          <field>
            <name>DLYM1L</name>
            <bitOffset>0</bitOffset>
            <bitWidth>3</bitWidth>
          </field>
          <field>
            <name>DLYM1R</name>
            <bitOffset>4</bitOffset>
            <bitWidth>3</bitWidth>
          </field>
          <field>
            <name>DLYM2L</name>
            <bitOffset>8</bitOffset>
            <bitWidth>3</bitWidth>
          </field>
          <field>
            <name>DLYM2R</name>
            <bitOffset>12</bitOffset>
            <bitWidth>3</bitWidth>
          </field>
          <field>
            <name>DLYM3L</name>
            <bitOffset>16</bitOffset>
            <bitWidth>3</bitWidth>
          </field>
          <field>
            <name>DLYM3R</name>
            <bitOffset>20</bitOffset>
            <bitWidth>3</bitWidth>
          </field>
          <field>
            <name>DLYM4L</name>
            <bitOffset>24</bitOffset>
            <bitWidth>3</bitWidth>
          </field>
          <field>
            <name>DLYM4R</name>
            <bitOffset>28</bitOffset>
            <bitWidth>3</bitWidth>
          </field>
        </fields>
      </register>
      <register>
        <name>IMRB</name>
        <addressOffset>0x4c</addressOffset>
        <size>0x20</size>
      </register>
      <register>
        <name>IMRB</name>
        <addressOffset>0x4c</addressOffset>
        <size>0x20</size>
      </register>
      <register>
        <name>CLRFRA</name>
        <addressOffset>0x58</addressOffset>
        <size>0x20</size>
      </register>
      <register>
        <name>CLRFRA</name>
        <addressOffset>0x58</addressOffset>
        <size>0x20</size>
      </register>
      <register>
        <name>SRB</name>
        <addressOffset>0x60</addressOffset>
        <size>0x20</size>
      </register>
      <register>
        <name>SRB</name>
        <addressOffset>0x60</addressOffset>
        <size>0x20</size>
      </register>
      <register>
        <name>DRA</name>
        <addressOffset>0x74</addressOffset>
        <size>0x20</size>
      </register>
      <register>
        <name>DRA</name>
        <addressOffset>0x74</addressOffset>
        <size>0x20</size>
      </register>
      <register>
        <name>CLRFRB</name>
        <addressOffset>0x78</addressOffset>
        <size>0x20</size>
      </register>
      <register>
        <name>CLRFRB</name>
        <addressOffset>0x78</addressOffset>
        <size>0x20</size>
      </register>
      <register>
        <name>DRB</name>
        <addressOffset>0x94</addressOffset>
        <size>0x20</size>
      </register>
      <register>
        <name>DRB</name>
        <addressOffset>0x94</addressOffset>
        <size>0x20</size>
      </register>
    </peripheral>
    <peripheral>
      <name>DFSDM1</name>
      <baseAddress>0x40016000</baseAddress>
      <register>
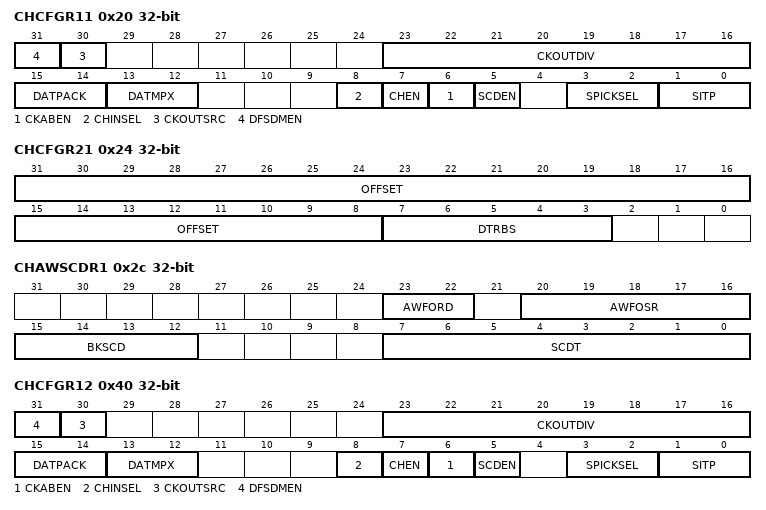
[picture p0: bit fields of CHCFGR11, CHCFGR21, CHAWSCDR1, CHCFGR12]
        <name>CHCFGR11</name>
        <addressOffset>0x20</addressOffset>
        <size>0x20</size>
        <fields>
          <field>
            <name>SITP</name>
            <bitOffset>0</bitOffset>
            <bitWidth>2</bitWidth>
          </field>
          <field>
            <name>SPICKSEL</name>
            <bitOffset>2</bitOffset>
            <bitWidth>2</bitWidth>
          </field>
          <field>
            <name>SCDEN</name>
            <bitOffset>5</bitOffset>
            <bitWidth>1</bitWidth>
          </field>
          <field>
            <name>CKABEN</name>
            <bitOffset>6</bitOffset>
            <bitWidth>1</bitWidth>
          </field>
          <field>
            <name>CHEN</name>
            <bitOffset>7</bitOffset>
            <bitWidth>1</bitWidth>
          </field>
          <field>
            <name>CHINSEL</name>
            <bitOffset>8</bitOffset>
            <bitWidth>1</bitWidth>
          </field>
          <field>
            <name>DATMPX</name>
            <bitOffset>12</bitOffset>
            <bitWidth>2</bitWidth>
          </field>
          <field>
            <name>DATPACK</name>
            <bitOffset>14</bitOffset>
            <bitWidth>2</bitWidth>
          </field>
          <field>
            <name>CKOUTDIV</name>
            <bitOffset>16</bitOffset>
            <bitWidth>8</bitWidth>
          </field>
          <field>
            <name>CKOUTSRC</name>
            <bitOffset>30</bitOffset>
            <bitWidth>1</bitWidth>
          </field>
          <field>
            <name>DFSDMEN</name>
            <bitOffset>31</bitOffset>
            <bitWidth>1</bitWidth>
          </field>
        </fields>
      </register>
      <register>
        <name>CHCFGR21</name>
        <addressOffset>0x24</addressOffset>
        <size>0x20</size>
        <fields>
          <field>
            <name>DTRBS</name>
            <bitOffset>3</bitOffset>
            <bitWidth>5</bitWidth>
          </field>
          <field>
            <name>OFFSET</name>
            <bitOffset>8</bitOffset>
            <bitWidth>24</bitWidth>
          </field>
        </fields>
      </register>
      <register>
        <name>CHAWSCDR1</name>
        <addressOffset>0x2c</addressOffset>
        <size>0x20</size>
        <fields>
          <field>
            <name>SCDT</name>
            <bitOffset>0</bitOffset>
            <bitWidth>8</bitWidth>
          </field>
          <field>
            <name>BKSCD</name>
            <bitOffset>12</bitOffset>
            <bitWidth>4</bitWidth>
          </field>
          <field>
            <name>AWFOSR</name>
            <bitOffset>16</bitOffset>
            <bitWidth>5</bitWidth>
          </field>
          <field>
            <name>AWFORD</name>
            <bitOffset>22</bitOffset>
            <bitWidth>2</bitWidth>
          </field>
        </fields>
      </register>
      <register>
        <name>CHWDATAR1</name>
        <addressOffset>0x38</addressOffset>
        <size>0x20</size>
      </register>
      <register>
        <name>CHCFGR12</name>
        <addressOffset>0x40</addressOffset>
        <size>0x20</size>
        <fields>
          <field>
            <name>SITP</name>
            <bitOffset>0</bitOffset>
            <bitWidth>2</bitWidth>
          </field>
          <field>
            <name>SPICKSEL</name>
            <bitOffset>2</bitOffset>
            <bitWidth>2</bitWidth>
          </field>
          <field>
            <name>SCDEN</name>
            <bitOffset>5</bitOffset>
            <bitWidth>1</bitWidth>
          </field>
          <field>
            <name>CKABEN</name>
            <bitOffset>6</bitOffset>
            <bitWidth>1</bitWidth>
          </field>
          <field>
            <name>CHEN</name>
            <bitOffset>7</bitOffset>
            <bitWidth>1</bitWidth>
          </field>
          <field>
            <name>CHINSEL</name>
            <bitOffset>8</bitOffset>
            <bitWidth>1</bitWidth>
          </field>
          <field>
            <name>DATMPX</name>
            <bitOffset>12</bitOffset>
            <bitWidth>2</bitWidth>
          </field>
          <field>
            <name>DATPACK</name>
            <bitOffset>14</bitOffset>
            <bitWidth>2</bitWidth>
          </field>
          <field>
            <name>CKOUTDIV</name>
            <bitOffset>16</bitOffset>
            <bitWidth>8</bitWidth>
          </field>
          <field>
            <name>CKOUTSRC</name>
            <bitOffset>30</bitOffset>
            <bitWidth>1</bitWidth>
          </field>
          <field>
            <name>DFSDMEN</name>
            <bitOffset>31</bitOffset>
            <bitWidth>1</bitWidth>
          </field>
        </fields>
      </register>
      <register>
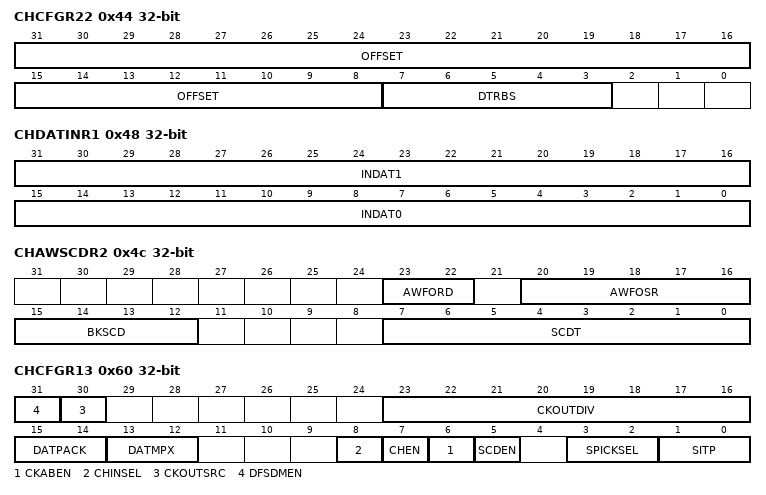
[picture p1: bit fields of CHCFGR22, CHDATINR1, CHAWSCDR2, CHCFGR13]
        <name>CHCFGR22</name>
        <addressOffset>0x44</addressOffset>
        <size>0x20</size>
        <fields>
          <field>
            <name>DTRBS</name>
            <bitOffset>3</bitOffset>
            <bitWidth>5</bitWidth>
          </field>
          <field>
            <name>OFFSET</name>
            <bitOffset>8</bitOffset>
            <bitWidth>24</bitWidth>
          </field>
        </fields>
      </register>
      <register>
        <name>CHDATINR1</name>
        <addressOffset>0x48</addressOffset>
        <size>0x20</size>
        <fields>
          <field>
            <name>INDAT0</name>
            <bitOffset>0</bitOffset>
            <bitWidth>16</bitWidth>
          </field>
          <field>
            <name>INDAT1</name>
            <bitOffset>16</bitOffset>
            <bitWidth>16</bitWidth>
          </field>
        </fields>
      </register>
      <register>
        <name>CHAWSCDR2</name>
        <addressOffset>0x4c</addressOffset>
        <size>0x20</size>
        <fields>
          <field>
            <name>SCDT</name>
            <bitOffset>0</bitOffset>
            <bitWidth>8</bitWidth>
          </field>
          <field>
            <name>BKSCD</name>
            <bitOffset>12</bitOffset>
            <bitWidth>4</bitWidth>
          </field>
          <field>
            <name>AWFOSR</name>
            <bitOffset>16</bitOffset>
            <bitWidth>5</bitWidth>
          </field>
          <field>
            <name>AWFORD</name>
            <bitOffset>22</bitOffset>
            <bitWidth>2</bitWidth>
          </field>
        </fields>
      </register>
      <register>
        <name>CHWDATAR2</name>
        <addressOffset>0x58</addressOffset>
        <size>0x20</size>
      </register>
      <register>
        <name>CHDLYR1</name>
        <addressOffset>0x5c</addressOffset>
        <size>0x20</size>
        <fields>
          <field>
            <name>PLSSKP</name>
            <bitOffset>0</bitOffset>
            <bitWidth>6</bitWidth>
          </field>
        </fields>
      </register>
      <register>
        <name>CHCFGR13</name>
        <addressOffset>0x60</addressOffset>
        <size>0x20</size>
        <fields>
          <field>
            <name>SITP</name>
            <bitOffset>0</bitOffset>
            <bitWidth>2</bitWidth>
          </field>
          <field>
            <name>SPICKSEL</name>
            <bitOffset>2</bitOffset>
            <bitWidth>2</bitWidth>
          </field>
          <field>
            <name>SCDEN</name>
            <bitOffset>5</bitOffset>
            <bitWidth>1</bitWidth>
          </field>
          <field>
            <name>CKABEN</name>
            <bitOffset>6</bitOffset>
            <bitWidth>1</bitWidth>
          </field>
          <field>
            <name>CHEN</name>
            <bitOffset>7</bitOffset>
            <bitWidth>1</bitWidth>
          </field>
          <field>
            <name>CHINSEL</name>
            <bitOffset>8</bitOffset>
            <bitWidth>1</bitWidth>
          </field>
          <field>
            <name>DATMPX</name>
            <bitOffset>12</bitOffset>
            <bitWidth>2</bitWidth>
          </field>
          <field>
            <name>DATPACK</name>
            <bitOffset>14</bitOffset>
            <bitWidth>2</bitWidth>
          </field>
          <field>
            <name>CKOUTDIV</name>
            <bitOffset>16</bitOffset>
            <bitWidth>8</bitWidth>
          </field>
          <field>
            <name>CKOUTSRC</name>
            <bitOffset>30</bitOffset>
            <bitWidth>1</bitWidth>
          </field>
          <field>
            <name>DFSDMEN</name>
            <bitOffset>31</bitOffset>
            <bitWidth>1</bitWidth>
          </field>
        </fields>
      </register>
      <register>
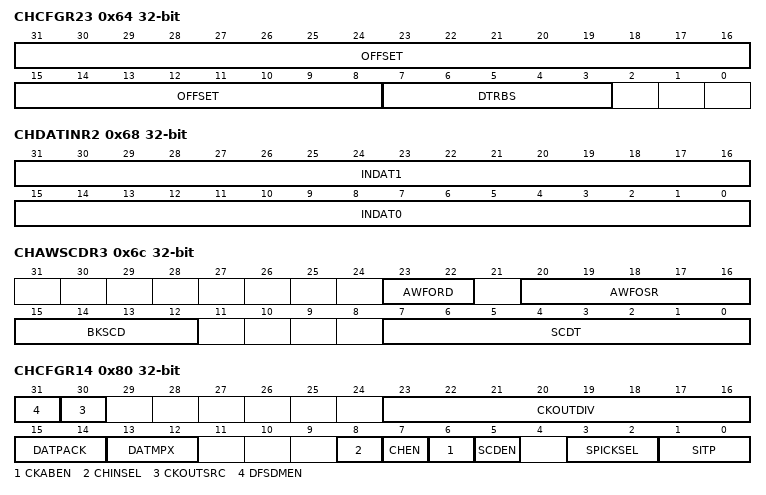
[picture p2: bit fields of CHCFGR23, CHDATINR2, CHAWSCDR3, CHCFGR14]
        <name>CHCFGR23</name>
        <addressOffset>0x64</addressOffset>
        <size>0x20</size>
        <fields>
          <field>
            <name>DTRBS</name>
            <bitOffset>3</bitOffset>
            <bitWidth>5</bitWidth>
          </field>
          <field>
            <name>OFFSET</name>
            <bitOffset>8</bitOffset>
            <bitWidth>24</bitWidth>
          </field>
        </fields>
      </register>
      <register>
        <name>CHDATINR2</name>
        <addressOffset>0x68</addressOffset>
        <size>0x20</size>
        <fields>
          <field>
            <name>INDAT0</name>
            <bitOffset>0</bitOffset>
            <bitWidth>16</bitWidth>
          </field>
          <field>
            <name>INDAT1</name>
            <bitOffset>16</bitOffset>
            <bitWidth>16</bitWidth>
          </field>
        </fields>
      </register>
      <register>
        <name>CHAWSCDR3</name>
        <addressOffset>0x6c</addressOffset>
        <size>0x20</size>
        <fields>
          <field>
            <name>SCDT</name>
            <bitOffset>0</bitOffset>
            <bitWidth>8</bitWidth>
          </field>
          <field>
            <name>BKSCD</name>
            <bitOffset>12</bitOffset>
            <bitWidth>4</bitWidth>
          </field>
          <field>
            <name>AWFOSR</name>
            <bitOffset>16</bitOffset>
            <bitWidth>5</bitWidth>
          </field>
          <field>
            <name>AWFORD</name>
            <bitOffset>22</bitOffset>
            <bitWidth>2</bitWidth>
          </field>
        </fields>
      </register>
      <register>
        <name>CHWDATAR3</name>
        <addressOffset>0x78</addressOffset>
        <size>0x20</size>
      </register>
      <register>
        <name>CHDLYR2</name>
        <addressOffset>0x7c</addressOffset>
        <size>0x20</size>
        <fields>
          <field>
            <name>PLSSKP</name>
            <bitOffset>0</bitOffset>
            <bitWidth>6</bitWidth>
          </field>
        </fields>
      </register>
      <register>
        <name>CHCFGR14</name>
        <addressOffset>0x80</addressOffset>
        <size>0x20</size>
        <fields>
          <field>
            <name>SITP</name>
            <bitOffset>0</bitOffset>
            <bitWidth>2</bitWidth>
          </field>
          <field>
            <name>SPICKSEL</name>
            <bitOffset>2</bitOffset>
            <bitWidth>2</bitWidth>
          </field>
          <field>
            <name>SCDEN</name>
            <bitOffset>5</bitOffset>
            <bitWidth>1</bitWidth>
          </field>
          <field>
            <name>CKABEN</name>
            <bitOffset>6</bitOffset>
            <bitWidth>1</bitWidth>
          </field>
          <field>
            <name>CHEN</name>
            <bitOffset>7</bitOffset>
            <bitWidth>1</bitWidth>
          </field>
          <field>
            <name>CHINSEL</name>
            <bitOffset>8</bitOffset>
            <bitWidth>1</bitWidth>
          </field>
          <field>
            <name>DATMPX</name>
            <bitOffset>12</bitOffset>
            <bitWidth>2</bitWidth>
          </field>
          <field>
            <name>DATPACK</name>
            <bitOffset>14</bitOffset>
            <bitWidth>2</bitWidth>
          </field>
          <field>
            <name>CKOUTDIV</name>
            <bitOffset>16</bitOffset>
            <bitWidth>8</bitWidth>
          </field>
          <field>
            <name>CKOUTSRC</name>
            <bitOffset>30</bitOffset>
            <bitWidth>1</bitWidth>
          </field>
          <field>
            <name>DFSDMEN</name>
            <bitOffset>31</bitOffset>
            <bitWidth>1</bitWidth>
          </field>
        </fields>
      </register>
      <register>
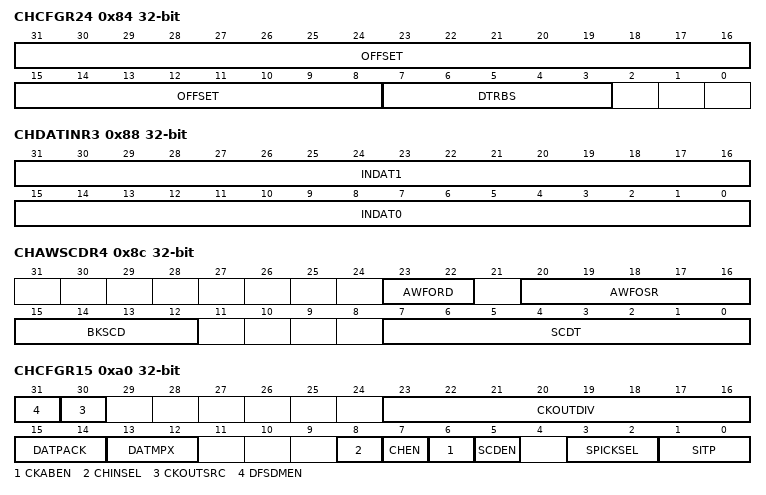
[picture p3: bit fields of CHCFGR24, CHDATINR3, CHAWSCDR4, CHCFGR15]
        <name>CHCFGR24</name>
        <addressOffset>0x84</addressOffset>
        <size>0x20</size>
        <fields>
          <field>
            <name>DTRBS</name>
            <bitOffset>3</bitOffset>
            <bitWidth>5</bitWidth>
          </field>
          <field>
            <name>OFFSET</name>
            <bitOffset>8</bitOffset>
            <bitWidth>24</bitWidth>
          </field>
        </fields>
      </register>
      <register>
        <name>CHDATINR3</name>
        <addressOffset>0x88</addressOffset>
        <size>0x20</size>
        <fields>
          <field>
            <name>INDAT0</name>
            <bitOffset>0</bitOffset>
            <bitWidth>16</bitWidth>
          </field>
          <field>
            <name>INDAT1</name>
            <bitOffset>16</bitOffset>
            <bitWidth>16</bitWidth>
          </field>
        </fields>
      </register>
      <register>
        <name>CHAWSCDR4</name>
        <addressOffset>0x8c</addressOffset>
        <size>0x20</size>
        <fields>
          <field>
            <name>SCDT</name>
            <bitOffset>0</bitOffset>
            <bitWidth>8</bitWidth>
          </field>
          <field>
            <name>BKSCD</name>
            <bitOffset>12</bitOffset>
            <bitWidth>4</bitWidth>
          </field>
          <field>
            <name>AWFOSR</name>
            <bitOffset>16</bitOffset>
            <bitWidth>5</bitWidth>
          </field>
          <field>
            <name>AWFORD</name>
            <bitOffset>22</bitOffset>
            <bitWidth>2</bitWidth>
          </field>
        </fields>
      </register>
      <register>
        <name>CHWDATAR4</name>
        <addressOffset>0x98</addressOffset>
        <size>0x20</size>
      </register>
      <register>
        <name>CHDLYR3</name>
        <addressOffset>0x9c</addressOffset>
        <size>0x20</size>
        <fields>
          <field>
            <name>PLSSKP</name>
            <bitOffset>0</bitOffset>
            <bitWidth>6</bitWidth>
          </field>
        </fields>
      </register>
      <register>
        <name>CHCFGR15</name>
        <addressOffset>0xa0</addressOffset>
        <size>0x20</size>
        <fields>
          <field>
            <name>SITP</name>
            <bitOffset>0</bitOffset>
            <bitWidth>2</bitWidth>
          </field>
          <field>
            <name>SPICKSEL</name>
            <bitOffset>2</bitOffset>
            <bitWidth>2</bitWidth>
          </field>
          <field>
            <name>SCDEN</name>
            <bitOffset>5</bitOffset>
            <bitWidth>1</bitWidth>
          </field>
          <field>
            <name>CKABEN</name>
            <bitOffset>6</bitOffset>
            <bitWidth>1</bitWidth>
          </field>
          <field>
            <name>CHEN</name>
            <bitOffset>7</bitOffset>
            <bitWidth>1</bitWidth>
          </field>
          <field>
            <name>CHINSEL</name>
            <bitOffset>8</bitOffset>
            <bitWidth>1</bitWidth>
          </field>
          <field>
            <name>DATMPX</name>
            <bitOffset>12</bitOffset>
            <bitWidth>2</bitWidth>
          </field>
          <field>
            <name>DATPACK</name>
            <bitOffset>14</bitOffset>
            <bitWidth>2</bitWidth>
          </field>
          <field>
            <name>CKOUTDIV</name>
            <bitOffset>16</bitOffset>
            <bitWidth>8</bitWidth>
          </field>
          <field>
            <name>CKOUTSRC</name>
            <bitOffset>30</bitOffset>
            <bitWidth>1</bitWidth>
          </field>
          <field>
            <name>DFSDMEN</name>
            <bitOffset>31</bitOffset>
            <bitWidth>1</bitWidth>
          </field>
        </fields>
      </register>
      <register>
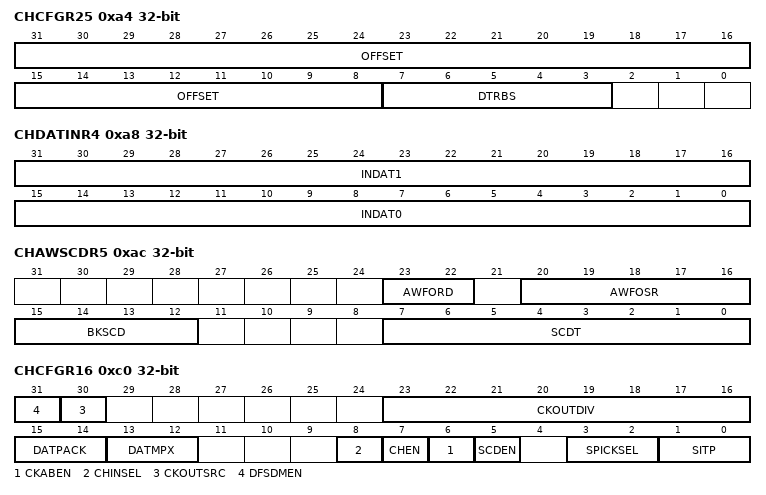
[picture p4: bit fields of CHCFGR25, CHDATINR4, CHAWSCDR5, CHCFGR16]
        <name>CHCFGR25</name>
        <addressOffset>0xa4</addressOffset>
        <size>0x20</size>
        <fields>
          <field>
            <name>DTRBS</name>
            <bitOffset>3</bitOffset>
            <bitWidth>5</bitWidth>
          </field>
          <field>
            <name>OFFSET</name>
            <bitOffset>8</bitOffset>
            <bitWidth>24</bitWidth>
          </field>
        </fields>
      </register>
      <register>
        <name>CHDATINR4</name>
        <addressOffset>0xa8</addressOffset>
        <size>0x20</size>
        <fields>
          <field>
            <name>INDAT0</name>
            <bitOffset>0</bitOffset>
            <bitWidth>16</bitWidth>
          </field>
          <field>
            <name>INDAT1</name>
            <bitOffset>16</bitOffset>
            <bitWidth>16</bitWidth>
          </field>
        </fields>
      </register>
      <register>
        <name>CHAWSCDR5</name>
        <addressOffset>0xac</addressOffset>
        <size>0x20</size>
        <fields>
          <field>
            <name>SCDT</name>
            <bitOffset>0</bitOffset>
            <bitWidth>8</bitWidth>
          </field>
          <field>
            <name>BKSCD</name>
            <bitOffset>12</bitOffset>
            <bitWidth>4</bitWidth>
          </field>
          <field>
            <name>AWFOSR</name>
            <bitOffset>16</bitOffset>
            <bitWidth>5</bitWidth>
          </field>
          <field>
            <name>AWFORD</name>
            <bitOffset>22</bitOffset>
            <bitWidth>2</bitWidth>
          </field>
        </fields>
      </register>
      <register>
        <name>CHWDATAR5</name>
        <addressOffset>0xb8</addressOffset>
        <size>0x20</size>
      </register>
      <register>
        <name>CHDLYR4</name>
        <addressOffset>0xbc</addressOffset>
        <size>0x20</size>
        <fields>
          <field>
            <name>PLSSKP</name>
            <bitOffset>0</bitOffset>
            <bitWidth>6</bitWidth>
          </field>
        </fields>
      </register>
      <register>
        <name>CHCFGR16</name>
        <addressOffset>0xc0</addressOffset>
        <size>0x20</size>
        <fields>
          <field>
            <name>SITP</name>
            <bitOffset>0</bitOffset>
            <bitWidth>2</bitWidth>
          </field>
          <field>
            <name>SPICKSEL</name>
            <bitOffset>2</bitOffset>
            <bitWidth>2</bitWidth>
          </field>
          <field>
            <name>SCDEN</name>
            <bitOffset>5</bitOffset>
            <bitWidth>1</bitWidth>
          </field>
          <field>
            <name>CKABEN</name>
            <bitOffset>6</bitOffset>
            <bitWidth>1</bitWidth>
          </field>
          <field>
            <name>CHEN</name>
            <bitOffset>7</bitOffset>
            <bitWidth>1</bitWidth>
          </field>
          <field>
            <name>CHINSEL</name>
            <bitOffset>8</bitOffset>
            <bitWidth>1</bitWidth>
          </field>
          <field>
            <name>DATMPX</name>
            <bitOffset>12</bitOffset>
            <bitWidth>2</bitWidth>
          </field>
          <field>
            <name>DATPACK</name>
            <bitOffset>14</bitOffset>
            <bitWidth>2</bitWidth>
          </field>
          <field>
            <name>CKOUTDIV</name>
            <bitOffset>16</bitOffset>
            <bitWidth>8</bitWidth>
          </field>
          <field>
            <name>CKOUTSRC</name>
            <bitOffset>30</bitOffset>
            <bitWidth>1</bitWidth>
          </field>
          <field>
            <name>DFSDMEN</name>
            <bitOffset>31</bitOffset>
            <bitWidth>1</bitWidth>
          </field>
        </fields>
      </register>
      <register>
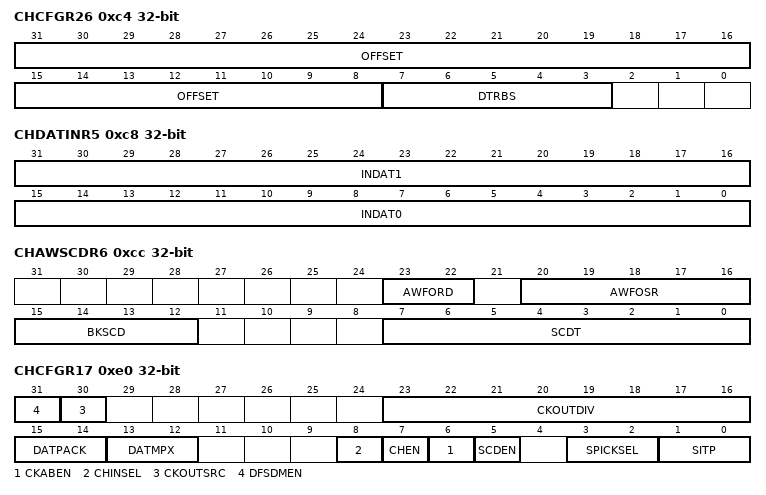
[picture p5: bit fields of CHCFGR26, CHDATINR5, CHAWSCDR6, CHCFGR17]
        <name>CHCFGR26</name>
        <addressOffset>0xc4</addressOffset>
        <size>0x20</size>
        <fields>
          <field>
            <name>DTRBS</name>
            <bitOffset>3</bitOffset>
            <bitWidth>5</bitWidth>
          </field>
          <field>
            <name>OFFSET</name>
            <bitOffset>8</bitOffset>
            <bitWidth>24</bitWidth>
          </field>
        </fields>
      </register>
      <register>
        <name>CHDATINR5</name>
        <addressOffset>0xc8</addressOffset>
        <size>0x20</size>
        <fields>
          <field>
            <name>INDAT0</name>
            <bitOffset>0</bitOffset>
            <bitWidth>16</bitWidth>
          </field>
          <field>
            <name>INDAT1</name>
            <bitOffset>16</bitOffset>
            <bitWidth>16</bitWidth>
          </field>
        </fields>
      </register>
      <register>
        <name>CHAWSCDR6</name>
        <addressOffset>0xcc</addressOffset>
        <size>0x20</size>
        <fields>
          <field>
            <name>SCDT</name>
            <bitOffset>0</bitOffset>
            <bitWidth>8</bitWidth>
          </field>
          <field>
            <name>BKSCD</name>
            <bitOffset>12</bitOffset>
            <bitWidth>4</bitWidth>
          </field>
          <field>
            <name>AWFOSR</name>
            <bitOffset>16</bitOffset>
            <bitWidth>5</bitWidth>
          </field>
          <field>
            <name>AWFORD</name>
            <bitOffset>22</bitOffset>
            <bitWidth>2</bitWidth>
          </field>
        </fields>
      </register>
      <register>
        <name>CHWDATAR6</name>
        <addressOffset>0xd8</addressOffset>
        <size>0x20</size>
      </register>
      <register>
        <name>CHDLYR5</name>
        <addressOffset>0xdc</addressOffset>
        <size>0x20</size>
        <fields>
          <field>
            <name>PLSSKP</name>
            <bitOffset>0</bitOffset>
            <bitWidth>6</bitWidth>
          </field>
        </fields>
      </register>
      <register>
        <name>CHCFGR17</name>
        <addressOffset>0xe0</addressOffset>
        <size>0x20</size>
        <fields>
          <field>
            <name>SITP</name>
            <bitOffset>0</bitOffset>
            <bitWidth>2</bitWidth>
          </field>
          <field>
            <name>SPICKSEL</name>
            <bitOffset>2</bitOffset>
            <bitWidth>2</bitWidth>
          </field>
          <field>
            <name>SCDEN</name>
            <bitOffset>5</bitOffset>
            <bitWidth>1</bitWidth>
          </field>
          <field>
            <name>CKABEN</name>
            <bitOffset>6</bitOffset>
            <bitWidth>1</bitWidth>
          </field>
          <field>
            <name>CHEN</name>
            <bitOffset>7</bitOffset>
            <bitWidth>1</bitWidth>
          </field>
          <field>
            <name>CHINSEL</name>
            <bitOffset>8</bitOffset>
            <bitWidth>1</bitWidth>
          </field>
          <field>
            <name>DATMPX</name>
            <bitOffset>12</bitOffset>
            <bitWidth>2</bitWidth>
          </field>
          <field>
            <name>DATPACK</name>
            <bitOffset>14</bitOffset>
            <bitWidth>2</bitWidth>
          </field>
          <field>
            <name>CKOUTDIV</name>
            <bitOffset>16</bitOffset>
            <bitWidth>8</bitWidth>
          </field>
          <field>
            <name>CKOUTSRC</name>
            <bitOffset>30</bitOffset>
            <bitWidth>1</bitWidth>
          </field>
          <field>
            <name>DFSDMEN</name>
            <bitOffset>31</bitOffset>
            <bitWidth>1</bitWidth>
          </field>
        </fields>
      </register>
      <register>
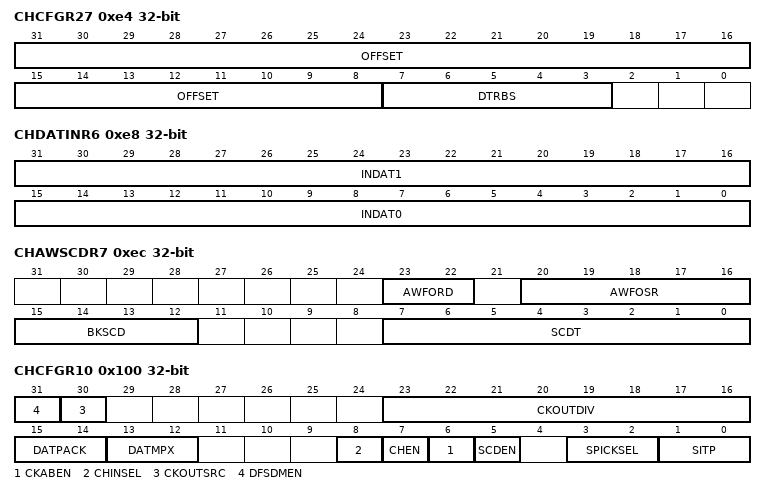
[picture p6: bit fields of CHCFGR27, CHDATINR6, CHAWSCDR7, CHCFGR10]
        <name>CHCFGR27</name>
        <addressOffset>0xe4</addressOffset>
        <size>0x20</size>
        <fields>
          <field>
            <name>DTRBS</name>
            <bitOffset>3</bitOffset>
            <bitWidth>5</bitWidth>
          </field>
          <field>
            <name>OFFSET</name>
            <bitOffset>8</bitOffset>
            <bitWidth>24</bitWidth>
          </field>
        </fields>
      </register>
      <register>
        <name>CHDATINR6</name>
        <addressOffset>0xe8</addressOffset>
        <size>0x20</size>
        <fields>
          <field>
            <name>INDAT0</name>
            <bitOffset>0</bitOffset>
            <bitWidth>16</bitWidth>
          </field>
          <field>
            <name>INDAT1</name>
            <bitOffset>16</bitOffset>
            <bitWidth>16</bitWidth>
          </field>
        </fields>
      </register>
      <register>
        <name>CHAWSCDR7</name>
        <addressOffset>0xec</addressOffset>
        <size>0x20</size>
        <fields>
          <field>
            <name>SCDT</name>
            <bitOffset>0</bitOffset>
            <bitWidth>8</bitWidth>
          </field>
          <field>
            <name>BKSCD</name>
            <bitOffset>12</bitOffset>
            <bitWidth>4</bitWidth>
          </field>
          <field>
            <name>AWFOSR</name>
            <bitOffset>16</bitOffset>
            <bitWidth>5</bitWidth>
          </field>
          <field>
            <name>AWFORD</name>
            <bitOffset>22</bitOffset>
            <bitWidth>2</bitWidth>
          </field>
        </fields>
      </register>
      <register>
        <name>CHWDATAR7</name>
        <addressOffset>0xf8</addressOffset>
        <size>0x20</size>
      </register>
      <register>
        <name>CHDLYR6</name>
        <addressOffset>0xfc</addressOffset>
        <size>0x20</size>
        <fields>
          <field>
            <name>PLSSKP</name>
            <bitOffset>0</bitOffset>
            <bitWidth>6</bitWidth>
          </field>
        </fields>
      </register>
      <register>
        <name>CHCFGR10</name>
        <addressOffset>0x100</addressOffset>
        <size>0x20</size>
        <fields>
          <field>
            <name>SITP</name>
            <bitOffset>0</bitOffset>
            <bitWidth>2</bitWidth>
          </field>
          <field>
            <name>SPICKSEL</name>
            <bitOffset>2</bitOffset>
            <bitWidth>2</bitWidth>
          </field>
          <field>
            <name>SCDEN</name>
            <bitOffset>5</bitOffset>
            <bitWidth>1</bitWidth>
          </field>
          <field>
            <name>CKABEN</name>
            <bitOffset>6</bitOffset>
            <bitWidth>1</bitWidth>
          </field>
          <field>
            <name>CHEN</name>
            <bitOffset>7</bitOffset>
            <bitWidth>1</bitWidth>
          </field>
          <field>
            <name>CHINSEL</name>
            <bitOffset>8</bitOffset>
            <bitWidth>1</bitWidth>
          </field>
          <field>
            <name>DATMPX</name>
            <bitOffset>12</bitOffset>
            <bitWidth>2</bitWidth>
          </field>
          <field>
            <name>DATPACK</name>
            <bitOffset>14</bitOffset>
            <bitWidth>2</bitWidth>
          </field>
          <field>
            <name>CKOUTDIV</name>
            <bitOffset>16</bitOffset>
            <bitWidth>8</bitWidth>
          </field>
          <field>
            <name>CKOUTSRC</name>
            <bitOffset>30</bitOffset>
            <bitWidth>1</bitWidth>
          </field>
          <field>
            <name>DFSDMEN</name>
            <bitOffset>31</bitOffset>
            <bitWidth>1</bitWidth>
          </field>
        </fields>
      </register>
      <register>
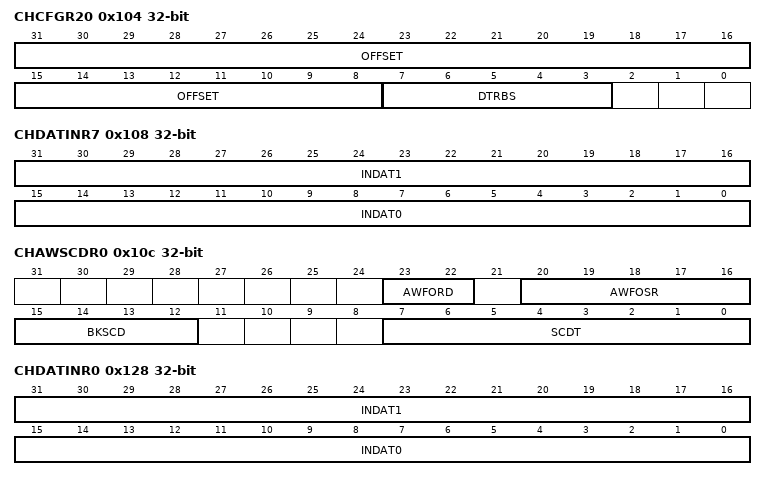
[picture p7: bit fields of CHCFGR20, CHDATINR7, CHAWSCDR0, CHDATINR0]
        <name>CHCFGR20</name>
        <addressOffset>0x104</addressOffset>
        <size>0x20</size>
        <fields>
          <field>
            <name>DTRBS</name>
            <bitOffset>3</bitOffset>
            <bitWidth>5</bitWidth>
          </field>
          <field>
            <name>OFFSET</name>
            <bitOffset>8</bitOffset>
            <bitWidth>24</bitWidth>
          </field>
        </fields>
      </register>
      <register>
        <name>CHDATINR7</name>
        <addressOffset>0x108</addressOffset>
        <size>0x20</size>
        <fields>
          <field>
            <name>INDAT0</name>
            <bitOffset>0</bitOffset>
            <bitWidth>16</bitWidth>
          </field>
          <field>
            <name>INDAT1</name>
            <bitOffset>16</bitOffset>
            <bitWidth>16</bitWidth>
          </field>
        </fields>
      </register>
      <register>
        <name>CHAWSCDR0</name>
        <addressOffset>0x10c</addressOffset>
        <size>0x20</size>
        <fields>
          <field>
            <name>SCDT</name>
            <bitOffset>0</bitOffset>
            <bitWidth>8</bitWidth>
          </field>
          <field>
            <name>BKSCD</name>
            <bitOffset>12</bitOffset>
            <bitWidth>4</bitWidth>
          </field>
          <field>
            <name>AWFOSR</name>
            <bitOffset>16</bitOffset>
            <bitWidth>5</bitWidth>
          </field>
          <field>
            <name>AWFORD</name>
            <bitOffset>22</bitOffset>
            <bitWidth>2</bitWidth>
          </field>
        </fields>
      </register>
      <register>
        <name>CHWDATAR0</name>
        <addressOffset>0x118</addressOffset>
        <size>0x20</size>
      </register>
      <register>
        <name>CHDLYR7</name>
        <addressOffset>0x11c</addressOffset>
        <size>0x20</size>
        <fields>
          <field>
            <name>PLSSKP</name>
            <bitOffset>0</bitOffset>
            <bitWidth>6</bitWidth>
          </field>
        </fields>
      </register>
      <register>
        <name>CHDATINR0</name>
        <addressOffset>0x128</addressOffset>
        <size>0x20</size>
        <fields>
          <field>
            <name>INDAT0</name>
            <bitOffset>0</bitOffset>
            <bitWidth>16</bitWidth>
          </field>
          <field>
            <name>INDAT1</name>
            <bitOffset>16</bitOffset>
            <bitWidth>16</bitWidth>
          </field>
        </fields>
      </register>
      <register>
        <name>CHDLYR0</name>
        <addressOffset>0x13c</addressOffset>
        <size>0x20</size>
        <fields>
          <field>
            <name>PLSSKP</name>
            <bitOffset>0</bitOffset>
            <bitWidth>6</bitWidth>
          </field>
        </fields>
      </register>
      <register>
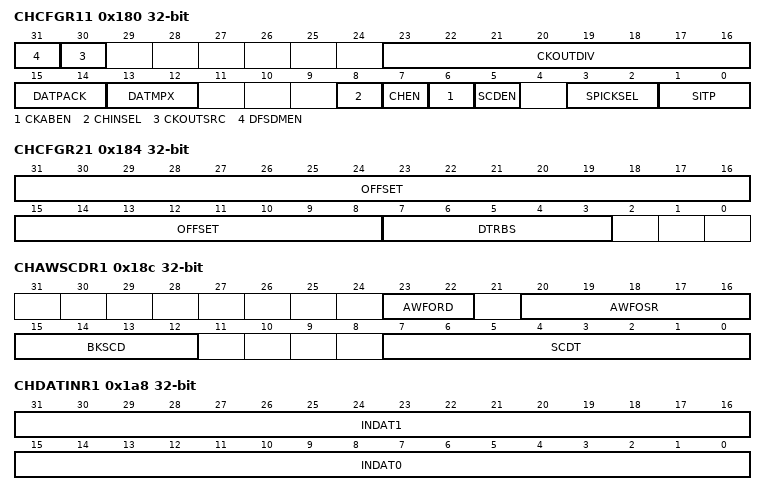
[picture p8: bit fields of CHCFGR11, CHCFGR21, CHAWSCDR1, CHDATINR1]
        <name>CHCFGR11</name>
        <addressOffset>0x180</addressOffset>
        <size>0x20</size>
        <fields>
          <field>
            <name>SITP</name>
            <bitOffset>0</bitOffset>
            <bitWidth>2</bitWidth>
          </field>
          <field>
            <name>SPICKSEL</name>
            <bitOffset>2</bitOffset>
            <bitWidth>2</bitWidth>
          </field>
          <field>
            <name>SCDEN</name>
            <bitOffset>5</bitOffset>
            <bitWidth>1</bitWidth>
          </field>
          <field>
            <name>CKABEN</name>
            <bitOffset>6</bitOffset>
            <bitWidth>1</bitWidth>
          </field>
          <field>
            <name>CHEN</name>
            <bitOffset>7</bitOffset>
            <bitWidth>1</bitWidth>
          </field>
          <field>
            <name>CHINSEL</name>
            <bitOffset>8</bitOffset>
            <bitWidth>1</bitWidth>
          </field>
          <field>
            <name>DATMPX</name>
            <bitOffset>12</bitOffset>
            <bitWidth>2</bitWidth>
          </field>
          <field>
            <name>DATPACK</name>
            <bitOffset>14</bitOffset>
            <bitWidth>2</bitWidth>
          </field>
          <field>
            <name>CKOUTDIV</name>
            <bitOffset>16</bitOffset>
            <bitWidth>8</bitWidth>
          </field>
          <field>
            <name>CKOUTSRC</name>
            <bitOffset>30</bitOffset>
            <bitWidth>1</bitWidth>
          </field>
          <field>
            <name>DFSDMEN</name>
            <bitOffset>31</bitOffset>
            <bitWidth>1</bitWidth>
          </field>
        </fields>
      </register>
      <register>
        <name>CHCFGR21</name>
        <addressOffset>0x184</addressOffset>
        <size>0x20</size>
        <fields>
          <field>
            <name>DTRBS</name>
            <bitOffset>3</bitOffset>
            <bitWidth>5</bitWidth>
          </field>
          <field>
            <name>OFFSET</name>
            <bitOffset>8</bitOffset>
            <bitWidth>24</bitWidth>
          </field>
        </fields>
      </register>
      <register>
        <name>CHAWSCDR1</name>
        <addressOffset>0x18c</addressOffset>
        <size>0x20</size>
        <fields>
          <field>
            <name>SCDT</name>
            <bitOffset>0</bitOffset>
            <bitWidth>8</bitWidth>
          </field>
          <field>
            <name>BKSCD</name>
            <bitOffset>12</bitOffset>
            <bitWidth>4</bitWidth>
          </field>
          <field>
            <name>AWFOSR</name>
            <bitOffset>16</bitOffset>
            <bitWidth>5</bitWidth>
          </field>
          <field>
            <name>AWFORD</name>
            <bitOffset>22</bitOffset>
            <bitWidth>2</bitWidth>
          </field>
        </fields>
      </register>
      <register>
        <name>CHWDATAR1</name>
        <addressOffset>0x198</addressOffset>
        <size>0x20</size>
      </register>
      <register>
        <name>CHDATINR1</name>
        <addressOffset>0x1a8</addressOffset>
        <size>0x20</size>
        <fields>
          <field>
            <name>INDAT0</name>
            <bitOffset>0</bitOffset>
            <bitWidth>16</bitWidth>
          </field>
          <field>
            <name>INDAT1</name>
            <bitOffset>16</bitOffset>
            <bitWidth>16</bitWidth>
          </field>
        </fields>
      </register>
      <register>
        <name>CHDLYR1</name>
        <addressOffset>0x1bc</addressOffset>
        <size>0x20</size>
        <fields>
          <field>
            <name>PLSSKP</name>
            <bitOffset>0</bitOffset>
            <bitWidth>6</bitWidth>
          </field>
        </fields>
      </register>
      <register>
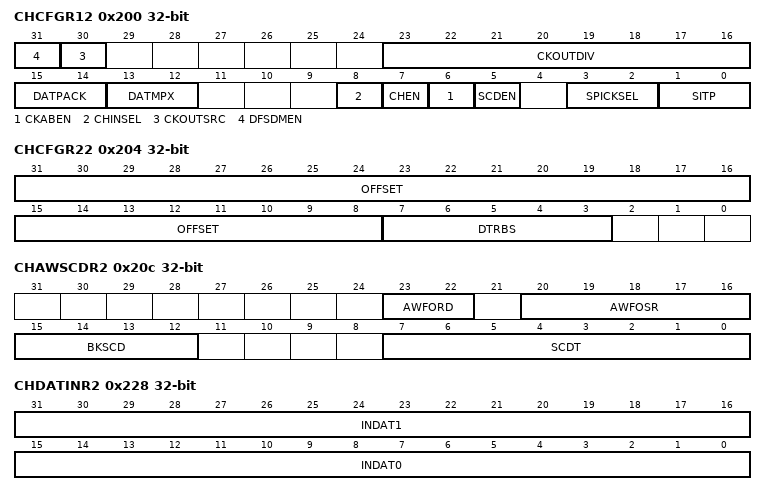
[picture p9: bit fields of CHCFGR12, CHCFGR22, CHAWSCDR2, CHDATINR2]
        <name>CHCFGR12</name>
        <addressOffset>0x200</addressOffset>
        <size>0x20</size>
        <fields>
          <field>
            <name>SITP</name>
            <bitOffset>0</bitOffset>
            <bitWidth>2</bitWidth>
          </field>
          <field>
            <name>SPICKSEL</name>
            <bitOffset>2</bitOffset>
            <bitWidth>2</bitWidth>
          </field>
          <field>
            <name>SCDEN</name>
            <bitOffset>5</bitOffset>
            <bitWidth>1</bitWidth>
          </field>
          <field>
            <name>CKABEN</name>
            <bitOffset>6</bitOffset>
            <bitWidth>1</bitWidth>
          </field>
          <field>
            <name>CHEN</name>
            <bitOffset>7</bitOffset>
            <bitWidth>1</bitWidth>
          </field>
          <field>
            <name>CHINSEL</name>
            <bitOffset>8</bitOffset>
            <bitWidth>1</bitWidth>
          </field>
          <field>
            <name>DATMPX</name>
            <bitOffset>12</bitOffset>
            <bitWidth>2</bitWidth>
          </field>
          <field>
            <name>DATPACK</name>
            <bitOffset>14</bitOffset>
            <bitWidth>2</bitWidth>
          </field>
          <field>
            <name>CKOUTDIV</name>
            <bitOffset>16</bitOffset>
            <bitWidth>8</bitWidth>
          </field>
          <field>
            <name>CKOUTSRC</name>
            <bitOffset>30</bitOffset>
            <bitWidth>1</bitWidth>
          </field>
          <field>
            <name>DFSDMEN</name>
            <bitOffset>31</bitOffset>
            <bitWidth>1</bitWidth>
          </field>
        </fields>
      </register>
      <register>
        <name>CHCFGR22</name>
        <addressOffset>0x204</addressOffset>
        <size>0x20</size>
        <fields>
          <field>
            <name>DTRBS</name>
            <bitOffset>3</bitOffset>
            <bitWidth>5</bitWidth>
          </field>
          <field>
            <name>OFFSET</name>
            <bitOffset>8</bitOffset>
            <bitWidth>24</bitWidth>
          </field>
        </fields>
      </register>
      <register>
        <name>CHAWSCDR2</name>
        <addressOffset>0x20c</addressOffset>
        <size>0x20</size>
        <fields>
          <field>
            <name>SCDT</name>
            <bitOffset>0</bitOffset>
            <bitWidth>8</bitWidth>
          </field>
          <field>
            <name>BKSCD</name>
            <bitOffset>12</bitOffset>
            <bitWidth>4</bitWidth>
          </field>
          <field>
            <name>AWFOSR</name>
            <bitOffset>16</bitOffset>
            <bitWidth>5</bitWidth>
          </field>
          <field>
            <name>AWFORD</name>
            <bitOffset>22</bitOffset>
            <bitWidth>2</bitWidth>
          </field>
        </fields>
      </register>
      <register>
        <name>CHWDATAR2</name>
        <addressOffset>0x218</addressOffset>
        <size>0x20</size>
      </register>
      <register>
        <name>CHDATINR2</name>
        <addressOffset>0x228</addressOffset>
        <size>0x20</size>
        <fields>
          <field>
            <name>INDAT0</name>
            <bitOffset>0</bitOffset>
            <bitWidth>16</bitWidth>
          </field>
          <field>
            <name>INDAT1</name>
            <bitOffset>16</bitOffset>
            <bitWidth>16</bitWidth>
          </field>
        </fields>
      </register>
      <register>
        <name>CHDLYR2</name>
        <addressOffset>0x23c</addressOffset>
        <size>0x20</size>
        <fields>
          <field>
            <name>PLSSKP</name>
            <bitOffset>0</bitOffset>
            <bitWidth>6</bitWidth>
          </field>
        </fields>
      </register>
      <register>
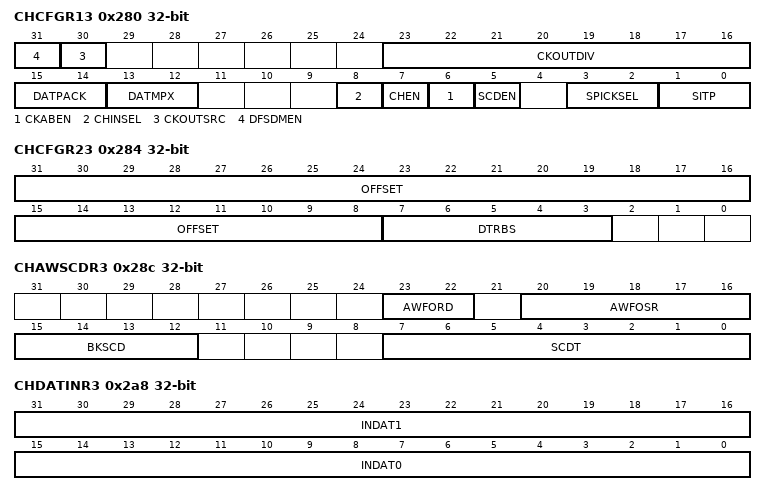
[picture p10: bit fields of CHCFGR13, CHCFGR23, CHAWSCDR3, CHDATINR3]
        <name>CHCFGR13</name>
        <addressOffset>0x280</addressOffset>
        <size>0x20</size>
        <fields>
          <field>
            <name>SITP</name>
            <bitOffset>0</bitOffset>
            <bitWidth>2</bitWidth>
          </field>
          <field>
            <name>SPICKSEL</name>
            <bitOffset>2</bitOffset>
            <bitWidth>2</bitWidth>
          </field>
          <field>
            <name>SCDEN</name>
            <bitOffset>5</bitOffset>
            <bitWidth>1</bitWidth>
          </field>
          <field>
            <name>CKABEN</name>
            <bitOffset>6</bitOffset>
            <bitWidth>1</bitWidth>
          </field>
          <field>
            <name>CHEN</name>
            <bitOffset>7</bitOffset>
            <bitWidth>1</bitWidth>
          </field>
          <field>
            <name>CHINSEL</name>
            <bitOffset>8</bitOffset>
            <bitWidth>1</bitWidth>
          </field>
          <field>
            <name>DATMPX</name>
            <bitOffset>12</bitOffset>
            <bitWidth>2</bitWidth>
          </field>
          <field>
            <name>DATPACK</name>
            <bitOffset>14</bitOffset>
            <bitWidth>2</bitWidth>
          </field>
          <field>
            <name>CKOUTDIV</name>
            <bitOffset>16</bitOffset>
            <bitWidth>8</bitWidth>
          </field>
          <field>
            <name>CKOUTSRC</name>
            <bitOffset>30</bitOffset>
            <bitWidth>1</bitWidth>
          </field>
          <field>
            <name>DFSDMEN</name>
            <bitOffset>31</bitOffset>
            <bitWidth>1</bitWidth>
          </field>
        </fields>
      </register>
      <register>
        <name>CHCFGR23</name>
        <addressOffset>0x284</addressOffset>
        <size>0x20</size>
        <fields>
          <field>
            <name>DTRBS</name>
            <bitOffset>3</bitOffset>
            <bitWidth>5</bitWidth>
          </field>
          <field>
            <name>OFFSET</name>
            <bitOffset>8</bitOffset>
            <bitWidth>24</bitWidth>
          </field>
        </fields>
      </register>
      <register>
        <name>CHAWSCDR3</name>
        <addressOffset>0x28c</addressOffset>
        <size>0x20</size>
        <fields>
          <field>
            <name>SCDT</name>
            <bitOffset>0</bitOffset>
            <bitWidth>8</bitWidth>
          </field>
          <field>
            <name>BKSCD</name>
            <bitOffset>12</bitOffset>
            <bitWidth>4</bitWidth>
          </field>
          <field>
            <name>AWFOSR</name>
            <bitOffset>16</bitOffset>
            <bitWidth>5</bitWidth>
          </field>
          <field>
            <name>AWFORD</name>
            <bitOffset>22</bitOffset>
            <bitWidth>2</bitWidth>
          </field>
        </fields>
      </register>
      <register>
        <name>CHWDATAR3</name>
        <addressOffset>0x298</addressOffset>
        <size>0x20</size>
      </register>
      <register>
        <name>CHDATINR3</name>
        <addressOffset>0x2a8</addressOffset>
        <size>0x20</size>
        <fields>
          <field>
            <name>INDAT0</name>
            <bitOffset>0</bitOffset>
            <bitWidth>16</bitWidth>
          </field>
          <field>
            <name>INDAT1</name>
            <bitOffset>16</bitOffset>
            <bitWidth>16</bitWidth>
          </field>
        </fields>
      </register>
      <register>
        <name>CHDLYR3</name>
        <addressOffset>0x2bc</addressOffset>
        <size>0x20</size>
        <fields>
          <field>
            <name>PLSSKP</name>
            <bitOffset>0</bitOffset>
            <bitWidth>6</bitWidth>
          </field>
        </fields>
      </register>
    </peripheral>
    <peripheral>
      <name>LTDC</name>
      <baseAddress>0x40016800</baseAddress>
      <register>
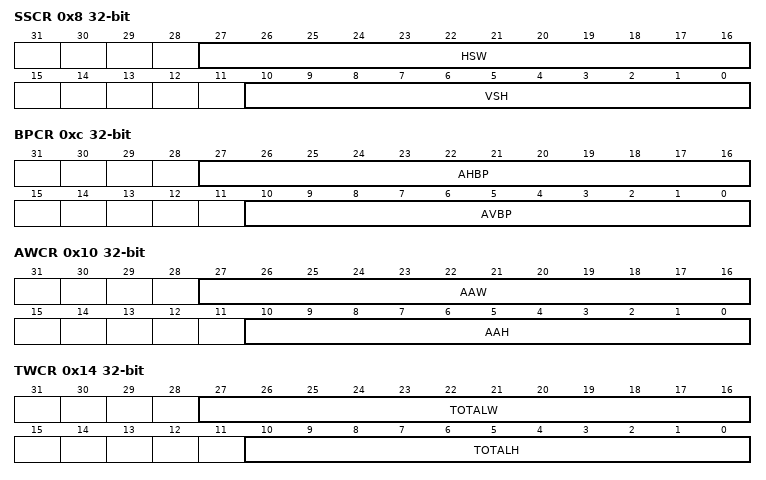
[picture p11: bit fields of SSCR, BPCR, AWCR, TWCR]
        <name>SSCR</name>
        <addressOffset>0x8</addressOffset>
        <size>0x20</size>
        <fields>
          <field>
            <name>VSH</name>
            <bitOffset>0</bitOffset>
            <bitWidth>11</bitWidth>
          </field>
          <field>
            <name>HSW</name>
            <bitOffset>16</bitOffset>
            <bitWidth>12</bitWidth>
          </field>
        </fields>
      </register>
      <register>
        <name>BPCR</name>
        <addressOffset>0xc</addressOffset>
        <size>0x20</size>
        <fields>
          <field>
            <name>AVBP</name>
            <bitOffset>0</bitOffset>
            <bitWidth>11</bitWidth>
          </field>
          <field>
            <name>AHBP</name>
            <bitOffset>16</bitOffset>
            <bitWidth>12</bitWidth>
          </field>
        </fields>
      </register>
      <register>
        <name>AWCR</name>
        <addressOffset>0x10</addressOffset>
        <size>0x20</size>
        <fields>
          <field>
            <name>AAH</name>
            <bitOffset>0</bitOffset>
            <bitWidth>11</bitWidth>
          </field>
          <field>
            <name>AAW</name>
            <bitOffset>16</bitOffset>
            <bitWidth>12</bitWidth>
          </field>
        </fields>
      </register>
      <register>
        <name>TWCR</name>
        <addressOffset>0x14</addressOffset>
        <size>0x20</size>
        <fields>
          <field>
            <name>TOTALH</name>
            <bitOffset>0</bitOffset>
            <bitWidth>11</bitWidth>
          </field>
          <field>
            <name>TOTALW</name>
            <bitOffset>16</bitOffset>
            <bitWidth>12</bitWidth>
          </field>
        </fields>
      </register>
      <register>
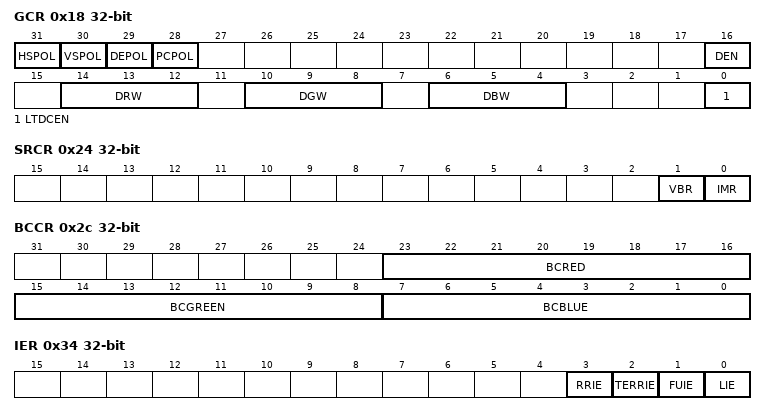
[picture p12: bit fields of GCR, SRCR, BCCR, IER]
        <name>GCR</name>
        <addressOffset>0x18</addressOffset>
        <size>0x20</size>
        <fields>
          <field>
            <name>LTDCEN</name>
            <bitOffset>0</bitOffset>
            <bitWidth>1</bitWidth>
          </field>
          <field>
            <name>DBW</name>
            <bitOffset>4</bitOffset>
            <bitWidth>3</bitWidth>
          </field>
          <field>
            <name>DGW</name>
            <bitOffset>8</bitOffset>
            <bitWidth>3</bitWidth>
          </field>
          <field>
            <name>DRW</name>
            <bitOffset>12</bitOffset>
            <bitWidth>3</bitWidth>
          </field>
          <field>
            <name>DEN</name>
            <bitOffset>16</bitOffset>
            <bitWidth>1</bitWidth>
          </field>
          <field>
            <name>PCPOL</name>
            <bitOffset>28</bitOffset>
            <bitWidth>1</bitWidth>
          </field>
          <field>
            <name>DEPOL</name>
            <bitOffset>29</bitOffset>
            <bitWidth>1</bitWidth>
          </field>
          <field>
            <name>VSPOL</name>
            <bitOffset>30</bitOffset>
            <bitWidth>1</bitWidth>
          </field>
          <field>
            <name>HSPOL</name>
            <bitOffset>31</bitOffset>
            <bitWidth>1</bitWidth>
          </field>
        </fields>
      </register>
      <register>
        <name>SRCR</name>
        <addressOffset>0x24</addressOffset>
        <size>0x20</size>
        <fields>
          <field>
            <name>IMR</name>
            <bitOffset>0</bitOffset>
            <bitWidth>1</bitWidth>
          </field>
          <field>
            <name>VBR</name>
            <bitOffset>1</bitOffset>
            <bitWidth>1</bitWidth>
          </field>
        </fields>
      </register>
      <register>
        <name>BCCR</name>
        <addressOffset>0x2c</addressOffset>
        <size>0x20</size>
        <fields>
          <field>
            <name>BCBLUE</name>
            <bitOffset>0</bitOffset>
            <bitWidth>8</bitWidth>
          </field>
          <field>
            <name>BCGREEN</name>
            <bitOffset>8</bitOffset>
            <bitWidth>8</bitWidth>
          </field>
          <field>
            <name>BCRED</name>
            <bitOffset>16</bitOffset>
            <bitWidth>8</bitWidth>
          </field>
        </fields>
      </register>
      <register>
        <name>IER</name>
        <addressOffset>0x34</addressOffset>
        <size>0x20</size>
        <fields>
          <field>
            <name>LIE</name>
            <bitOffset>0</bitOffset>
            <bitWidth>1</bitWidth>
          </field>
          <field>
            <name>FUIE</name>
            <bitOffset>1</bitOffset>
            <bitWidth>1</bitWidth>
          </field>
          <field>
            <name>TERRIE</name>
            <bitOffset>2</bitOffset>
            <bitWidth>1</bitWidth>
          </field>
          <field>
            <name>RRIE</name>
            <bitOffset>3</bitOffset>
            <bitWidth>1</bitWidth>
          </field>
        </fields>
      </register>
      <register>
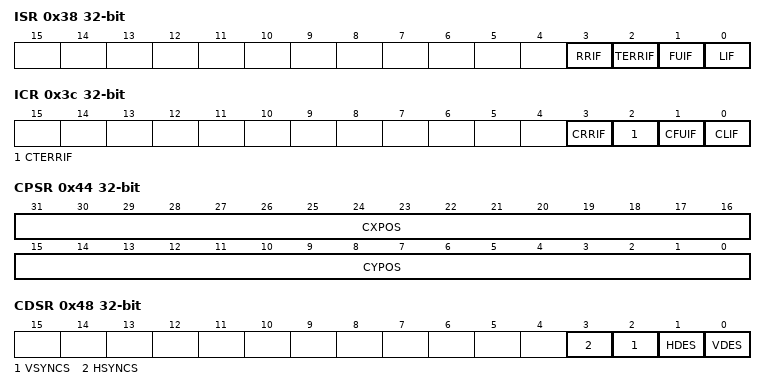
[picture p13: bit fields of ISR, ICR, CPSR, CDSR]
        <name>ISR</name>
        <addressOffset>0x38</addressOffset>
        <size>0x20</size>
        <fields>
          <field>
            <name>LIF</name>
            <bitOffset>0</bitOffset>
            <bitWidth>1</bitWidth>
          </field>
          <field>
            <name>FUIF</name>
            <bitOffset>1</bitOffset>
            <bitWidth>1</bitWidth>
          </field>
          <field>
            <name>TERRIF</name>
            <bitOffset>2</bitOffset>
            <bitWidth>1</bitWidth>
          </field>
          <field>
            <name>RRIF</name>
            <bitOffset>3</bitOffset>
            <bitWidth>1</bitWidth>
          </field>
        </fields>
      </register>
      <register>
        <name>ICR</name>
        <addressOffset>0x3c</addressOffset>
        <size>0x20</size>
        <fields>
          <field>
            <name>CLIF</name>
            <bitOffset>0</bitOffset>
            <bitWidth>1</bitWidth>
          </field>
          <field>
            <name>CFUIF</name>
            <bitOffset>1</bitOffset>
            <bitWidth>1</bitWidth>
          </field>
          <field>
            <name>CTERRIF</name>
            <bitOffset>2</bitOffset>
            <bitWidth>1</bitWidth>
          </field>
          <field>
            <name>CRRIF</name>
            <bitOffset>3</bitOffset>
            <bitWidth>1</bitWidth>
          </field>
        </fields>
      </register>
      <register>
        <name>LIPCR</name>
        <addressOffset>0x40</addressOffset>
        <size>0x20</size>
        <fields>
          <field>
            <name>LIPOS</name>
            <bitOffset>0</bitOffset>
            <bitWidth>11</bitWidth>
          </field>
        </fields>
      </register>
      <register>
        <name>CPSR</name>
        <addressOffset>0x44</addressOffset>
        <size>0x20</size>
        <fields>
          <field>
            <name>CYPOS</name>
            <bitOffset>0</bitOffset>
            <bitWidth>16</bitWidth>
          </field>
          <field>
            <name>CXPOS</name>
            <bitOffset>16</bitOffset>
            <bitWidth>16</bitWidth>
          </field>
        </fields>
      </register>
      <register>
        <name>CDSR</name>
        <addressOffset>0x48</addressOffset>
        <size>0x20</size>
        <fields>
          <field>
            <name>VDES</name>
            <bitOffset>0</bitOffset>
            <bitWidth>1</bitWidth>
          </field>
          <field>
            <name>HDES</name>
            <bitOffset>1</bitOffset>
            <bitWidth>1</bitWidth>
          </field>
          <field>
            <name>VSYNCS</name>
            <bitOffset>2</bitOffset>
            <bitWidth>1</bitWidth>
          </field>
          <field>
            <name>HSYNCS</name>
            <bitOffset>3</bitOffset>
            <bitWidth>1</bitWidth>
          </field>
        </fields>
      </register>
      <register>
        <name>CR1</name>
        <addressOffset>0x84</addressOffset>
        <size>0x20</size>
      </register>
      <register>
        <name>WHPCR1</name>
        <addressOffset>0x88</addressOffset>
        <size>0x20</size>
      </register>
      <register>
        <name>WVPCR1</name>
        <addressOffset>0x90</addressOffset>
        <size>0x20</size>
      </register>
      <register>
        <name>CKCR1</name>
        <addressOffset>0x9c</addressOffset>
        <size>0x20</size>
      </register>
      <register>
        <name>PFCR1</name>
        <addressOffset>0xac</addressOffset>
        <size>0x20</size>
      </register>
      <register>
        <name>CACR1</name>
        <addressOffset>0xc0</addressOffset>
        <size>0x20</size>
      </register>
      <register>
        <name>DCCR1</name>
        <addressOffset>0xd8</addressOffset>
        <size>0x20</size>
      </register>
      <register>
        <name>BFCR1</name>
        <addressOffset>0xf4</addressOffset>
        <size>0x20</size>
      </register>
      <register>
        <name>CFBAR1</name>
        <addressOffset>0x11c</addressOffset>
        <size>0x20</size>
      </register>
      <register>
        <name>CFBLR1</name>
        <addressOffset>0x148</addressOffset>
        <size>0x20</size>
      </register>
      <register>
        <name>CFBLNR1</name>
        <addressOffset>0x178</addressOffset>
        <size>0x20</size>
      </register>
      <register>
        <name>CLUTWR1</name>
        <addressOffset>0x1b8</addressOffset>
        <size>0x20</size>
      </register>
    </peripheral>
    <peripheral>
      <name>DMA1</name>
      <baseAddress>0x40020000</baseAddress>
      <register>
        <name>ISR</name>
        <addressOffset>0x0</addressOffset>
        <size>0x20</size>
        <fields>
          <field>
            <name>GIF1</name>
            <bitOffset>0</bitOffset>
            <bitWidth>1</bitWidth>
          </field>
          <field>
            <name>TCIF1</name>
            <bitOffset>1</bitOffset>
            <bitWidth>1</bitWidth>
          </field>
          <field>
            <name>HTIF1</name>
            <bitOffset>2</bitOffset>
            <bitWidth>1</bitWidth>
          </field>
          <field>
            <name>TEIF1</name>
            <bitOffset>3</bitOffset>
            <bitWidth>1</bitWidth>
          </field>
          <field>
            <name>GIF2</name>
            <bitOffset>4</bitOffset>
            <bitWidth>1</bitWidth>
          </field>
          <field>
            <name>TCIF2</name>
            <bitOffset>5</bitOffset>
            <bitWidth>1</bitWidth>
          </field>
          <field>
            <name>HTIF2</name>
            <bitOffset>6</bitOffset>
            <bitWidth>1</bitWidth>
          </field>
          <field>
            <name>TEIF2</name>
            <bitOffset>7</bitOffset>
            <bitWidth>1</bitWidth>
          </field>
          <field>
            <name>GIF3</name>
            <bitOffset>8</bitOffset>
            <bitWidth>1</bitWidth>
          </field>
          <field>
            <name>TCIF3</name>
            <bitOffset>9</bitOffset>
            <bitWidth>1</bitWidth>
          </field>
          <field>
            <name>HTIF3</name>
            <bitOffset>10</bitOffset>
            <bitWidth>1</bitWidth>
          </field>
          <field>
            <name>TEIF3</name>
            <bitOffset>11</bitOffset>
            <bitWidth>1</bitWidth>
          </field>
          <field>
            <name>GIF4</name>
            <bitOffset>12</bitOffset>
            <bitWidth>1</bitWidth>
          </field>
          <field>
            <name>TCIF4</name>
            <bitOffset>13</bitOffset>
            <bitWidth>1</bitWidth>
          </field>
          <field>
            <name>HTIF4</name>
            <bitOffset>14</bitOffset>
            <bitWidth>1</bitWidth>
          </field>
          <field>
            <name>TEIF4</name>
            <bitOffset>15</bitOffset>
            <bitWidth>1</bitWidth>
          </field>
          <field>
            <name>GIF5</name>
            <bitOffset>16</bitOffset>
            <bitWidth>1</bitWidth>
          </field>
          <field>
            <name>TCIF5</name>
            <bitOffset>17</bitOffset>
            <bitWidth>1</bitWidth>
          </field>
          <field>
            <name>HTIF5</name>
            <bitOffset>18</bitOffset>
            <bitWidth>1</bitWidth>
          </field>
          <field>
            <name>TEIF5</name>
            <bitOffset>19</bitOffset>
            <bitWidth>1</bitWidth>
          </field>
          <field>
            <name>GIF6</name>
            <bitOffset>20</bitOffset>
            <bitWidth>1</bitWidth>
          </field>
          <field>
            <name>TCIF6</name>
            <bitOffset>21</bitOffset>
            <bitWidth>1</bitWidth>
          </field>
          <field>
            <name>HTIF6</name>
            <bitOffset>22</bitOffset>
            <bitWidth>1</bitWidth>
          </field>
          <field>
            <name>TEIF6</name>
            <bitOffset>23</bitOffset>
            <bitWidth>1</bitWidth>
          </field>
          <field>
            <name>GIF7</name>
            <bitOffset>24</bitOffset>
            <bitWidth>1</bitWidth>
          </field>
          <field>
            <name>TCIF7</name>
            <bitOffset>25</bitOffset>
            <bitWidth>1</bitWidth>
          </field>
          <field>
            <name>HTIF7</name>
            <bitOffset>26</bitOffset>
            <bitWidth>1</bitWidth>
          </field>
          <field>
            <name>TEIF7</name>
            <bitOffset>27</bitOffset>
            <bitWidth>1</bitWidth>
          </field>
        </fields>
      </register>
      <register>
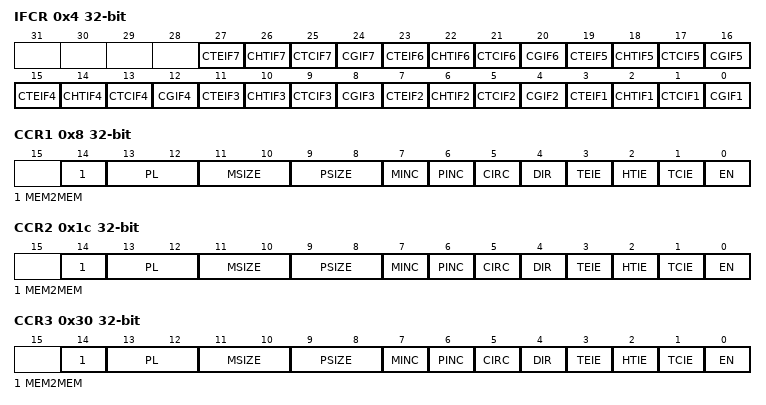
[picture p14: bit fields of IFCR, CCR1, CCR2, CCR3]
        <name>IFCR</name>
        <addressOffset>0x4</addressOffset>
        <size>0x20</size>
        <fields>
          <field>
            <name>CGIF1</name>
            <bitOffset>0</bitOffset>
            <bitWidth>1</bitWidth>
          </field>
          <field>
            <name>CTCIF1</name>
            <bitOffset>1</bitOffset>
            <bitWidth>1</bitWidth>
          </field>
          <field>
            <name>CHTIF1</name>
            <bitOffset>2</bitOffset>
            <bitWidth>1</bitWidth>
          </field>
          <field>
            <name>CTEIF1</name>
            <bitOffset>3</bitOffset>
            <bitWidth>1</bitWidth>
          </field>
          <field>
            <name>CGIF2</name>
            <bitOffset>4</bitOffset>
            <bitWidth>1</bitWidth>
          </field>
          <field>
            <name>CTCIF2</name>
            <bitOffset>5</bitOffset>
            <bitWidth>1</bitWidth>
          </field>
          <field>
            <name>CHTIF2</name>
            <bitOffset>6</bitOffset>
            <bitWidth>1</bitWidth>
          </field>
          <field>
            <name>CTEIF2</name>
            <bitOffset>7</bitOffset>
            <bitWidth>1</bitWidth>
          </field>
          <field>
            <name>CGIF3</name>
            <bitOffset>8</bitOffset>
            <bitWidth>1</bitWidth>
          </field>
          <field>
            <name>CTCIF3</name>
            <bitOffset>9</bitOffset>
            <bitWidth>1</bitWidth>
          </field>
          <field>
            <name>CHTIF3</name>
            <bitOffset>10</bitOffset>
            <bitWidth>1</bitWidth>
          </field>
          <field>
            <name>CTEIF3</name>
            <bitOffset>11</bitOffset>
            <bitWidth>1</bitWidth>
          </field>
          <field>
            <name>CGIF4</name>
            <bitOffset>12</bitOffset>
            <bitWidth>1</bitWidth>
          </field>
          <field>
            <name>CTCIF4</name>
            <bitOffset>13</bitOffset>
            <bitWidth>1</bitWidth>
          </field>
          <field>
            <name>CHTIF4</name>
            <bitOffset>14</bitOffset>
            <bitWidth>1</bitWidth>
          </field>
          <field>
            <name>CTEIF4</name>
            <bitOffset>15</bitOffset>
            <bitWidth>1</bitWidth>
          </field>
          <field>
            <name>CGIF5</name>
            <bitOffset>16</bitOffset>
            <bitWidth>1</bitWidth>
          </field>
          <field>
            <name>CTCIF5</name>
            <bitOffset>17</bitOffset>
            <bitWidth>1</bitWidth>
          </field>
          <field>
            <name>CHTIF5</name>
            <bitOffset>18</bitOffset>
            <bitWidth>1</bitWidth>
          </field>
          <field>
            <name>CTEIF5</name>
            <bitOffset>19</bitOffset>
            <bitWidth>1</bitWidth>
          </field>
          <field>
            <name>CGIF6</name>
            <bitOffset>20</bitOffset>
            <bitWidth>1</bitWidth>
          </field>
          <field>
            <name>CTCIF6</name>
            <bitOffset>21</bitOffset>
            <bitWidth>1</bitWidth>
          </field>
          <field>
            <name>CHTIF6</name>
            <bitOffset>22</bitOffset>
            <bitWidth>1</bitWidth>
          </field>
          <field>
            <name>CTEIF6</name>
            <bitOffset>23</bitOffset>
            <bitWidth>1</bitWidth>
          </field>
          <field>
            <name>CGIF7</name>
            <bitOffset>24</bitOffset>
            <bitWidth>1</bitWidth>
          </field>
          <field>
            <name>CTCIF7</name>
            <bitOffset>25</bitOffset>
            <bitWidth>1</bitWidth>
          </field>
          <field>
            <name>CHTIF7</name>
            <bitOffset>26</bitOffset>
            <bitWidth>1</bitWidth>
          </field>
          <field>
            <name>CTEIF7</name>
            <bitOffset>27</bitOffset>
            <bitWidth>1</bitWidth>
          </field>
        </fields>
      </register>
      <register>
        <name>CCR1</name>
        <addressOffset>0x8</addressOffset>
        <size>0x20</size>
        <fields>
          <field>
            <name>EN</name>
            <bitOffset>0</bitOffset>
            <bitWidth>1</bitWidth>
          </field>
          <field>
            <name>TCIE</name>
            <bitOffset>1</bitOffset>
            <bitWidth>1</bitWidth>
          </field>
          <field>
            <name>HTIE</name>
            <bitOffset>2</bitOffset>
            <bitWidth>1</bitWidth>
          </field>
          <field>
            <name>TEIE</name>
            <bitOffset>3</bitOffset>
            <bitWidth>1</bitWidth>
          </field>
          <field>
            <name>DIR</name>
            <bitOffset>4</bitOffset>
            <bitWidth>1</bitWidth>
          </field>
          <field>
            <name>CIRC</name>
            <bitOffset>5</bitOffset>
            <bitWidth>1</bitWidth>
          </field>
          <field>
            <name>PINC</name>
            <bitOffset>6</bitOffset>
            <bitWidth>1</bitWidth>
          </field>
          <field>
            <name>MINC</name>
            <bitOffset>7</bitOffset>
            <bitWidth>1</bitWidth>
          </field>
          <field>
            <name>PSIZE</name>
            <bitOffset>8</bitOffset>
            <bitWidth>2</bitWidth>
          </field>
          <field>
            <name>MSIZE</name>
            <bitOffset>10</bitOffset>
            <bitWidth>2</bitWidth>
          </field>
          <field>
            <name>PL</name>
            <bitOffset>12</bitOffset>
            <bitWidth>2</bitWidth>
          </field>
          <field>
            <name>MEM2MEM</name>
            <bitOffset>14</bitOffset>
            <bitWidth>1</bitWidth>
          </field>
        </fields>
      </register>
      <register>
        <name>CCR1</name>
        <addressOffset>0x8</addressOffset>
        <size>0x20</size>
        <fields>
          <field>
            <name>EN</name>
            <bitOffset>0</bitOffset>
            <bitWidth>1</bitWidth>
          </field>
          <field>
            <name>TCIE</name>
            <bitOffset>1</bitOffset>
            <bitWidth>1</bitWidth>
          </field>
          <field>
            <name>HTIE</name>
            <bitOffset>2</bitOffset>
            <bitWidth>1</bitWidth>
          </field>
          <field>
            <name>TEIE</name>
            <bitOffset>3</bitOffset>
            <bitWidth>1</bitWidth>
          </field>
          <field>
            <name>DIR</name>
            <bitOffset>4</bitOffset>
            <bitWidth>1</bitWidth>
          </field>
          <field>
            <name>CIRC</name>
            <bitOffset>5</bitOffset>
            <bitWidth>1</bitWidth>
          </field>
          <field>
            <name>PINC</name>
            <bitOffset>6</bitOffset>
            <bitWidth>1</bitWidth>
          </field>
          <field>
            <name>MINC</name>
            <bitOffset>7</bitOffset>
            <bitWidth>1</bitWidth>
          </field>
          <field>
            <name>PSIZE</name>
            <bitOffset>8</bitOffset>
            <bitWidth>2</bitWidth>
          </field>
          <field>
            <name>MSIZE</name>
            <bitOffset>10</bitOffset>
            <bitWidth>2</bitWidth>
          </field>
          <field>
            <name>PL</name>
            <bitOffset>12</bitOffset>
            <bitWidth>2</bitWidth>
          </field>
          <field>
            <name>MEM2MEM</name>
            <bitOffset>14</bitOffset>
            <bitWidth>1</bitWidth>
          </field>
        </fields>
      </register>
      <register>
        <name>CNDTR1</name>
        <addressOffset>0xc</addressOffset>
        <size>0x20</size>
        <fields>
          <field>
            <name>NDT</name>
            <bitOffset>0</bitOffset>
            <bitWidth>16</bitWidth>
          </field>
        </fields>
      </register>
      <register>
        <name>CNDTR1</name>
        <addressOffset>0xc</addressOffset>
        <size>0x20</size>
        <fields>
          <field>
            <name>NDT</name>
            <bitOffset>0</bitOffset>
            <bitWidth>16</bitWidth>
          </field>
        </fields>
      </register>
      <register>
        <name>CPAR1</name>
        <addressOffset>0x14</addressOffset>
        <size>0x20</size>
        <fields>
          <field>
            <name>PA</name>
            <bitOffset>0</bitOffset>
            <bitWidth>32</bitWidth>
          </field>
        </fields>
      </register>
      <register>
        <name>CPAR1</name>
        <addressOffset>0x14</addressOffset>
        <size>0x20</size>
        <fields>
          <field>
            <name>PA</name>
            <bitOffset>0</bitOffset>
            <bitWidth>32</bitWidth>
          </field>
        </fields>
      </register>
      <register>
        <name>CCR2</name>
        <addressOffset>0x1c</addressOffset>
        <size>0x20</size>
        <fields>
          <field>
            <name>EN</name>
            <bitOffset>0</bitOffset>
            <bitWidth>1</bitWidth>
          </field>
          <field>
            <name>TCIE</name>
            <bitOffset>1</bitOffset>
            <bitWidth>1</bitWidth>
          </field>
          <field>
            <name>HTIE</name>
            <bitOffset>2</bitOffset>
            <bitWidth>1</bitWidth>
          </field>
          <field>
            <name>TEIE</name>
            <bitOffset>3</bitOffset>
            <bitWidth>1</bitWidth>
          </field>
          <field>
            <name>DIR</name>
            <bitOffset>4</bitOffset>
            <bitWidth>1</bitWidth>
          </field>
          <field>
            <name>CIRC</name>
            <bitOffset>5</bitOffset>
            <bitWidth>1</bitWidth>
          </field>
          <field>
            <name>PINC</name>
            <bitOffset>6</bitOffset>
            <bitWidth>1</bitWidth>
          </field>
          <field>
            <name>MINC</name>
            <bitOffset>7</bitOffset>
            <bitWidth>1</bitWidth>
          </field>
          <field>
            <name>PSIZE</name>
            <bitOffset>8</bitOffset>
            <bitWidth>2</bitWidth>
          </field>
          <field>
            <name>MSIZE</name>
            <bitOffset>10</bitOffset>
            <bitWidth>2</bitWidth>
          </field>
          <field>
            <name>PL</name>
            <bitOffset>12</bitOffset>
            <bitWidth>2</bitWidth>
          </field>
          <field>
            <name>MEM2MEM</name>
            <bitOffset>14</bitOffset>
            <bitWidth>1</bitWidth>
          </field>
        </fields>
      </register>
      <register>
        <name>CCR2</name>
        <addressOffset>0x1c</addressOffset>
        <size>0x20</size>
        <fields>
          <field>
            <name>EN</name>
            <bitOffset>0</bitOffset>
            <bitWidth>1</bitWidth>
          </field>
          <field>
            <name>TCIE</name>
            <bitOffset>1</bitOffset>
            <bitWidth>1</bitWidth>
          </field>
          <field>
            <name>HTIE</name>
            <bitOffset>2</bitOffset>
            <bitWidth>1</bitWidth>
          </field>
          <field>
            <name>TEIE</name>
            <bitOffset>3</bitOffset>
            <bitWidth>1</bitWidth>
          </field>
          <field>
            <name>DIR</name>
            <bitOffset>4</bitOffset>
            <bitWidth>1</bitWidth>
          </field>
          <field>
            <name>CIRC</name>
            <bitOffset>5</bitOffset>
            <bitWidth>1</bitWidth>
          </field>
          <field>
            <name>PINC</name>
            <bitOffset>6</bitOffset>
            <bitWidth>1</bitWidth>
          </field>
          <field>
            <name>MINC</name>
            <bitOffset>7</bitOffset>
            <bitWidth>1</bitWidth>
          </field>
          <field>
            <name>PSIZE</name>
            <bitOffset>8</bitOffset>
            <bitWidth>2</bitWidth>
          </field>
          <field>
            <name>MSIZE</name>
            <bitOffset>10</bitOffset>
            <bitWidth>2</bitWidth>
          </field>
          <field>
            <name>PL</name>
            <bitOffset>12</bitOffset>
            <bitWidth>2</bitWidth>
          </field>
          <field>
            <name>MEM2MEM</name>
            <bitOffset>14</bitOffset>
            <bitWidth>1</bitWidth>
          </field>
        </fields>
      </register>
      <register>
        <name>CMAR1</name>
        <addressOffset>0x20</addressOffset>
        <size>0x20</size>
        <fields>
          <field>
            <name>MA</name>
            <bitOffset>0</bitOffset>
            <bitWidth>32</bitWidth>
          </field>
        </fields>
      </register>
      <register>
        <name>CNDTR2</name>
        <addressOffset>0x20</addressOffset>
        <size>0x20</size>
        <fields>
          <field>
            <name>NDT</name>
            <bitOffset>0</bitOffset>
            <bitWidth>16</bitWidth>
          </field>
        </fields>
      </register>
      <register>
        <name>CMAR1</name>
        <addressOffset>0x20</addressOffset>
        <size>0x20</size>
        <fields>
          <field>
            <name>MA</name>
            <bitOffset>0</bitOffset>
            <bitWidth>32</bitWidth>
          </field>
        </fields>
      </register>
      <register>
        <name>CNDTR2</name>
        <addressOffset>0x20</addressOffset>
        <size>0x20</size>
        <fields>
          <field>
            <name>NDT</name>
            <bitOffset>0</bitOffset>
            <bitWidth>16</bitWidth>
          </field>
        </fields>
      </register>
      <register>
        <name>CPAR2</name>
        <addressOffset>0x28</addressOffset>
        <size>0x20</size>
        <fields>
          <field>
            <name>PA</name>
            <bitOffset>0</bitOffset>
            <bitWidth>32</bitWidth>
          </field>
        </fields>
      </register>
      <register>
        <name>CPAR2</name>
        <addressOffset>0x28</addressOffset>
        <size>0x20</size>
        <fields>
          <field>
            <name>PA</name>
            <bitOffset>0</bitOffset>
            <bitWidth>32</bitWidth>
          </field>
        </fields>
      </register>
      <register>
        <name>CCR3</name>
        <addressOffset>0x30</addressOffset>
        <size>0x20</size>
        <fields>
          <field>
            <name>EN</name>
            <bitOffset>0</bitOffset>
            <bitWidth>1</bitWidth>
          </field>
          <field>
            <name>TCIE</name>
            <bitOffset>1</bitOffset>
            <bitWidth>1</bitWidth>
          </field>
          <field>
            <name>HTIE</name>
            <bitOffset>2</bitOffset>
            <bitWidth>1</bitWidth>
          </field>
          <field>
            <name>TEIE</name>
            <bitOffset>3</bitOffset>
            <bitWidth>1</bitWidth>
          </field>
          <field>
            <name>DIR</name>
            <bitOffset>4</bitOffset>
            <bitWidth>1</bitWidth>
          </field>
          <field>
            <name>CIRC</name>
            <bitOffset>5</bitOffset>
            <bitWidth>1</bitWidth>
          </field>
          <field>
            <name>PINC</name>
            <bitOffset>6</bitOffset>
            <bitWidth>1</bitWidth>
          </field>
          <field>
            <name>MINC</name>
            <bitOffset>7</bitOffset>
            <bitWidth>1</bitWidth>
          </field>
          <field>
            <name>PSIZE</name>
            <bitOffset>8</bitOffset>
            <bitWidth>2</bitWidth>
          </field>
          <field>
            <name>MSIZE</name>
            <bitOffset>10</bitOffset>
            <bitWidth>2</bitWidth>
          </field>
          <field>
            <name>PL</name>
            <bitOffset>12</bitOffset>
            <bitWidth>2</bitWidth>
          </field>
          <field>
            <name>MEM2MEM</name>
            <bitOffset>14</bitOffset>
            <bitWidth>1</bitWidth>
          </field>
        </fields>
      </register>
      <register>
        <name>CCR3</name>
        <addressOffset>0x30</addressOffset>
        <size>0x20</size>
        <fields>
          <field>
            <name>EN</name>
            <bitOffset>0</bitOffset>
            <bitWidth>1</bitWidth>
          </field>
          <field>
            <name>TCIE</name>
            <bitOffset>1</bitOffset>
            <bitWidth>1</bitWidth>
          </field>
          <field>
            <name>HTIE</name>
            <bitOffset>2</bitOffset>
            <bitWidth>1</bitWidth>
          </field>
          <field>
            <name>TEIE</name>
            <bitOffset>3</bitOffset>
            <bitWidth>1</bitWidth>
          </field>
          <field>
            <name>DIR</name>
            <bitOffset>4</bitOffset>
            <bitWidth>1</bitWidth>
          </field>
          <field>
            <name>CIRC</name>
            <bitOffset>5</bitOffset>
            <bitWidth>1</bitWidth>
          </field>
          <field>
            <name>PINC</name>
            <bitOffset>6</bitOffset>
            <bitWidth>1</bitWidth>
          </field>
          <field>
            <name>MINC</name>
            <bitOffset>7</bitOffset>
            <bitWidth>1</bitWidth>
          </field>
          <field>
            <name>PSIZE</name>
            <bitOffset>8</bitOffset>
            <bitWidth>2</bitWidth>
          </field>
          <field>
            <name>MSIZE</name>
            <bitOffset>10</bitOffset>
            <bitWidth>2</bitWidth>
          </field>
          <field>
            <name>PL</name>
            <bitOffset>12</bitOffset>
            <bitWidth>2</bitWidth>
          </field>
          <field>
            <name>MEM2MEM</name>
            <bitOffset>14</bitOffset>
            <bitWidth>1</bitWidth>
          </field>
        </fields>
      </register>
      <register>
        <name>CMAR2</name>
        <addressOffset>0x34</addressOffset>
        <size>0x20</size>
        <fields>
          <field>
            <name>MA</name>
            <bitOffset>0</bitOffset>
            <bitWidth>32</bitWidth>
          </field>
        </fields>
      </register>
      <register>
        <name>CNDTR3</name>
        <addressOffset>0x34</addressOffset>
        <size>0x20</size>
        <fields>
          <field>
            <name>NDT</name>
            <bitOffset>0</bitOffset>
            <bitWidth>16</bitWidth>
          </field>
        </fields>
      </register>
      <register>
        <name>CMAR2</name>
        <addressOffset>0x34</addressOffset>
        <size>0x20</size>
        <fields>
          <field>
            <name>MA</name>
            <bitOffset>0</bitOffset>
            <bitWidth>32</bitWidth>
          </field>
        </fields>
      </register>
      <register>
        <name>CNDTR3</name>
        <addressOffset>0x34</addressOffset>
        <size>0x20</size>
        <fields>
          <field>
            <name>NDT</name>
            <bitOffset>0</bitOffset>
            <bitWidth>16</bitWidth>
          </field>
        </fields>
      </register>
      <register>
        <name>CPAR3</name>
        <addressOffset>0x3c</addressOffset>
        <size>0x20</size>
        <fields>
          <field>
            <name>PA</name>
            <bitOffset>0</bitOffset>
            <bitWidth>32</bitWidth>
          </field>
        </fields>
      </register>
      <register>
        <name>CPAR3</name>
        <addressOffset>0x3c</addressOffset>
        <size>0x20</size>
        <fields>
          <field>
            <name>PA</name>
            <bitOffset>0</bitOffset>
            <bitWidth>32</bitWidth>
          </field>
        </fields>
      </register>
      <register>
        <name>CCR4</name>
        <addressOffset>0x44</addressOffset>
        <size>0x20</size>
        <fields>
          <field>
            <name>EN</name>
            <bitOffset>0</bitOffset>
            <bitWidth>1</bitWidth>
          </field>
          <field>
            <name>TCIE</name>
            <bitOffset>1</bitOffset>
            <bitWidth>1</bitWidth>
          </field>
          <field>
            <name>HTIE</name>
            <bitOffset>2</bitOffset>
            <bitWidth>1</bitWidth>
          </field>
          <field>
            <name>TEIE</name>
            <bitOffset>3</bitOffset>
            <bitWidth>1</bitWidth>
          </field>
          <field>
            <name>DIR</name>
            <bitOffset>4</bitOffset>
            <bitWidth>1</bitWidth>
          </field>
          <field>
            <name>CIRC</name>
            <bitOffset>5</bitOffset>
            <bitWidth>1</bitWidth>
          </field>
          <field>
            <name>PINC</name>
            <bitOffset>6</bitOffset>
            <bitWidth>1</bitWidth>
          </field>
          <field>
            <name>MINC</name>
            <bitOffset>7</bitOffset>
            <bitWidth>1</bitWidth>
          </field>
          <field>
            <name>PSIZE</name>
            <bitOffset>8</bitOffset>
            <bitWidth>2</bitWidth>
          </field>
          <field>
            <name>MSIZE</name>
            <bitOffset>10</bitOffset>
            <bitWidth>2</bitWidth>
          </field>
          <field>
            <name>PL</name>
            <bitOffset>12</bitOffset>
            <bitWidth>2</bitWidth>
          </field>
          <field>
            <name>MEM2MEM</name>
            <bitOffset>14</bitOffset>
            <bitWidth>1</bitWidth>
          </field>
        </fields>
      </register>
      <register>
        <name>CCR4</name>
        <addressOffset>0x44</addressOffset>
        <size>0x20</size>
        <fields>
          <field>
            <name>EN</name>
            <bitOffset>0</bitOffset>
            <bitWidth>1</bitWidth>
          </field>
          <field>
            <name>TCIE</name>
            <bitOffset>1</bitOffset>
            <bitWidth>1</bitWidth>
          </field>
          <field>
            <name>HTIE</name>
            <bitOffset>2</bitOffset>
            <bitWidth>1</bitWidth>
          </field>
          <field>
            <name>TEIE</name>
            <bitOffset>3</bitOffset>
            <bitWidth>1</bitWidth>
          </field>
          <field>
            <name>DIR</name>
            <bitOffset>4</bitOffset>
            <bitWidth>1</bitWidth>
          </field>
          <field>
            <name>CIRC</name>
            <bitOffset>5</bitOffset>
            <bitWidth>1</bitWidth>
          </field>
          <field>
            <name>PINC</name>
            <bitOffset>6</bitOffset>
            <bitWidth>1</bitWidth>
          </field>
          <field>
            <name>MINC</name>
            <bitOffset>7</bitOffset>
            <bitWidth>1</bitWidth>
          </field>
          <field>
            <name>PSIZE</name>
            <bitOffset>8</bitOffset>
            <bitWidth>2</bitWidth>
          </field>
          <field>
            <name>MSIZE</name>
            <bitOffset>10</bitOffset>
            <bitWidth>2</bitWidth>
          </field>
          <field>
            <name>PL</name>
            <bitOffset>12</bitOffset>
            <bitWidth>2</bitWidth>
          </field>
          <field>
            <name>MEM2MEM</name>
            <bitOffset>14</bitOffset>
            <bitWidth>1</bitWidth>
          </field>
        </fields>
      </register>
      <register>
        <name>CMAR3</name>
        <addressOffset>0x48</addressOffset>
        <size>0x20</size>
        <fields>
          <field>
            <name>MA</name>
            <bitOffset>0</bitOffset>
            <bitWidth>32</bitWidth>
          </field>
        </fields>
      </register>
      <register>
        <name>CNDTR4</name>
        <addressOffset>0x48</addressOffset>
        <size>0x20</size>
        <fields>
          <field>
            <name>NDT</name>
            <bitOffset>0</bitOffset>
            <bitWidth>16</bitWidth>
          </field>
        </fields>
      </register>
      <register>
        <name>CMAR3</name>
        <addressOffset>0x48</addressOffset>
        <size>0x20</size>
        <fields>
          <field>
            <name>MA</name>
            <bitOffset>0</bitOffset>
            <bitWidth>32</bitWidth>
          </field>
        </fields>
      </register>
      <register>
        <name>CNDTR4</name>
        <addressOffset>0x48</addressOffset>
        <size>0x20</size>
        <fields>
          <field>
            <name>NDT</name>
            <bitOffset>0</bitOffset>
            <bitWidth>16</bitWidth>
          </field>
        </fields>
      </register>
      <register>
        <name>CPAR4</name>
        <addressOffset>0x50</addressOffset>
        <size>0x20</size>
        <fields>
          <field>
            <name>PA</name>
            <bitOffset>0</bitOffset>
            <bitWidth>32</bitWidth>
          </field>
        </fields>
      </register>
      <register>
        <name>CPAR4</name>
        <addressOffset>0x50</addressOffset>
        <size>0x20</size>
        <fields>
          <field>
            <name>PA</name>
            <bitOffset>0</bitOffset>
            <bitWidth>32</bitWidth>
          </field>
        </fields>
      </register>
      <register>
        <name>CCR5</name>
        <addressOffset>0x58</addressOffset>
        <size>0x20</size>
        <fields>
          <field>
            <name>EN</name>
            <bitOffset>0</bitOffset>
            <bitWidth>1</bitWidth>
          </field>
          <field>
            <name>TCIE</name>
            <bitOffset>1</bitOffset>
            <bitWidth>1</bitWidth>
          </field>
          <field>
            <name>HTIE</name>
            <bitOffset>2</bitOffset>
            <bitWidth>1</bitWidth>
          </field>
          <field>
            <name>TEIE</name>
            <bitOffset>3</bitOffset>
            <bitWidth>1</bitWidth>
          </field>
          <field>
            <name>DIR</name>
            <bitOffset>4</bitOffset>
            <bitWidth>1</bitWidth>
          </field>
          <field>
            <name>CIRC</name>
            <bitOffset>5</bitOffset>
            <bitWidth>1</bitWidth>
          </field>
          <field>
            <name>PINC</name>
            <bitOffset>6</bitOffset>
            <bitWidth>1</bitWidth>
          </field>
          <field>
            <name>MINC</name>
            <bitOffset>7</bitOffset>
            <bitWidth>1</bitWidth>
          </field>
          <field>
            <name>PSIZE</name>
            <bitOffset>8</bitOffset>
            <bitWidth>2</bitWidth>
          </field>
          <field>
            <name>MSIZE</name>
            <bitOffset>10</bitOffset>
            <bitWidth>2</bitWidth>
          </field>
          <field>
            <name>PL</name>
            <bitOffset>12</bitOffset>
            <bitWidth>2</bitWidth>
          </field>
          <field>
            <name>MEM2MEM</name>
            <bitOffset>14</bitOffset>
            <bitWidth>1</bitWidth>
          </field>
        </fields>
      </register>
      <register>
        <name>CCR5</name>
        <addressOffset>0x58</addressOffset>
        <size>0x20</size>
        <fields>
          <field>
            <name>EN</name>
            <bitOffset>0</bitOffset>
            <bitWidth>1</bitWidth>
          </field>
          <field>
            <name>TCIE</name>
            <bitOffset>1</bitOffset>
            <bitWidth>1</bitWidth>
          </field>
          <field>
            <name>HTIE</name>
            <bitOffset>2</bitOffset>
            <bitWidth>1</bitWidth>
          </field>
          <field>
            <name>TEIE</name>
            <bitOffset>3</bitOffset>
            <bitWidth>1</bitWidth>
          </field>
          <field>
            <name>DIR</name>
            <bitOffset>4</bitOffset>
            <bitWidth>1</bitWidth>
          </field>
          <field>
            <name>CIRC</name>
            <bitOffset>5</bitOffset>
            <bitWidth>1</bitWidth>
          </field>
          <field>
            <name>PINC</name>
            <bitOffset>6</bitOffset>
            <bitWidth>1</bitWidth>
          </field>
          <field>
            <name>MINC</name>
            <bitOffset>7</bitOffset>
            <bitWidth>1</bitWidth>
          </field>
          <field>
            <name>PSIZE</name>
            <bitOffset>8</bitOffset>
            <bitWidth>2</bitWidth>
          </field>
          <field>
            <name>MSIZE</name>
            <bitOffset>10</bitOffset>
            <bitWidth>2</bitWidth>
          </field>
          <field>
            <name>PL</name>
            <bitOffset>12</bitOffset>
            <bitWidth>2</bitWidth>
          </field>
          <field>
            <name>MEM2MEM</name>
            <bitOffset>14</bitOffset>
            <bitWidth>1</bitWidth>
          </field>
        </fields>
      </register>
      <register>
        <name>CMAR4</name>
        <addressOffset>0x5c</addressOffset>
        <size>0x20</size>
        <fields>
          <field>
            <name>MA</name>
            <bitOffset>0</bitOffset>
            <bitWidth>32</bitWidth>
          </field>
        </fields>
      </register>
      <register>
        <name>CNDTR5</name>
        <addressOffset>0x5c</addressOffset>
        <size>0x20</size>
        <fields>
          <field>
            <name>NDT</name>
            <bitOffset>0</bitOffset>
            <bitWidth>16</bitWidth>
          </field>
        </fields>
      </register>
      <register>
        <name>CMAR4</name>
        <addressOffset>0x5c</addressOffset>
        <size>0x20</size>
        <fields>
          <field>
            <name>MA</name>
            <bitOffset>0</bitOffset>
            <bitWidth>32</bitWidth>
          </field>
        </fields>
      </register>
      <register>
        <name>CNDTR5</name>
        <addressOffset>0x5c</addressOffset>
        <size>0x20</size>
        <fields>
          <field>
            <name>NDT</name>
            <bitOffset>0</bitOffset>
            <bitWidth>16</bitWidth>
          </field>
        </fields>
      </register>
      <register>
        <name>CPAR5</name>
        <addressOffset>0x64</addressOffset>
        <size>0x20</size>
        <fields>
          <field>
            <name>PA</name>
            <bitOffset>0</bitOffset>
            <bitWidth>32</bitWidth>
          </field>
        </fields>
      </register>
      <register>
        <name>CPAR5</name>
        <addressOffset>0x64</addressOffset>
        <size>0x20</size>
        <fields>
          <field>
            <name>PA</name>
            <bitOffset>0</bitOffset>
            <bitWidth>32</bitWidth>
          </field>
        </fields>
      </register>
      <register>
        <name>CCR6</name>
        <addressOffset>0x6c</addressOffset>
        <size>0x20</size>
        <fields>
          <field>
            <name>EN</name>
            <bitOffset>0</bitOffset>
            <bitWidth>1</bitWidth>
          </field>
          <field>
            <name>TCIE</name>
            <bitOffset>1</bitOffset>
            <bitWidth>1</bitWidth>
          </field>
          <field>
            <name>HTIE</name>
            <bitOffset>2</bitOffset>
            <bitWidth>1</bitWidth>
          </field>
          <field>
            <name>TEIE</name>
            <bitOffset>3</bitOffset>
            <bitWidth>1</bitWidth>
          </field>
          <field>
            <name>DIR</name>
            <bitOffset>4</bitOffset>
            <bitWidth>1</bitWidth>
          </field>
          <field>
            <name>CIRC</name>
            <bitOffset>5</bitOffset>
            <bitWidth>1</bitWidth>
          </field>
          <field>
            <name>PINC</name>
            <bitOffset>6</bitOffset>
            <bitWidth>1</bitWidth>
          </field>
          <field>
            <name>MINC</name>
            <bitOffset>7</bitOffset>
            <bitWidth>1</bitWidth>
          </field>
          <field>
            <name>PSIZE</name>
            <bitOffset>8</bitOffset>
            <bitWidth>2</bitWidth>
          </field>
          <field>
            <name>MSIZE</name>
            <bitOffset>10</bitOffset>
            <bitWidth>2</bitWidth>
          </field>
          <field>
            <name>PL</name>
            <bitOffset>12</bitOffset>
            <bitWidth>2</bitWidth>
          </field>
          <field>
            <name>MEM2MEM</name>
            <bitOffset>14</bitOffset>
            <bitWidth>1</bitWidth>
          </field>
        </fields>
      </register>
      <register>
        <name>CCR6</name>
        <addressOffset>0x6c</addressOffset>
        <size>0x20</size>
        <fields>
          <field>
            <name>EN</name>
            <bitOffset>0</bitOffset>
            <bitWidth>1</bitWidth>
          </field>
          <field>
            <name>TCIE</name>
            <bitOffset>1</bitOffset>
            <bitWidth>1</bitWidth>
          </field>
          <field>
            <name>HTIE</name>
            <bitOffset>2</bitOffset>
            <bitWidth>1</bitWidth>
          </field>
          <field>
            <name>TEIE</name>
            <bitOffset>3</bitOffset>
            <bitWidth>1</bitWidth>
          </field>
          <field>
            <name>DIR</name>
            <bitOffset>4</bitOffset>
            <bitWidth>1</bitWidth>
          </field>
          <field>
            <name>CIRC</name>
            <bitOffset>5</bitOffset>
            <bitWidth>1</bitWidth>
          </field>
          <field>
            <name>PINC</name>
            <bitOffset>6</bitOffset>
            <bitWidth>1</bitWidth>
          </field>
          <field>
            <name>MINC</name>
            <bitOffset>7</bitOffset>
            <bitWidth>1</bitWidth>
          </field>
          <field>
            <name>PSIZE</name>
            <bitOffset>8</bitOffset>
            <bitWidth>2</bitWidth>
          </field>
          <field>
            <name>MSIZE</name>
            <bitOffset>10</bitOffset>
            <bitWidth>2</bitWidth>
          </field>
          <field>
            <name>PL</name>
            <bitOffset>12</bitOffset>
            <bitWidth>2</bitWidth>
          </field>
          <field>
            <name>MEM2MEM</name>
            <bitOffset>14</bitOffset>
            <bitWidth>1</bitWidth>
          </field>
        </fields>
      </register>
      <register>
        <name>CMAR5</name>
        <addressOffset>0x70</addressOffset>
        <size>0x20</size>
        <fields>
          <field>
            <name>MA</name>
            <bitOffset>0</bitOffset>
            <bitWidth>32</bitWidth>
          </field>
        </fields>
      </register>
      <register>
        <name>CNDTR6</name>
        <addressOffset>0x70</addressOffset>
        <size>0x20</size>
        <fields>
          <field>
            <name>NDT</name>
            <bitOffset>0</bitOffset>
            <bitWidth>16</bitWidth>
          </field>
        </fields>
      </register>
      <register>
        <name>CMAR5</name>
        <addressOffset>0x70</addressOffset>
        <size>0x20</size>
        <fields>
          <field>
            <name>MA</name>
            <bitOffset>0</bitOffset>
            <bitWidth>32</bitWidth>
          </field>
        </fields>
      </register>
      <register>
        <name>CNDTR6</name>
        <addressOffset>0x70</addressOffset>
        <size>0x20</size>
        <fields>
          <field>
            <name>NDT</name>
            <bitOffset>0</bitOffset>
            <bitWidth>16</bitWidth>
          </field>
        </fields>
      </register>
      <register>
        <name>CPAR6</name>
        <addressOffset>0x78</addressOffset>
        <size>0x20</size>
        <fields>
          <field>
            <name>PA</name>
            <bitOffset>0</bitOffset>
            <bitWidth>32</bitWidth>
          </field>
        </fields>
      </register>
      <register>
        <name>CPAR6</name>
        <addressOffset>0x78</addressOffset>
        <size>0x20</size>
        <fields>
          <field>
            <name>PA</name>
            <bitOffset>0</bitOffset>
            <bitWidth>32</bitWidth>
          </field>
        </fields>
      </register>
      <register>
        <name>CCR7</name>
        <addressOffset>0x80</addressOffset>
        <size>0x20</size>
        <fields>
          <field>
            <name>EN</name>
            <bitOffset>0</bitOffset>
            <bitWidth>1</bitWidth>
          </field>
          <field>
            <name>TCIE</name>
            <bitOffset>1</bitOffset>
            <bitWidth>1</bitWidth>
          </field>
          <field>
            <name>HTIE</name>
            <bitOffset>2</bitOffset>
            <bitWidth>1</bitWidth>
          </field>
          <field>
            <name>TEIE</name>
            <bitOffset>3</bitOffset>
            <bitWidth>1</bitWidth>
          </field>
          <field>
            <name>DIR</name>
            <bitOffset>4</bitOffset>
            <bitWidth>1</bitWidth>
          </field>
          <field>
            <name>CIRC</name>
            <bitOffset>5</bitOffset>
            <bitWidth>1</bitWidth>
          </field>
          <field>
            <name>PINC</name>
            <bitOffset>6</bitOffset>
            <bitWidth>1</bitWidth>
          </field>
          <field>
            <name>MINC</name>
            <bitOffset>7</bitOffset>
            <bitWidth>1</bitWidth>
          </field>
          <field>
            <name>PSIZE</name>
            <bitOffset>8</bitOffset>
            <bitWidth>2</bitWidth>
          </field>
          <field>
            <name>MSIZE</name>
            <bitOffset>10</bitOffset>
            <bitWidth>2</bitWidth>
          </field>
          <field>
            <name>PL</name>
            <bitOffset>12</bitOffset>
            <bitWidth>2</bitWidth>
          </field>
          <field>
            <name>MEM2MEM</name>
            <bitOffset>14</bitOffset>
            <bitWidth>1</bitWidth>
          </field>
        </fields>
      </register>
      <register>
        <name>CCR7</name>
        <addressOffset>0x80</addressOffset>
        <size>0x20</size>
        <fields>
          <field>
            <name>EN</name>
            <bitOffset>0</bitOffset>
            <bitWidth>1</bitWidth>
          </field>
          <field>
            <name>TCIE</name>
            <bitOffset>1</bitOffset>
            <bitWidth>1</bitWidth>
          </field>
          <field>
            <name>HTIE</name>
            <bitOffset>2</bitOffset>
            <bitWidth>1</bitWidth>
          </field>
          <field>
            <name>TEIE</name>
            <bitOffset>3</bitOffset>
            <bitWidth>1</bitWidth>
          </field>
          <field>
            <name>DIR</name>
            <bitOffset>4</bitOffset>
            <bitWidth>1</bitWidth>
          </field>
          <field>
            <name>CIRC</name>
            <bitOffset>5</bitOffset>
            <bitWidth>1</bitWidth>
          </field>
          <field>
            <name>PINC</name>
            <bitOffset>6</bitOffset>
            <bitWidth>1</bitWidth>
          </field>
          <field>
            <name>MINC</name>
            <bitOffset>7</bitOffset>
            <bitWidth>1</bitWidth>
          </field>
          <field>
            <name>PSIZE</name>
            <bitOffset>8</bitOffset>
            <bitWidth>2</bitWidth>
          </field>
          <field>
            <name>MSIZE</name>
            <bitOffset>10</bitOffset>
            <bitWidth>2</bitWidth>
          </field>
          <field>
            <name>PL</name>
            <bitOffset>12</bitOffset>
            <bitWidth>2</bitWidth>
          </field>
          <field>
            <name>MEM2MEM</name>
            <bitOffset>14</bitOffset>
            <bitWidth>1</bitWidth>
          </field>
        </fields>
      </register>
      <register>
        <name>CMAR6</name>
        <addressOffset>0x84</addressOffset>
        <size>0x20</size>
        <fields>
          <field>
            <name>MA</name>
            <bitOffset>0</bitOffset>
            <bitWidth>32</bitWidth>
          </field>
        </fields>
      </register>
      <register>
        <name>CNDTR7</name>
        <addressOffset>0x84</addressOffset>
        <size>0x20</size>
        <fields>
          <field>
            <name>NDT</name>
            <bitOffset>0</bitOffset>
            <bitWidth>16</bitWidth>
          </field>
        </fields>
      </register>
      <register>
        <name>CMAR6</name>
        <addressOffset>0x84</addressOffset>
        <size>0x20</size>
        <fields>
          <field>
            <name>MA</name>
            <bitOffset>0</bitOffset>
            <bitWidth>32</bitWidth>
          </field>
        </fields>
      </register>
      <register>
        <name>CNDTR7</name>
        <addressOffset>0x84</addressOffset>
        <size>0x20</size>
        <fields>
          <field>
            <name>NDT</name>
            <bitOffset>0</bitOffset>
            <bitWidth>16</bitWidth>
          </field>
        </fields>
      </register>
      <register>
        <name>CPAR7</name>
        <addressOffset>0x8c</addressOffset>
        <size>0x20</size>
        <fields>
          <field>
            <name>PA</name>
            <bitOffset>0</bitOffset>
            <bitWidth>32</bitWidth>
          </field>
        </fields>
      </register>
      <register>
        <name>CPAR7</name>
        <addressOffset>0x8c</addressOffset>
        <size>0x20</size>
        <fields>
          <field>
            <name>PA</name>
            <bitOffset>0</bitOffset>
            <bitWidth>32</bitWidth>
          </field>
        </fields>
      </register>
      <register>
        <name>CMAR7</name>
        <addressOffset>0x98</addressOffset>
        <size>0x20</size>
        <fields>
          <field>
            <name>MA</name>
            <bitOffset>0</bitOffset>
            <bitWidth>32</bitWidth>
          </field>
        </fields>
      </register>
      <register>
        <name>CMAR7</name>
        <addressOffset>0x98</addressOffset>
        <size>0x20</size>
        <fields>
          <field>
            <name>MA</name>
            <bitOffset>0</bitOffset>
            <bitWidth>32</bitWidth>
          </field>
        </fields>
      </register>
    </peripheral>
    <peripheral>
      <name>DMA2</name>
      <baseAddress>0x40020400</baseAddress>
      <register>
        <name>ISR</name>
        <addressOffset>0x0</addressOffset>
        <size>0x20</size>
        <fields>
          <field>
            <name>GIF1</name>
            <bitOffset>0</bitOffset>
            <bitWidth>1</bitWidth>
          </field>
          <field>
            <name>TCIF1</name>
            <bitOffset>1</bitOffset>
            <bitWidth>1</bitWidth>
          </field>
          <field>
            <name>HTIF1</name>
            <bitOffset>2</bitOffset>
            <bitWidth>1</bitWidth>
          </field>
          <field>
            <name>TEIF1</name>
            <bitOffset>3</bitOffset>
            <bitWidth>1</bitWidth>
          </field>
          <field>
            <name>GIF2</name>
            <bitOffset>4</bitOffset>
            <bitWidth>1</bitWidth>
          </field>
          <field>
            <name>TCIF2</name>
            <bitOffset>5</bitOffset>
            <bitWidth>1</bitWidth>
          </field>
          <field>
            <name>HTIF2</name>
            <bitOffset>6</bitOffset>
            <bitWidth>1</bitWidth>
          </field>
          <field>
            <name>TEIF2</name>
            <bitOffset>7</bitOffset>
            <bitWidth>1</bitWidth>
          </field>
          <field>
            <name>GIF3</name>
            <bitOffset>8</bitOffset>
            <bitWidth>1</bitWidth>
          </field>
          <field>
            <name>TCIF3</name>
            <bitOffset>9</bitOffset>
            <bitWidth>1</bitWidth>
          </field>
          <field>
            <name>HTIF3</name>
            <bitOffset>10</bitOffset>
            <bitWidth>1</bitWidth>
          </field>
          <field>
            <name>TEIF3</name>
            <bitOffset>11</bitOffset>
            <bitWidth>1</bitWidth>
          </field>
          <field>
            <name>GIF4</name>
            <bitOffset>12</bitOffset>
            <bitWidth>1</bitWidth>
          </field>
          <field>
            <name>TCIF4</name>
            <bitOffset>13</bitOffset>
            <bitWidth>1</bitWidth>
          </field>
          <field>
            <name>HTIF4</name>
            <bitOffset>14</bitOffset>
            <bitWidth>1</bitWidth>
          </field>
          <field>
            <name>TEIF4</name>
            <bitOffset>15</bitOffset>
            <bitWidth>1</bitWidth>
          </field>
          <field>
            <name>GIF5</name>
            <bitOffset>16</bitOffset>
            <bitWidth>1</bitWidth>
          </field>
          <field>
            <name>TCIF5</name>
            <bitOffset>17</bitOffset>
            <bitWidth>1</bitWidth>
          </field>
          <field>
            <name>HTIF5</name>
            <bitOffset>18</bitOffset>
            <bitWidth>1</bitWidth>
          </field>
          <field>
            <name>TEIF5</name>
            <bitOffset>19</bitOffset>
            <bitWidth>1</bitWidth>
          </field>
          <field>
            <name>GIF6</name>
            <bitOffset>20</bitOffset>
            <bitWidth>1</bitWidth>
          </field>
          <field>
            <name>TCIF6</name>
            <bitOffset>21</bitOffset>
            <bitWidth>1</bitWidth>
          </field>
          <field>
            <name>HTIF6</name>
            <bitOffset>22</bitOffset>
            <bitWidth>1</bitWidth>
          </field>
          <field>
            <name>TEIF6</name>
            <bitOffset>23</bitOffset>
            <bitWidth>1</bitWidth>
          </field>
          <field>
            <name>GIF7</name>
            <bitOffset>24</bitOffset>
            <bitWidth>1</bitWidth>
          </field>
          <field>
            <name>TCIF7</name>
            <bitOffset>25</bitOffset>
            <bitWidth>1</bitWidth>
          </field>
          <field>
            <name>HTIF7</name>
            <bitOffset>26</bitOffset>
            <bitWidth>1</bitWidth>
          </field>
          <field>
            <name>TEIF7</name>
            <bitOffset>27</bitOffset>
            <bitWidth>1</bitWidth>
          </field>
        </fields>
      </register>
      <register>
        <name>IFCR</name>
        <addressOffset>0x4</addressOffset>
        <size>0x20</size>
        <fields>
          <field>
            <name>CGIF1</name>
            <bitOffset>0</bitOffset>
            <bitWidth>1</bitWidth>
          </field>
          <field>
            <name>CTCIF1</name>
            <bitOffset>1</bitOffset>
            <bitWidth>1</bitWidth>
          </field>
          <field>
            <name>CHTIF1</name>
            <bitOffset>2</bitOffset>
            <bitWidth>1</bitWidth>
          </field>
          <field>
            <name>CTEIF1</name>
            <bitOffset>3</bitOffset>
            <bitWidth>1</bitWidth>
          </field>
          <field>
            <name>CGIF2</name>
            <bitOffset>4</bitOffset>
            <bitWidth>1</bitWidth>
          </field>
          <field>
            <name>CTCIF2</name>
            <bitOffset>5</bitOffset>
            <bitWidth>1</bitWidth>
          </field>
          <field>
            <name>CHTIF2</name>
            <bitOffset>6</bitOffset>
            <bitWidth>1</bitWidth>
          </field>
          <field>
            <name>CTEIF2</name>
            <bitOffset>7</bitOffset>
            <bitWidth>1</bitWidth>
          </field>
          <field>
            <name>CGIF3</name>
            <bitOffset>8</bitOffset>
            <bitWidth>1</bitWidth>
          </field>
          <field>
            <name>CTCIF3</name>
            <bitOffset>9</bitOffset>
            <bitWidth>1</bitWidth>
          </field>
          <field>
            <name>CHTIF3</name>
            <bitOffset>10</bitOffset>
            <bitWidth>1</bitWidth>
          </field>
          <field>
            <name>CTEIF3</name>
            <bitOffset>11</bitOffset>
            <bitWidth>1</bitWidth>
          </field>
          <field>
            <name>CGIF4</name>
            <bitOffset>12</bitOffset>
            <bitWidth>1</bitWidth>
          </field>
          <field>
            <name>CTCIF4</name>
            <bitOffset>13</bitOffset>
            <bitWidth>1</bitWidth>
          </field>
          <field>
            <name>CHTIF4</name>
            <bitOffset>14</bitOffset>
            <bitWidth>1</bitWidth>
          </field>
          <field>
            <name>CTEIF4</name>
            <bitOffset>15</bitOffset>
            <bitWidth>1</bitWidth>
          </field>
          <field>
            <name>CGIF5</name>
            <bitOffset>16</bitOffset>
            <bitWidth>1</bitWidth>
          </field>
          <field>
            <name>CTCIF5</name>
            <bitOffset>17</bitOffset>
            <bitWidth>1</bitWidth>
          </field>
          <field>
            <name>CHTIF5</name>
            <bitOffset>18</bitOffset>
            <bitWidth>1</bitWidth>
          </field>
          <field>
            <name>CTEIF5</name>
            <bitOffset>19</bitOffset>
            <bitWidth>1</bitWidth>
          </field>
          <field>
            <name>CGIF6</name>
            <bitOffset>20</bitOffset>
            <bitWidth>1</bitWidth>
          </field>
          <field>
            <name>CTCIF6</name>
            <bitOffset>21</bitOffset>
            <bitWidth>1</bitWidth>
          </field>
          <field>
            <name>CHTIF6</name>
            <bitOffset>22</bitOffset>
            <bitWidth>1</bitWidth>
          </field>
          <field>
            <name>CTEIF6</name>
            <bitOffset>23</bitOffset>
            <bitWidth>1</bitWidth>
          </field>
          <field>
            <name>CGIF7</name>
            <bitOffset>24</bitOffset>
            <bitWidth>1</bitWidth>
          </field>
          <field>
            <name>CTCIF7</name>
            <bitOffset>25</bitOffset>
            <bitWidth>1</bitWidth>
          </field>
          <field>
            <name>CHTIF7</name>
            <bitOffset>26</bitOffset>
            <bitWidth>1</bitWidth>
          </field>
          <field>
            <name>CTEIF7</name>
            <bitOffset>27</bitOffset>
            <bitWidth>1</bitWidth>
          </field>
        </fields>
      </register>
      <register>
        <name>CCR1</name>
        <addressOffset>0x8</addressOffset>
        <size>0x20</size>
        <fields>
          <field>
            <name>EN</name>
            <bitOffset>0</bitOffset>
            <bitWidth>1</bitWidth>
          </field>
          <field>
            <name>TCIE</name>
            <bitOffset>1</bitOffset>
            <bitWidth>1</bitWidth>
          </field>
          <field>
            <name>HTIE</name>
            <bitOffset>2</bitOffset>
            <bitWidth>1</bitWidth>
          </field>
          <field>
            <name>TEIE</name>
            <bitOffset>3</bitOffset>
            <bitWidth>1</bitWidth>
          </field>
          <field>
            <name>DIR</name>
            <bitOffset>4</bitOffset>
            <bitWidth>1</bitWidth>
          </field>
          <field>
            <name>CIRC</name>
            <bitOffset>5</bitOffset>
            <bitWidth>1</bitWidth>
          </field>
          <field>
            <name>PINC</name>
            <bitOffset>6</bitOffset>
            <bitWidth>1</bitWidth>
          </field>
          <field>
            <name>MINC</name>
            <bitOffset>7</bitOffset>
            <bitWidth>1</bitWidth>
          </field>
          <field>
            <name>PSIZE</name>
            <bitOffset>8</bitOffset>
            <bitWidth>2</bitWidth>
          </field>
          <field>
            <name>MSIZE</name>
            <bitOffset>10</bitOffset>
            <bitWidth>2</bitWidth>
          </field>
          <field>
            <name>PL</name>
            <bitOffset>12</bitOffset>
            <bitWidth>2</bitWidth>
          </field>
          <field>
            <name>MEM2MEM</name>
            <bitOffset>14</bitOffset>
            <bitWidth>1</bitWidth>
          </field>
        </fields>
      </register>
      <register>
        <name>CCR1</name>
        <addressOffset>0x8</addressOffset>
        <size>0x20</size>
        <fields>
          <field>
            <name>EN</name>
            <bitOffset>0</bitOffset>
            <bitWidth>1</bitWidth>
          </field>
          <field>
            <name>TCIE</name>
            <bitOffset>1</bitOffset>
            <bitWidth>1</bitWidth>
          </field>
          <field>
            <name>HTIE</name>
            <bitOffset>2</bitOffset>
            <bitWidth>1</bitWidth>
          </field>
          <field>
            <name>TEIE</name>
            <bitOffset>3</bitOffset>
            <bitWidth>1</bitWidth>
          </field>
          <field>
            <name>DIR</name>
            <bitOffset>4</bitOffset>
            <bitWidth>1</bitWidth>
          </field>
          <field>
            <name>CIRC</name>
            <bitOffset>5</bitOffset>
            <bitWidth>1</bitWidth>
          </field>
          <field>
            <name>PINC</name>
            <bitOffset>6</bitOffset>
            <bitWidth>1</bitWidth>
          </field>
          <field>
            <name>MINC</name>
            <bitOffset>7</bitOffset>
            <bitWidth>1</bitWidth>
          </field>
          <field>
            <name>PSIZE</name>
            <bitOffset>8</bitOffset>
            <bitWidth>2</bitWidth>
          </field>
          <field>
            <name>MSIZE</name>
            <bitOffset>10</bitOffset>
            <bitWidth>2</bitWidth>
          </field>
          <field>
            <name>PL</name>
            <bitOffset>12</bitOffset>
            <bitWidth>2</bitWidth>
          </field>
          <field>
            <name>MEM2MEM</name>
            <bitOffset>14</bitOffset>
            <bitWidth>1</bitWidth>
          </field>
        </fields>
      </register>
      <register>
        <name>CNDTR1</name>
        <addressOffset>0xc</addressOffset>
        <size>0x20</size>
        <fields>
          <field>
            <name>NDT</name>
            <bitOffset>0</bitOffset>
            <bitWidth>16</bitWidth>
          </field>
        </fields>
      </register>
      <register>
        <name>CNDTR1</name>
        <addressOffset>0xc</addressOffset>
        <size>0x20</size>
        <fields>
          <field>
            <name>NDT</name>
            <bitOffset>0</bitOffset>
            <bitWidth>16</bitWidth>
          </field>
        </fields>
      </register>
      <register>
        <name>CPAR1</name>
        <addressOffset>0x14</addressOffset>
        <size>0x20</size>
        <fields>
          <field>
            <name>PA</name>
            <bitOffset>0</bitOffset>
            <bitWidth>32</bitWidth>
          </field>
        </fields>
      </register>
      <register>
        <name>CPAR1</name>
        <addressOffset>0x14</addressOffset>
        <size>0x20</size>
        <fields>
          <field>
            <name>PA</name>
            <bitOffset>0</bitOffset>
            <bitWidth>32</bitWidth>
          </field>
        </fields>
      </register>
      <register>
        <name>CCR2</name>
        <addressOffset>0x1c</addressOffset>
        <size>0x20</size>
        <fields>
          <field>
            <name>EN</name>
            <bitOffset>0</bitOffset>
            <bitWidth>1</bitWidth>
          </field>
          <field>
            <name>TCIE</name>
            <bitOffset>1</bitOffset>
            <bitWidth>1</bitWidth>
          </field>
          <field>
            <name>HTIE</name>
            <bitOffset>2</bitOffset>
            <bitWidth>1</bitWidth>
          </field>
          <field>
            <name>TEIE</name>
            <bitOffset>3</bitOffset>
            <bitWidth>1</bitWidth>
          </field>
          <field>
            <name>DIR</name>
            <bitOffset>4</bitOffset>
            <bitWidth>1</bitWidth>
          </field>
          <field>
            <name>CIRC</name>
            <bitOffset>5</bitOffset>
            <bitWidth>1</bitWidth>
          </field>
          <field>
            <name>PINC</name>
            <bitOffset>6</bitOffset>
            <bitWidth>1</bitWidth>
          </field>
          <field>
            <name>MINC</name>
            <bitOffset>7</bitOffset>
            <bitWidth>1</bitWidth>
          </field>
          <field>
            <name>PSIZE</name>
            <bitOffset>8</bitOffset>
            <bitWidth>2</bitWidth>
          </field>
          <field>
            <name>MSIZE</name>
            <bitOffset>10</bitOffset>
            <bitWidth>2</bitWidth>
          </field>
          <field>
            <name>PL</name>
            <bitOffset>12</bitOffset>
            <bitWidth>2</bitWidth>
          </field>
          <field>
            <name>MEM2MEM</name>
            <bitOffset>14</bitOffset>
            <bitWidth>1</bitWidth>
          </field>
        </fields>
      </register>
      <register>
        <name>CCR2</name>
        <addressOffset>0x1c</addressOffset>
        <size>0x20</size>
        <fields>
          <field>
            <name>EN</name>
            <bitOffset>0</bitOffset>
            <bitWidth>1</bitWidth>
          </field>
          <field>
            <name>TCIE</name>
            <bitOffset>1</bitOffset>
            <bitWidth>1</bitWidth>
          </field>
          <field>
            <name>HTIE</name>
            <bitOffset>2</bitOffset>
            <bitWidth>1</bitWidth>
          </field>
          <field>
            <name>TEIE</name>
            <bitOffset>3</bitOffset>
            <bitWidth>1</bitWidth>
          </field>
          <field>
            <name>DIR</name>
            <bitOffset>4</bitOffset>
            <bitWidth>1</bitWidth>
          </field>
          <field>
            <name>CIRC</name>
            <bitOffset>5</bitOffset>
            <bitWidth>1</bitWidth>
          </field>
          <field>
            <name>PINC</name>
            <bitOffset>6</bitOffset>
            <bitWidth>1</bitWidth>
          </field>
          <field>
            <name>MINC</name>
            <bitOffset>7</bitOffset>
            <bitWidth>1</bitWidth>
          </field>
          <field>
            <name>PSIZE</name>
            <bitOffset>8</bitOffset>
            <bitWidth>2</bitWidth>
          </field>
          <field>
            <name>MSIZE</name>
            <bitOffset>10</bitOffset>
            <bitWidth>2</bitWidth>
          </field>
          <field>
            <name>PL</name>
            <bitOffset>12</bitOffset>
            <bitWidth>2</bitWidth>
          </field>
          <field>
            <name>MEM2MEM</name>
            <bitOffset>14</bitOffset>
            <bitWidth>1</bitWidth>
          </field>
        </fields>
      </register>
      <register>
        <name>CMAR1</name>
        <addressOffset>0x20</addressOffset>
        <size>0x20</size>
        <fields>
          <field>
            <name>MA</name>
            <bitOffset>0</bitOffset>
            <bitWidth>32</bitWidth>
          </field>
        </fields>
      </register>
      <register>
        <name>CNDTR2</name>
        <addressOffset>0x20</addressOffset>
        <size>0x20</size>
        <fields>
          <field>
            <name>NDT</name>
            <bitOffset>0</bitOffset>
            <bitWidth>16</bitWidth>
          </field>
        </fields>
      </register>
      <register>
        <name>CMAR1</name>
        <addressOffset>0x20</addressOffset>
        <size>0x20</size>
        <fields>
          <field>
            <name>MA</name>
            <bitOffset>0</bitOffset>
            <bitWidth>32</bitWidth>
          </field>
        </fields>
      </register>
      <register>
        <name>CNDTR2</name>
        <addressOffset>0x20</addressOffset>
        <size>0x20</size>
        <fields>
          <field>
            <name>NDT</name>
            <bitOffset>0</bitOffset>
            <bitWidth>16</bitWidth>
          </field>
        </fields>
      </register>
      <register>
        <name>CPAR2</name>
        <addressOffset>0x28</addressOffset>
        <size>0x20</size>
        <fields>
          <field>
            <name>PA</name>
            <bitOffset>0</bitOffset>
            <bitWidth>32</bitWidth>
          </field>
        </fields>
      </register>
      <register>
        <name>CPAR2</name>
        <addressOffset>0x28</addressOffset>
        <size>0x20</size>
        <fields>
          <field>
            <name>PA</name>
            <bitOffset>0</bitOffset>
            <bitWidth>32</bitWidth>
          </field>
        </fields>
      </register>
      <register>
        <name>CCR3</name>
        <addressOffset>0x30</addressOffset>
        <size>0x20</size>
        <fields>
          <field>
            <name>EN</name>
            <bitOffset>0</bitOffset>
            <bitWidth>1</bitWidth>
          </field>
          <field>
            <name>TCIE</name>
            <bitOffset>1</bitOffset>
            <bitWidth>1</bitWidth>
          </field>
          <field>
            <name>HTIE</name>
            <bitOffset>2</bitOffset>
            <bitWidth>1</bitWidth>
          </field>
          <field>
            <name>TEIE</name>
            <bitOffset>3</bitOffset>
            <bitWidth>1</bitWidth>
          </field>
          <field>
            <name>DIR</name>
            <bitOffset>4</bitOffset>
            <bitWidth>1</bitWidth>
          </field>
          <field>
            <name>CIRC</name>
            <bitOffset>5</bitOffset>
            <bitWidth>1</bitWidth>
          </field>
          <field>
            <name>PINC</name>
            <bitOffset>6</bitOffset>
            <bitWidth>1</bitWidth>
          </field>
          <field>
            <name>MINC</name>
            <bitOffset>7</bitOffset>
            <bitWidth>1</bitWidth>
          </field>
          <field>
            <name>PSIZE</name>
            <bitOffset>8</bitOffset>
            <bitWidth>2</bitWidth>
          </field>
          <field>
            <name>MSIZE</name>
            <bitOffset>10</bitOffset>
            <bitWidth>2</bitWidth>
          </field>
          <field>
            <name>PL</name>
            <bitOffset>12</bitOffset>
            <bitWidth>2</bitWidth>
          </field>
          <field>
            <name>MEM2MEM</name>
            <bitOffset>14</bitOffset>
            <bitWidth>1</bitWidth>
          </field>
        </fields>
      </register>
      <register>
        <name>CCR3</name>
        <addressOffset>0x30</addressOffset>
        <size>0x20</size>
        <fields>
          <field>
            <name>EN</name>
            <bitOffset>0</bitOffset>
            <bitWidth>1</bitWidth>
          </field>
          <field>
            <name>TCIE</name>
            <bitOffset>1</bitOffset>
            <bitWidth>1</bitWidth>
          </field>
          <field>
            <name>HTIE</name>
            <bitOffset>2</bitOffset>
            <bitWidth>1</bitWidth>
          </field>
          <field>
            <name>TEIE</name>
            <bitOffset>3</bitOffset>
            <bitWidth>1</bitWidth>
          </field>
          <field>
            <name>DIR</name>
            <bitOffset>4</bitOffset>
            <bitWidth>1</bitWidth>
          </field>
          <field>
            <name>CIRC</name>
            <bitOffset>5</bitOffset>
            <bitWidth>1</bitWidth>
          </field>
          <field>
            <name>PINC</name>
            <bitOffset>6</bitOffset>
            <bitWidth>1</bitWidth>
          </field>
          <field>
            <name>MINC</name>
            <bitOffset>7</bitOffset>
            <bitWidth>1</bitWidth>
          </field>
          <field>
            <name>PSIZE</name>
            <bitOffset>8</bitOffset>
            <bitWidth>2</bitWidth>
          </field>
          <field>
            <name>MSIZE</name>
            <bitOffset>10</bitOffset>
            <bitWidth>2</bitWidth>
          </field>
          <field>
            <name>PL</name>
            <bitOffset>12</bitOffset>
            <bitWidth>2</bitWidth>
          </field>
          <field>
            <name>MEM2MEM</name>
            <bitOffset>14</bitOffset>
            <bitWidth>1</bitWidth>
          </field>
        </fields>
      </register>
      <register>
        <name>CMAR2</name>
        <addressOffset>0x34</addressOffset>
        <size>0x20</size>
        <fields>
          <field>
            <name>MA</name>
            <bitOffset>0</bitOffset>
            <bitWidth>32</bitWidth>
          </field>
        </fields>
      </register>
      <register>
        <name>CNDTR3</name>
        <addressOffset>0x34</addressOffset>
        <size>0x20</size>
        <fields>
          <field>
            <name>NDT</name>
            <bitOffset>0</bitOffset>
            <bitWidth>16</bitWidth>
          </field>
        </fields>
      </register>
      <register>
        <name>CMAR2</name>
        <addressOffset>0x34</addressOffset>
        <size>0x20</size>
        <fields>
          <field>
            <name>MA</name>
            <bitOffset>0</bitOffset>
            <bitWidth>32</bitWidth>
          </field>
        </fields>
      </register>
      <register>
        <name>CNDTR3</name>
        <addressOffset>0x34</addressOffset>
        <size>0x20</size>
        <fields>
          <field>
            <name>NDT</name>
            <bitOffset>0</bitOffset>
            <bitWidth>16</bitWidth>
          </field>
        </fields>
      </register>
      <register>
        <name>CPAR3</name>
        <addressOffset>0x3c</addressOffset>
        <size>0x20</size>
        <fields>
          <field>
            <name>PA</name>
            <bitOffset>0</bitOffset>
            <bitWidth>32</bitWidth>
          </field>
        </fields>
      </register>
      <register>
        <name>CPAR3</name>
        <addressOffset>0x3c</addressOffset>
        <size>0x20</size>
        <fields>
          <field>
            <name>PA</name>
            <bitOffset>0</bitOffset>
            <bitWidth>32</bitWidth>
          </field>
        </fields>
      </register>
      <register>
        <name>CCR4</name>
        <addressOffset>0x44</addressOffset>
        <size>0x20</size>
        <fields>
          <field>
            <name>EN</name>
            <bitOffset>0</bitOffset>
            <bitWidth>1</bitWidth>
          </field>
          <field>
            <name>TCIE</name>
            <bitOffset>1</bitOffset>
            <bitWidth>1</bitWidth>
          </field>
          <field>
            <name>HTIE</name>
            <bitOffset>2</bitOffset>
            <bitWidth>1</bitWidth>
          </field>
          <field>
            <name>TEIE</name>
            <bitOffset>3</bitOffset>
            <bitWidth>1</bitWidth>
          </field>
          <field>
            <name>DIR</name>
            <bitOffset>4</bitOffset>
            <bitWidth>1</bitWidth>
          </field>
          <field>
            <name>CIRC</name>
            <bitOffset>5</bitOffset>
            <bitWidth>1</bitWidth>
          </field>
          <field>
            <name>PINC</name>
            <bitOffset>6</bitOffset>
            <bitWidth>1</bitWidth>
          </field>
          <field>
            <name>MINC</name>
            <bitOffset>7</bitOffset>
            <bitWidth>1</bitWidth>
          </field>
          <field>
            <name>PSIZE</name>
            <bitOffset>8</bitOffset>
            <bitWidth>2</bitWidth>
          </field>
          <field>
            <name>MSIZE</name>
            <bitOffset>10</bitOffset>
            <bitWidth>2</bitWidth>
          </field>
          <field>
            <name>PL</name>
            <bitOffset>12</bitOffset>
            <bitWidth>2</bitWidth>
          </field>
          <field>
            <name>MEM2MEM</name>
            <bitOffset>14</bitOffset>
            <bitWidth>1</bitWidth>
          </field>
        </fields>
      </register>
      <register>
        <name>CCR4</name>
        <addressOffset>0x44</addressOffset>
        <size>0x20</size>
        <fields>
          <field>
            <name>EN</name>
            <bitOffset>0</bitOffset>
            <bitWidth>1</bitWidth>
          </field>
          <field>
            <name>TCIE</name>
            <bitOffset>1</bitOffset>
            <bitWidth>1</bitWidth>
          </field>
          <field>
            <name>HTIE</name>
            <bitOffset>2</bitOffset>
            <bitWidth>1</bitWidth>
          </field>
          <field>
            <name>TEIE</name>
            <bitOffset>3</bitOffset>
            <bitWidth>1</bitWidth>
          </field>
          <field>
            <name>DIR</name>
            <bitOffset>4</bitOffset>
            <bitWidth>1</bitWidth>
          </field>
          <field>
            <name>CIRC</name>
            <bitOffset>5</bitOffset>
            <bitWidth>1</bitWidth>
          </field>
          <field>
            <name>PINC</name>
            <bitOffset>6</bitOffset>
            <bitWidth>1</bitWidth>
          </field>
          <field>
            <name>MINC</name>
            <bitOffset>7</bitOffset>
            <bitWidth>1</bitWidth>
          </field>
          <field>
            <name>PSIZE</name>
            <bitOffset>8</bitOffset>
            <bitWidth>2</bitWidth>
          </field>
          <field>
            <name>MSIZE</name>
            <bitOffset>10</bitOffset>
            <bitWidth>2</bitWidth>
          </field>
          <field>
            <name>PL</name>
            <bitOffset>12</bitOffset>
            <bitWidth>2</bitWidth>
          </field>
          <field>
            <name>MEM2MEM</name>
            <bitOffset>14</bitOffset>
            <bitWidth>1</bitWidth>
          </field>
        </fields>
      </register>
      <register>
        <name>CMAR3</name>
        <addressOffset>0x48</addressOffset>
        <size>0x20</size>
        <fields>
          <field>
            <name>MA</name>
            <bitOffset>0</bitOffset>
            <bitWidth>32</bitWidth>
          </field>
        </fields>
      </register>
      <register>
        <name>CNDTR4</name>
        <addressOffset>0x48</addressOffset>
        <size>0x20</size>
        <fields>
          <field>
            <name>NDT</name>
            <bitOffset>0</bitOffset>
            <bitWidth>16</bitWidth>
          </field>
        </fields>
      </register>
      <register>
        <name>CMAR3</name>
        <addressOffset>0x48</addressOffset>
        <size>0x20</size>
        <fields>
          <field>
            <name>MA</name>
            <bitOffset>0</bitOffset>
            <bitWidth>32</bitWidth>
          </field>
        </fields>
      </register>
      <register>
        <name>CNDTR4</name>
        <addressOffset>0x48</addressOffset>
        <size>0x20</size>
        <fields>
          <field>
            <name>NDT</name>
            <bitOffset>0</bitOffset>
            <bitWidth>16</bitWidth>
          </field>
        </fields>
      </register>
      <register>
        <name>CPAR4</name>
        <addressOffset>0x50</addressOffset>
        <size>0x20</size>
        <fields>
          <field>
            <name>PA</name>
            <bitOffset>0</bitOffset>
            <bitWidth>32</bitWidth>
          </field>
        </fields>
      </register>
      <register>
        <name>CPAR4</name>
        <addressOffset>0x50</addressOffset>
        <size>0x20</size>
        <fields>
          <field>
            <name>PA</name>
            <bitOffset>0</bitOffset>
            <bitWidth>32</bitWidth>
          </field>
        </fields>
      </register>
      <register>
        <name>CCR5</name>
        <addressOffset>0x58</addressOffset>
        <size>0x20</size>
        <fields>
          <field>
            <name>EN</name>
            <bitOffset>0</bitOffset>
            <bitWidth>1</bitWidth>
          </field>
          <field>
            <name>TCIE</name>
            <bitOffset>1</bitOffset>
            <bitWidth>1</bitWidth>
          </field>
          <field>
            <name>HTIE</name>
            <bitOffset>2</bitOffset>
            <bitWidth>1</bitWidth>
          </field>
          <field>
            <name>TEIE</name>
            <bitOffset>3</bitOffset>
            <bitWidth>1</bitWidth>
          </field>
          <field>
            <name>DIR</name>
            <bitOffset>4</bitOffset>
            <bitWidth>1</bitWidth>
          </field>
          <field>
            <name>CIRC</name>
            <bitOffset>5</bitOffset>
            <bitWidth>1</bitWidth>
          </field>
          <field>
            <name>PINC</name>
            <bitOffset>6</bitOffset>
            <bitWidth>1</bitWidth>
          </field>
          <field>
            <name>MINC</name>
            <bitOffset>7</bitOffset>
            <bitWidth>1</bitWidth>
          </field>
          <field>
            <name>PSIZE</name>
            <bitOffset>8</bitOffset>
            <bitWidth>2</bitWidth>
          </field>
          <field>
            <name>MSIZE</name>
            <bitOffset>10</bitOffset>
            <bitWidth>2</bitWidth>
          </field>
          <field>
            <name>PL</name>
            <bitOffset>12</bitOffset>
            <bitWidth>2</bitWidth>
          </field>
          <field>
            <name>MEM2MEM</name>
            <bitOffset>14</bitOffset>
            <bitWidth>1</bitWidth>
          </field>
        </fields>
      </register>
      <register>
        <name>CCR5</name>
        <addressOffset>0x58</addressOffset>
        <size>0x20</size>
        <fields>
          <field>
            <name>EN</name>
            <bitOffset>0</bitOffset>
            <bitWidth>1</bitWidth>
          </field>
          <field>
            <name>TCIE</name>
            <bitOffset>1</bitOffset>
            <bitWidth>1</bitWidth>
          </field>
          <field>
            <name>HTIE</name>
            <bitOffset>2</bitOffset>
            <bitWidth>1</bitWidth>
          </field>
          <field>
            <name>TEIE</name>
            <bitOffset>3</bitOffset>
            <bitWidth>1</bitWidth>
          </field>
          <field>
            <name>DIR</name>
            <bitOffset>4</bitOffset>
            <bitWidth>1</bitWidth>
          </field>
          <field>
            <name>CIRC</name>
            <bitOffset>5</bitOffset>
            <bitWidth>1</bitWidth>
          </field>
          <field>
            <name>PINC</name>
            <bitOffset>6</bitOffset>
            <bitWidth>1</bitWidth>
          </field>
          <field>
            <name>MINC</name>
            <bitOffset>7</bitOffset>
            <bitWidth>1</bitWidth>
          </field>
          <field>
            <name>PSIZE</name>
            <bitOffset>8</bitOffset>
            <bitWidth>2</bitWidth>
          </field>
          <field>
            <name>MSIZE</name>
            <bitOffset>10</bitOffset>
            <bitWidth>2</bitWidth>
          </field>
          <field>
            <name>PL</name>
            <bitOffset>12</bitOffset>
            <bitWidth>2</bitWidth>
          </field>
          <field>
            <name>MEM2MEM</name>
            <bitOffset>14</bitOffset>
            <bitWidth>1</bitWidth>
          </field>
        </fields>
      </register>
      <register>
        <name>CMAR4</name>
        <addressOffset>0x5c</addressOffset>
        <size>0x20</size>
        <fields>
          <field>
            <name>MA</name>
            <bitOffset>0</bitOffset>
            <bitWidth>32</bitWidth>
          </field>
        </fields>
      </register>
      <register>
        <name>CNDTR5</name>
        <addressOffset>0x5c</addressOffset>
        <size>0x20</size>
        <fields>
          <field>
            <name>NDT</name>
            <bitOffset>0</bitOffset>
            <bitWidth>16</bitWidth>
          </field>
        </fields>
      </register>
      <register>
        <name>CMAR4</name>
        <addressOffset>0x5c</addressOffset>
        <size>0x20</size>
        <fields>
          <field>
            <name>MA</name>
            <bitOffset>0</bitOffset>
            <bitWidth>32</bitWidth>
          </field>
        </fields>
      </register>
      <register>
        <name>CNDTR5</name>
        <addressOffset>0x5c</addressOffset>
        <size>0x20</size>
        <fields>
          <field>
            <name>NDT</name>
            <bitOffset>0</bitOffset>
            <bitWidth>16</bitWidth>
          </field>
        </fields>
      </register>
      <register>
        <name>CPAR5</name>
        <addressOffset>0x64</addressOffset>
        <size>0x20</size>
        <fields>
          <field>
            <name>PA</name>
            <bitOffset>0</bitOffset>
            <bitWidth>32</bitWidth>
          </field>
        </fields>
      </register>
      <register>
        <name>CPAR5</name>
        <addressOffset>0x64</addressOffset>
        <size>0x20</size>
        <fields>
          <field>
            <name>PA</name>
            <bitOffset>0</bitOffset>
            <bitWidth>32</bitWidth>
          </field>
        </fields>
      </register>
      <register>
        <name>CCR6</name>
        <addressOffset>0x6c</addressOffset>
        <size>0x20</size>
        <fields>
          <field>
            <name>EN</name>
            <bitOffset>0</bitOffset>
            <bitWidth>1</bitWidth>
          </field>
          <field>
            <name>TCIE</name>
            <bitOffset>1</bitOffset>
            <bitWidth>1</bitWidth>
          </field>
          <field>
            <name>HTIE</name>
            <bitOffset>2</bitOffset>
            <bitWidth>1</bitWidth>
          </field>
          <field>
            <name>TEIE</name>
            <bitOffset>3</bitOffset>
            <bitWidth>1</bitWidth>
          </field>
          <field>
            <name>DIR</name>
            <bitOffset>4</bitOffset>
            <bitWidth>1</bitWidth>
          </field>
          <field>
            <name>CIRC</name>
            <bitOffset>5</bitOffset>
            <bitWidth>1</bitWidth>
          </field>
          <field>
            <name>PINC</name>
            <bitOffset>6</bitOffset>
            <bitWidth>1</bitWidth>
          </field>
          <field>
            <name>MINC</name>
            <bitOffset>7</bitOffset>
            <bitWidth>1</bitWidth>
          </field>
          <field>
            <name>PSIZE</name>
            <bitOffset>8</bitOffset>
            <bitWidth>2</bitWidth>
          </field>
          <field>
            <name>MSIZE</name>
            <bitOffset>10</bitOffset>
            <bitWidth>2</bitWidth>
          </field>
          <field>
            <name>PL</name>
            <bitOffset>12</bitOffset>
            <bitWidth>2</bitWidth>
          </field>
          <field>
            <name>MEM2MEM</name>
            <bitOffset>14</bitOffset>
            <bitWidth>1</bitWidth>
          </field>
        </fields>
      </register>
      <register>
        <name>CCR6</name>
        <addressOffset>0x6c</addressOffset>
        <size>0x20</size>
        <fields>
          <field>
            <name>EN</name>
            <bitOffset>0</bitOffset>
            <bitWidth>1</bitWidth>
          </field>
          <field>
            <name>TCIE</name>
            <bitOffset>1</bitOffset>
            <bitWidth>1</bitWidth>
          </field>
          <field>
            <name>HTIE</name>
            <bitOffset>2</bitOffset>
            <bitWidth>1</bitWidth>
          </field>
          <field>
            <name>TEIE</name>
            <bitOffset>3</bitOffset>
            <bitWidth>1</bitWidth>
          </field>
          <field>
            <name>DIR</name>
            <bitOffset>4</bitOffset>
            <bitWidth>1</bitWidth>
          </field>
          <field>
            <name>CIRC</name>
            <bitOffset>5</bitOffset>
            <bitWidth>1</bitWidth>
          </field>
          <field>
            <name>PINC</name>
            <bitOffset>6</bitOffset>
            <bitWidth>1</bitWidth>
          </field>
          <field>
            <name>MINC</name>
            <bitOffset>7</bitOffset>
            <bitWidth>1</bitWidth>
          </field>
          <field>
            <name>PSIZE</name>
            <bitOffset>8</bitOffset>
            <bitWidth>2</bitWidth>
          </field>
          <field>
            <name>MSIZE</name>
            <bitOffset>10</bitOffset>
            <bitWidth>2</bitWidth>
          </field>
          <field>
            <name>PL</name>
            <bitOffset>12</bitOffset>
            <bitWidth>2</bitWidth>
          </field>
          <field>
            <name>MEM2MEM</name>
            <bitOffset>14</bitOffset>
            <bitWidth>1</bitWidth>
          </field>
        </fields>
      </register>
      <register>
        <name>CMAR5</name>
        <addressOffset>0x70</addressOffset>
        <size>0x20</size>
        <fields>
          <field>
            <name>MA</name>
            <bitOffset>0</bitOffset>
            <bitWidth>32</bitWidth>
          </field>
        </fields>
      </register>
      <register>
        <name>CNDTR6</name>
        <addressOffset>0x70</addressOffset>
        <size>0x20</size>
        <fields>
          <field>
            <name>NDT</name>
            <bitOffset>0</bitOffset>
            <bitWidth>16</bitWidth>
          </field>
        </fields>
      </register>
      <register>
        <name>CMAR5</name>
        <addressOffset>0x70</addressOffset>
        <size>0x20</size>
        <fields>
          <field>
            <name>MA</name>
            <bitOffset>0</bitOffset>
            <bitWidth>32</bitWidth>
          </field>
        </fields>
      </register>
      <register>
        <name>CNDTR6</name>
        <addressOffset>0x70</addressOffset>
        <size>0x20</size>
        <fields>
          <field>
            <name>NDT</name>
            <bitOffset>0</bitOffset>
            <bitWidth>16</bitWidth>
          </field>
        </fields>
      </register>
      <register>
        <name>CPAR6</name>
        <addressOffset>0x78</addressOffset>
        <size>0x20</size>
        <fields>
          <field>
            <name>PA</name>
            <bitOffset>0</bitOffset>
            <bitWidth>32</bitWidth>
          </field>
        </fields>
      </register>
      <register>
        <name>CPAR6</name>
        <addressOffset>0x78</addressOffset>
        <size>0x20</size>
        <fields>
          <field>
            <name>PA</name>
            <bitOffset>0</bitOffset>
            <bitWidth>32</bitWidth>
          </field>
        </fields>
      </register>
      <register>
        <name>CCR7</name>
        <addressOffset>0x80</addressOffset>
        <size>0x20</size>
        <fields>
          <field>
            <name>EN</name>
            <bitOffset>0</bitOffset>
            <bitWidth>1</bitWidth>
          </field>
          <field>
            <name>TCIE</name>
            <bitOffset>1</bitOffset>
            <bitWidth>1</bitWidth>
          </field>
          <field>
            <name>HTIE</name>
            <bitOffset>2</bitOffset>
            <bitWidth>1</bitWidth>
          </field>
          <field>
            <name>TEIE</name>
            <bitOffset>3</bitOffset>
            <bitWidth>1</bitWidth>
          </field>
          <field>
            <name>DIR</name>
            <bitOffset>4</bitOffset>
            <bitWidth>1</bitWidth>
          </field>
          <field>
            <name>CIRC</name>
            <bitOffset>5</bitOffset>
            <bitWidth>1</bitWidth>
          </field>
          <field>
            <name>PINC</name>
            <bitOffset>6</bitOffset>
            <bitWidth>1</bitWidth>
          </field>
          <field>
            <name>MINC</name>
            <bitOffset>7</bitOffset>
            <bitWidth>1</bitWidth>
          </field>
          <field>
            <name>PSIZE</name>
            <bitOffset>8</bitOffset>
            <bitWidth>2</bitWidth>
          </field>
          <field>
            <name>MSIZE</name>
            <bitOffset>10</bitOffset>
            <bitWidth>2</bitWidth>
          </field>
          <field>
            <name>PL</name>
            <bitOffset>12</bitOffset>
            <bitWidth>2</bitWidth>
          </field>
          <field>
            <name>MEM2MEM</name>
            <bitOffset>14</bitOffset>
            <bitWidth>1</bitWidth>
          </field>
        </fields>
      </register>
      <register>
        <name>CCR7</name>
        <addressOffset>0x80</addressOffset>
        <size>0x20</size>
        <fields>
          <field>
            <name>EN</name>
            <bitOffset>0</bitOffset>
            <bitWidth>1</bitWidth>
          </field>
          <field>
            <name>TCIE</name>
            <bitOffset>1</bitOffset>
            <bitWidth>1</bitWidth>
          </field>
          <field>
            <name>HTIE</name>
            <bitOffset>2</bitOffset>
            <bitWidth>1</bitWidth>
          </field>
          <field>
            <name>TEIE</name>
            <bitOffset>3</bitOffset>
            <bitWidth>1</bitWidth>
          </field>
          <field>
            <name>DIR</name>
            <bitOffset>4</bitOffset>
            <bitWidth>1</bitWidth>
          </field>
          <field>
            <name>CIRC</name>
            <bitOffset>5</bitOffset>
            <bitWidth>1</bitWidth>
          </field>
          <field>
            <name>PINC</name>
            <bitOffset>6</bitOffset>
            <bitWidth>1</bitWidth>
          </field>
          <field>
            <name>MINC</name>
            <bitOffset>7</bitOffset>
            <bitWidth>1</bitWidth>
          </field>
          <field>
            <name>PSIZE</name>
            <bitOffset>8</bitOffset>
            <bitWidth>2</bitWidth>
          </field>
          <field>
            <name>MSIZE</name>
            <bitOffset>10</bitOffset>
            <bitWidth>2</bitWidth>
          </field>
          <field>
            <name>PL</name>
            <bitOffset>12</bitOffset>
            <bitWidth>2</bitWidth>
          </field>
          <field>
            <name>MEM2MEM</name>
            <bitOffset>14</bitOffset>
            <bitWidth>1</bitWidth>
          </field>
        </fields>
      </register>
      <register>
        <name>CMAR6</name>
        <addressOffset>0x84</addressOffset>
        <size>0x20</size>
        <fields>
          <field>
            <name>MA</name>
            <bitOffset>0</bitOffset>
            <bitWidth>32</bitWidth>
          </field>
        </fields>
      </register>
      <register>
        <name>CNDTR7</name>
        <addressOffset>0x84</addressOffset>
        <size>0x20</size>
        <fields>
          <field>
            <name>NDT</name>
            <bitOffset>0</bitOffset>
            <bitWidth>16</bitWidth>
          </field>
        </fields>
      </register>
      <register>
        <name>CMAR6</name>
        <addressOffset>0x84</addressOffset>
        <size>0x20</size>
        <fields>
          <field>
            <name>MA</name>
            <bitOffset>0</bitOffset>
            <bitWidth>32</bitWidth>
          </field>
        </fields>
      </register>
      <register>
        <name>CNDTR7</name>
        <addressOffset>0x84</addressOffset>
        <size>0x20</size>
        <fields>
          <field>
            <name>NDT</name>
            <bitOffset>0</bitOffset>
            <bitWidth>16</bitWidth>
          </field>
        </fields>
      </register>
      <register>
        <name>CPAR7</name>
        <addressOffset>0x8c</addressOffset>
        <size>0x20</size>
        <fields>
          <field>
            <name>PA</name>
            <bitOffset>0</bitOffset>
            <bitWidth>32</bitWidth>
          </field>
        </fields>
      </register>
      <register>
        <name>CPAR7</name>
        <addressOffset>0x8c</addressOffset>
        <size>0x20</size>
        <fields>
          <field>
            <name>PA</name>
            <bitOffset>0</bitOffset>
            <bitWidth>32</bitWidth>
          </field>
        </fields>
      </register>
      <register>
        <name>CMAR7</name>
        <addressOffset>0x98</addressOffset>
        <size>0x20</size>
        <fields>
          <field>
            <name>MA</name>
            <bitOffset>0</bitOffset>
            <bitWidth>32</bitWidth>
          </field>
        </fields>
      </register>
      <register>
        <name>CMAR7</name>
        <addressOffset>0x98</addressOffset>
        <size>0x20</size>
        <fields>
          <field>
            <name>MA</name>
            <bitOffset>0</bitOffset>
            <bitWidth>32</bitWidth>
          </field>
        </fields>
      </register>
    </peripheral>
    <peripheral>
      <name>DMAMUX1</name>
      <baseAddress>0x40020800</baseAddress>
      <register>
        <name>CCR1</name>
        <addressOffset>0x4</addressOffset>
        <size>0x20</size>
      </register>
      <register>
        <name>CCR2</name>
        <addressOffset>0x8</addressOffset>
        <size>0x20</size>
      </register>
      <register>
        <name>CCR3</name>
        <addressOffset>0xc</addressOffset>
        <size>0x20</size>
      </register>
      <register>
        <name>CCR4</name>
        <addressOffset>0x10</addressOffset>
        <size>0x20</size>
      </register>
      <register>
        <name>CCR5</name>
        <addressOffset>0x14</addressOffset>
        <size>0x20</size>
      </register>
      <register>
        <name>CCR6</name>
        <addressOffset>0x18</addressOffset>
        <size>0x20</size>
      </register>
      <register>
        <name>CCR7</name>
        <addressOffset>0x1c</addressOffset>
        <size>0x20</size>
      </register>
      <register>
        <name>CCR8</name>
        <addressOffset>0x20</addressOffset>
        <size>0x20</size>
      </register>
      <register>
        <name>CCR9</name>
        <addressOffset>0x24</addressOffset>
        <size>0x20</size>
      </register>
      <register>
        <name>CCR0</name>
        <addressOffset>0x28</addressOffset>
        <size>0x20</size>
      </register>
      <register>
        <name>CCR1</name>
        <addressOffset>0x2c</addressOffset>
        <size>0x20</size>
      </register>
      <register>
        <name>CCR2</name>
        <addressOffset>0x30</addressOffset>
        <size>0x20</size>
      </register>
      <register>
        <name>CCR3</name>
        <addressOffset>0x34</addressOffset>
        <size>0x20</size>
      </register>
      <register>
        <name>CCRs</name>
        <addressOffset>0x80</addressOffset>
        <size>0x20</size>
      </register>
      <register>
        <name>CCR0</name>
        <addressOffset>0x100</addressOffset>
        <size>0x20</size>
      </register>
      <register>
        <name>CCR1</name>
        <addressOffset>0x104</addressOffset>
        <size>0x20</size>
      </register>
      <register>
        <name>CCR2</name>
        <addressOffset>0x108</addressOffset>
        <size>0x20</size>
      </register>
      <register>
        <name>CCR3</name>
        <addressOffset>0x10c</addressOffset>
        <size>0x20</size>
      </register>
      <register>
        <name>CCRs</name>
        <addressOffset>0x140</addressOffset>
        <size>0x20</size>
      </register>
    </peripheral>
    <peripheral>
      <name>RCC</name>
      <baseAddress>0x40021000</baseAddress>
      <register>
        <name>CR</name>
        <addressOffset>0x0</addressOffset>
        <size>0x20</size>
        <fields>
          <field>
            <name>MSION</name>
            <bitOffset>0</bitOffset>
            <bitWidth>1</bitWidth>
          </field>
          <field>
            <name>MSIRDY</name>
            <bitOffset>1</bitOffset>
            <bitWidth>1</bitWidth>
          </field>
          <field>
            <name>MSIPLLEN</name>
            <bitOffset>2</bitOffset>
            <bitWidth>1</bitWidth>
          </field>
          <field>
            <name>MSIRGSEL</name>
            <bitOffset>3</bitOffset>
            <bitWidth>1</bitWidth>
          </field>
          <field>
            <name>MSIRANGE</name>
            <bitOffset>4</bitOffset>
            <bitWidth>4</bitWidth>
          </field>
          <field>
            <name>HSION</name>
            <bitOffset>8</bitOffset>
            <bitWidth>1</bitWidth>
          </field>
          <field>
            <name>HSIKERON</name>
            <bitOffset>9</bitOffset>
            <bitWidth>1</bitWidth>
          </field>
          <field>
            <name>HSIRDY</name>
            <bitOffset>10</bitOffset>
            <bitWidth>1</bitWidth>
          </field>
          <field>
            <name>HSIASFS</name>
            <bitOffset>11</bitOffset>
            <bitWidth>1</bitWidth>
          </field>
          <field>
            <name>HSEON</name>
            <bitOffset>16</bitOffset>
            <bitWidth>1</bitWidth>
          </field>
          <field>
            <name>HSERDY</name>
            <bitOffset>17</bitOffset>
            <bitWidth>1</bitWidth>
          </field>
          <field>
            <name>HSEBYP</name>
            <bitOffset>18</bitOffset>
            <bitWidth>1</bitWidth>
          </field>
          <field>
            <name>CSSON</name>
            <bitOffset>19</bitOffset>
            <bitWidth>1</bitWidth>
          </field>
          <field>
            <name>PLLON</name>
            <bitOffset>24</bitOffset>
            <bitWidth>1</bitWidth>
          </field>
          <field>
            <name>PLLRDY</name>
            <bitOffset>25</bitOffset>
            <bitWidth>1</bitWidth>
          </field>
          <field>
            <name>PLLSAI1ON</name>
            <bitOffset>26</bitOffset>
            <bitWidth>1</bitWidth>
          </field>
          <field>
            <name>PLLSAI1RDY</name>
            <bitOffset>27</bitOffset>
            <bitWidth>1</bitWidth>
          </field>
          <field>
            <name>PLLSAI2ON</name>
            <bitOffset>28</bitOffset>
            <bitWidth>1</bitWidth>
          </field>
          <field>
            <name>PLLSAI2RDY</name>
            <bitOffset>29</bitOffset>
            <bitWidth>1</bitWidth>
          </field>
        </fields>
      </register>
      <register>
        <name>ICSCR</name>
        <addressOffset>0x4</addressOffset>
        <size>0x20</size>
        <fields>
          <field>
            <name>MSICAL</name>
            <bitOffset>0</bitOffset>
            <bitWidth>8</bitWidth>
          </field>
          <field>
            <name>MSITRIM</name>
            <bitOffset>8</bitOffset>
            <bitWidth>8</bitWidth>
          </field>
          <field>
            <name>HSICAL</name>
            <bitOffset>16</bitOffset>
            <bitWidth>8</bitWidth>
          </field>
          <field>
            <name>HSITRIM</name>
            <bitOffset>24</bitOffset>
            <bitWidth>7</bitWidth>
          </field>
        </fields>
      </register>
      <register>
        <name>CFGR</name>
        <addressOffset>0x8</addressOffset>
        <size>0x20</size>
        <fields>
          <field>
            <name>SW</name>
            <bitOffset>0</bitOffset>
            <bitWidth>2</bitWidth>
          </field>
          <field>
            <name>SWS</name>
            <bitOffset>2</bitOffset>
            <bitWidth>2</bitWidth>
          </field>
          <field>
            <name>HPRE</name>
            <bitOffset>4</bitOffset>
            <bitWidth>4</bitWidth>
          </field>
          <field>
            <name>PPRE1</name>
            <bitOffset>8</bitOffset>
            <bitWidth>3</bitWidth>
          </field>
          <field>
            <name>PPRE2</name>
            <bitOffset>11</bitOffset>
            <bitWidth>3</bitWidth>
          </field>
          <field>
            <name>STOPWUCK</name>
            <bitOffset>15</bitOffset>
            <bitWidth>1</bitWidth>
          </field>
          <field>
            <name>MCOSEL</name>
            <bitOffset>24</bitOffset>
            <bitWidth>4</bitWidth>
          </field>
          <field>
            <name>MCOPRE</name>
            <bitOffset>28</bitOffset>
            <bitWidth>3</bitWidth>
          </field>
        </fields>
      </register>
      <register>
        <name>PLLCFGR</name>
        <addressOffset>0xc</addressOffset>
        <size>0x20</size>
        <fields>
          <field>
            <name>PLLSRC_MSI</name>
            <bitOffset>0</bitOffset>
            <bitWidth>1</bitWidth>
          </field>
          <field>
            <name>PLLSRC_HSI</name>
            <bitOffset>1</bitOffset>
            <bitWidth>1</bitWidth>
          </field>
          <field>
            <name>PLLM</name>
            <bitOffset>4</bitOffset>
            <bitWidth>4</bitWidth>
          </field>
          <field>
            <name>PLLN</name>
            <bitOffset>8</bitOffset>
            <bitWidth>7</bitWidth>
          </field>
          <field>
            <name>PLLPEN</name>
            <bitOffset>16</bitOffset>
            <bitWidth>1</bitWidth>
          </field>
          <field>
            <name>PLLP</name>
            <bitOffset>17</bitOffset>
            <bitWidth>1</bitWidth>
          </field>
          <field>
            <name>PLLQEN</name>
            <bitOffset>20</bitOffset>
            <bitWidth>1</bitWidth>
          </field>
          <field>
            <name>PLLQ</name>
            <bitOffset>21</bitOffset>
            <bitWidth>2</bitWidth>
          </field>
          <field>
            <name>PLLREN</name>
            <bitOffset>24</bitOffset>
            <bitWidth>1</bitWidth>
          </field>
          <field>
            <name>PLLR</name>
            <bitOffset>25</bitOffset>
            <bitWidth>2</bitWidth>
          </field>
          <field>
            <name>PLLPDIV</name>
            <bitOffset>27</bitOffset>
            <bitWidth>5</bitWidth>
          </field>
        </fields>
      </register>
      <register>
        <name>PLLSAI1CFGR</name>
        <addressOffset>0x10</addressOffset>
        <size>0x20</size>
        <fields>
          <field>
            <name>PLLSAI1M</name>
            <bitOffset>4</bitOffset>
            <bitWidth>4</bitWidth>
          </field>
          <field>
            <name>PLLSAI1N</name>
            <bitOffset>8</bitOffset>
            <bitWidth>7</bitWidth>
          </field>
          <field>
            <name>PLLSAI1PEN</name>
            <bitOffset>16</bitOffset>
            <bitWidth>1</bitWidth>
          </field>
          <field>
            <name>PLLSAI1P</name>
            <bitOffset>17</bitOffset>
            <bitWidth>1</bitWidth>
          </field>
          <field>
            <name>PLLSAI1QEN</name>
            <bitOffset>20</bitOffset>
            <bitWidth>1</bitWidth>
          </field>
          <field>
            <name>PLLSAI1Q</name>
            <bitOffset>21</bitOffset>
            <bitWidth>2</bitWidth>
          </field>
          <field>
            <name>PLLSAI1REN</name>
            <bitOffset>24</bitOffset>
            <bitWidth>1</bitWidth>
          </field>
          <field>
            <name>PLLSAI1R</name>
            <bitOffset>25</bitOffset>
            <bitWidth>2</bitWidth>
          </field>
          <field>
            <name>PLLSAI1PDIV</name>
            <bitOffset>27</bitOffset>
            <bitWidth>5</bitWidth>
          </field>
        </fields>
      </register>
      <register>
        <name>PLLSAI2CFGR</name>
        <addressOffset>0x14</addressOffset>
        <size>0x20</size>
        <fields>
          <field>
            <name>PLLSAI2M</name>
            <bitOffset>4</bitOffset>
            <bitWidth>4</bitWidth>
          </field>
          <field>
            <name>PLLSAI2N</name>
            <bitOffset>8</bitOffset>
            <bitWidth>7</bitWidth>
          </field>
          <field>
            <name>PLLSAI2PEN</name>
            <bitOffset>16</bitOffset>
            <bitWidth>1</bitWidth>
          </field>
          <field>
            <name>PLLSAI2P</name>
            <bitOffset>17</bitOffset>
            <bitWidth>1</bitWidth>
          </field>
          <field>
            <name>PLLSAI2QEN</name>
            <bitOffset>20</bitOffset>
            <bitWidth>1</bitWidth>
          </field>
          <field>
            <name>PLLSAI2Q</name>
            <bitOffset>21</bitOffset>
            <bitWidth>2</bitWidth>
          </field>
          <field>
            <name>PLLSAI2REN</name>
            <bitOffset>24</bitOffset>
            <bitWidth>1</bitWidth>
          </field>
          <field>
            <name>PLLSAI2R</name>
            <bitOffset>25</bitOffset>
            <bitWidth>2</bitWidth>
          </field>
          <field>
            <name>PLLSAI2PDIV</name>
            <bitOffset>27</bitOffset>
            <bitWidth>5</bitWidth>
          </field>
        </fields>
      </register>
      <register>
        <name>CIER</name>
        <addressOffset>0x18</addressOffset>
        <size>0x20</size>
        <fields>
          <field>
            <name>LSIRDYIE</name>
            <bitOffset>0</bitOffset>
            <bitWidth>1</bitWidth>
          </field>
          <field>
            <name>LSERDYIE</name>
            <bitOffset>1</bitOffset>
            <bitWidth>1</bitWidth>
          </field>
          <field>
            <name>MSIRDYIE</name>
            <bitOffset>2</bitOffset>
            <bitWidth>1</bitWidth>
          </field>
          <field>
            <name>HSIRDYIE</name>
            <bitOffset>3</bitOffset>
            <bitWidth>1</bitWidth>
          </field>
          <field>
            <name>HSERDYIE</name>
            <bitOffset>4</bitOffset>
            <bitWidth>1</bitWidth>
          </field>
          <field>
            <name>PLLRDYIE</name>
            <bitOffset>5</bitOffset>
            <bitWidth>1</bitWidth>
          </field>
          <field>
            <name>PLLSAI1RDYIE</name>
            <bitOffset>6</bitOffset>
            <bitWidth>1</bitWidth>
          </field>
          <field>
            <name>PLLSAI2RDYIE</name>
            <bitOffset>7</bitOffset>
            <bitWidth>1</bitWidth>
          </field>
          <field>
            <name>LSECSSIE</name>
            <bitOffset>9</bitOffset>
            <bitWidth>1</bitWidth>
          </field>
          <field>
            <name>HSI48RDYIE</name>
            <bitOffset>10</bitOffset>
            <bitWidth>1</bitWidth>
          </field>
        </fields>
      </register>
      <register>
        <name>CIFR</name>
        <addressOffset>0x1c</addressOffset>
        <size>0x20</size>
        <fields>
          <field>
            <name>LSIRDYF</name>
            <bitOffset>0</bitOffset>
            <bitWidth>1</bitWidth>
          </field>
          <field>
            <name>LSERDYF</name>
            <bitOffset>1</bitOffset>
            <bitWidth>1</bitWidth>
          </field>
          <field>
            <name>MSIRDYF</name>
            <bitOffset>2</bitOffset>
            <bitWidth>1</bitWidth>
          </field>
          <field>
            <name>HSIRDYF</name>
            <bitOffset>3</bitOffset>
            <bitWidth>1</bitWidth>
          </field>
          <field>
            <name>HSERDYF</name>
            <bitOffset>4</bitOffset>
            <bitWidth>1</bitWidth>
          </field>
          <field>
            <name>PLLRDYF</name>
            <bitOffset>5</bitOffset>
            <bitWidth>1</bitWidth>
          </field>
          <field>
            <name>PLLSAI1RDYF</name>
            <bitOffset>6</bitOffset>
            <bitWidth>1</bitWidth>
          </field>
          <field>
            <name>PLLSAI2RDYF</name>
            <bitOffset>7</bitOffset>
            <bitWidth>1</bitWidth>
          </field>
          <field>
            <name>CSSF</name>
            <bitOffset>8</bitOffset>
            <bitWidth>1</bitWidth>
          </field>
          <field>
            <name>LSECSSF</name>
            <bitOffset>9</bitOffset>
            <bitWidth>1</bitWidth>
          </field>
          <field>
            <name>HSI48RDYF</name>
            <bitOffset>10</bitOffset>
            <bitWidth>1</bitWidth>
          </field>
        </fields>
      </register>
      <register>
        <name>CICR</name>
        <addressOffset>0x20</addressOffset>
        <size>0x20</size>
        <fields>
          <field>
            <name>LSIRDYC</name>
            <bitOffset>0</bitOffset>
            <bitWidth>1</bitWidth>
          </field>
          <field>
            <name>LSERDYC</name>
            <bitOffset>1</bitOffset>
            <bitWidth>1</bitWidth>
          </field>
          <field>
            <name>MSIRDYC</name>
            <bitOffset>2</bitOffset>
            <bitWidth>1</bitWidth>
          </field>
          <field>
            <name>HSIRDYC</name>
            <bitOffset>3</bitOffset>
            <bitWidth>1</bitWidth>
          </field>
          <field>
            <name>HSERDYC</name>
            <bitOffset>4</bitOffset>
            <bitWidth>1</bitWidth>
          </field>
          <field>
            <name>PLLRDYC</name>
            <bitOffset>5</bitOffset>
            <bitWidth>1</bitWidth>
          </field>
          <field>
            <name>PLLSAI1RDYC</name>
            <bitOffset>6</bitOffset>
            <bitWidth>1</bitWidth>
          </field>
          <field>
            <name>PLLSAI2RDYC</name>
            <bitOffset>7</bitOffset>
            <bitWidth>1</bitWidth>
          </field>
          <field>
            <name>CSSC</name>
            <bitOffset>8</bitOffset>
            <bitWidth>1</bitWidth>
          </field>
          <field>
            <name>LSECSSC</name>
            <bitOffset>9</bitOffset>
            <bitWidth>1</bitWidth>
          </field>
          <field>
            <name>HSI48RDYC</name>
            <bitOffset>10</bitOffset>
            <bitWidth>1</bitWidth>
          </field>
        </fields>
      </register>
      <register>
        <name>AHB1RSTR</name>
        <addressOffset>0x28</addressOffset>
        <size>0x20</size>
        <fields>
          <field>
            <name>DMA1RST</name>
            <bitOffset>0</bitOffset>
            <bitWidth>1</bitWidth>
          </field>
          <field>
            <name>DMA2RST</name>
            <bitOffset>1</bitOffset>
            <bitWidth>1</bitWidth>
          </field>
          <field>
            <name>DMAMUX1RST</name>
            <bitOffset>2</bitOffset>
            <bitWidth>1</bitWidth>
          </field>
          <field>
            <name>FLASHRST</name>
            <bitOffset>8</bitOffset>
            <bitWidth>1</bitWidth>
          </field>
          <field>
            <name>CRCRST</name>
            <bitOffset>12</bitOffset>
            <bitWidth>1</bitWidth>
          </field>
          <field>
            <name>TSCRST</name>
            <bitOffset>16</bitOffset>
            <bitWidth>1</bitWidth>
          </field>
          <field>
            <name>DMA2DRST</name>
            <bitOffset>17</bitOffset>
            <bitWidth>1</bitWidth>
          </field>
        </fields>
      </register>
      <register>
        <name>AHB2RSTR</name>
        <addressOffset>0x2c</addressOffset>
        <size>0x20</size>
        <fields>
          <field>
            <name>GPIOARST</name>
            <bitOffset>0</bitOffset>
            <bitWidth>1</bitWidth>
          </field>
          <field>
            <name>GPIOBRST</name>
            <bitOffset>1</bitOffset>
            <bitWidth>1</bitWidth>
          </field>
          <field>
            <name>GPIOCRST</name>
            <bitOffset>2</bitOffset>
            <bitWidth>1</bitWidth>
          </field>
          <field>
            <name>GPIODRST</name>
            <bitOffset>3</bitOffset>
            <bitWidth>1</bitWidth>
          </field>
          <field>
            <name>GPIOERST</name>
            <bitOffset>4</bitOffset>
            <bitWidth>1</bitWidth>
          </field>
          <field>
            <name>GPIOFRST</name>
            <bitOffset>5</bitOffset>
            <bitWidth>1</bitWidth>
          </field>
          <field>
            <name>GPIOGRST</name>
            <bitOffset>6</bitOffset>
            <bitWidth>1</bitWidth>
          </field>
          <field>
            <name>GPIOHRST</name>
            <bitOffset>7</bitOffset>
            <bitWidth>1</bitWidth>
          </field>
          <field>
            <name>GPIOIRST</name>
            <bitOffset>8</bitOffset>
            <bitWidth>1</bitWidth>
          </field>
          <field>
            <name>OTGFSRST</name>
            <bitOffset>12</bitOffset>
            <bitWidth>1</bitWidth>
          </field>
          <field>
            <name>ADCRST</name>
            <bitOffset>13</bitOffset>
            <bitWidth>1</bitWidth>
          </field>
          <field>
            <name>DCMIRST</name>
            <bitOffset>14</bitOffset>
            <bitWidth>1</bitWidth>
          </field>
          <field>
            <name>HASHRST</name>
            <bitOffset>17</bitOffset>
            <bitWidth>1</bitWidth>
          </field>
          <field>
            <name>RNGRST</name>
            <bitOffset>18</bitOffset>
            <bitWidth>1</bitWidth>
          </field>
          <field>
            <name>OSPIMRST</name>
            <bitOffset>20</bitOffset>
            <bitWidth>1</bitWidth>
          </field>
          <field>
            <name>SDMMC1RST</name>
            <bitOffset>22</bitOffset>
            <bitWidth>1</bitWidth>
          </field>
          <field>
            <name>SDMMC2RST</name>
            <bitOffset>23</bitOffset>
            <bitWidth>1</bitWidth>
          </field>
        </fields>
      </register>
      <register>
        <name>AHB3RSTR</name>
        <addressOffset>0x30</addressOffset>
        <size>0x20</size>
        <fields>
          <field>
            <name>FMCRST</name>
            <bitOffset>0</bitOffset>
            <bitWidth>1</bitWidth>
          </field>
          <field>
            <name>OSPI1RST</name>
            <bitOffset>8</bitOffset>
            <bitWidth>1</bitWidth>
          </field>
          <field>
            <name>OSPI2RST</name>
            <bitOffset>9</bitOffset>
            <bitWidth>1</bitWidth>
          </field>
        </fields>
      </register>
      <register>
        <name>APB1RSTR1</name>
        <addressOffset>0x38</addressOffset>
        <size>0x20</size>
        <fields>
          <field>
            <name>TIM2RST</name>
            <bitOffset>0</bitOffset>
            <bitWidth>1</bitWidth>
          </field>
          <field>
            <name>TIM3RST</name>
            <bitOffset>1</bitOffset>
            <bitWidth>1</bitWidth>
          </field>
          <field>
            <name>TIM4RST</name>
            <bitOffset>2</bitOffset>
            <bitWidth>1</bitWidth>
          </field>
          <field>
            <name>TIM5RST</name>
            <bitOffset>3</bitOffset>
            <bitWidth>1</bitWidth>
          </field>
          <field>
            <name>TIM6RST</name>
            <bitOffset>4</bitOffset>
            <bitWidth>1</bitWidth>
          </field>
          <field>
            <name>TIM7RST</name>
            <bitOffset>5</bitOffset>
            <bitWidth>1</bitWidth>
          </field>
          <field>
            <name>SPI2RST</name>
            <bitOffset>14</bitOffset>
            <bitWidth>1</bitWidth>
          </field>
          <field>
            <name>SPI3RST</name>
            <bitOffset>15</bitOffset>
            <bitWidth>1</bitWidth>
          </field>
          <field>
            <name>USART2RST</name>
            <bitOffset>17</bitOffset>
            <bitWidth>1</bitWidth>
          </field>
          <field>
            <name>USART3RST</name>
            <bitOffset>18</bitOffset>
            <bitWidth>1</bitWidth>
          </field>
          <field>
            <name>UART4RST</name>
            <bitOffset>19</bitOffset>
            <bitWidth>1</bitWidth>
          </field>
          <field>
            <name>UART5RST</name>
            <bitOffset>20</bitOffset>
            <bitWidth>1</bitWidth>
          </field>
          <field>
            <name>I2C1RST</name>
            <bitOffset>21</bitOffset>
            <bitWidth>1</bitWidth>
          </field>
          <field>
            <name>I2C2RST</name>
            <bitOffset>22</bitOffset>
            <bitWidth>1</bitWidth>
          </field>
          <field>
            <name>I2C3RST</name>
            <bitOffset>23</bitOffset>
            <bitWidth>1</bitWidth>
          </field>
          <field>
            <name>CRSRST</name>
            <bitOffset>24</bitOffset>
            <bitWidth>1</bitWidth>
          </field>
          <field>
            <name>CAN1RST</name>
            <bitOffset>25</bitOffset>
            <bitWidth>1</bitWidth>
          </field>
          <field>
            <name>PWRRST</name>
            <bitOffset>28</bitOffset>
            <bitWidth>1</bitWidth>
          </field>
          <field>
            <name>DAC1RST</name>
            <bitOffset>29</bitOffset>
            <bitWidth>1</bitWidth>
          </field>
          <field>
            <name>OPAMPRST</name>
            <bitOffset>30</bitOffset>
            <bitWidth>1</bitWidth>
          </field>
          <field>
            <name>LPTIM1RST</name>
            <bitOffset>31</bitOffset>
            <bitWidth>1</bitWidth>
          </field>
        </fields>
      </register>
      <register>
        <name>APB1RSTR2</name>
        <addressOffset>0x3c</addressOffset>
        <size>0x20</size>
        <fields>
          <field>
            <name>LPUART1RST</name>
            <bitOffset>0</bitOffset>
            <bitWidth>1</bitWidth>
          </field>
          <field>
            <name>I2C4RST</name>
            <bitOffset>1</bitOffset>
            <bitWidth>1</bitWidth>
          </field>
          <field>
            <name>LPTIM2RST</name>
            <bitOffset>5</bitOffset>
            <bitWidth>1</bitWidth>
          </field>
        </fields>
      </register>
      <register>
        <name>APB2RSTR</name>
        <addressOffset>0x40</addressOffset>
        <size>0x20</size>
        <fields>
          <field>
            <name>SYSCFGRST</name>
            <bitOffset>0</bitOffset>
            <bitWidth>1</bitWidth>
          </field>
          <field>
            <name>TIM1RST</name>
            <bitOffset>11</bitOffset>
            <bitWidth>1</bitWidth>
          </field>
          <field>
            <name>SPI1RST</name>
            <bitOffset>12</bitOffset>
            <bitWidth>1</bitWidth>
          </field>
          <field>
            <name>TIM8RST</name>
            <bitOffset>13</bitOffset>
            <bitWidth>1</bitWidth>
          </field>
          <field>
            <name>USART1RST</name>
            <bitOffset>14</bitOffset>
            <bitWidth>1</bitWidth>
          </field>
          <field>
            <name>TIM15RST</name>
            <bitOffset>16</bitOffset>
            <bitWidth>1</bitWidth>
          </field>
          <field>
            <name>TIM16RST</name>
            <bitOffset>17</bitOffset>
            <bitWidth>1</bitWidth>
          </field>
          <field>
            <name>TIM17RST</name>
            <bitOffset>18</bitOffset>
            <bitWidth>1</bitWidth>
          </field>
          <field>
            <name>SAI1RST</name>
            <bitOffset>21</bitOffset>
            <bitWidth>1</bitWidth>
          </field>
          <field>
            <name>SAI2RST</name>
            <bitOffset>22</bitOffset>
            <bitWidth>1</bitWidth>
          </field>
          <field>
            <name>DFSDM1RST</name>
            <bitOffset>24</bitOffset>
            <bitWidth>1</bitWidth>
          </field>
          <field>
            <name>LTDCRST</name>
            <bitOffset>26</bitOffset>
            <bitWidth>1</bitWidth>
          </field>
        </fields>
      </register>
      <register>
        <name>AHB1ENR</name>
        <addressOffset>0x48</addressOffset>
        <size>0x20</size>
        <fields>
          <field>
            <name>DMA1EN</name>
            <bitOffset>0</bitOffset>
            <bitWidth>1</bitWidth>
          </field>
          <field>
            <name>DMA2EN</name>
            <bitOffset>1</bitOffset>
            <bitWidth>1</bitWidth>
          </field>
          <field>
            <name>DMAMUX1EN</name>
            <bitOffset>2</bitOffset>
            <bitWidth>1</bitWidth>
          </field>
          <field>
            <name>FLASHEN</name>
            <bitOffset>8</bitOffset>
            <bitWidth>1</bitWidth>
          </field>
          <field>
            <name>CRCEN</name>
            <bitOffset>12</bitOffset>
            <bitWidth>1</bitWidth>
          </field>
          <field>
            <name>TSCEN</name>
            <bitOffset>16</bitOffset>
            <bitWidth>1</bitWidth>
          </field>
          <field>
            <name>DMA2DEN</name>
            <bitOffset>17</bitOffset>
            <bitWidth>1</bitWidth>
          </field>
        </fields>
      </register>
      <register>
        <name>AHB2ENR</name>
        <addressOffset>0x4c</addressOffset>
        <size>0x20</size>
        <fields>
          <field>
            <name>GPIOAEN</name>
            <bitOffset>0</bitOffset>
            <bitWidth>1</bitWidth>
          </field>
          <field>
            <name>GPIOBEN</name>
            <bitOffset>1</bitOffset>
            <bitWidth>1</bitWidth>
          </field>
          <field>
            <name>GPIOCEN</name>
            <bitOffset>2</bitOffset>
            <bitWidth>1</bitWidth>
          </field>
          <field>
            <name>GPIODEN</name>
            <bitOffset>3</bitOffset>
            <bitWidth>1</bitWidth>
          </field>
          <field>
            <name>GPIOEEN</name>
            <bitOffset>4</bitOffset>
            <bitWidth>1</bitWidth>
          </field>
          <field>
            <name>GPIOFEN</name>
            <bitOffset>5</bitOffset>
            <bitWidth>1</bitWidth>
          </field>
          <field>
            <name>GPIOGEN</name>
            <bitOffset>6</bitOffset>
            <bitWidth>1</bitWidth>
          </field>
          <field>
            <name>GPIOHEN</name>
            <bitOffset>7</bitOffset>
            <bitWidth>1</bitWidth>
          </field>
          <field>
            <name>GPIOIEN</name>
            <bitOffset>8</bitOffset>
            <bitWidth>1</bitWidth>
          </field>
          <field>
            <name>OTGFSEN</name>
            <bitOffset>12</bitOffset>
            <bitWidth>1</bitWidth>
          </field>
          <field>
            <name>ADCEN</name>
            <bitOffset>13</bitOffset>
            <bitWidth>1</bitWidth>
          </field>
          <field>
            <name>DCMIEN</name>
            <bitOffset>14</bitOffset>
            <bitWidth>1</bitWidth>
          </field>
          <field>
            <name>HASHEN</name>
            <bitOffset>17</bitOffset>
            <bitWidth>1</bitWidth>
          </field>
          <field>
            <name>RNGEN</name>
            <bitOffset>18</bitOffset>
            <bitWidth>1</bitWidth>
          </field>
          <field>
            <name>OSPIMEN</name>
            <bitOffset>20</bitOffset>
            <bitWidth>1</bitWidth>
          </field>
          <field>
            <name>SDMMC1EN</name>
            <bitOffset>22</bitOffset>
            <bitWidth>1</bitWidth>
          </field>
          <field>
            <name>SDMMC2EN</name>
            <bitOffset>23</bitOffset>
            <bitWidth>1</bitWidth>
          </field>
        </fields>
      </register>
      <register>
        <name>AHB3ENR</name>
        <addressOffset>0x50</addressOffset>
        <size>0x20</size>
        <fields>
          <field>
            <name>FMCEN</name>
            <bitOffset>0</bitOffset>
            <bitWidth>1</bitWidth>
          </field>
          <field>
            <name>OSPI1EN</name>
            <bitOffset>8</bitOffset>
            <bitWidth>1</bitWidth>
          </field>
          <field>
            <name>OSPI2EN</name>
            <bitOffset>9</bitOffset>
            <bitWidth>1</bitWidth>
          </field>
        </fields>
      </register>
      <register>
        <name>APB1ENR1</name>
        <addressOffset>0x58</addressOffset>
        <size>0x20</size>
        <fields>
          <field>
            <name>TIM2EN</name>
            <bitOffset>0</bitOffset>
            <bitWidth>1</bitWidth>
          </field>
          <field>
            <name>TIM3EN</name>
            <bitOffset>1</bitOffset>
            <bitWidth>1</bitWidth>
          </field>
          <field>
            <name>TIM4EN</name>
            <bitOffset>2</bitOffset>
            <bitWidth>1</bitWidth>
          </field>
          <field>
            <name>TIM5EN</name>
            <bitOffset>3</bitOffset>
            <bitWidth>1</bitWidth>
          </field>
          <field>
            <name>TIM6EN</name>
            <bitOffset>4</bitOffset>
            <bitWidth>1</bitWidth>
          </field>
          <field>
            <name>TIM7EN</name>
            <bitOffset>5</bitOffset>
            <bitWidth>1</bitWidth>
          </field>
          <field>
            <name>RTCAPBEN</name>
            <bitOffset>10</bitOffset>
            <bitWidth>1</bitWidth>
          </field>
          <field>
            <name>WWDGEN</name>
            <bitOffset>11</bitOffset>
            <bitWidth>1</bitWidth>
          </field>
          <field>
            <name>SPI2EN</name>
            <bitOffset>14</bitOffset>
            <bitWidth>1</bitWidth>
          </field>
          <field>
            <name>SPI3EN</name>
            <bitOffset>15</bitOffset>
            <bitWidth>1</bitWidth>
          </field>
          <field>
            <name>USART2EN</name>
            <bitOffset>17</bitOffset>
            <bitWidth>1</bitWidth>
          </field>
          <field>
            <name>USART3EN</name>
            <bitOffset>18</bitOffset>
            <bitWidth>1</bitWidth>
          </field>
          <field>
            <name>UART4EN</name>
            <bitOffset>19</bitOffset>
            <bitWidth>1</bitWidth>
          </field>
          <field>
            <name>UART5EN</name>
            <bitOffset>20</bitOffset>
            <bitWidth>1</bitWidth>
          </field>
          <field>
            <name>I2C1EN</name>
            <bitOffset>21</bitOffset>
            <bitWidth>1</bitWidth>
          </field>
          <field>
            <name>I2C2EN</name>
            <bitOffset>22</bitOffset>
            <bitWidth>1</bitWidth>
          </field>
          <field>
            <name>I2C3EN</name>
            <bitOffset>23</bitOffset>
            <bitWidth>1</bitWidth>
          </field>
          <field>
            <name>CRSEN</name>
            <bitOffset>24</bitOffset>
            <bitWidth>1</bitWidth>
          </field>
          <field>
            <name>CAN1EN</name>
            <bitOffset>25</bitOffset>
            <bitWidth>1</bitWidth>
          </field>
          <field>
            <name>PWREN</name>
            <bitOffset>28</bitOffset>
            <bitWidth>1</bitWidth>
          </field>
          <field>
            <name>DAC1EN</name>
            <bitOffset>29</bitOffset>
            <bitWidth>1</bitWidth>
          </field>
          <field>
            <name>OPAMPEN</name>
            <bitOffset>30</bitOffset>
            <bitWidth>1</bitWidth>
          </field>
          <field>
            <name>LPTIM1EN</name>
            <bitOffset>31</bitOffset>
            <bitWidth>1</bitWidth>
          </field>
        </fields>
      </register>
      <register>
        <name>APB1ENR2</name>
        <addressOffset>0x5c</addressOffset>
        <size>0x20</size>
        <fields>
          <field>
            <name>LPUART1EN</name>
            <bitOffset>0</bitOffset>
            <bitWidth>1</bitWidth>
          </field>
          <field>
            <name>I2C4EN</name>
            <bitOffset>1</bitOffset>
            <bitWidth>1</bitWidth>
          </field>
          <field>
            <name>LPTIM2EN</name>
            <bitOffset>5</bitOffset>
            <bitWidth>1</bitWidth>
          </field>
        </fields>
      </register>
      <register>
        <name>APB2ENR</name>
        <addressOffset>0x60</addressOffset>
        <size>0x20</size>
        <fields>
          <field>
            <name>SYSCFGEN</name>
            <bitOffset>0</bitOffset>
            <bitWidth>1</bitWidth>
          </field>
          <field>
            <name>FWEN</name>
            <bitOffset>7</bitOffset>
            <bitWidth>1</bitWidth>
          </field>
          <field>
            <name>TIM1EN</name>
            <bitOffset>11</bitOffset>
            <bitWidth>1</bitWidth>
          </field>
          <field>
            <name>SPI1EN</name>
            <bitOffset>12</bitOffset>
            <bitWidth>1</bitWidth>
          </field>
          <field>
            <name>TIM8EN</name>
            <bitOffset>13</bitOffset>
            <bitWidth>1</bitWidth>
          </field>
          <field>
            <name>USART1EN</name>
            <bitOffset>14</bitOffset>
            <bitWidth>1</bitWidth>
          </field>
          <field>
            <name>TIM15EN</name>
            <bitOffset>16</bitOffset>
            <bitWidth>1</bitWidth>
          </field>
          <field>
            <name>TIM16EN</name>
            <bitOffset>17</bitOffset>
            <bitWidth>1</bitWidth>
          </field>
          <field>
            <name>TIM17EN</name>
            <bitOffset>18</bitOffset>
            <bitWidth>1</bitWidth>
          </field>
          <field>
            <name>SAI1EN</name>
            <bitOffset>21</bitOffset>
            <bitWidth>1</bitWidth>
          </field>
          <field>
            <name>SAI2EN</name>
            <bitOffset>22</bitOffset>
            <bitWidth>1</bitWidth>
          </field>
          <field>
            <name>DFSDM1EN</name>
            <bitOffset>24</bitOffset>
            <bitWidth>1</bitWidth>
          </field>
          <field>
            <name>LTDCEN</name>
            <bitOffset>26</bitOffset>
            <bitWidth>1</bitWidth>
          </field>
        </fields>
      </register>
      <register>
        <name>AHB1SMENR</name>
        <addressOffset>0x68</addressOffset>
        <size>0x20</size>
        <fields>
          <field>
            <name>DMA1SMEN</name>
            <bitOffset>0</bitOffset>
            <bitWidth>1</bitWidth>
          </field>
          <field>
            <name>DMA2SMEN</name>
            <bitOffset>1</bitOffset>
            <bitWidth>1</bitWidth>
          </field>
          <field>
            <name>DMAMUX1SMEN</name>
            <bitOffset>2</bitOffset>
            <bitWidth>1</bitWidth>
          </field>
          <field>
            <name>FLASHSMEN</name>
            <bitOffset>8</bitOffset>
            <bitWidth>1</bitWidth>
          </field>
          <field>
            <name>SRAM1SMEN</name>
            <bitOffset>9</bitOffset>
            <bitWidth>1</bitWidth>
          </field>
          <field>
            <name>CRCSMEN</name>
            <bitOffset>12</bitOffset>
            <bitWidth>1</bitWidth>
          </field>
          <field>
            <name>TSCSMEN</name>
            <bitOffset>16</bitOffset>
            <bitWidth>1</bitWidth>
          </field>
          <field>
            <name>DMA2DSMEN</name>
            <bitOffset>17</bitOffset>
            <bitWidth>1</bitWidth>
          </field>
        </fields>
      </register>
      <register>
        <name>AHB2SMENR</name>
        <addressOffset>0x6c</addressOffset>
        <size>0x20</size>
        <fields>
          <field>
            <name>GPIOASMEN</name>
            <bitOffset>0</bitOffset>
            <bitWidth>1</bitWidth>
          </field>
          <field>
            <name>GPIOBSMEN</name>
            <bitOffset>1</bitOffset>
            <bitWidth>1</bitWidth>
          </field>
          <field>
            <name>GPIOCSMEN</name>
            <bitOffset>2</bitOffset>
            <bitWidth>1</bitWidth>
          </field>
          <field>
            <name>GPIODSMEN</name>
            <bitOffset>3</bitOffset>
            <bitWidth>1</bitWidth>
          </field>
          <field>
            <name>GPIOESMEN</name>
            <bitOffset>4</bitOffset>
            <bitWidth>1</bitWidth>
          </field>
          <field>
            <name>GPIOFSMEN</name>
            <bitOffset>5</bitOffset>
            <bitWidth>1</bitWidth>
          </field>
          <field>
            <name>GPIOGSMEN</name>
            <bitOffset>6</bitOffset>
            <bitWidth>1</bitWidth>
          </field>
          <field>
            <name>GPIOHSMEN</name>
            <bitOffset>7</bitOffset>
            <bitWidth>1</bitWidth>
          </field>
          <field>
            <name>GPIOISMEN</name>
            <bitOffset>8</bitOffset>
            <bitWidth>1</bitWidth>
          </field>
          <field>
            <name>SRAM2SMEN</name>
            <bitOffset>9</bitOffset>
            <bitWidth>1</bitWidth>
          </field>
          <field>
            <name>SRAM3SMEN</name>
            <bitOffset>10</bitOffset>
            <bitWidth>1</bitWidth>
          </field>
          <field>
            <name>OTGFSSMEN</name>
            <bitOffset>12</bitOffset>
            <bitWidth>1</bitWidth>
          </field>
          <field>
            <name>ADCSMEN</name>
            <bitOffset>13</bitOffset>
            <bitWidth>1</bitWidth>
          </field>
          <field>
            <name>DCMISMEN</name>
            <bitOffset>14</bitOffset>
            <bitWidth>1</bitWidth>
          </field>
          <field>
            <name>HASHSMEN</name>
            <bitOffset>17</bitOffset>
            <bitWidth>1</bitWidth>
          </field>
          <field>
            <name>RNGSMEN</name>
            <bitOffset>18</bitOffset>
            <bitWidth>1</bitWidth>
          </field>
          <field>
            <name>OSPIMSMEN</name>
            <bitOffset>20</bitOffset>
            <bitWidth>1</bitWidth>
          </field>
          <field>
            <name>SDMMC1SMEN</name>
            <bitOffset>22</bitOffset>
            <bitWidth>1</bitWidth>
          </field>
          <field>
            <name>SDMMC2SMEN</name>
            <bitOffset>23</bitOffset>
            <bitWidth>1</bitWidth>
          </field>
        </fields>
      </register>
      <register>
        <name>AHB3SMENR</name>
        <addressOffset>0x70</addressOffset>
        <size>0x20</size>
        <fields>
          <field>
            <name>FMCSMEN</name>
            <bitOffset>0</bitOffset>
            <bitWidth>1</bitWidth>
          </field>
          <field>
            <name>OSPI1SMEN</name>
            <bitOffset>8</bitOffset>
            <bitWidth>1</bitWidth>
          </field>
          <field>
            <name>OSPI2SMEN</name>
            <bitOffset>9</bitOffset>
            <bitWidth>1</bitWidth>
          </field>
        </fields>
      </register>
      <register>
        <name>APB1SMENR1</name>
        <addressOffset>0x78</addressOffset>
        <size>0x20</size>
        <fields>
          <field>
            <name>TIM2SMEN</name>
            <bitOffset>0</bitOffset>
            <bitWidth>1</bitWidth>
          </field>
          <field>
            <name>TIM3SMEN</name>
            <bitOffset>1</bitOffset>
            <bitWidth>1</bitWidth>
          </field>
          <field>
            <name>TIM4SMEN</name>
            <bitOffset>2</bitOffset>
            <bitWidth>1</bitWidth>
          </field>
          <field>
            <name>TIM5SMEN</name>
            <bitOffset>3</bitOffset>
            <bitWidth>1</bitWidth>
          </field>
          <field>
            <name>TIM6SMEN</name>
            <bitOffset>4</bitOffset>
            <bitWidth>1</bitWidth>
          </field>
          <field>
            <name>TIM7SMEN</name>
            <bitOffset>5</bitOffset>
            <bitWidth>1</bitWidth>
          </field>
          <field>
            <name>RTCAPBSMEN</name>
            <bitOffset>10</bitOffset>
            <bitWidth>1</bitWidth>
          </field>
          <field>
            <name>WWDGSMEN</name>
            <bitOffset>11</bitOffset>
            <bitWidth>1</bitWidth>
          </field>
          <field>
            <name>SPI2SMEN</name>
            <bitOffset>14</bitOffset>
            <bitWidth>1</bitWidth>
          </field>
          <field>
            <name>SPI3SMEN</name>
            <bitOffset>15</bitOffset>
            <bitWidth>1</bitWidth>
          </field>
          <field>
            <name>USART2SMEN</name>
            <bitOffset>17</bitOffset>
            <bitWidth>1</bitWidth>
          </field>
          <field>
            <name>USART3SMEN</name>
            <bitOffset>18</bitOffset>
            <bitWidth>1</bitWidth>
          </field>
          <field>
            <name>UART4SMEN</name>
            <bitOffset>19</bitOffset>
            <bitWidth>1</bitWidth>
          </field>
          <field>
            <name>UART5SMEN</name>
            <bitOffset>20</bitOffset>
            <bitWidth>1</bitWidth>
          </field>
          <field>
            <name>I2C1SMEN</name>
            <bitOffset>21</bitOffset>
            <bitWidth>1</bitWidth>
          </field>
          <field>
            <name>I2C2SMEN</name>
            <bitOffset>22</bitOffset>
            <bitWidth>1</bitWidth>
          </field>
          <field>
            <name>I2C3SMEN</name>
            <bitOffset>23</bitOffset>
            <bitWidth>1</bitWidth>
          </field>
          <field>
            <name>CRSSMEN</name>
            <bitOffset>24</bitOffset>
            <bitWidth>1</bitWidth>
          </field>
          <field>
            <name>CAN1SMEN</name>
            <bitOffset>25</bitOffset>
            <bitWidth>1</bitWidth>
          </field>
          <field>
            <name>PWRSMEN</name>
            <bitOffset>28</bitOffset>
            <bitWidth>1</bitWidth>
          </field>
          <field>
            <name>DAC1SMEN</name>
            <bitOffset>29</bitOffset>
            <bitWidth>1</bitWidth>
          </field>
          <field>
            <name>OPAMPSMEN</name>
            <bitOffset>30</bitOffset>
            <bitWidth>1</bitWidth>
          </field>
          <field>
            <name>LPTIM1SMEN</name>
            <bitOffset>31</bitOffset>
            <bitWidth>1</bitWidth>
          </field>
        </fields>
      </register>
      <register>
        <name>APB1SMENR2</name>
        <addressOffset>0x7c</addressOffset>
        <size>0x20</size>
        <fields>
          <field>
            <name>LPUART1SMEN</name>
            <bitOffset>0</bitOffset>
            <bitWidth>1</bitWidth>
          </field>
          <field>
            <name>I2C4SMEN</name>
            <bitOffset>1</bitOffset>
            <bitWidth>1</bitWidth>
          </field>
          <field>
            <name>LPTIM2SMEN</name>
            <bitOffset>5</bitOffset>
            <bitWidth>1</bitWidth>
          </field>
        </fields>
      </register>
      <register>
        <name>APB2SMENR</name>
        <addressOffset>0x80</addressOffset>
        <size>0x20</size>
        <fields>
          <field>
            <name>SYSCFGSMEN</name>
            <bitOffset>0</bitOffset>
            <bitWidth>1</bitWidth>
          </field>
          <field>
            <name>TIM1SMEN</name>
            <bitOffset>11</bitOffset>
            <bitWidth>1</bitWidth>
          </field>
          <field>
            <name>SPI1SMEN</name>
            <bitOffset>12</bitOffset>
            <bitWidth>1</bitWidth>
          </field>
          <field>
            <name>TIM8SMEN</name>
            <bitOffset>13</bitOffset>
            <bitWidth>1</bitWidth>
          </field>
          <field>
            <name>USART1SMEN</name>
            <bitOffset>14</bitOffset>
            <bitWidth>1</bitWidth>
          </field>
          <field>
            <name>TIM15SMEN</name>
            <bitOffset>16</bitOffset>
            <bitWidth>1</bitWidth>
          </field>
          <field>
            <name>TIM16SMEN</name>
            <bitOffset>17</bitOffset>
            <bitWidth>1</bitWidth>
          </field>
          <field>
            <name>TIM17SMEN</name>
            <bitOffset>18</bitOffset>
            <bitWidth>1</bitWidth>
          </field>
          <field>
            <name>SAI1SMEN</name>
            <bitOffset>21</bitOffset>
            <bitWidth>1</bitWidth>
          </field>
          <field>
            <name>SAI2SMEN</name>
            <bitOffset>22</bitOffset>
            <bitWidth>1</bitWidth>
          </field>
          <field>
            <name>DFSDM1SMEN</name>
            <bitOffset>24</bitOffset>
            <bitWidth>1</bitWidth>
          </field>
          <field>
            <name>LTDCSMEN</name>
            <bitOffset>26</bitOffset>
            <bitWidth>1</bitWidth>
          </field>
        </fields>
      </register>
      <register>
        <name>CCIPR</name>
        <addressOffset>0x88</addressOffset>
        <size>0x20</size>
        <fields>
          <field>
            <name>USART1SEL</name>
            <bitOffset>0</bitOffset>
            <bitWidth>2</bitWidth>
          </field>
          <field>
            <name>USART2SEL</name>
            <bitOffset>2</bitOffset>
            <bitWidth>2</bitWidth>
          </field>
          <field>
            <name>USART3SEL</name>
            <bitOffset>4</bitOffset>
            <bitWidth>2</bitWidth>
          </field>
          <field>
            <name>UART4SEL</name>
            <bitOffset>6</bitOffset>
            <bitWidth>2</bitWidth>
          </field>
          <field>
            <name>UART5SEL</name>
            <bitOffset>8</bitOffset>
            <bitWidth>2</bitWidth>
          </field>
          <field>
            <name>LPUART1SEL</name>
            <bitOffset>10</bitOffset>
            <bitWidth>2</bitWidth>
          </field>
          <field>
            <name>I2C1SEL</name>
            <bitOffset>12</bitOffset>
            <bitWidth>2</bitWidth>
          </field>
          <field>
            <name>I2C2SEL</name>
            <bitOffset>14</bitOffset>
            <bitWidth>2</bitWidth>
          </field>
          <field>
            <name>I2C3SEL</name>
            <bitOffset>16</bitOffset>
            <bitWidth>2</bitWidth>
          </field>
          <field>
            <name>LPTIM1SEL</name>
            <bitOffset>18</bitOffset>
            <bitWidth>2</bitWidth>
          </field>
          <field>
            <name>LPTIM2SEL</name>
            <bitOffset>20</bitOffset>
            <bitWidth>2</bitWidth>
          </field>
          <field>
            <name>CLK48SEL</name>
            <bitOffset>26</bitOffset>
            <bitWidth>2</bitWidth>
          </field>
          <field>
            <name>ADCSEL</name>
            <bitOffset>28</bitOffset>
            <bitWidth>2</bitWidth>
          </field>
        </fields>
      </register>
      <register>
        <name>BDCR</name>
        <addressOffset>0x90</addressOffset>
        <size>0x20</size>
        <fields>
          <field>
            <name>LSEON</name>
            <bitOffset>0</bitOffset>
            <bitWidth>1</bitWidth>
          </field>
          <field>
            <name>LSERDY</name>
            <bitOffset>1</bitOffset>
            <bitWidth>1</bitWidth>
          </field>
          <field>
            <name>LSEBYP</name>
            <bitOffset>2</bitOffset>
            <bitWidth>1</bitWidth>
          </field>
          <field>
            <name>LSEDRV</name>
            <bitOffset>3</bitOffset>
            <bitWidth>2</bitWidth>
          </field>
          <field>
            <name>LSECSSON</name>
            <bitOffset>5</bitOffset>
            <bitWidth>1</bitWidth>
          </field>
          <field>
            <name>LSECSSD</name>
            <bitOffset>6</bitOffset>
            <bitWidth>1</bitWidth>
          </field>
          <field>
            <name>LSESYSDIS</name>
            <bitOffset>7</bitOffset>
            <bitWidth>1</bitWidth>
          </field>
          <field>
            <name>RTCSEL</name>
            <bitOffset>8</bitOffset>
            <bitWidth>2</bitWidth>
          </field>
          <field>
            <name>RTCEN</name>
            <bitOffset>15</bitOffset>
            <bitWidth>1</bitWidth>
          </field>
          <field>
            <name>BDRST</name>
            <bitOffset>16</bitOffset>
            <bitWidth>1</bitWidth>
          </field>
          <field>
            <name>LSCOEN</name>
            <bitOffset>24</bitOffset>
            <bitWidth>1</bitWidth>
          </field>
          <field>
            <name>LSCOSEL</name>
            <bitOffset>25</bitOffset>
            <bitWidth>1</bitWidth>
          </field>
        </fields>
      </register>
      <register>
        <name>CSR</name>
        <addressOffset>0x94</addressOffset>
        <size>0x20</size>
        <fields>
          <field>
            <name>LSION</name>
            <bitOffset>0</bitOffset>
            <bitWidth>1</bitWidth>
          </field>
          <field>
            <name>LSIRDY</name>
            <bitOffset>1</bitOffset>
            <bitWidth>1</bitWidth>
          </field>
          <field>
            <name>LSIPREDIV</name>
            <bitOffset>4</bitOffset>
            <bitWidth>1</bitWidth>
          </field>
          <field>
            <name>MSISRANGE</name>
            <bitOffset>8</bitOffset>
            <bitWidth>4</bitWidth>
          </field>
          <field>
            <name>RMVF</name>
            <bitOffset>23</bitOffset>
            <bitWidth>1</bitWidth>
          </field>
          <field>
            <name>FWRSTF</name>
            <bitOffset>24</bitOffset>
            <bitWidth>1</bitWidth>
          </field>
          <field>
            <name>OBLRSTF</name>
            <bitOffset>25</bitOffset>
            <bitWidth>1</bitWidth>
          </field>
          <field>
            <name>PINRSTF</name>
            <bitOffset>26</bitOffset>
            <bitWidth>1</bitWidth>
          </field>
          <field>
            <name>BORRSTF</name>
            <bitOffset>27</bitOffset>
            <bitWidth>1</bitWidth>
          </field>
          <field>
            <name>SFTRSTF</name>
            <bitOffset>28</bitOffset>
            <bitWidth>1</bitWidth>
          </field>
          <field>
            <name>IWDGRSTF</name>
            <bitOffset>29</bitOffset>
            <bitWidth>1</bitWidth>
          </field>
          <field>
            <name>WWDGRSTF</name>
            <bitOffset>30</bitOffset>
            <bitWidth>1</bitWidth>
          </field>
          <field>
            <name>LPWRRSTF</name>
            <bitOffset>31</bitOffset>
            <bitWidth>1</bitWidth>
          </field>
        </fields>
      </register>
      <register>
        <name>CRRCR</name>
        <addressOffset>0x98</addressOffset>
        <size>0x20</size>
        <fields>
          <field>
            <name>HSI48ON</name>
            <bitOffset>0</bitOffset>
            <bitWidth>1</bitWidth>
          </field>
          <field>
            <name>HSI48RDY</name>
            <bitOffset>1</bitOffset>
            <bitWidth>1</bitWidth>
          </field>
          <field>
            <name>HSI48CAL</name>
            <bitOffset>7</bitOffset>
            <bitWidth>9</bitWidth>
          </field>
        </fields>
      </register>
      <register>
        <name>CCIPR2</name>
        <addressOffset>0x9c</addressOffset>
        <size>0x20</size>
        <fields>
          <field>
            <name>I2C4SEL</name>
            <bitOffset>0</bitOffset>
            <bitWidth>2</bitWidth>
          </field>
          <field>
            <name>DFSDM1SEL</name>
            <bitOffset>2</bitOffset>
            <bitWidth>1</bitWidth>
          </field>
          <field>
            <name>ADFSDM1SEL</name>
            <bitOffset>3</bitOffset>
            <bitWidth>2</bitWidth>
          </field>
          <field>
            <name>SAI1SEL</name>
            <bitOffset>5</bitOffset>
            <bitWidth>3</bitWidth>
          </field>
          <field>
            <name>SAI2SEL</name>
            <bitOffset>8</bitOffset>
            <bitWidth>3</bitWidth>
          </field>
          <field>
            <name>SDMMCSEL</name>
            <bitOffset>14</bitOffset>
            <bitWidth>1</bitWidth>
          </field>
          <field>
            <name>PLLSAI2DIVR</name>
            <bitOffset>16</bitOffset>
            <bitWidth>2</bitWidth>
          </field>
          <field>
            <name>OSPISEL</name>
            <bitOffset>20</bitOffset>
            <bitWidth>2</bitWidth>
          </field>
        </fields>
      </register>
      <register>
        <name>DLYCFGR</name>
        <addressOffset>0xa4</addressOffset>
        <size>0x20</size>
        <fields>
          <field>
            <name>OCTOSPI1_DLY</name>
            <bitOffset>0</bitOffset>
            <bitWidth>4</bitWidth>
          </field>
          <field>
            <name>OCTOSPI2_DLY</name>
            <bitOffset>4</bitOffset>
            <bitWidth>4</bitWidth>
          </field>
        </fields>
      </register>
    </peripheral>
    <peripheral>
      <name>FLASH</name>
      <baseAddress>0x40022000</baseAddress>
      <register>
        <name>ACR</name>
        <addressOffset>0x0</addressOffset>
        <size>0x20</size>
        <fields>
          <field>
            <name>LATENCY</name>
            <bitOffset>0</bitOffset>
            <bitWidth>4</bitWidth>
          </field>
          <field>
            <name>PRFTEN</name>
            <bitOffset>8</bitOffset>
            <bitWidth>1</bitWidth>
          </field>
          <field>
            <name>ICEN</name>
            <bitOffset>9</bitOffset>
            <bitWidth>1</bitWidth>
          </field>
          <field>
            <name>DCEN</name>
            <bitOffset>10</bitOffset>
            <bitWidth>1</bitWidth>
          </field>
          <field>
            <name>ICRST</name>
            <bitOffset>11</bitOffset>
            <bitWidth>1</bitWidth>
          </field>
          <field>
            <name>DCRST</name>
            <bitOffset>12</bitOffset>
            <bitWidth>1</bitWidth>
          </field>
          <field>
            <name>RUN_PD</name>
            <bitOffset>13</bitOffset>
            <bitWidth>1</bitWidth>
          </field>
          <field>
            <name>SLEEP_PD</name>
            <bitOffset>14</bitOffset>
            <bitWidth>1</bitWidth>
          </field>
        </fields>
      </register>
      <register>
        <name>PDKEYR</name>
        <addressOffset>0x4</addressOffset>
        <size>0x20</size>
      </register>
      <register>
        <name>KEYR</name>
        <addressOffset>0x8</addressOffset>
        <size>0x20</size>
      </register>
      <register>
        <name>OPTKEYR</name>
        <addressOffset>0xc</addressOffset>
        <size>0x20</size>
      </register>
      <register>
        <name>SR</name>
        <addressOffset>0x10</addressOffset>
        <size>0x20</size>
        <fields>
          <field>
            <name>EOP</name>
            <bitOffset>0</bitOffset>
            <bitWidth>1</bitWidth>
          </field>
          <field>
            <name>OPERR</name>
            <bitOffset>1</bitOffset>
            <bitWidth>1</bitWidth>
          </field>
          <field>
            <name>PROGERR</name>
            <bitOffset>3</bitOffset>
            <bitWidth>1</bitWidth>
          </field>
          <field>
            <name>WRPERR</name>
            <bitOffset>4</bitOffset>
            <bitWidth>1</bitWidth>
          </field>
          <field>
            <name>PGAERR</name>
            <bitOffset>5</bitOffset>
            <bitWidth>1</bitWidth>
          </field>
          <field>
            <name>SIZERR</name>
            <bitOffset>6</bitOffset>
            <bitWidth>1</bitWidth>
          </field>
          <field>
            <name>PGSERR</name>
            <bitOffset>7</bitOffset>
            <bitWidth>1</bitWidth>
          </field>
          <field>
            <name>MISERR</name>
            <bitOffset>8</bitOffset>
            <bitWidth>1</bitWidth>
          </field>
          <field>
            <name>FASTERR</name>
            <bitOffset>9</bitOffset>
            <bitWidth>1</bitWidth>
          </field>
          <field>
            <name>RDERR</name>
            <bitOffset>14</bitOffset>
            <bitWidth>1</bitWidth>
          </field>
          <field>
            <name>OPTVERR</name>
            <bitOffset>15</bitOffset>
            <bitWidth>1</bitWidth>
          </field>
          <field>
            <name>BSY</name>
            <bitOffset>16</bitOffset>
            <bitWidth>1</bitWidth>
          </field>
          <field>
            <name>PEMPTY</name>
            <bitOffset>17</bitOffset>
            <bitWidth>1</bitWidth>
          </field>
        </fields>
      </register>
      <register>
        <name>CR</name>
        <addressOffset>0x14</addressOffset>
        <size>0x20</size>
        <fields>
          <field>
            <name>PG</name>
            <bitOffset>0</bitOffset>
            <bitWidth>1</bitWidth>
          </field>
          <field>
            <name>PER</name>
            <bitOffset>1</bitOffset>
            <bitWidth>1</bitWidth>
          </field>
          <field>
            <name>MER1</name>
            <bitOffset>2</bitOffset>
            <bitWidth>1</bitWidth>
          </field>
          <field>
            <name>PNB</name>
            <bitOffset>3</bitOffset>
            <bitWidth>7</bitWidth>
          </field>
          <field>
            <name>BKER</name>
            <bitOffset>11</bitOffset>
            <bitWidth>1</bitWidth>
          </field>
          <field>
            <name>MER2</name>
            <bitOffset>15</bitOffset>
            <bitWidth>1</bitWidth>
          </field>
          <field>
            <name>STRT</name>
            <bitOffset>16</bitOffset>
            <bitWidth>1</bitWidth>
          </field>
          <field>
            <name>OPTSTRT</name>
            <bitOffset>17</bitOffset>
            <bitWidth>1</bitWidth>
          </field>
          <field>
            <name>FSTPG</name>
            <bitOffset>18</bitOffset>
            <bitWidth>1</bitWidth>
          </field>
          <field>
            <name>EOPIE</name>
            <bitOffset>24</bitOffset>
            <bitWidth>1</bitWidth>
          </field>
          <field>
            <name>ERRIE</name>
            <bitOffset>25</bitOffset>
            <bitWidth>1</bitWidth>
          </field>
          <field>
            <name>RDERRIE</name>
            <bitOffset>26</bitOffset>
            <bitWidth>1</bitWidth>
          </field>
          <field>
            <name>OBL_LAUNCH</name>
            <bitOffset>27</bitOffset>
            <bitWidth>1</bitWidth>
          </field>
          <field>
            <name>OPTLOCK</name>
            <bitOffset>30</bitOffset>
            <bitWidth>1</bitWidth>
          </field>
          <field>
            <name>LOCK</name>
            <bitOffset>31</bitOffset>
            <bitWidth>1</bitWidth>
          </field>
        </fields>
      </register>
      <register>
        <name>ECCR</name>
        <addressOffset>0x18</addressOffset>
        <size>0x20</size>
        <fields>
          <field>
            <name>ADDR_ECC</name>
            <bitOffset>0</bitOffset>
            <bitWidth>20</bitWidth>
          </field>
          <field>
            <name>BK_ECC</name>
            <bitOffset>21</bitOffset>
            <bitWidth>1</bitWidth>
          </field>
          <field>
            <name>SYSF_ECC</name>
            <bitOffset>22</bitOffset>
            <bitWidth>1</bitWidth>
          </field>
          <field>
            <name>ECCIE</name>
            <bitOffset>24</bitOffset>
            <bitWidth>1</bitWidth>
          </field>
          <field>
            <name>ECCC2</name>
            <bitOffset>28</bitOffset>
            <bitWidth>1</bitWidth>
          </field>
          <field>
            <name>ECCD2</name>
            <bitOffset>29</bitOffset>
            <bitWidth>1</bitWidth>
          </field>
          <field>
            <name>ECCC</name>
            <bitOffset>30</bitOffset>
            <bitWidth>1</bitWidth>
          </field>
          <field>
            <name>ECCD</name>
            <bitOffset>31</bitOffset>
            <bitWidth>1</bitWidth>
          </field>
        </fields>
      </register>
      <register>
        <name>OPTR</name>
        <addressOffset>0x20</addressOffset>
        <size>0x20</size>
        <fields>
          <field>
            <name>RDP</name>
            <bitOffset>0</bitOffset>
            <bitWidth>8</bitWidth>
          </field>
          <field>
            <name>BOR_LEV</name>
            <bitOffset>8</bitOffset>
            <bitWidth>3</bitWidth>
          </field>
          <field>
            <name>nRST_STOP</name>
            <bitOffset>12</bitOffset>
            <bitWidth>1</bitWidth>
          </field>
          <field>
            <name>nRST_STDBY</name>
            <bitOffset>13</bitOffset>
            <bitWidth>1</bitWidth>
          </field>
          <field>
            <name>nRST_SHDW</name>
            <bitOffset>14</bitOffset>
            <bitWidth>1</bitWidth>
          </field>
          <field>
            <name>IWDG_SW</name>
            <bitOffset>16</bitOffset>
            <bitWidth>1</bitWidth>
          </field>
          <field>
            <name>IWDG_STOP</name>
            <bitOffset>17</bitOffset>
            <bitWidth>1</bitWidth>
          </field>
          <field>
            <name>IWDG_STDBY</name>
            <bitOffset>18</bitOffset>
            <bitWidth>1</bitWidth>
          </field>
          <field>
            <name>WWDG_SW</name>
            <bitOffset>19</bitOffset>
            <bitWidth>1</bitWidth>
          </field>
          <field>
            <name>BFB2</name>
            <bitOffset>20</bitOffset>
            <bitWidth>1</bitWidth>
          </field>
          <field>
            <name>DB1M</name>
            <bitOffset>21</bitOffset>
            <bitWidth>1</bitWidth>
          </field>
          <field>
            <name>DBANK</name>
            <bitOffset>22</bitOffset>
            <bitWidth>1</bitWidth>
          </field>
          <field>
            <name>nBOOT1</name>
            <bitOffset>23</bitOffset>
            <bitWidth>1</bitWidth>
          </field>
          <field>
            <name>SRAM2_PE</name>
            <bitOffset>24</bitOffset>
            <bitWidth>1</bitWidth>
          </field>
          <field>
            <name>SRAM2_RST</name>
            <bitOffset>25</bitOffset>
            <bitWidth>1</bitWidth>
          </field>
          <field>
            <name>nSWBOOT0</name>
            <bitOffset>26</bitOffset>
            <bitWidth>1</bitWidth>
          </field>
          <field>
            <name>nBOOT0</name>
            <bitOffset>27</bitOffset>
            <bitWidth>1</bitWidth>
          </field>
        </fields>
      </register>
      <register>
        <name>PCROP1SR</name>
        <addressOffset>0x24</addressOffset>
        <size>0x20</size>
        <fields>
          <field>
            <name>PCROP1_STRT</name>
            <bitOffset>0</bitOffset>
            <bitWidth>16</bitWidth>
          </field>
        </fields>
      </register>
      <register>
        <name>PCROP1ER</name>
        <addressOffset>0x28</addressOffset>
        <size>0x20</size>
        <fields>
          <field>
            <name>PCROP1_END</name>
            <bitOffset>0</bitOffset>
            <bitWidth>16</bitWidth>
          </field>
          <field>
            <name>PCROP_RDP</name>
            <bitOffset>31</bitOffset>
            <bitWidth>1</bitWidth>
          </field>
        </fields>
      </register>
      <register>
        <name>WRP1AR</name>
        <addressOffset>0x2c</addressOffset>
        <size>0x20</size>
        <fields>
          <field>
            <name>WRP1A_STRT</name>
            <bitOffset>0</bitOffset>
            <bitWidth>7</bitWidth>
          </field>
          <field>
            <name>WRP1A_END</name>
            <bitOffset>16</bitOffset>
            <bitWidth>7</bitWidth>
          </field>
        </fields>
      </register>
      <register>
        <name>WRP1BR</name>
        <addressOffset>0x30</addressOffset>
        <size>0x20</size>
        <fields>
          <field>
            <name>WRP1B_STRT</name>
            <bitOffset>0</bitOffset>
            <bitWidth>7</bitWidth>
          </field>
          <field>
            <name>WRP1B_END</name>
            <bitOffset>16</bitOffset>
            <bitWidth>7</bitWidth>
          </field>
        </fields>
      </register>
      <register>
        <name>PCROP2SR</name>
        <addressOffset>0x44</addressOffset>
        <size>0x20</size>
        <fields>
          <field>
            <name>PCROP2_STRT</name>
            <bitOffset>0</bitOffset>
            <bitWidth>16</bitWidth>
          </field>
        </fields>
      </register>
      <register>
        <name>PCROP2ER</name>
        <addressOffset>0x48</addressOffset>
        <size>0x20</size>
        <fields>
          <field>
            <name>PCROP2_END</name>
            <bitOffset>0</bitOffset>
            <bitWidth>16</bitWidth>
          </field>
        </fields>
      </register>
      <register>
        <name>WRP2AR</name>
        <addressOffset>0x4c</addressOffset>
        <size>0x20</size>
        <fields>
          <field>
            <name>WRP2A_STRT</name>
            <bitOffset>0</bitOffset>
            <bitWidth>7</bitWidth>
          </field>
          <field>
            <name>WRP2A_END</name>
            <bitOffset>16</bitOffset>
            <bitWidth>7</bitWidth>
          </field>
        </fields>
      </register>
      <register>
        <name>WRP2BR</name>
        <addressOffset>0x50</addressOffset>
        <size>0x20</size>
        <fields>
          <field>
            <name>WRP2B_STRT</name>
            <bitOffset>0</bitOffset>
            <bitWidth>7</bitWidth>
          </field>
          <field>
            <name>WRP2B_END</name>
            <bitOffset>16</bitOffset>
            <bitWidth>7</bitWidth>
          </field>
        </fields>
      </register>
      <register>
        <name>CFGR</name>
        <addressOffset>0x130</addressOffset>
        <size>0x20</size>
        <fields>
          <field>
            <name>LVEN</name>
            <bitOffset>0</bitOffset>
            <bitWidth>1</bitWidth>
          </field>
        </fields>
      </register>
      <register>
        <name>DSR</name>
        <addressOffset>0x200</addressOffset>
        <size>0x20</size>
      </register>
    </peripheral>
    <peripheral>
      <name>CRC</name>
      <baseAddress>0x40023000</baseAddress>
      <register>
        <name>DR</name>
        <addressOffset>0x0</addressOffset>
        <size>0x20</size>
        <fields>
          <field>
            <name>DR</name>
            <bitOffset>0</bitOffset>
            <bitWidth>32</bitWidth>
          </field>
        </fields>
      </register>
      <register>
        <name>IDR</name>
        <addressOffset>0x4</addressOffset>
        <size>0x20</size>
        <fields>
          <field>
            <name>IDR</name>
            <bitOffset>0</bitOffset>
            <bitWidth>32</bitWidth>
          </field>
        </fields>
      </register>
      <register>
        <name>CR</name>
        <addressOffset>0x8</addressOffset>
        <size>0x20</size>
        <fields>
          <field>
            <name>RESET</name>
            <bitOffset>0</bitOffset>
            <bitWidth>1</bitWidth>
          </field>
          <field>
            <name>POLYSIZE</name>
            <bitOffset>3</bitOffset>
            <bitWidth>2</bitWidth>
          </field>
          <field>
            <name>REV_IN</name>
            <bitOffset>5</bitOffset>
            <bitWidth>2</bitWidth>
          </field>
          <field>
            <name>REV_OUT</name>
            <bitOffset>7</bitOffset>
            <bitWidth>1</bitWidth>
          </field>
        </fields>
      </register>
      <register>
        <name>INIT</name>
        <addressOffset>0x10</addressOffset>
        <size>0x20</size>
        <fields>
          <field>
            <name>INIT</name>
            <bitOffset>0</bitOffset>
            <bitWidth>32</bitWidth>
          </field>
        </fields>
      </register>
      <register>
        <name>POL</name>
        <addressOffset>0x14</addressOffset>
        <size>0x20</size>
        <fields>
          <field>
            <name>POL</name>
            <bitOffset>0</bitOffset>
            <bitWidth>32</bitWidth>
          </field>
        </fields>
      </register>
    </peripheral>
    <peripheral>
      <name>TSC</name>
      <baseAddress>0x40024000</baseAddress>
      <register>
        <name>CR</name>
        <addressOffset>0x0</addressOffset>
        <size>0x20</size>
        <fields>
          <field>
            <name>TSCE</name>
            <bitOffset>0</bitOffset>
            <bitWidth>1</bitWidth>
          </field>
          <field>
            <name>START</name>
            <bitOffset>1</bitOffset>
            <bitWidth>1</bitWidth>
          </field>
          <field>
            <name>AM</name>
            <bitOffset>2</bitOffset>
            <bitWidth>1</bitWidth>
          </field>
          <field>
            <name>SYNCPOL</name>
            <bitOffset>3</bitOffset>
            <bitWidth>1</bitWidth>
          </field>
          <field>
            <name>IODEF</name>
            <bitOffset>4</bitOffset>
            <bitWidth>1</bitWidth>
          </field>
          <field>
            <name>MCV</name>
            <bitOffset>5</bitOffset>
            <bitWidth>3</bitWidth>
          </field>
          <field>
            <name>PGPSC</name>
            <bitOffset>12</bitOffset>
            <bitWidth>3</bitWidth>
          </field>
          <field>
            <name>SSPSC</name>
            <bitOffset>15</bitOffset>
            <bitWidth>1</bitWidth>
          </field>
          <field>
            <name>SSE</name>
            <bitOffset>16</bitOffset>
            <bitWidth>1</bitWidth>
          </field>
          <field>
            <name>SSD</name>
            <bitOffset>17</bitOffset>
            <bitWidth>7</bitWidth>
          </field>
          <field>
            <name>CTPL</name>
            <bitOffset>24</bitOffset>
            <bitWidth>4</bitWidth>
          </field>
          <field>
            <name>CTPH</name>
            <bitOffset>28</bitOffset>
            <bitWidth>4</bitWidth>
          </field>
        </fields>
      </register>
      <register>
        <name>IER</name>
        <addressOffset>0x4</addressOffset>
        <size>0x20</size>
        <fields>
          <field>
            <name>EOAIE</name>
            <bitOffset>0</bitOffset>
            <bitWidth>1</bitWidth>
          </field>
          <field>
            <name>MCEIE</name>
            <bitOffset>1</bitOffset>
            <bitWidth>1</bitWidth>
          </field>
        </fields>
      </register>
      <register>
        <name>ICR</name>
        <addressOffset>0x8</addressOffset>
        <size>0x20</size>
        <fields>
          <field>
            <name>EOAIC</name>
            <bitOffset>0</bitOffset>
            <bitWidth>1</bitWidth>
          </field>
          <field>
            <name>MCEIC</name>
            <bitOffset>1</bitOffset>
            <bitWidth>1</bitWidth>
          </field>
        </fields>
      </register>
      <register>
        <name>ISR</name>
        <addressOffset>0xc</addressOffset>
        <size>0x20</size>
        <fields>
          <field>
            <name>EOAF</name>
            <bitOffset>0</bitOffset>
            <bitWidth>1</bitWidth>
          </field>
          <field>
            <name>MCEF</name>
            <bitOffset>1</bitOffset>
            <bitWidth>1</bitWidth>
          </field>
        </fields>
      </register>
      <register>
        <name>IOHCR</name>
        <addressOffset>0x10</addressOffset>
        <size>0x20</size>
        <fields>
          <field>
            <name>G1_IO1</name>
            <bitOffset>0</bitOffset>
            <bitWidth>1</bitWidth>
          </field>
          <field>
            <name>G1_IO2</name>
            <bitOffset>1</bitOffset>
            <bitWidth>1</bitWidth>
          </field>
          <field>
            <name>G1_IO3</name>
            <bitOffset>2</bitOffset>
            <bitWidth>1</bitWidth>
          </field>
          <field>
            <name>G1_IO4</name>
            <bitOffset>3</bitOffset>
            <bitWidth>1</bitWidth>
          </field>
          <field>
            <name>G2_IO1</name>
            <bitOffset>4</bitOffset>
            <bitWidth>1</bitWidth>
          </field>
          <field>
            <name>G2_IO2</name>
            <bitOffset>5</bitOffset>
            <bitWidth>1</bitWidth>
          </field>
          <field>
            <name>G2_IO3</name>
            <bitOffset>6</bitOffset>
            <bitWidth>1</bitWidth>
          </field>
          <field>
            <name>G2_IO4</name>
            <bitOffset>7</bitOffset>
            <bitWidth>1</bitWidth>
          </field>
          <field>
            <name>G3_IO1</name>
            <bitOffset>8</bitOffset>
            <bitWidth>1</bitWidth>
          </field>
          <field>
            <name>G3_IO2</name>
            <bitOffset>9</bitOffset>
            <bitWidth>1</bitWidth>
          </field>
          <field>
            <name>G3_IO3</name>
            <bitOffset>10</bitOffset>
            <bitWidth>1</bitWidth>
          </field>
          <field>
            <name>G3_IO4</name>
            <bitOffset>11</bitOffset>
            <bitWidth>1</bitWidth>
          </field>
          <field>
            <name>G4_IO1</name>
            <bitOffset>12</bitOffset>
            <bitWidth>1</bitWidth>
          </field>
          <field>
            <name>G4_IO2</name>
            <bitOffset>13</bitOffset>
            <bitWidth>1</bitWidth>
          </field>
          <field>
            <name>G4_IO3</name>
            <bitOffset>14</bitOffset>
            <bitWidth>1</bitWidth>
          </field>
          <field>
            <name>G4_IO4</name>
            <bitOffset>15</bitOffset>
            <bitWidth>1</bitWidth>
          </field>
          <field>
            <name>G5_IO1</name>
            <bitOffset>16</bitOffset>
            <bitWidth>1</bitWidth>
          </field>
          <field>
            <name>G5_IO2</name>
            <bitOffset>17</bitOffset>
            <bitWidth>1</bitWidth>
          </field>
          <field>
            <name>G5_IO3</name>
            <bitOffset>18</bitOffset>
            <bitWidth>1</bitWidth>
          </field>
          <field>
            <name>G5_IO4</name>
            <bitOffset>19</bitOffset>
            <bitWidth>1</bitWidth>
          </field>
          <field>
            <name>G6_IO1</name>
            <bitOffset>20</bitOffset>
            <bitWidth>1</bitWidth>
          </field>
          <field>
            <name>G6_IO2</name>
            <bitOffset>21</bitOffset>
            <bitWidth>1</bitWidth>
          </field>
          <field>
            <name>G6_IO3</name>
            <bitOffset>22</bitOffset>
            <bitWidth>1</bitWidth>
          </field>
          <field>
            <name>G6_IO4</name>
            <bitOffset>23</bitOffset>
            <bitWidth>1</bitWidth>
          </field>
          <field>
            <name>G7_IO1</name>
            <bitOffset>24</bitOffset>
            <bitWidth>1</bitWidth>
          </field>
          <field>
            <name>G7_IO2</name>
            <bitOffset>25</bitOffset>
            <bitWidth>1</bitWidth>
          </field>
          <field>
            <name>G7_IO3</name>
            <bitOffset>26</bitOffset>
            <bitWidth>1</bitWidth>
          </field>
          <field>
            <name>G7_IO4</name>
            <bitOffset>27</bitOffset>
            <bitWidth>1</bitWidth>
          </field>
          <field>
            <name>G8_IO1</name>
            <bitOffset>28</bitOffset>
            <bitWidth>1</bitWidth>
          </field>
          <field>
            <name>G8_IO2</name>
            <bitOffset>29</bitOffset>
            <bitWidth>1</bitWidth>
          </field>
          <field>
            <name>G8_IO3</name>
            <bitOffset>30</bitOffset>
            <bitWidth>1</bitWidth>
          </field>
          <field>
            <name>G8_IO4</name>
            <bitOffset>31</bitOffset>
            <bitWidth>1</bitWidth>
          </field>
        </fields>
      </register>
      <register>
        <name>IOASCR</name>
        <addressOffset>0x18</addressOffset>
        <size>0x20</size>
        <fields>
          <field>
            <name>G1_IO1</name>
            <bitOffset>0</bitOffset>
            <bitWidth>1</bitWidth>
          </field>
          <field>
            <name>G1_IO2</name>
            <bitOffset>1</bitOffset>
            <bitWidth>1</bitWidth>
          </field>
          <field>
            <name>G1_IO3</name>
            <bitOffset>2</bitOffset>
            <bitWidth>1</bitWidth>
          </field>
          <field>
            <name>G1_IO4</name>
            <bitOffset>3</bitOffset>
            <bitWidth>1</bitWidth>
          </field>
          <field>
            <name>G2_IO1</name>
            <bitOffset>4</bitOffset>
            <bitWidth>1</bitWidth>
          </field>
          <field>
            <name>G2_IO2</name>
            <bitOffset>5</bitOffset>
            <bitWidth>1</bitWidth>
          </field>
          <field>
            <name>G2_IO3</name>
            <bitOffset>6</bitOffset>
            <bitWidth>1</bitWidth>
          </field>
          <field>
            <name>G2_IO4</name>
            <bitOffset>7</bitOffset>
            <bitWidth>1</bitWidth>
          </field>
          <field>
            <name>G3_IO1</name>
            <bitOffset>8</bitOffset>
            <bitWidth>1</bitWidth>
          </field>
          <field>
            <name>G3_IO2</name>
            <bitOffset>9</bitOffset>
            <bitWidth>1</bitWidth>
          </field>
          <field>
            <name>G3_IO3</name>
            <bitOffset>10</bitOffset>
            <bitWidth>1</bitWidth>
          </field>
          <field>
            <name>G3_IO4</name>
            <bitOffset>11</bitOffset>
            <bitWidth>1</bitWidth>
          </field>
          <field>
            <name>G4_IO1</name>
            <bitOffset>12</bitOffset>
            <bitWidth>1</bitWidth>
          </field>
          <field>
            <name>G4_IO2</name>
            <bitOffset>13</bitOffset>
            <bitWidth>1</bitWidth>
          </field>
          <field>
            <name>G4_IO3</name>
            <bitOffset>14</bitOffset>
            <bitWidth>1</bitWidth>
          </field>
          <field>
            <name>G4_IO4</name>
            <bitOffset>15</bitOffset>
            <bitWidth>1</bitWidth>
          </field>
          <field>
            <name>G5_IO1</name>
            <bitOffset>16</bitOffset>
            <bitWidth>1</bitWidth>
          </field>
          <field>
            <name>G5_IO2</name>
            <bitOffset>17</bitOffset>
            <bitWidth>1</bitWidth>
          </field>
          <field>
            <name>G5_IO3</name>
            <bitOffset>18</bitOffset>
            <bitWidth>1</bitWidth>
          </field>
          <field>
            <name>G5_IO4</name>
            <bitOffset>19</bitOffset>
            <bitWidth>1</bitWidth>
          </field>
          <field>
            <name>G6_IO1</name>
            <bitOffset>20</bitOffset>
            <bitWidth>1</bitWidth>
          </field>
          <field>
            <name>G6_IO2</name>
            <bitOffset>21</bitOffset>
            <bitWidth>1</bitWidth>
          </field>
          <field>
            <name>G6_IO3</name>
            <bitOffset>22</bitOffset>
            <bitWidth>1</bitWidth>
          </field>
          <field>
            <name>G6_IO4</name>
            <bitOffset>23</bitOffset>
            <bitWidth>1</bitWidth>
          </field>
          <field>
            <name>G7_IO1</name>
            <bitOffset>24</bitOffset>
            <bitWidth>1</bitWidth>
          </field>
          <field>
            <name>G7_IO2</name>
            <bitOffset>25</bitOffset>
            <bitWidth>1</bitWidth>
          </field>
          <field>
            <name>G7_IO3</name>
            <bitOffset>26</bitOffset>
            <bitWidth>1</bitWidth>
          </field>
          <field>
            <name>G7_IO4</name>
            <bitOffset>27</bitOffset>
            <bitWidth>1</bitWidth>
          </field>
          <field>
            <name>G8_IO1</name>
            <bitOffset>28</bitOffset>
            <bitWidth>1</bitWidth>
          </field>
          <field>
            <name>G8_IO2</name>
            <bitOffset>29</bitOffset>
            <bitWidth>1</bitWidth>
          </field>
          <field>
            <name>G8_IO3</name>
            <bitOffset>30</bitOffset>
            <bitWidth>1</bitWidth>
          </field>
          <field>
            <name>G8_IO4</name>
            <bitOffset>31</bitOffset>
            <bitWidth>1</bitWidth>
          </field>
        </fields>
      </register>
      <register>
        <name>IOSCR</name>
        <addressOffset>0x20</addressOffset>
        <size>0x20</size>
        <fields>
          <field>
            <name>G1_IO1</name>
            <bitOffset>0</bitOffset>
            <bitWidth>1</bitWidth>
          </field>
          <field>
            <name>G1_IO2</name>
            <bitOffset>1</bitOffset>
            <bitWidth>1</bitWidth>
          </field>
          <field>
            <name>G1_IO3</name>
            <bitOffset>2</bitOffset>
            <bitWidth>1</bitWidth>
          </field>
          <field>
            <name>G1_IO4</name>
            <bitOffset>3</bitOffset>
            <bitWidth>1</bitWidth>
          </field>
          <field>
            <name>G2_IO1</name>
            <bitOffset>4</bitOffset>
            <bitWidth>1</bitWidth>
          </field>
          <field>
            <name>G2_IO2</name>
            <bitOffset>5</bitOffset>
            <bitWidth>1</bitWidth>
          </field>
          <field>
            <name>G2_IO3</name>
            <bitOffset>6</bitOffset>
            <bitWidth>1</bitWidth>
          </field>
          <field>
            <name>G2_IO4</name>
            <bitOffset>7</bitOffset>
            <bitWidth>1</bitWidth>
          </field>
          <field>
            <name>G3_IO1</name>
            <bitOffset>8</bitOffset>
            <bitWidth>1</bitWidth>
          </field>
          <field>
            <name>G3_IO2</name>
            <bitOffset>9</bitOffset>
            <bitWidth>1</bitWidth>
          </field>
          <field>
            <name>G3_IO3</name>
            <bitOffset>10</bitOffset>
            <bitWidth>1</bitWidth>
          </field>
          <field>
            <name>G3_IO4</name>
            <bitOffset>11</bitOffset>
            <bitWidth>1</bitWidth>
          </field>
          <field>
            <name>G4_IO1</name>
            <bitOffset>12</bitOffset>
            <bitWidth>1</bitWidth>
          </field>
          <field>
            <name>G4_IO2</name>
            <bitOffset>13</bitOffset>
            <bitWidth>1</bitWidth>
          </field>
          <field>
            <name>G4_IO3</name>
            <bitOffset>14</bitOffset>
            <bitWidth>1</bitWidth>
          </field>
          <field>
            <name>G4_IO4</name>
            <bitOffset>15</bitOffset>
            <bitWidth>1</bitWidth>
          </field>
          <field>
            <name>G5_IO1</name>
            <bitOffset>16</bitOffset>
            <bitWidth>1</bitWidth>
          </field>
          <field>
            <name>G5_IO2</name>
            <bitOffset>17</bitOffset>
            <bitWidth>1</bitWidth>
          </field>
          <field>
            <name>G5_IO3</name>
            <bitOffset>18</bitOffset>
            <bitWidth>1</bitWidth>
          </field>
          <field>
            <name>G5_IO4</name>
            <bitOffset>19</bitOffset>
            <bitWidth>1</bitWidth>
          </field>
          <field>
            <name>G6_IO1</name>
            <bitOffset>20</bitOffset>
            <bitWidth>1</bitWidth>
          </field>
          <field>
            <name>G6_IO2</name>
            <bitOffset>21</bitOffset>
            <bitWidth>1</bitWidth>
          </field>
          <field>
            <name>G6_IO3</name>
            <bitOffset>22</bitOffset>
            <bitWidth>1</bitWidth>
          </field>
          <field>
            <name>G6_IO4</name>
            <bitOffset>23</bitOffset>
            <bitWidth>1</bitWidth>
          </field>
          <field>
            <name>G7_IO1</name>
            <bitOffset>24</bitOffset>
            <bitWidth>1</bitWidth>
          </field>
          <field>
            <name>G7_IO2</name>
            <bitOffset>25</bitOffset>
            <bitWidth>1</bitWidth>
          </field>
          <field>
            <name>G7_IO3</name>
            <bitOffset>26</bitOffset>
            <bitWidth>1</bitWidth>
          </field>
          <field>
            <name>G7_IO4</name>
            <bitOffset>27</bitOffset>
            <bitWidth>1</bitWidth>
          </field>
          <field>
            <name>G8_IO1</name>
            <bitOffset>28</bitOffset>
            <bitWidth>1</bitWidth>
          </field>
          <field>
            <name>G8_IO2</name>
            <bitOffset>29</bitOffset>
            <bitWidth>1</bitWidth>
          </field>
          <field>
            <name>G8_IO3</name>
            <bitOffset>30</bitOffset>
            <bitWidth>1</bitWidth>
          </field>
          <field>
            <name>G8_IO4</name>
            <bitOffset>31</bitOffset>
            <bitWidth>1</bitWidth>
          </field>
        </fields>
      </register>
      <register>
        <name>IOCCR</name>
        <addressOffset>0x28</addressOffset>
        <size>0x20</size>
        <fields>
          <field>
            <name>G1_IO1</name>
            <bitOffset>0</bitOffset>
            <bitWidth>1</bitWidth>
          </field>
          <field>
            <name>G1_IO2</name>
            <bitOffset>1</bitOffset>
            <bitWidth>1</bitWidth>
          </field>
          <field>
            <name>G1_IO3</name>
            <bitOffset>2</bitOffset>
            <bitWidth>1</bitWidth>
          </field>
          <field>
            <name>G1_IO4</name>
            <bitOffset>3</bitOffset>
            <bitWidth>1</bitWidth>
          </field>
          <field>
            <name>G2_IO1</name>
            <bitOffset>4</bitOffset>
            <bitWidth>1</bitWidth>
          </field>
          <field>
            <name>G2_IO2</name>
            <bitOffset>5</bitOffset>
            <bitWidth>1</bitWidth>
          </field>
          <field>
            <name>G2_IO3</name>
            <bitOffset>6</bitOffset>
            <bitWidth>1</bitWidth>
          </field>
          <field>
            <name>G2_IO4</name>
            <bitOffset>7</bitOffset>
            <bitWidth>1</bitWidth>
          </field>
          <field>
            <name>G3_IO1</name>
            <bitOffset>8</bitOffset>
            <bitWidth>1</bitWidth>
          </field>
          <field>
            <name>G3_IO2</name>
            <bitOffset>9</bitOffset>
            <bitWidth>1</bitWidth>
          </field>
          <field>
            <name>G3_IO3</name>
            <bitOffset>10</bitOffset>
            <bitWidth>1</bitWidth>
          </field>
          <field>
            <name>G3_IO4</name>
            <bitOffset>11</bitOffset>
            <bitWidth>1</bitWidth>
          </field>
          <field>
            <name>G4_IO1</name>
            <bitOffset>12</bitOffset>
            <bitWidth>1</bitWidth>
          </field>
          <field>
            <name>G4_IO2</name>
            <bitOffset>13</bitOffset>
            <bitWidth>1</bitWidth>
          </field>
          <field>
            <name>G4_IO3</name>
            <bitOffset>14</bitOffset>
            <bitWidth>1</bitWidth>
          </field>
          <field>
            <name>G4_IO4</name>
            <bitOffset>15</bitOffset>
            <bitWidth>1</bitWidth>
          </field>
          <field>
            <name>G5_IO1</name>
            <bitOffset>16</bitOffset>
            <bitWidth>1</bitWidth>
          </field>
          <field>
            <name>G5_IO2</name>
            <bitOffset>17</bitOffset>
            <bitWidth>1</bitWidth>
          </field>
          <field>
            <name>G5_IO3</name>
            <bitOffset>18</bitOffset>
            <bitWidth>1</bitWidth>
          </field>
          <field>
            <name>G5_IO4</name>
            <bitOffset>19</bitOffset>
            <bitWidth>1</bitWidth>
          </field>
          <field>
            <name>G6_IO1</name>
            <bitOffset>20</bitOffset>
            <bitWidth>1</bitWidth>
          </field>
          <field>
            <name>G6_IO2</name>
            <bitOffset>21</bitOffset>
            <bitWidth>1</bitWidth>
          </field>
          <field>
            <name>G6_IO3</name>
            <bitOffset>22</bitOffset>
            <bitWidth>1</bitWidth>
          </field>
          <field>
            <name>G6_IO4</name>
            <bitOffset>23</bitOffset>
            <bitWidth>1</bitWidth>
          </field>
          <field>
            <name>G7_IO1</name>
            <bitOffset>24</bitOffset>
            <bitWidth>1</bitWidth>
          </field>
          <field>
            <name>G7_IO2</name>
            <bitOffset>25</bitOffset>
            <bitWidth>1</bitWidth>
          </field>
          <field>
            <name>G7_IO3</name>
            <bitOffset>26</bitOffset>
            <bitWidth>1</bitWidth>
          </field>
          <field>
            <name>G7_IO4</name>
            <bitOffset>27</bitOffset>
            <bitWidth>1</bitWidth>
          </field>
          <field>
            <name>G8_IO1</name>
            <bitOffset>28</bitOffset>
            <bitWidth>1</bitWidth>
          </field>
          <field>
            <name>G8_IO2</name>
            <bitOffset>29</bitOffset>
            <bitWidth>1</bitWidth>
          </field>
          <field>
            <name>G8_IO3</name>
            <bitOffset>30</bitOffset>
            <bitWidth>1</bitWidth>
          </field>
          <field>
            <name>G8_IO4</name>
            <bitOffset>31</bitOffset>
            <bitWidth>1</bitWidth>
          </field>
        </fields>
      </register>
      <register>
        <name>IOGCSR</name>
        <addressOffset>0x30</addressOffset>
        <size>0x20</size>
        <fields>
          <field>
            <name>G1E</name>
            <bitOffset>0</bitOffset>
            <bitWidth>1</bitWidth>
          </field>
          <field>
            <name>G2E</name>
            <bitOffset>1</bitOffset>
            <bitWidth>1</bitWidth>
          </field>
          <field>
            <name>G3E</name>
            <bitOffset>2</bitOffset>
            <bitWidth>1</bitWidth>
          </field>
          <field>
            <name>G4E</name>
            <bitOffset>3</bitOffset>
            <bitWidth>1</bitWidth>
          </field>
          <field>
            <name>G5E</name>
            <bitOffset>4</bitOffset>
            <bitWidth>1</bitWidth>
          </field>
          <field>
            <name>G6E</name>
            <bitOffset>5</bitOffset>
            <bitWidth>1</bitWidth>
          </field>
          <field>
            <name>G7E</name>
            <bitOffset>6</bitOffset>
            <bitWidth>1</bitWidth>
          </field>
          <field>
            <name>G8E</name>
            <bitOffset>7</bitOffset>
            <bitWidth>1</bitWidth>
          </field>
          <field>
            <name>G1S</name>
            <bitOffset>16</bitOffset>
            <bitWidth>1</bitWidth>
          </field>
          <field>
            <name>G2S</name>
            <bitOffset>17</bitOffset>
            <bitWidth>1</bitWidth>
          </field>
          <field>
            <name>G3S</name>
            <bitOffset>18</bitOffset>
            <bitWidth>1</bitWidth>
          </field>
          <field>
            <name>G4S</name>
            <bitOffset>19</bitOffset>
            <bitWidth>1</bitWidth>
          </field>
          <field>
            <name>G5S</name>
            <bitOffset>20</bitOffset>
            <bitWidth>1</bitWidth>
          </field>
          <field>
            <name>G6S</name>
            <bitOffset>21</bitOffset>
            <bitWidth>1</bitWidth>
          </field>
          <field>
            <name>G7S</name>
            <bitOffset>22</bitOffset>
            <bitWidth>1</bitWidth>
          </field>
          <field>
            <name>G8S</name>
            <bitOffset>23</bitOffset>
            <bitWidth>1</bitWidth>
          </field>
        </fields>
      </register>
      <register>
        <name>IOGXCR.0</name>
        <addressOffset>0x34</addressOffset>
        <size>0x20</size>
        <fields>
          <field>
            <name>CNT</name>
            <bitOffset>0</bitOffset>
            <bitWidth>14</bitWidth>
          </field>
        </fields>
      </register>
      <register>
        <name>IOGXCR.1</name>
        <addressOffset>0x38</addressOffset>
        <size>0x20</size>
        <fields>
          <field>
            <name>CNT</name>
            <bitOffset>0</bitOffset>
            <bitWidth>14</bitWidth>
          </field>
        </fields>
      </register>
      <register>
        <name>IOGXCR.2</name>
        <addressOffset>0x3c</addressOffset>
        <size>0x20</size>
        <fields>
          <field>
            <name>CNT</name>
            <bitOffset>0</bitOffset>
            <bitWidth>14</bitWidth>
          </field>
        </fields>
      </register>
      <register>
        <name>IOGXCR.3</name>
        <addressOffset>0x40</addressOffset>
        <size>0x20</size>
        <fields>
          <field>
            <name>CNT</name>
            <bitOffset>0</bitOffset>
            <bitWidth>14</bitWidth>
          </field>
        </fields>
      </register>
      <register>
        <name>IOGXCR.4</name>
        <addressOffset>0x44</addressOffset>
        <size>0x20</size>
        <fields>
          <field>
            <name>CNT</name>
            <bitOffset>0</bitOffset>
            <bitWidth>14</bitWidth>
          </field>
        </fields>
      </register>
      <register>
        <name>IOGXCR.5</name>
        <addressOffset>0x48</addressOffset>
        <size>0x20</size>
        <fields>
          <field>
            <name>CNT</name>
            <bitOffset>0</bitOffset>
            <bitWidth>14</bitWidth>
          </field>
        </fields>
      </register>
      <register>
        <name>IOGXCR.6</name>
        <addressOffset>0x4c</addressOffset>
        <size>0x20</size>
        <fields>
          <field>
            <name>CNT</name>
            <bitOffset>0</bitOffset>
            <bitWidth>14</bitWidth>
          </field>
        </fields>
      </register>
      <register>
        <name>IOGXCR.7</name>
        <addressOffset>0x50</addressOffset>
        <size>0x20</size>
        <fields>
          <field>
            <name>CNT</name>
            <bitOffset>0</bitOffset>
            <bitWidth>14</bitWidth>
          </field>
        </fields>
      </register>
    </peripheral>
    <peripheral>
      <name>DMA2D</name>
      <baseAddress>0x4002b000</baseAddress>
      <register>
        <name>CR</name>
        <addressOffset>0x0</addressOffset>
        <size>0x20</size>
        <fields>
          <field>
            <name>START</name>
            <bitOffset>0</bitOffset>
            <bitWidth>1</bitWidth>
          </field>
          <field>
            <name>SUSP</name>
            <bitOffset>1</bitOffset>
            <bitWidth>1</bitWidth>
          </field>
          <field>
            <name>ABORT</name>
            <bitOffset>2</bitOffset>
            <bitWidth>1</bitWidth>
          </field>
          <field>
            <name>LOM</name>
            <bitOffset>6</bitOffset>
            <bitWidth>1</bitWidth>
          </field>
          <field>
            <name>TEIE</name>
            <bitOffset>8</bitOffset>
            <bitWidth>1</bitWidth>
          </field>
          <field>
            <name>TCIE</name>
            <bitOffset>9</bitOffset>
            <bitWidth>1</bitWidth>
          </field>
          <field>
            <name>TWIE</name>
            <bitOffset>10</bitOffset>
            <bitWidth>1</bitWidth>
          </field>
          <field>
            <name>CAEIE</name>
            <bitOffset>11</bitOffset>
            <bitWidth>1</bitWidth>
          </field>
          <field>
            <name>CTCIE</name>
            <bitOffset>12</bitOffset>
            <bitWidth>1</bitWidth>
          </field>
          <field>
            <name>CEIE</name>
            <bitOffset>13</bitOffset>
            <bitWidth>1</bitWidth>
          </field>
          <field>
            <name>MODE</name>
            <bitOffset>16</bitOffset>
            <bitWidth>3</bitWidth>
          </field>
        </fields>
      </register>
      <register>
        <name>ISR</name>
        <addressOffset>0x4</addressOffset>
        <size>0x20</size>
        <fields>
          <field>
            <name>TEIF</name>
            <bitOffset>0</bitOffset>
            <bitWidth>1</bitWidth>
          </field>
          <field>
            <name>TCIF</name>
            <bitOffset>1</bitOffset>
            <bitWidth>1</bitWidth>
          </field>
          <field>
            <name>TWIF</name>
            <bitOffset>2</bitOffset>
            <bitWidth>1</bitWidth>
          </field>
          <field>
            <name>CAEIF</name>
            <bitOffset>3</bitOffset>
            <bitWidth>1</bitWidth>
          </field>
          <field>
            <name>CTCIF</name>
            <bitOffset>4</bitOffset>
            <bitWidth>1</bitWidth>
          </field>
          <field>
            <name>CEIF</name>
            <bitOffset>5</bitOffset>
            <bitWidth>1</bitWidth>
          </field>
        </fields>
      </register>
      <register>
        <name>IFCR</name>
        <addressOffset>0x8</addressOffset>
        <size>0x20</size>
        <fields>
          <field>
            <name>CTEIF</name>
            <bitOffset>0</bitOffset>
            <bitWidth>1</bitWidth>
          </field>
          <field>
            <name>CTCIF</name>
            <bitOffset>1</bitOffset>
            <bitWidth>1</bitWidth>
          </field>
          <field>
            <name>CTWIF</name>
            <bitOffset>2</bitOffset>
            <bitWidth>1</bitWidth>
          </field>
          <field>
            <name>CAECIF</name>
            <bitOffset>3</bitOffset>
            <bitWidth>1</bitWidth>
          </field>
          <field>
            <name>CCTCIF</name>
            <bitOffset>4</bitOffset>
            <bitWidth>1</bitWidth>
          </field>
          <field>
            <name>CCEIF</name>
            <bitOffset>5</bitOffset>
            <bitWidth>1</bitWidth>
          </field>
        </fields>
      </register>
      <register>
        <name>FGMAR</name>
        <addressOffset>0xc</addressOffset>
        <size>0x20</size>
        <fields>
          <field>
            <name>MA</name>
            <bitOffset>0</bitOffset>
            <bitWidth>32</bitWidth>
          </field>
        </fields>
      </register>
      <register>
        <name>FGOR</name>
        <addressOffset>0x10</addressOffset>
        <size>0x20</size>
        <fields>
          <field>
            <name>LO</name>
            <bitOffset>0</bitOffset>
            <bitWidth>16</bitWidth>
          </field>
        </fields>
      </register>
      <register>
        <name>BGMAR</name>
        <addressOffset>0x14</addressOffset>
        <size>0x20</size>
        <fields>
          <field>
            <name>MA</name>
            <bitOffset>0</bitOffset>
            <bitWidth>32</bitWidth>
          </field>
        </fields>
      </register>
      <register>
        <name>BGOR</name>
        <addressOffset>0x18</addressOffset>
        <size>0x20</size>
        <fields>
          <field>
            <name>LO</name>
            <bitOffset>0</bitOffset>
            <bitWidth>16</bitWidth>
          </field>
        </fields>
      </register>
      <register>
        <name>FGPFCCR</name>
        <addressOffset>0x1c</addressOffset>
        <size>0x20</size>
        <fields>
          <field>
            <name>CM</name>
            <bitOffset>0</bitOffset>
            <bitWidth>4</bitWidth>
          </field>
          <field>
            <name>CCM</name>
            <bitOffset>4</bitOffset>
            <bitWidth>1</bitWidth>
          </field>
          <field>
            <name>START</name>
            <bitOffset>5</bitOffset>
            <bitWidth>1</bitWidth>
          </field>
          <field>
            <name>CS</name>
            <bitOffset>8</bitOffset>
            <bitWidth>8</bitWidth>
          </field>
          <field>
            <name>AM</name>
            <bitOffset>16</bitOffset>
            <bitWidth>2</bitWidth>
          </field>
          <field>
            <name>AI</name>
            <bitOffset>20</bitOffset>
            <bitWidth>1</bitWidth>
          </field>
          <field>
            <name>RBS</name>
            <bitOffset>21</bitOffset>
            <bitWidth>1</bitWidth>
          </field>
          <field>
            <name>ALPHA</name>
            <bitOffset>24</bitOffset>
            <bitWidth>8</bitWidth>
          </field>
        </fields>
      </register>
      <register>
        <name>FGCOLR</name>
        <addressOffset>0x20</addressOffset>
        <size>0x20</size>
        <fields>
          <field>
            <name>BLUE</name>
            <bitOffset>0</bitOffset>
            <bitWidth>8</bitWidth>
          </field>
          <field>
            <name>GREEN</name>
            <bitOffset>8</bitOffset>
            <bitWidth>8</bitWidth>
          </field>
          <field>
            <name>RED</name>
            <bitOffset>16</bitOffset>
            <bitWidth>8</bitWidth>
          </field>
        </fields>
      </register>
      <register>
        <name>BGPFCCR</name>
        <addressOffset>0x24</addressOffset>
        <size>0x20</size>
        <fields>
          <field>
            <name>CM</name>
            <bitOffset>0</bitOffset>
            <bitWidth>4</bitWidth>
          </field>
          <field>
            <name>CCM</name>
            <bitOffset>4</bitOffset>
            <bitWidth>1</bitWidth>
          </field>
          <field>
            <name>START</name>
            <bitOffset>5</bitOffset>
            <bitWidth>1</bitWidth>
          </field>
          <field>
            <name>CS</name>
            <bitOffset>8</bitOffset>
            <bitWidth>8</bitWidth>
          </field>
          <field>
            <name>AM</name>
            <bitOffset>16</bitOffset>
            <bitWidth>2</bitWidth>
          </field>
          <field>
            <name>AI</name>
            <bitOffset>20</bitOffset>
            <bitWidth>1</bitWidth>
          </field>
          <field>
            <name>RBS</name>
            <bitOffset>21</bitOffset>
            <bitWidth>1</bitWidth>
          </field>
          <field>
            <name>ALPHA</name>
            <bitOffset>24</bitOffset>
            <bitWidth>8</bitWidth>
          </field>
        </fields>
      </register>
      <register>
        <name>BGCOLR</name>
        <addressOffset>0x28</addressOffset>
        <size>0x20</size>
        <fields>
          <field>
            <name>BLUE</name>
            <bitOffset>0</bitOffset>
            <bitWidth>8</bitWidth>
          </field>
          <field>
            <name>GREEN</name>
            <bitOffset>8</bitOffset>
            <bitWidth>8</bitWidth>
          </field>
          <field>
            <name>RED</name>
            <bitOffset>16</bitOffset>
            <bitWidth>8</bitWidth>
          </field>
        </fields>
      </register>
      <register>
        <name>FGCMAR</name>
        <addressOffset>0x2c</addressOffset>
        <size>0x20</size>
        <fields>
          <field>
            <name>MA</name>
            <bitOffset>0</bitOffset>
            <bitWidth>32</bitWidth>
          </field>
        </fields>
      </register>
      <register>
        <name>BGCMAR</name>
        <addressOffset>0x30</addressOffset>
        <size>0x20</size>
        <fields>
          <field>
            <name>MA</name>
            <bitOffset>0</bitOffset>
            <bitWidth>32</bitWidth>
          </field>
        </fields>
      </register>
      <register>
        <name>OPFCCR</name>
        <addressOffset>0x34</addressOffset>
        <size>0x20</size>
        <fields>
          <field>
            <name>CM</name>
            <bitOffset>0</bitOffset>
            <bitWidth>3</bitWidth>
          </field>
          <field>
            <name>SB</name>
            <bitOffset>8</bitOffset>
            <bitWidth>1</bitWidth>
          </field>
          <field>
            <name>AI</name>
            <bitOffset>20</bitOffset>
            <bitWidth>1</bitWidth>
          </field>
          <field>
            <name>RBS</name>
            <bitOffset>21</bitOffset>
            <bitWidth>1</bitWidth>
          </field>
        </fields>
      </register>
      <register>
        <name>OCOLR</name>
        <addressOffset>0x38</addressOffset>
        <size>0x20</size>
      </register>
      <register>
        <name>OMAR</name>
        <addressOffset>0x3c</addressOffset>
        <size>0x20</size>
        <fields>
          <field>
            <name>MA</name>
            <bitOffset>0</bitOffset>
            <bitWidth>32</bitWidth>
          </field>
        </fields>
      </register>
      <register>
        <name>OOR</name>
        <addressOffset>0x40</addressOffset>
        <size>0x20</size>
        <fields>
          <field>
            <name>LO</name>
            <bitOffset>0</bitOffset>
            <bitWidth>16</bitWidth>
          </field>
        </fields>
      </register>
      <register>
        <name>NLR</name>
        <addressOffset>0x44</addressOffset>
        <size>0x20</size>
        <fields>
          <field>
            <name>NL</name>
            <bitOffset>0</bitOffset>
            <bitWidth>16</bitWidth>
          </field>
          <field>
            <name>PL</name>
            <bitOffset>16</bitOffset>
            <bitWidth>14</bitWidth>
          </field>
        </fields>
      </register>
      <register>
        <name>LWR</name>
        <addressOffset>0x48</addressOffset>
        <size>0x20</size>
        <fields>
          <field>
            <name>LW</name>
            <bitOffset>0</bitOffset>
            <bitWidth>16</bitWidth>
          </field>
        </fields>
      </register>
      <register>
        <name>AMTCR</name>
        <addressOffset>0x4c</addressOffset>
        <size>0x20</size>
        <fields>
          <field>
            <name>EN</name>
            <bitOffset>0</bitOffset>
            <bitWidth>1</bitWidth>
          </field>
          <field>
            <name>DT</name>
            <bitOffset>8</bitOffset>
            <bitWidth>8</bitWidth>
          </field>
        </fields>
      </register>
      <register>
        <name>FGCLUT.0</name>
        <addressOffset>0x400</addressOffset>
        <size>0x20</size>
      </register>
      <register>
        <name>FGCLUT.1</name>
        <addressOffset>0x404</addressOffset>
        <size>0x20</size>
      </register>
      <register>
        <name>FGCLUT.2</name>
        <addressOffset>0x408</addressOffset>
        <size>0x20</size>
      </register>
      <register>
        <name>FGCLUT.3</name>
        <addressOffset>0x40c</addressOffset>
        <size>0x20</size>
      </register>
      <register>
        <name>FGCLUT.4</name>
        <addressOffset>0x410</addressOffset>
        <size>0x20</size>
      </register>
      <register>
        <name>FGCLUT.5</name>
        <addressOffset>0x414</addressOffset>
        <size>0x20</size>
      </register>
      <register>
        <name>FGCLUT.6</name>
        <addressOffset>0x418</addressOffset>
        <size>0x20</size>
      </register>
      <register>
        <name>FGCLUT.7</name>
        <addressOffset>0x41c</addressOffset>
        <size>0x20</size>
      </register>
      <register>
        <name>FGCLUT.8</name>
        <addressOffset>0x420</addressOffset>
        <size>0x20</size>
      </register>
      <register>
        <name>FGCLUT.9</name>
        <addressOffset>0x424</addressOffset>
        <size>0x20</size>
      </register>
      <register>
        <name>FGCLUT.10</name>
        <addressOffset>0x428</addressOffset>
        <size>0x20</size>
      </register>
      <register>
        <name>FGCLUT.11</name>
        <addressOffset>0x42c</addressOffset>
        <size>0x20</size>
      </register>
      <register>
        <name>FGCLUT.12</name>
        <addressOffset>0x430</addressOffset>
        <size>0x20</size>
      </register>
      <register>
        <name>FGCLUT.13</name>
        <addressOffset>0x434</addressOffset>
        <size>0x20</size>
      </register>
      <register>
        <name>FGCLUT.14</name>
        <addressOffset>0x438</addressOffset>
        <size>0x20</size>
      </register>
      <register>
        <name>FGCLUT.15</name>
        <addressOffset>0x43c</addressOffset>
        <size>0x20</size>
      </register>
      <register>
        <name>FGCLUT.16</name>
        <addressOffset>0x440</addressOffset>
        <size>0x20</size>
      </register>
      <register>
        <name>FGCLUT.17</name>
        <addressOffset>0x444</addressOffset>
        <size>0x20</size>
      </register>
      <register>
        <name>FGCLUT.18</name>
        <addressOffset>0x448</addressOffset>
        <size>0x20</size>
      </register>
      <register>
        <name>FGCLUT.19</name>
        <addressOffset>0x44c</addressOffset>
        <size>0x20</size>
      </register>
      <register>
        <name>FGCLUT.20</name>
        <addressOffset>0x450</addressOffset>
        <size>0x20</size>
      </register>
      <register>
        <name>FGCLUT.21</name>
        <addressOffset>0x454</addressOffset>
        <size>0x20</size>
      </register>
      <register>
        <name>FGCLUT.22</name>
        <addressOffset>0x458</addressOffset>
        <size>0x20</size>
      </register>
      <register>
        <name>FGCLUT.23</name>
        <addressOffset>0x45c</addressOffset>
        <size>0x20</size>
      </register>
      <register>
        <name>FGCLUT.24</name>
        <addressOffset>0x460</addressOffset>
        <size>0x20</size>
      </register>
      <register>
        <name>FGCLUT.25</name>
        <addressOffset>0x464</addressOffset>
        <size>0x20</size>
      </register>
      <register>
        <name>FGCLUT.26</name>
        <addressOffset>0x468</addressOffset>
        <size>0x20</size>
      </register>
      <register>
        <name>FGCLUT.27</name>
        <addressOffset>0x46c</addressOffset>
        <size>0x20</size>
      </register>
      <register>
        <name>FGCLUT.28</name>
        <addressOffset>0x470</addressOffset>
        <size>0x20</size>
      </register>
      <register>
        <name>FGCLUT.29</name>
        <addressOffset>0x474</addressOffset>
        <size>0x20</size>
      </register>
      <register>
        <name>FGCLUT.30</name>
        <addressOffset>0x478</addressOffset>
        <size>0x20</size>
      </register>
      <register>
        <name>FGCLUT.31</name>
        <addressOffset>0x47c</addressOffset>
        <size>0x20</size>
      </register>
      <register>
        <name>FGCLUT.32</name>
        <addressOffset>0x480</addressOffset>
        <size>0x20</size>
      </register>
      <register>
        <name>FGCLUT.33</name>
        <addressOffset>0x484</addressOffset>
        <size>0x20</size>
      </register>
      <register>
        <name>FGCLUT.34</name>
        <addressOffset>0x488</addressOffset>
        <size>0x20</size>
      </register>
      <register>
        <name>FGCLUT.35</name>
        <addressOffset>0x48c</addressOffset>
        <size>0x20</size>
      </register>
      <register>
        <name>FGCLUT.36</name>
        <addressOffset>0x490</addressOffset>
        <size>0x20</size>
      </register>
      <register>
        <name>FGCLUT.37</name>
        <addressOffset>0x494</addressOffset>
        <size>0x20</size>
      </register>
      <register>
        <name>FGCLUT.38</name>
        <addressOffset>0x498</addressOffset>
        <size>0x20</size>
      </register>
      <register>
        <name>FGCLUT.39</name>
        <addressOffset>0x49c</addressOffset>
        <size>0x20</size>
      </register>
      <register>
        <name>FGCLUT.40</name>
        <addressOffset>0x4a0</addressOffset>
        <size>0x20</size>
      </register>
      <register>
        <name>FGCLUT.41</name>
        <addressOffset>0x4a4</addressOffset>
        <size>0x20</size>
      </register>
      <register>
        <name>FGCLUT.42</name>
        <addressOffset>0x4a8</addressOffset>
        <size>0x20</size>
      </register>
      <register>
        <name>FGCLUT.43</name>
        <addressOffset>0x4ac</addressOffset>
        <size>0x20</size>
      </register>
      <register>
        <name>FGCLUT.44</name>
        <addressOffset>0x4b0</addressOffset>
        <size>0x20</size>
      </register>
      <register>
        <name>FGCLUT.45</name>
        <addressOffset>0x4b4</addressOffset>
        <size>0x20</size>
      </register>
      <register>
        <name>FGCLUT.46</name>
        <addressOffset>0x4b8</addressOffset>
        <size>0x20</size>
      </register>
      <register>
        <name>FGCLUT.47</name>
        <addressOffset>0x4bc</addressOffset>
        <size>0x20</size>
      </register>
      <register>
        <name>FGCLUT.48</name>
        <addressOffset>0x4c0</addressOffset>
        <size>0x20</size>
      </register>
      <register>
        <name>FGCLUT.49</name>
        <addressOffset>0x4c4</addressOffset>
        <size>0x20</size>
      </register>
      <register>
        <name>FGCLUT.50</name>
        <addressOffset>0x4c8</addressOffset>
        <size>0x20</size>
      </register>
      <register>
        <name>FGCLUT.51</name>
        <addressOffset>0x4cc</addressOffset>
        <size>0x20</size>
      </register>
      <register>
        <name>FGCLUT.52</name>
        <addressOffset>0x4d0</addressOffset>
        <size>0x20</size>
      </register>
      <register>
        <name>FGCLUT.53</name>
        <addressOffset>0x4d4</addressOffset>
        <size>0x20</size>
      </register>
      <register>
        <name>FGCLUT.54</name>
        <addressOffset>0x4d8</addressOffset>
        <size>0x20</size>
      </register>
      <register>
        <name>FGCLUT.55</name>
        <addressOffset>0x4dc</addressOffset>
        <size>0x20</size>
      </register>
      <register>
        <name>FGCLUT.56</name>
        <addressOffset>0x4e0</addressOffset>
        <size>0x20</size>
      </register>
      <register>
        <name>FGCLUT.57</name>
        <addressOffset>0x4e4</addressOffset>
        <size>0x20</size>
      </register>
      <register>
        <name>FGCLUT.58</name>
        <addressOffset>0x4e8</addressOffset>
        <size>0x20</size>
      </register>
      <register>
        <name>FGCLUT.59</name>
        <addressOffset>0x4ec</addressOffset>
        <size>0x20</size>
      </register>
      <register>
        <name>FGCLUT.60</name>
        <addressOffset>0x4f0</addressOffset>
        <size>0x20</size>
      </register>
      <register>
        <name>FGCLUT.61</name>
        <addressOffset>0x4f4</addressOffset>
        <size>0x20</size>
      </register>
      <register>
        <name>FGCLUT.62</name>
        <addressOffset>0x4f8</addressOffset>
        <size>0x20</size>
      </register>
      <register>
        <name>FGCLUT.63</name>
        <addressOffset>0x4fc</addressOffset>
        <size>0x20</size>
      </register>
      <register>
        <name>FGCLUT.64</name>
        <addressOffset>0x500</addressOffset>
        <size>0x20</size>
      </register>
      <register>
        <name>FGCLUT.65</name>
        <addressOffset>0x504</addressOffset>
        <size>0x20</size>
      </register>
      <register>
        <name>FGCLUT.66</name>
        <addressOffset>0x508</addressOffset>
        <size>0x20</size>
      </register>
      <register>
        <name>FGCLUT.67</name>
        <addressOffset>0x50c</addressOffset>
        <size>0x20</size>
      </register>
      <register>
        <name>FGCLUT.68</name>
        <addressOffset>0x510</addressOffset>
        <size>0x20</size>
      </register>
      <register>
        <name>FGCLUT.69</name>
        <addressOffset>0x514</addressOffset>
        <size>0x20</size>
      </register>
      <register>
        <name>FGCLUT.70</name>
        <addressOffset>0x518</addressOffset>
        <size>0x20</size>
      </register>
      <register>
        <name>FGCLUT.71</name>
        <addressOffset>0x51c</addressOffset>
        <size>0x20</size>
      </register>
      <register>
        <name>FGCLUT.72</name>
        <addressOffset>0x520</addressOffset>
        <size>0x20</size>
      </register>
      <register>
        <name>FGCLUT.73</name>
        <addressOffset>0x524</addressOffset>
        <size>0x20</size>
      </register>
      <register>
        <name>FGCLUT.74</name>
        <addressOffset>0x528</addressOffset>
        <size>0x20</size>
      </register>
      <register>
        <name>FGCLUT.75</name>
        <addressOffset>0x52c</addressOffset>
        <size>0x20</size>
      </register>
      <register>
        <name>FGCLUT.76</name>
        <addressOffset>0x530</addressOffset>
        <size>0x20</size>
      </register>
      <register>
        <name>FGCLUT.77</name>
        <addressOffset>0x534</addressOffset>
        <size>0x20</size>
      </register>
      <register>
        <name>FGCLUT.78</name>
        <addressOffset>0x538</addressOffset>
        <size>0x20</size>
      </register>
      <register>
        <name>FGCLUT.79</name>
        <addressOffset>0x53c</addressOffset>
        <size>0x20</size>
      </register>
      <register>
        <name>FGCLUT.80</name>
        <addressOffset>0x540</addressOffset>
        <size>0x20</size>
      </register>
      <register>
        <name>FGCLUT.81</name>
        <addressOffset>0x544</addressOffset>
        <size>0x20</size>
      </register>
      <register>
        <name>FGCLUT.82</name>
        <addressOffset>0x548</addressOffset>
        <size>0x20</size>
      </register>
      <register>
        <name>FGCLUT.83</name>
        <addressOffset>0x54c</addressOffset>
        <size>0x20</size>
      </register>
      <register>
        <name>FGCLUT.84</name>
        <addressOffset>0x550</addressOffset>
        <size>0x20</size>
      </register>
      <register>
        <name>FGCLUT.85</name>
        <addressOffset>0x554</addressOffset>
        <size>0x20</size>
      </register>
      <register>
        <name>FGCLUT.86</name>
        <addressOffset>0x558</addressOffset>
        <size>0x20</size>
      </register>
      <register>
        <name>FGCLUT.87</name>
        <addressOffset>0x55c</addressOffset>
        <size>0x20</size>
      </register>
      <register>
        <name>FGCLUT.88</name>
        <addressOffset>0x560</addressOffset>
        <size>0x20</size>
      </register>
      <register>
        <name>FGCLUT.89</name>
        <addressOffset>0x564</addressOffset>
        <size>0x20</size>
      </register>
      <register>
        <name>FGCLUT.90</name>
        <addressOffset>0x568</addressOffset>
        <size>0x20</size>
      </register>
      <register>
        <name>FGCLUT.91</name>
        <addressOffset>0x56c</addressOffset>
        <size>0x20</size>
      </register>
      <register>
        <name>FGCLUT.92</name>
        <addressOffset>0x570</addressOffset>
        <size>0x20</size>
      </register>
      <register>
        <name>FGCLUT.93</name>
        <addressOffset>0x574</addressOffset>
        <size>0x20</size>
      </register>
      <register>
        <name>FGCLUT.94</name>
        <addressOffset>0x578</addressOffset>
        <size>0x20</size>
      </register>
      <register>
        <name>FGCLUT.95</name>
        <addressOffset>0x57c</addressOffset>
        <size>0x20</size>
      </register>
      <register>
        <name>FGCLUT.96</name>
        <addressOffset>0x580</addressOffset>
        <size>0x20</size>
      </register>
      <register>
        <name>FGCLUT.97</name>
        <addressOffset>0x584</addressOffset>
        <size>0x20</size>
      </register>
      <register>
        <name>FGCLUT.98</name>
        <addressOffset>0x588</addressOffset>
        <size>0x20</size>
      </register>
      <register>
        <name>FGCLUT.99</name>
        <addressOffset>0x58c</addressOffset>
        <size>0x20</size>
      </register>
      <register>
        <name>FGCLUT.100</name>
        <addressOffset>0x590</addressOffset>
        <size>0x20</size>
      </register>
      <register>
        <name>FGCLUT.101</name>
        <addressOffset>0x594</addressOffset>
        <size>0x20</size>
      </register>
      <register>
        <name>FGCLUT.102</name>
        <addressOffset>0x598</addressOffset>
        <size>0x20</size>
      </register>
      <register>
        <name>FGCLUT.103</name>
        <addressOffset>0x59c</addressOffset>
        <size>0x20</size>
      </register>
      <register>
        <name>FGCLUT.104</name>
        <addressOffset>0x5a0</addressOffset>
        <size>0x20</size>
      </register>
      <register>
        <name>FGCLUT.105</name>
        <addressOffset>0x5a4</addressOffset>
        <size>0x20</size>
      </register>
      <register>
        <name>FGCLUT.106</name>
        <addressOffset>0x5a8</addressOffset>
        <size>0x20</size>
      </register>
      <register>
        <name>FGCLUT.107</name>
        <addressOffset>0x5ac</addressOffset>
        <size>0x20</size>
      </register>
      <register>
        <name>FGCLUT.108</name>
        <addressOffset>0x5b0</addressOffset>
        <size>0x20</size>
      </register>
      <register>
        <name>FGCLUT.109</name>
        <addressOffset>0x5b4</addressOffset>
        <size>0x20</size>
      </register>
      <register>
        <name>FGCLUT.110</name>
        <addressOffset>0x5b8</addressOffset>
        <size>0x20</size>
      </register>
      <register>
        <name>FGCLUT.111</name>
        <addressOffset>0x5bc</addressOffset>
        <size>0x20</size>
      </register>
      <register>
        <name>FGCLUT.112</name>
        <addressOffset>0x5c0</addressOffset>
        <size>0x20</size>
      </register>
      <register>
        <name>FGCLUT.113</name>
        <addressOffset>0x5c4</addressOffset>
        <size>0x20</size>
      </register>
      <register>
        <name>FGCLUT.114</name>
        <addressOffset>0x5c8</addressOffset>
        <size>0x20</size>
      </register>
      <register>
        <name>FGCLUT.115</name>
        <addressOffset>0x5cc</addressOffset>
        <size>0x20</size>
      </register>
      <register>
        <name>FGCLUT.116</name>
        <addressOffset>0x5d0</addressOffset>
        <size>0x20</size>
      </register>
      <register>
        <name>FGCLUT.117</name>
        <addressOffset>0x5d4</addressOffset>
        <size>0x20</size>
      </register>
      <register>
        <name>FGCLUT.118</name>
        <addressOffset>0x5d8</addressOffset>
        <size>0x20</size>
      </register>
      <register>
        <name>FGCLUT.119</name>
        <addressOffset>0x5dc</addressOffset>
        <size>0x20</size>
      </register>
      <register>
        <name>FGCLUT.120</name>
        <addressOffset>0x5e0</addressOffset>
        <size>0x20</size>
      </register>
      <register>
        <name>FGCLUT.121</name>
        <addressOffset>0x5e4</addressOffset>
        <size>0x20</size>
      </register>
      <register>
        <name>FGCLUT.122</name>
        <addressOffset>0x5e8</addressOffset>
        <size>0x20</size>
      </register>
      <register>
        <name>FGCLUT.123</name>
        <addressOffset>0x5ec</addressOffset>
        <size>0x20</size>
      </register>
      <register>
        <name>FGCLUT.124</name>
        <addressOffset>0x5f0</addressOffset>
        <size>0x20</size>
      </register>
      <register>
        <name>FGCLUT.125</name>
        <addressOffset>0x5f4</addressOffset>
        <size>0x20</size>
      </register>
      <register>
        <name>FGCLUT.126</name>
        <addressOffset>0x5f8</addressOffset>
        <size>0x20</size>
      </register>
      <register>
        <name>FGCLUT.127</name>
        <addressOffset>0x5fc</addressOffset>
        <size>0x20</size>
      </register>
      <register>
        <name>FGCLUT.128</name>
        <addressOffset>0x600</addressOffset>
        <size>0x20</size>
      </register>
      <register>
        <name>FGCLUT.129</name>
        <addressOffset>0x604</addressOffset>
        <size>0x20</size>
      </register>
      <register>
        <name>FGCLUT.130</name>
        <addressOffset>0x608</addressOffset>
        <size>0x20</size>
      </register>
      <register>
        <name>FGCLUT.131</name>
        <addressOffset>0x60c</addressOffset>
        <size>0x20</size>
      </register>
      <register>
        <name>FGCLUT.132</name>
        <addressOffset>0x610</addressOffset>
        <size>0x20</size>
      </register>
      <register>
        <name>FGCLUT.133</name>
        <addressOffset>0x614</addressOffset>
        <size>0x20</size>
      </register>
      <register>
        <name>FGCLUT.134</name>
        <addressOffset>0x618</addressOffset>
        <size>0x20</size>
      </register>
      <register>
        <name>FGCLUT.135</name>
        <addressOffset>0x61c</addressOffset>
        <size>0x20</size>
      </register>
      <register>
        <name>FGCLUT.136</name>
        <addressOffset>0x620</addressOffset>
        <size>0x20</size>
      </register>
      <register>
        <name>FGCLUT.137</name>
        <addressOffset>0x624</addressOffset>
        <size>0x20</size>
      </register>
      <register>
        <name>FGCLUT.138</name>
        <addressOffset>0x628</addressOffset>
        <size>0x20</size>
      </register>
      <register>
        <name>FGCLUT.139</name>
        <addressOffset>0x62c</addressOffset>
        <size>0x20</size>
      </register>
      <register>
        <name>FGCLUT.140</name>
        <addressOffset>0x630</addressOffset>
        <size>0x20</size>
      </register>
      <register>
        <name>FGCLUT.141</name>
        <addressOffset>0x634</addressOffset>
        <size>0x20</size>
      </register>
      <register>
        <name>FGCLUT.142</name>
        <addressOffset>0x638</addressOffset>
        <size>0x20</size>
      </register>
      <register>
        <name>FGCLUT.143</name>
        <addressOffset>0x63c</addressOffset>
        <size>0x20</size>
      </register>
      <register>
        <name>FGCLUT.144</name>
        <addressOffset>0x640</addressOffset>
        <size>0x20</size>
      </register>
      <register>
        <name>FGCLUT.145</name>
        <addressOffset>0x644</addressOffset>
        <size>0x20</size>
      </register>
      <register>
        <name>FGCLUT.146</name>
        <addressOffset>0x648</addressOffset>
        <size>0x20</size>
      </register>
      <register>
        <name>FGCLUT.147</name>
        <addressOffset>0x64c</addressOffset>
        <size>0x20</size>
      </register>
      <register>
        <name>FGCLUT.148</name>
        <addressOffset>0x650</addressOffset>
        <size>0x20</size>
      </register>
      <register>
        <name>FGCLUT.149</name>
        <addressOffset>0x654</addressOffset>
        <size>0x20</size>
      </register>
      <register>
        <name>FGCLUT.150</name>
        <addressOffset>0x658</addressOffset>
        <size>0x20</size>
      </register>
      <register>
        <name>FGCLUT.151</name>
        <addressOffset>0x65c</addressOffset>
        <size>0x20</size>
      </register>
      <register>
        <name>FGCLUT.152</name>
        <addressOffset>0x660</addressOffset>
        <size>0x20</size>
      </register>
      <register>
        <name>FGCLUT.153</name>
        <addressOffset>0x664</addressOffset>
        <size>0x20</size>
      </register>
      <register>
        <name>FGCLUT.154</name>
        <addressOffset>0x668</addressOffset>
        <size>0x20</size>
      </register>
      <register>
        <name>FGCLUT.155</name>
        <addressOffset>0x66c</addressOffset>
        <size>0x20</size>
      </register>
      <register>
        <name>FGCLUT.156</name>
        <addressOffset>0x670</addressOffset>
        <size>0x20</size>
      </register>
      <register>
        <name>FGCLUT.157</name>
        <addressOffset>0x674</addressOffset>
        <size>0x20</size>
      </register>
      <register>
        <name>FGCLUT.158</name>
        <addressOffset>0x678</addressOffset>
        <size>0x20</size>
      </register>
      <register>
        <name>FGCLUT.159</name>
        <addressOffset>0x67c</addressOffset>
        <size>0x20</size>
      </register>
      <register>
        <name>FGCLUT.160</name>
        <addressOffset>0x680</addressOffset>
        <size>0x20</size>
      </register>
      <register>
        <name>FGCLUT.161</name>
        <addressOffset>0x684</addressOffset>
        <size>0x20</size>
      </register>
      <register>
        <name>FGCLUT.162</name>
        <addressOffset>0x688</addressOffset>
        <size>0x20</size>
      </register>
      <register>
        <name>FGCLUT.163</name>
        <addressOffset>0x68c</addressOffset>
        <size>0x20</size>
      </register>
      <register>
        <name>FGCLUT.164</name>
        <addressOffset>0x690</addressOffset>
        <size>0x20</size>
      </register>
      <register>
        <name>FGCLUT.165</name>
        <addressOffset>0x694</addressOffset>
        <size>0x20</size>
      </register>
      <register>
        <name>FGCLUT.166</name>
        <addressOffset>0x698</addressOffset>
        <size>0x20</size>
      </register>
      <register>
        <name>FGCLUT.167</name>
        <addressOffset>0x69c</addressOffset>
        <size>0x20</size>
      </register>
      <register>
        <name>FGCLUT.168</name>
        <addressOffset>0x6a0</addressOffset>
        <size>0x20</size>
      </register>
      <register>
        <name>FGCLUT.169</name>
        <addressOffset>0x6a4</addressOffset>
        <size>0x20</size>
      </register>
      <register>
        <name>FGCLUT.170</name>
        <addressOffset>0x6a8</addressOffset>
        <size>0x20</size>
      </register>
      <register>
        <name>FGCLUT.171</name>
        <addressOffset>0x6ac</addressOffset>
        <size>0x20</size>
      </register>
      <register>
        <name>FGCLUT.172</name>
        <addressOffset>0x6b0</addressOffset>
        <size>0x20</size>
      </register>
      <register>
        <name>FGCLUT.173</name>
        <addressOffset>0x6b4</addressOffset>
        <size>0x20</size>
      </register>
      <register>
        <name>FGCLUT.174</name>
        <addressOffset>0x6b8</addressOffset>
        <size>0x20</size>
      </register>
      <register>
        <name>FGCLUT.175</name>
        <addressOffset>0x6bc</addressOffset>
        <size>0x20</size>
      </register>
      <register>
        <name>FGCLUT.176</name>
        <addressOffset>0x6c0</addressOffset>
        <size>0x20</size>
      </register>
      <register>
        <name>FGCLUT.177</name>
        <addressOffset>0x6c4</addressOffset>
        <size>0x20</size>
      </register>
      <register>
        <name>FGCLUT.178</name>
        <addressOffset>0x6c8</addressOffset>
        <size>0x20</size>
      </register>
      <register>
        <name>FGCLUT.179</name>
        <addressOffset>0x6cc</addressOffset>
        <size>0x20</size>
      </register>
      <register>
        <name>FGCLUT.180</name>
        <addressOffset>0x6d0</addressOffset>
        <size>0x20</size>
      </register>
      <register>
        <name>FGCLUT.181</name>
        <addressOffset>0x6d4</addressOffset>
        <size>0x20</size>
      </register>
      <register>
        <name>FGCLUT.182</name>
        <addressOffset>0x6d8</addressOffset>
        <size>0x20</size>
      </register>
      <register>
        <name>FGCLUT.183</name>
        <addressOffset>0x6dc</addressOffset>
        <size>0x20</size>
      </register>
      <register>
        <name>FGCLUT.184</name>
        <addressOffset>0x6e0</addressOffset>
        <size>0x20</size>
      </register>
      <register>
        <name>FGCLUT.185</name>
        <addressOffset>0x6e4</addressOffset>
        <size>0x20</size>
      </register>
      <register>
        <name>FGCLUT.186</name>
        <addressOffset>0x6e8</addressOffset>
        <size>0x20</size>
      </register>
      <register>
        <name>FGCLUT.187</name>
        <addressOffset>0x6ec</addressOffset>
        <size>0x20</size>
      </register>
      <register>
        <name>FGCLUT.188</name>
        <addressOffset>0x6f0</addressOffset>
        <size>0x20</size>
      </register>
      <register>
        <name>FGCLUT.189</name>
        <addressOffset>0x6f4</addressOffset>
        <size>0x20</size>
      </register>
      <register>
        <name>FGCLUT.190</name>
        <addressOffset>0x6f8</addressOffset>
        <size>0x20</size>
      </register>
      <register>
        <name>FGCLUT.191</name>
        <addressOffset>0x6fc</addressOffset>
        <size>0x20</size>
      </register>
      <register>
        <name>FGCLUT.192</name>
        <addressOffset>0x700</addressOffset>
        <size>0x20</size>
      </register>
      <register>
        <name>FGCLUT.193</name>
        <addressOffset>0x704</addressOffset>
        <size>0x20</size>
      </register>
      <register>
        <name>FGCLUT.194</name>
        <addressOffset>0x708</addressOffset>
        <size>0x20</size>
      </register>
      <register>
        <name>FGCLUT.195</name>
        <addressOffset>0x70c</addressOffset>
        <size>0x20</size>
      </register>
      <register>
        <name>FGCLUT.196</name>
        <addressOffset>0x710</addressOffset>
        <size>0x20</size>
      </register>
      <register>
        <name>FGCLUT.197</name>
        <addressOffset>0x714</addressOffset>
        <size>0x20</size>
      </register>
      <register>
        <name>FGCLUT.198</name>
        <addressOffset>0x718</addressOffset>
        <size>0x20</size>
      </register>
      <register>
        <name>FGCLUT.199</name>
        <addressOffset>0x71c</addressOffset>
        <size>0x20</size>
      </register>
      <register>
        <name>FGCLUT.200</name>
        <addressOffset>0x720</addressOffset>
        <size>0x20</size>
      </register>
      <register>
        <name>FGCLUT.201</name>
        <addressOffset>0x724</addressOffset>
        <size>0x20</size>
      </register>
      <register>
        <name>FGCLUT.202</name>
        <addressOffset>0x728</addressOffset>
        <size>0x20</size>
      </register>
      <register>
        <name>FGCLUT.203</name>
        <addressOffset>0x72c</addressOffset>
        <size>0x20</size>
      </register>
      <register>
        <name>FGCLUT.204</name>
        <addressOffset>0x730</addressOffset>
        <size>0x20</size>
      </register>
      <register>
        <name>FGCLUT.205</name>
        <addressOffset>0x734</addressOffset>
        <size>0x20</size>
      </register>
      <register>
        <name>FGCLUT.206</name>
        <addressOffset>0x738</addressOffset>
        <size>0x20</size>
      </register>
      <register>
        <name>FGCLUT.207</name>
        <addressOffset>0x73c</addressOffset>
        <size>0x20</size>
      </register>
      <register>
        <name>FGCLUT.208</name>
        <addressOffset>0x740</addressOffset>
        <size>0x20</size>
      </register>
      <register>
        <name>FGCLUT.209</name>
        <addressOffset>0x744</addressOffset>
        <size>0x20</size>
      </register>
      <register>
        <name>FGCLUT.210</name>
        <addressOffset>0x748</addressOffset>
        <size>0x20</size>
      </register>
      <register>
        <name>FGCLUT.211</name>
        <addressOffset>0x74c</addressOffset>
        <size>0x20</size>
      </register>
      <register>
        <name>FGCLUT.212</name>
        <addressOffset>0x750</addressOffset>
        <size>0x20</size>
      </register>
      <register>
        <name>FGCLUT.213</name>
        <addressOffset>0x754</addressOffset>
        <size>0x20</size>
      </register>
      <register>
        <name>FGCLUT.214</name>
        <addressOffset>0x758</addressOffset>
        <size>0x20</size>
      </register>
      <register>
        <name>FGCLUT.215</name>
        <addressOffset>0x75c</addressOffset>
        <size>0x20</size>
      </register>
      <register>
        <name>FGCLUT.216</name>
        <addressOffset>0x760</addressOffset>
        <size>0x20</size>
      </register>
      <register>
        <name>FGCLUT.217</name>
        <addressOffset>0x764</addressOffset>
        <size>0x20</size>
      </register>
      <register>
        <name>FGCLUT.218</name>
        <addressOffset>0x768</addressOffset>
        <size>0x20</size>
      </register>
      <register>
        <name>FGCLUT.219</name>
        <addressOffset>0x76c</addressOffset>
        <size>0x20</size>
      </register>
      <register>
        <name>FGCLUT.220</name>
        <addressOffset>0x770</addressOffset>
        <size>0x20</size>
      </register>
      <register>
        <name>FGCLUT.221</name>
        <addressOffset>0x774</addressOffset>
        <size>0x20</size>
      </register>
      <register>
        <name>FGCLUT.222</name>
        <addressOffset>0x778</addressOffset>
        <size>0x20</size>
      </register>
      <register>
        <name>FGCLUT.223</name>
        <addressOffset>0x77c</addressOffset>
        <size>0x20</size>
      </register>
      <register>
        <name>FGCLUT.224</name>
        <addressOffset>0x780</addressOffset>
        <size>0x20</size>
      </register>
      <register>
        <name>FGCLUT.225</name>
        <addressOffset>0x784</addressOffset>
        <size>0x20</size>
      </register>
      <register>
        <name>FGCLUT.226</name>
        <addressOffset>0x788</addressOffset>
        <size>0x20</size>
      </register>
      <register>
        <name>FGCLUT.227</name>
        <addressOffset>0x78c</addressOffset>
        <size>0x20</size>
      </register>
      <register>
        <name>FGCLUT.228</name>
        <addressOffset>0x790</addressOffset>
        <size>0x20</size>
      </register>
      <register>
        <name>FGCLUT.229</name>
        <addressOffset>0x794</addressOffset>
        <size>0x20</size>
      </register>
      <register>
        <name>FGCLUT.230</name>
        <addressOffset>0x798</addressOffset>
        <size>0x20</size>
      </register>
      <register>
        <name>FGCLUT.231</name>
        <addressOffset>0x79c</addressOffset>
        <size>0x20</size>
      </register>
      <register>
        <name>FGCLUT.232</name>
        <addressOffset>0x7a0</addressOffset>
        <size>0x20</size>
      </register>
      <register>
        <name>FGCLUT.233</name>
        <addressOffset>0x7a4</addressOffset>
        <size>0x20</size>
      </register>
      <register>
        <name>FGCLUT.234</name>
        <addressOffset>0x7a8</addressOffset>
        <size>0x20</size>
      </register>
      <register>
        <name>FGCLUT.235</name>
        <addressOffset>0x7ac</addressOffset>
        <size>0x20</size>
      </register>
      <register>
        <name>FGCLUT.236</name>
        <addressOffset>0x7b0</addressOffset>
        <size>0x20</size>
      </register>
      <register>
        <name>FGCLUT.237</name>
        <addressOffset>0x7b4</addressOffset>
        <size>0x20</size>
      </register>
      <register>
        <name>FGCLUT.238</name>
        <addressOffset>0x7b8</addressOffset>
        <size>0x20</size>
      </register>
      <register>
        <name>FGCLUT.239</name>
        <addressOffset>0x7bc</addressOffset>
        <size>0x20</size>
      </register>
      <register>
        <name>FGCLUT.240</name>
        <addressOffset>0x7c0</addressOffset>
        <size>0x20</size>
      </register>
      <register>
        <name>FGCLUT.241</name>
        <addressOffset>0x7c4</addressOffset>
        <size>0x20</size>
      </register>
      <register>
        <name>FGCLUT.242</name>
        <addressOffset>0x7c8</addressOffset>
        <size>0x20</size>
      </register>
      <register>
        <name>FGCLUT.243</name>
        <addressOffset>0x7cc</addressOffset>
        <size>0x20</size>
      </register>
      <register>
        <name>FGCLUT.244</name>
        <addressOffset>0x7d0</addressOffset>
        <size>0x20</size>
      </register>
      <register>
        <name>FGCLUT.245</name>
        <addressOffset>0x7d4</addressOffset>
        <size>0x20</size>
      </register>
      <register>
        <name>FGCLUT.246</name>
        <addressOffset>0x7d8</addressOffset>
        <size>0x20</size>
      </register>
      <register>
        <name>FGCLUT.247</name>
        <addressOffset>0x7dc</addressOffset>
        <size>0x20</size>
      </register>
      <register>
        <name>FGCLUT.248</name>
        <addressOffset>0x7e0</addressOffset>
        <size>0x20</size>
      </register>
      <register>
        <name>FGCLUT.249</name>
        <addressOffset>0x7e4</addressOffset>
        <size>0x20</size>
      </register>
      <register>
        <name>FGCLUT.250</name>
        <addressOffset>0x7e8</addressOffset>
        <size>0x20</size>
      </register>
      <register>
        <name>FGCLUT.251</name>
        <addressOffset>0x7ec</addressOffset>
        <size>0x20</size>
      </register>
      <register>
        <name>FGCLUT.252</name>
        <addressOffset>0x7f0</addressOffset>
        <size>0x20</size>
      </register>
      <register>
        <name>FGCLUT.253</name>
        <addressOffset>0x7f4</addressOffset>
        <size>0x20</size>
      </register>
      <register>
        <name>FGCLUT.254</name>
        <addressOffset>0x7f8</addressOffset>
        <size>0x20</size>
      </register>
      <register>
        <name>FGCLUT.255</name>
        <addressOffset>0x7fc</addressOffset>
        <size>0x20</size>
      </register>
      <register>
        <name>BGCLUT.0</name>
        <addressOffset>0x800</addressOffset>
        <size>0x20</size>
      </register>
      <register>
        <name>BGCLUT.1</name>
        <addressOffset>0x804</addressOffset>
        <size>0x20</size>
      </register>
      <register>
        <name>BGCLUT.2</name>
        <addressOffset>0x808</addressOffset>
        <size>0x20</size>
      </register>
      <register>
        <name>BGCLUT.3</name>
        <addressOffset>0x80c</addressOffset>
        <size>0x20</size>
      </register>
      <register>
        <name>BGCLUT.4</name>
        <addressOffset>0x810</addressOffset>
        <size>0x20</size>
      </register>
      <register>
        <name>BGCLUT.5</name>
        <addressOffset>0x814</addressOffset>
        <size>0x20</size>
      </register>
      <register>
        <name>BGCLUT.6</name>
        <addressOffset>0x818</addressOffset>
        <size>0x20</size>
      </register>
      <register>
        <name>BGCLUT.7</name>
        <addressOffset>0x81c</addressOffset>
        <size>0x20</size>
      </register>
      <register>
        <name>BGCLUT.8</name>
        <addressOffset>0x820</addressOffset>
        <size>0x20</size>
      </register>
      <register>
        <name>BGCLUT.9</name>
        <addressOffset>0x824</addressOffset>
        <size>0x20</size>
      </register>
      <register>
        <name>BGCLUT.10</name>
        <addressOffset>0x828</addressOffset>
        <size>0x20</size>
      </register>
      <register>
        <name>BGCLUT.11</name>
        <addressOffset>0x82c</addressOffset>
        <size>0x20</size>
      </register>
      <register>
        <name>BGCLUT.12</name>
        <addressOffset>0x830</addressOffset>
        <size>0x20</size>
      </register>
      <register>
        <name>BGCLUT.13</name>
        <addressOffset>0x834</addressOffset>
        <size>0x20</size>
      </register>
      <register>
        <name>BGCLUT.14</name>
        <addressOffset>0x838</addressOffset>
        <size>0x20</size>
      </register>
      <register>
        <name>BGCLUT.15</name>
        <addressOffset>0x83c</addressOffset>
        <size>0x20</size>
      </register>
      <register>
        <name>BGCLUT.16</name>
        <addressOffset>0x840</addressOffset>
        <size>0x20</size>
      </register>
      <register>
        <name>BGCLUT.17</name>
        <addressOffset>0x844</addressOffset>
        <size>0x20</size>
      </register>
      <register>
        <name>BGCLUT.18</name>
        <addressOffset>0x848</addressOffset>
        <size>0x20</size>
      </register>
      <register>
        <name>BGCLUT.19</name>
        <addressOffset>0x84c</addressOffset>
        <size>0x20</size>
      </register>
      <register>
        <name>BGCLUT.20</name>
        <addressOffset>0x850</addressOffset>
        <size>0x20</size>
      </register>
      <register>
        <name>BGCLUT.21</name>
        <addressOffset>0x854</addressOffset>
        <size>0x20</size>
      </register>
      <register>
        <name>BGCLUT.22</name>
        <addressOffset>0x858</addressOffset>
        <size>0x20</size>
      </register>
      <register>
        <name>BGCLUT.23</name>
        <addressOffset>0x85c</addressOffset>
        <size>0x20</size>
      </register>
      <register>
        <name>BGCLUT.24</name>
        <addressOffset>0x860</addressOffset>
        <size>0x20</size>
      </register>
      <register>
        <name>BGCLUT.25</name>
        <addressOffset>0x864</addressOffset>
        <size>0x20</size>
      </register>
      <register>
        <name>BGCLUT.26</name>
        <addressOffset>0x868</addressOffset>
        <size>0x20</size>
      </register>
      <register>
        <name>BGCLUT.27</name>
        <addressOffset>0x86c</addressOffset>
        <size>0x20</size>
      </register>
      <register>
        <name>BGCLUT.28</name>
        <addressOffset>0x870</addressOffset>
        <size>0x20</size>
      </register>
      <register>
        <name>BGCLUT.29</name>
        <addressOffset>0x874</addressOffset>
        <size>0x20</size>
      </register>
      <register>
        <name>BGCLUT.30</name>
        <addressOffset>0x878</addressOffset>
        <size>0x20</size>
      </register>
      <register>
        <name>BGCLUT.31</name>
        <addressOffset>0x87c</addressOffset>
        <size>0x20</size>
      </register>
      <register>
        <name>BGCLUT.32</name>
        <addressOffset>0x880</addressOffset>
        <size>0x20</size>
      </register>
      <register>
        <name>BGCLUT.33</name>
        <addressOffset>0x884</addressOffset>
        <size>0x20</size>
      </register>
      <register>
        <name>BGCLUT.34</name>
        <addressOffset>0x888</addressOffset>
        <size>0x20</size>
      </register>
      <register>
        <name>BGCLUT.35</name>
        <addressOffset>0x88c</addressOffset>
        <size>0x20</size>
      </register>
      <register>
        <name>BGCLUT.36</name>
        <addressOffset>0x890</addressOffset>
        <size>0x20</size>
      </register>
      <register>
        <name>BGCLUT.37</name>
        <addressOffset>0x894</addressOffset>
        <size>0x20</size>
      </register>
      <register>
        <name>BGCLUT.38</name>
        <addressOffset>0x898</addressOffset>
        <size>0x20</size>
      </register>
      <register>
        <name>BGCLUT.39</name>
        <addressOffset>0x89c</addressOffset>
        <size>0x20</size>
      </register>
      <register>
        <name>BGCLUT.40</name>
        <addressOffset>0x8a0</addressOffset>
        <size>0x20</size>
      </register>
      <register>
        <name>BGCLUT.41</name>
        <addressOffset>0x8a4</addressOffset>
        <size>0x20</size>
      </register>
      <register>
        <name>BGCLUT.42</name>
        <addressOffset>0x8a8</addressOffset>
        <size>0x20</size>
      </register>
      <register>
        <name>BGCLUT.43</name>
        <addressOffset>0x8ac</addressOffset>
        <size>0x20</size>
      </register>
      <register>
        <name>BGCLUT.44</name>
        <addressOffset>0x8b0</addressOffset>
        <size>0x20</size>
      </register>
      <register>
        <name>BGCLUT.45</name>
        <addressOffset>0x8b4</addressOffset>
        <size>0x20</size>
      </register>
      <register>
        <name>BGCLUT.46</name>
        <addressOffset>0x8b8</addressOffset>
        <size>0x20</size>
      </register>
      <register>
        <name>BGCLUT.47</name>
        <addressOffset>0x8bc</addressOffset>
        <size>0x20</size>
      </register>
      <register>
        <name>BGCLUT.48</name>
        <addressOffset>0x8c0</addressOffset>
        <size>0x20</size>
      </register>
      <register>
        <name>BGCLUT.49</name>
        <addressOffset>0x8c4</addressOffset>
        <size>0x20</size>
      </register>
      <register>
        <name>BGCLUT.50</name>
        <addressOffset>0x8c8</addressOffset>
        <size>0x20</size>
      </register>
      <register>
        <name>BGCLUT.51</name>
        <addressOffset>0x8cc</addressOffset>
        <size>0x20</size>
      </register>
      <register>
        <name>BGCLUT.52</name>
        <addressOffset>0x8d0</addressOffset>
        <size>0x20</size>
      </register>
      <register>
        <name>BGCLUT.53</name>
        <addressOffset>0x8d4</addressOffset>
        <size>0x20</size>
      </register>
      <register>
        <name>BGCLUT.54</name>
        <addressOffset>0x8d8</addressOffset>
        <size>0x20</size>
      </register>
      <register>
        <name>BGCLUT.55</name>
        <addressOffset>0x8dc</addressOffset>
        <size>0x20</size>
      </register>
      <register>
        <name>BGCLUT.56</name>
        <addressOffset>0x8e0</addressOffset>
        <size>0x20</size>
      </register>
      <register>
        <name>BGCLUT.57</name>
        <addressOffset>0x8e4</addressOffset>
        <size>0x20</size>
      </register>
      <register>
        <name>BGCLUT.58</name>
        <addressOffset>0x8e8</addressOffset>
        <size>0x20</size>
      </register>
      <register>
        <name>BGCLUT.59</name>
        <addressOffset>0x8ec</addressOffset>
        <size>0x20</size>
      </register>
      <register>
        <name>BGCLUT.60</name>
        <addressOffset>0x8f0</addressOffset>
        <size>0x20</size>
      </register>
      <register>
        <name>BGCLUT.61</name>
        <addressOffset>0x8f4</addressOffset>
        <size>0x20</size>
      </register>
      <register>
        <name>BGCLUT.62</name>
        <addressOffset>0x8f8</addressOffset>
        <size>0x20</size>
      </register>
      <register>
        <name>BGCLUT.63</name>
        <addressOffset>0x8fc</addressOffset>
        <size>0x20</size>
      </register>
      <register>
        <name>BGCLUT.64</name>
        <addressOffset>0x900</addressOffset>
        <size>0x20</size>
      </register>
      <register>
        <name>BGCLUT.65</name>
        <addressOffset>0x904</addressOffset>
        <size>0x20</size>
      </register>
      <register>
        <name>BGCLUT.66</name>
        <addressOffset>0x908</addressOffset>
        <size>0x20</size>
      </register>
      <register>
        <name>BGCLUT.67</name>
        <addressOffset>0x90c</addressOffset>
        <size>0x20</size>
      </register>
      <register>
        <name>BGCLUT.68</name>
        <addressOffset>0x910</addressOffset>
        <size>0x20</size>
      </register>
      <register>
        <name>BGCLUT.69</name>
        <addressOffset>0x914</addressOffset>
        <size>0x20</size>
      </register>
      <register>
        <name>BGCLUT.70</name>
        <addressOffset>0x918</addressOffset>
        <size>0x20</size>
      </register>
      <register>
        <name>BGCLUT.71</name>
        <addressOffset>0x91c</addressOffset>
        <size>0x20</size>
      </register>
      <register>
        <name>BGCLUT.72</name>
        <addressOffset>0x920</addressOffset>
        <size>0x20</size>
      </register>
      <register>
        <name>BGCLUT.73</name>
        <addressOffset>0x924</addressOffset>
        <size>0x20</size>
      </register>
      <register>
        <name>BGCLUT.74</name>
        <addressOffset>0x928</addressOffset>
        <size>0x20</size>
      </register>
      <register>
        <name>BGCLUT.75</name>
        <addressOffset>0x92c</addressOffset>
        <size>0x20</size>
      </register>
      <register>
        <name>BGCLUT.76</name>
        <addressOffset>0x930</addressOffset>
        <size>0x20</size>
      </register>
      <register>
        <name>BGCLUT.77</name>
        <addressOffset>0x934</addressOffset>
        <size>0x20</size>
      </register>
      <register>
        <name>BGCLUT.78</name>
        <addressOffset>0x938</addressOffset>
        <size>0x20</size>
      </register>
      <register>
        <name>BGCLUT.79</name>
        <addressOffset>0x93c</addressOffset>
        <size>0x20</size>
      </register>
      <register>
        <name>BGCLUT.80</name>
        <addressOffset>0x940</addressOffset>
        <size>0x20</size>
      </register>
      <register>
        <name>BGCLUT.81</name>
        <addressOffset>0x944</addressOffset>
        <size>0x20</size>
      </register>
      <register>
        <name>BGCLUT.82</name>
        <addressOffset>0x948</addressOffset>
        <size>0x20</size>
      </register>
      <register>
        <name>BGCLUT.83</name>
        <addressOffset>0x94c</addressOffset>
        <size>0x20</size>
      </register>
      <register>
        <name>BGCLUT.84</name>
        <addressOffset>0x950</addressOffset>
        <size>0x20</size>
      </register>
      <register>
        <name>BGCLUT.85</name>
        <addressOffset>0x954</addressOffset>
        <size>0x20</size>
      </register>
      <register>
        <name>BGCLUT.86</name>
        <addressOffset>0x958</addressOffset>
        <size>0x20</size>
      </register>
      <register>
        <name>BGCLUT.87</name>
        <addressOffset>0x95c</addressOffset>
        <size>0x20</size>
      </register>
      <register>
        <name>BGCLUT.88</name>
        <addressOffset>0x960</addressOffset>
        <size>0x20</size>
      </register>
      <register>
        <name>BGCLUT.89</name>
        <addressOffset>0x964</addressOffset>
        <size>0x20</size>
      </register>
      <register>
        <name>BGCLUT.90</name>
        <addressOffset>0x968</addressOffset>
        <size>0x20</size>
      </register>
      <register>
        <name>BGCLUT.91</name>
        <addressOffset>0x96c</addressOffset>
        <size>0x20</size>
      </register>
      <register>
        <name>BGCLUT.92</name>
        <addressOffset>0x970</addressOffset>
        <size>0x20</size>
      </register>
      <register>
        <name>BGCLUT.93</name>
        <addressOffset>0x974</addressOffset>
        <size>0x20</size>
      </register>
      <register>
        <name>BGCLUT.94</name>
        <addressOffset>0x978</addressOffset>
        <size>0x20</size>
      </register>
      <register>
        <name>BGCLUT.95</name>
        <addressOffset>0x97c</addressOffset>
        <size>0x20</size>
      </register>
      <register>
        <name>BGCLUT.96</name>
        <addressOffset>0x980</addressOffset>
        <size>0x20</size>
      </register>
      <register>
        <name>BGCLUT.97</name>
        <addressOffset>0x984</addressOffset>
        <size>0x20</size>
      </register>
      <register>
        <name>BGCLUT.98</name>
        <addressOffset>0x988</addressOffset>
        <size>0x20</size>
      </register>
      <register>
        <name>BGCLUT.99</name>
        <addressOffset>0x98c</addressOffset>
        <size>0x20</size>
      </register>
      <register>
        <name>BGCLUT.100</name>
        <addressOffset>0x990</addressOffset>
        <size>0x20</size>
      </register>
      <register>
        <name>BGCLUT.101</name>
        <addressOffset>0x994</addressOffset>
        <size>0x20</size>
      </register>
      <register>
        <name>BGCLUT.102</name>
        <addressOffset>0x998</addressOffset>
        <size>0x20</size>
      </register>
      <register>
        <name>BGCLUT.103</name>
        <addressOffset>0x99c</addressOffset>
        <size>0x20</size>
      </register>
      <register>
        <name>BGCLUT.104</name>
        <addressOffset>0x9a0</addressOffset>
        <size>0x20</size>
      </register>
      <register>
        <name>BGCLUT.105</name>
        <addressOffset>0x9a4</addressOffset>
        <size>0x20</size>
      </register>
      <register>
        <name>BGCLUT.106</name>
        <addressOffset>0x9a8</addressOffset>
        <size>0x20</size>
      </register>
      <register>
        <name>BGCLUT.107</name>
        <addressOffset>0x9ac</addressOffset>
        <size>0x20</size>
      </register>
      <register>
        <name>BGCLUT.108</name>
        <addressOffset>0x9b0</addressOffset>
        <size>0x20</size>
      </register>
      <register>
        <name>BGCLUT.109</name>
        <addressOffset>0x9b4</addressOffset>
        <size>0x20</size>
      </register>
      <register>
        <name>BGCLUT.110</name>
        <addressOffset>0x9b8</addressOffset>
        <size>0x20</size>
      </register>
      <register>
        <name>BGCLUT.111</name>
        <addressOffset>0x9bc</addressOffset>
        <size>0x20</size>
      </register>
      <register>
        <name>BGCLUT.112</name>
        <addressOffset>0x9c0</addressOffset>
        <size>0x20</size>
      </register>
      <register>
        <name>BGCLUT.113</name>
        <addressOffset>0x9c4</addressOffset>
        <size>0x20</size>
      </register>
      <register>
        <name>BGCLUT.114</name>
        <addressOffset>0x9c8</addressOffset>
        <size>0x20</size>
      </register>
      <register>
        <name>BGCLUT.115</name>
        <addressOffset>0x9cc</addressOffset>
        <size>0x20</size>
      </register>
      <register>
        <name>BGCLUT.116</name>
        <addressOffset>0x9d0</addressOffset>
        <size>0x20</size>
      </register>
      <register>
        <name>BGCLUT.117</name>
        <addressOffset>0x9d4</addressOffset>
        <size>0x20</size>
      </register>
      <register>
        <name>BGCLUT.118</name>
        <addressOffset>0x9d8</addressOffset>
        <size>0x20</size>
      </register>
      <register>
        <name>BGCLUT.119</name>
        <addressOffset>0x9dc</addressOffset>
        <size>0x20</size>
      </register>
      <register>
        <name>BGCLUT.120</name>
        <addressOffset>0x9e0</addressOffset>
        <size>0x20</size>
      </register>
      <register>
        <name>BGCLUT.121</name>
        <addressOffset>0x9e4</addressOffset>
        <size>0x20</size>
      </register>
      <register>
        <name>BGCLUT.122</name>
        <addressOffset>0x9e8</addressOffset>
        <size>0x20</size>
      </register>
      <register>
        <name>BGCLUT.123</name>
        <addressOffset>0x9ec</addressOffset>
        <size>0x20</size>
      </register>
      <register>
        <name>BGCLUT.124</name>
        <addressOffset>0x9f0</addressOffset>
        <size>0x20</size>
      </register>
      <register>
        <name>BGCLUT.125</name>
        <addressOffset>0x9f4</addressOffset>
        <size>0x20</size>
      </register>
      <register>
        <name>BGCLUT.126</name>
        <addressOffset>0x9f8</addressOffset>
        <size>0x20</size>
      </register>
      <register>
        <name>BGCLUT.127</name>
        <addressOffset>0x9fc</addressOffset>
        <size>0x20</size>
      </register>
      <register>
        <name>BGCLUT.128</name>
        <addressOffset>0xa00</addressOffset>
        <size>0x20</size>
      </register>
      <register>
        <name>BGCLUT.129</name>
        <addressOffset>0xa04</addressOffset>
        <size>0x20</size>
      </register>
      <register>
        <name>BGCLUT.130</name>
        <addressOffset>0xa08</addressOffset>
        <size>0x20</size>
      </register>
      <register>
        <name>BGCLUT.131</name>
        <addressOffset>0xa0c</addressOffset>
        <size>0x20</size>
      </register>
      <register>
        <name>BGCLUT.132</name>
        <addressOffset>0xa10</addressOffset>
        <size>0x20</size>
      </register>
      <register>
        <name>BGCLUT.133</name>
        <addressOffset>0xa14</addressOffset>
        <size>0x20</size>
      </register>
      <register>
        <name>BGCLUT.134</name>
        <addressOffset>0xa18</addressOffset>
        <size>0x20</size>
      </register>
      <register>
        <name>BGCLUT.135</name>
        <addressOffset>0xa1c</addressOffset>
        <size>0x20</size>
      </register>
      <register>
        <name>BGCLUT.136</name>
        <addressOffset>0xa20</addressOffset>
        <size>0x20</size>
      </register>
      <register>
        <name>BGCLUT.137</name>
        <addressOffset>0xa24</addressOffset>
        <size>0x20</size>
      </register>
      <register>
        <name>BGCLUT.138</name>
        <addressOffset>0xa28</addressOffset>
        <size>0x20</size>
      </register>
      <register>
        <name>BGCLUT.139</name>
        <addressOffset>0xa2c</addressOffset>
        <size>0x20</size>
      </register>
      <register>
        <name>BGCLUT.140</name>
        <addressOffset>0xa30</addressOffset>
        <size>0x20</size>
      </register>
      <register>
        <name>BGCLUT.141</name>
        <addressOffset>0xa34</addressOffset>
        <size>0x20</size>
      </register>
      <register>
        <name>BGCLUT.142</name>
        <addressOffset>0xa38</addressOffset>
        <size>0x20</size>
      </register>
      <register>
        <name>BGCLUT.143</name>
        <addressOffset>0xa3c</addressOffset>
        <size>0x20</size>
      </register>
      <register>
        <name>BGCLUT.144</name>
        <addressOffset>0xa40</addressOffset>
        <size>0x20</size>
      </register>
      <register>
        <name>BGCLUT.145</name>
        <addressOffset>0xa44</addressOffset>
        <size>0x20</size>
      </register>
      <register>
        <name>BGCLUT.146</name>
        <addressOffset>0xa48</addressOffset>
        <size>0x20</size>
      </register>
      <register>
        <name>BGCLUT.147</name>
        <addressOffset>0xa4c</addressOffset>
        <size>0x20</size>
      </register>
      <register>
        <name>BGCLUT.148</name>
        <addressOffset>0xa50</addressOffset>
        <size>0x20</size>
      </register>
      <register>
        <name>BGCLUT.149</name>
        <addressOffset>0xa54</addressOffset>
        <size>0x20</size>
      </register>
      <register>
        <name>BGCLUT.150</name>
        <addressOffset>0xa58</addressOffset>
        <size>0x20</size>
      </register>
      <register>
        <name>BGCLUT.151</name>
        <addressOffset>0xa5c</addressOffset>
        <size>0x20</size>
      </register>
      <register>
        <name>BGCLUT.152</name>
        <addressOffset>0xa60</addressOffset>
        <size>0x20</size>
      </register>
      <register>
        <name>BGCLUT.153</name>
        <addressOffset>0xa64</addressOffset>
        <size>0x20</size>
      </register>
      <register>
        <name>BGCLUT.154</name>
        <addressOffset>0xa68</addressOffset>
        <size>0x20</size>
      </register>
      <register>
        <name>BGCLUT.155</name>
        <addressOffset>0xa6c</addressOffset>
        <size>0x20</size>
      </register>
      <register>
        <name>BGCLUT.156</name>
        <addressOffset>0xa70</addressOffset>
        <size>0x20</size>
      </register>
      <register>
        <name>BGCLUT.157</name>
        <addressOffset>0xa74</addressOffset>
        <size>0x20</size>
      </register>
      <register>
        <name>BGCLUT.158</name>
        <addressOffset>0xa78</addressOffset>
        <size>0x20</size>
      </register>
      <register>
        <name>BGCLUT.159</name>
        <addressOffset>0xa7c</addressOffset>
        <size>0x20</size>
      </register>
      <register>
        <name>BGCLUT.160</name>
        <addressOffset>0xa80</addressOffset>
        <size>0x20</size>
      </register>
      <register>
        <name>BGCLUT.161</name>
        <addressOffset>0xa84</addressOffset>
        <size>0x20</size>
      </register>
      <register>
        <name>BGCLUT.162</name>
        <addressOffset>0xa88</addressOffset>
        <size>0x20</size>
      </register>
      <register>
        <name>BGCLUT.163</name>
        <addressOffset>0xa8c</addressOffset>
        <size>0x20</size>
      </register>
      <register>
        <name>BGCLUT.164</name>
        <addressOffset>0xa90</addressOffset>
        <size>0x20</size>
      </register>
      <register>
        <name>BGCLUT.165</name>
        <addressOffset>0xa94</addressOffset>
        <size>0x20</size>
      </register>
      <register>
        <name>BGCLUT.166</name>
        <addressOffset>0xa98</addressOffset>
        <size>0x20</size>
      </register>
      <register>
        <name>BGCLUT.167</name>
        <addressOffset>0xa9c</addressOffset>
        <size>0x20</size>
      </register>
      <register>
        <name>BGCLUT.168</name>
        <addressOffset>0xaa0</addressOffset>
        <size>0x20</size>
      </register>
      <register>
        <name>BGCLUT.169</name>
        <addressOffset>0xaa4</addressOffset>
        <size>0x20</size>
      </register>
      <register>
        <name>BGCLUT.170</name>
        <addressOffset>0xaa8</addressOffset>
        <size>0x20</size>
      </register>
      <register>
        <name>BGCLUT.171</name>
        <addressOffset>0xaac</addressOffset>
        <size>0x20</size>
      </register>
      <register>
        <name>BGCLUT.172</name>
        <addressOffset>0xab0</addressOffset>
        <size>0x20</size>
      </register>
      <register>
        <name>BGCLUT.173</name>
        <addressOffset>0xab4</addressOffset>
        <size>0x20</size>
      </register>
      <register>
        <name>BGCLUT.174</name>
        <addressOffset>0xab8</addressOffset>
        <size>0x20</size>
      </register>
      <register>
        <name>BGCLUT.175</name>
        <addressOffset>0xabc</addressOffset>
        <size>0x20</size>
      </register>
      <register>
        <name>BGCLUT.176</name>
        <addressOffset>0xac0</addressOffset>
        <size>0x20</size>
      </register>
      <register>
        <name>BGCLUT.177</name>
        <addressOffset>0xac4</addressOffset>
        <size>0x20</size>
      </register>
      <register>
        <name>BGCLUT.178</name>
        <addressOffset>0xac8</addressOffset>
        <size>0x20</size>
      </register>
      <register>
        <name>BGCLUT.179</name>
        <addressOffset>0xacc</addressOffset>
        <size>0x20</size>
      </register>
      <register>
        <name>BGCLUT.180</name>
        <addressOffset>0xad0</addressOffset>
        <size>0x20</size>
      </register>
      <register>
        <name>BGCLUT.181</name>
        <addressOffset>0xad4</addressOffset>
        <size>0x20</size>
      </register>
      <register>
        <name>BGCLUT.182</name>
        <addressOffset>0xad8</addressOffset>
        <size>0x20</size>
      </register>
      <register>
        <name>BGCLUT.183</name>
        <addressOffset>0xadc</addressOffset>
        <size>0x20</size>
      </register>
      <register>
        <name>BGCLUT.184</name>
        <addressOffset>0xae0</addressOffset>
        <size>0x20</size>
      </register>
      <register>
        <name>BGCLUT.185</name>
        <addressOffset>0xae4</addressOffset>
        <size>0x20</size>
      </register>
      <register>
        <name>BGCLUT.186</name>
        <addressOffset>0xae8</addressOffset>
        <size>0x20</size>
      </register>
      <register>
        <name>BGCLUT.187</name>
        <addressOffset>0xaec</addressOffset>
        <size>0x20</size>
      </register>
      <register>
        <name>BGCLUT.188</name>
        <addressOffset>0xaf0</addressOffset>
        <size>0x20</size>
      </register>
      <register>
        <name>BGCLUT.189</name>
        <addressOffset>0xaf4</addressOffset>
        <size>0x20</size>
      </register>
      <register>
        <name>BGCLUT.190</name>
        <addressOffset>0xaf8</addressOffset>
        <size>0x20</size>
      </register>
      <register>
        <name>BGCLUT.191</name>
        <addressOffset>0xafc</addressOffset>
        <size>0x20</size>
      </register>
      <register>
        <name>BGCLUT.192</name>
        <addressOffset>0xb00</addressOffset>
        <size>0x20</size>
      </register>
      <register>
        <name>BGCLUT.193</name>
        <addressOffset>0xb04</addressOffset>
        <size>0x20</size>
      </register>
      <register>
        <name>BGCLUT.194</name>
        <addressOffset>0xb08</addressOffset>
        <size>0x20</size>
      </register>
      <register>
        <name>BGCLUT.195</name>
        <addressOffset>0xb0c</addressOffset>
        <size>0x20</size>
      </register>
      <register>
        <name>BGCLUT.196</name>
        <addressOffset>0xb10</addressOffset>
        <size>0x20</size>
      </register>
      <register>
        <name>BGCLUT.197</name>
        <addressOffset>0xb14</addressOffset>
        <size>0x20</size>
      </register>
      <register>
        <name>BGCLUT.198</name>
        <addressOffset>0xb18</addressOffset>
        <size>0x20</size>
      </register>
      <register>
        <name>BGCLUT.199</name>
        <addressOffset>0xb1c</addressOffset>
        <size>0x20</size>
      </register>
      <register>
        <name>BGCLUT.200</name>
        <addressOffset>0xb20</addressOffset>
        <size>0x20</size>
      </register>
      <register>
        <name>BGCLUT.201</name>
        <addressOffset>0xb24</addressOffset>
        <size>0x20</size>
      </register>
      <register>
        <name>BGCLUT.202</name>
        <addressOffset>0xb28</addressOffset>
        <size>0x20</size>
      </register>
      <register>
        <name>BGCLUT.203</name>
        <addressOffset>0xb2c</addressOffset>
        <size>0x20</size>
      </register>
      <register>
        <name>BGCLUT.204</name>
        <addressOffset>0xb30</addressOffset>
        <size>0x20</size>
      </register>
      <register>
        <name>BGCLUT.205</name>
        <addressOffset>0xb34</addressOffset>
        <size>0x20</size>
      </register>
      <register>
        <name>BGCLUT.206</name>
        <addressOffset>0xb38</addressOffset>
        <size>0x20</size>
      </register>
      <register>
        <name>BGCLUT.207</name>
        <addressOffset>0xb3c</addressOffset>
        <size>0x20</size>
      </register>
      <register>
        <name>BGCLUT.208</name>
        <addressOffset>0xb40</addressOffset>
        <size>0x20</size>
      </register>
      <register>
        <name>BGCLUT.209</name>
        <addressOffset>0xb44</addressOffset>
        <size>0x20</size>
      </register>
      <register>
        <name>BGCLUT.210</name>
        <addressOffset>0xb48</addressOffset>
        <size>0x20</size>
      </register>
      <register>
        <name>BGCLUT.211</name>
        <addressOffset>0xb4c</addressOffset>
        <size>0x20</size>
      </register>
      <register>
        <name>BGCLUT.212</name>
        <addressOffset>0xb50</addressOffset>
        <size>0x20</size>
      </register>
      <register>
        <name>BGCLUT.213</name>
        <addressOffset>0xb54</addressOffset>
        <size>0x20</size>
      </register>
      <register>
        <name>BGCLUT.214</name>
        <addressOffset>0xb58</addressOffset>
        <size>0x20</size>
      </register>
      <register>
        <name>BGCLUT.215</name>
        <addressOffset>0xb5c</addressOffset>
        <size>0x20</size>
      </register>
      <register>
        <name>BGCLUT.216</name>
        <addressOffset>0xb60</addressOffset>
        <size>0x20</size>
      </register>
      <register>
        <name>BGCLUT.217</name>
        <addressOffset>0xb64</addressOffset>
        <size>0x20</size>
      </register>
      <register>
        <name>BGCLUT.218</name>
        <addressOffset>0xb68</addressOffset>
        <size>0x20</size>
      </register>
      <register>
        <name>BGCLUT.219</name>
        <addressOffset>0xb6c</addressOffset>
        <size>0x20</size>
      </register>
      <register>
        <name>BGCLUT.220</name>
        <addressOffset>0xb70</addressOffset>
        <size>0x20</size>
      </register>
      <register>
        <name>BGCLUT.221</name>
        <addressOffset>0xb74</addressOffset>
        <size>0x20</size>
      </register>
      <register>
        <name>BGCLUT.222</name>
        <addressOffset>0xb78</addressOffset>
        <size>0x20</size>
      </register>
      <register>
        <name>BGCLUT.223</name>
        <addressOffset>0xb7c</addressOffset>
        <size>0x20</size>
      </register>
      <register>
        <name>BGCLUT.224</name>
        <addressOffset>0xb80</addressOffset>
        <size>0x20</size>
      </register>
      <register>
        <name>BGCLUT.225</name>
        <addressOffset>0xb84</addressOffset>
        <size>0x20</size>
      </register>
      <register>
        <name>BGCLUT.226</name>
        <addressOffset>0xb88</addressOffset>
        <size>0x20</size>
      </register>
      <register>
        <name>BGCLUT.227</name>
        <addressOffset>0xb8c</addressOffset>
        <size>0x20</size>
      </register>
      <register>
        <name>BGCLUT.228</name>
        <addressOffset>0xb90</addressOffset>
        <size>0x20</size>
      </register>
      <register>
        <name>BGCLUT.229</name>
        <addressOffset>0xb94</addressOffset>
        <size>0x20</size>
      </register>
      <register>
        <name>BGCLUT.230</name>
        <addressOffset>0xb98</addressOffset>
        <size>0x20</size>
      </register>
      <register>
        <name>BGCLUT.231</name>
        <addressOffset>0xb9c</addressOffset>
        <size>0x20</size>
      </register>
      <register>
        <name>BGCLUT.232</name>
        <addressOffset>0xba0</addressOffset>
        <size>0x20</size>
      </register>
      <register>
        <name>BGCLUT.233</name>
        <addressOffset>0xba4</addressOffset>
        <size>0x20</size>
      </register>
      <register>
        <name>BGCLUT.234</name>
        <addressOffset>0xba8</addressOffset>
        <size>0x20</size>
      </register>
      <register>
        <name>BGCLUT.235</name>
        <addressOffset>0xbac</addressOffset>
        <size>0x20</size>
      </register>
      <register>
        <name>BGCLUT.236</name>
        <addressOffset>0xbb0</addressOffset>
        <size>0x20</size>
      </register>
      <register>
        <name>BGCLUT.237</name>
        <addressOffset>0xbb4</addressOffset>
        <size>0x20</size>
      </register>
      <register>
        <name>BGCLUT.238</name>
        <addressOffset>0xbb8</addressOffset>
        <size>0x20</size>
      </register>
      <register>
        <name>BGCLUT.239</name>
        <addressOffset>0xbbc</addressOffset>
        <size>0x20</size>
      </register>
      <register>
        <name>BGCLUT.240</name>
        <addressOffset>0xbc0</addressOffset>
        <size>0x20</size>
      </register>
      <register>
        <name>BGCLUT.241</name>
        <addressOffset>0xbc4</addressOffset>
        <size>0x20</size>
      </register>
      <register>
        <name>BGCLUT.242</name>
        <addressOffset>0xbc8</addressOffset>
        <size>0x20</size>
      </register>
      <register>
        <name>BGCLUT.243</name>
        <addressOffset>0xbcc</addressOffset>
        <size>0x20</size>
      </register>
      <register>
        <name>BGCLUT.244</name>
        <addressOffset>0xbd0</addressOffset>
        <size>0x20</size>
      </register>
      <register>
        <name>BGCLUT.245</name>
        <addressOffset>0xbd4</addressOffset>
        <size>0x20</size>
      </register>
      <register>
        <name>BGCLUT.246</name>
        <addressOffset>0xbd8</addressOffset>
        <size>0x20</size>
      </register>
      <register>
        <name>BGCLUT.247</name>
        <addressOffset>0xbdc</addressOffset>
        <size>0x20</size>
      </register>
      <register>
        <name>BGCLUT.248</name>
        <addressOffset>0xbe0</addressOffset>
        <size>0x20</size>
      </register>
      <register>
        <name>BGCLUT.249</name>
        <addressOffset>0xbe4</addressOffset>
        <size>0x20</size>
      </register>
      <register>
        <name>BGCLUT.250</name>
        <addressOffset>0xbe8</addressOffset>
        <size>0x20</size>
      </register>
      <register>
        <name>BGCLUT.251</name>
        <addressOffset>0xbec</addressOffset>
        <size>0x20</size>
      </register>
      <register>
        <name>BGCLUT.252</name>
        <addressOffset>0xbf0</addressOffset>
        <size>0x20</size>
      </register>
      <register>
        <name>BGCLUT.253</name>
        <addressOffset>0xbf4</addressOffset>
        <size>0x20</size>
      </register>
      <register>
        <name>BGCLUT.254</name>
        <addressOffset>0xbf8</addressOffset>
        <size>0x20</size>
      </register>
      <register>
        <name>BGCLUT.255</name>
        <addressOffset>0xbfc</addressOffset>
        <size>0x20</size>
      </register>
    </peripheral>
    <peripheral>
      <name>GPIOA</name>
      <baseAddress>0x48000000</baseAddress>
      <register>
        <name>MODER</name>
        <addressOffset>0x0</addressOffset>
        <size>0x20</size>
        <fields>
          <field>
            <name>MODE0</name>
            <bitOffset>0</bitOffset>
            <bitWidth>2</bitWidth>
          </field>
          <field>
            <name>MODE1</name>
            <bitOffset>2</bitOffset>
            <bitWidth>2</bitWidth>
          </field>
          <field>
            <name>MODE2</name>
            <bitOffset>4</bitOffset>
            <bitWidth>2</bitWidth>
          </field>
          <field>
            <name>MODE3</name>
            <bitOffset>6</bitOffset>
            <bitWidth>2</bitWidth>
          </field>
          <field>
            <name>MODE4</name>
            <bitOffset>8</bitOffset>
            <bitWidth>2</bitWidth>
          </field>
          <field>
            <name>MODE5</name>
            <bitOffset>10</bitOffset>
            <bitWidth>2</bitWidth>
          </field>
          <field>
            <name>MODE6</name>
            <bitOffset>12</bitOffset>
            <bitWidth>2</bitWidth>
          </field>
          <field>
            <name>MODE7</name>
            <bitOffset>14</bitOffset>
            <bitWidth>2</bitWidth>
          </field>
          <field>
            <name>MODE8</name>
            <bitOffset>16</bitOffset>
            <bitWidth>2</bitWidth>
          </field>
          <field>
            <name>MODE9</name>
            <bitOffset>18</bitOffset>
            <bitWidth>2</bitWidth>
          </field>
          <field>
            <name>MODE10</name>
            <bitOffset>20</bitOffset>
            <bitWidth>2</bitWidth>
          </field>
          <field>
            <name>MODE11</name>
            <bitOffset>22</bitOffset>
            <bitWidth>2</bitWidth>
          </field>
          <field>
            <name>MODE12</name>
            <bitOffset>24</bitOffset>
            <bitWidth>2</bitWidth>
          </field>
          <field>
            <name>MODE13</name>
            <bitOffset>26</bitOffset>
            <bitWidth>2</bitWidth>
          </field>
          <field>
            <name>MODE14</name>
            <bitOffset>28</bitOffset>
            <bitWidth>2</bitWidth>
          </field>
          <field>
            <name>MODE15</name>
            <bitOffset>30</bitOffset>
            <bitWidth>2</bitWidth>
          </field>
        </fields>
      </register>
      <register>
        <name>OTYPER</name>
        <addressOffset>0x4</addressOffset>
        <size>0x20</size>
        <fields>
          <field>
            <name>OT0</name>
            <bitOffset>0</bitOffset>
            <bitWidth>1</bitWidth>
          </field>
          <field>
            <name>OT1</name>
            <bitOffset>1</bitOffset>
            <bitWidth>1</bitWidth>
          </field>
          <field>
            <name>OT2</name>
            <bitOffset>2</bitOffset>
            <bitWidth>1</bitWidth>
          </field>
          <field>
            <name>OT3</name>
            <bitOffset>3</bitOffset>
            <bitWidth>1</bitWidth>
          </field>
          <field>
            <name>OT4</name>
            <bitOffset>4</bitOffset>
            <bitWidth>1</bitWidth>
          </field>
          <field>
            <name>OT5</name>
            <bitOffset>5</bitOffset>
            <bitWidth>1</bitWidth>
          </field>
          <field>
            <name>OT6</name>
            <bitOffset>6</bitOffset>
            <bitWidth>1</bitWidth>
          </field>
          <field>
            <name>OT7</name>
            <bitOffset>7</bitOffset>
            <bitWidth>1</bitWidth>
          </field>
          <field>
            <name>OT8</name>
            <bitOffset>8</bitOffset>
            <bitWidth>1</bitWidth>
          </field>
          <field>
            <name>OT9</name>
            <bitOffset>9</bitOffset>
            <bitWidth>1</bitWidth>
          </field>
          <field>
            <name>OT10</name>
            <bitOffset>10</bitOffset>
            <bitWidth>1</bitWidth>
          </field>
          <field>
            <name>OT11</name>
            <bitOffset>11</bitOffset>
            <bitWidth>1</bitWidth>
          </field>
          <field>
            <name>OT12</name>
            <bitOffset>12</bitOffset>
            <bitWidth>1</bitWidth>
          </field>
          <field>
            <name>OT13</name>
            <bitOffset>13</bitOffset>
            <bitWidth>1</bitWidth>
          </field>
          <field>
            <name>OT14</name>
            <bitOffset>14</bitOffset>
            <bitWidth>1</bitWidth>
          </field>
          <field>
            <name>OT15</name>
            <bitOffset>15</bitOffset>
            <bitWidth>1</bitWidth>
          </field>
        </fields>
      </register>
      <register>
        <name>OSPEEDR</name>
        <addressOffset>0x8</addressOffset>
        <size>0x20</size>
        <fields>
          <field>
            <name>OSPEED0</name>
            <bitOffset>0</bitOffset>
            <bitWidth>2</bitWidth>
          </field>
          <field>
            <name>OSPEED1</name>
            <bitOffset>2</bitOffset>
            <bitWidth>2</bitWidth>
          </field>
          <field>
            <name>OSPEED2</name>
            <bitOffset>4</bitOffset>
            <bitWidth>2</bitWidth>
          </field>
          <field>
            <name>OSPEED3</name>
            <bitOffset>6</bitOffset>
            <bitWidth>2</bitWidth>
          </field>
          <field>
            <name>OSPEED4</name>
            <bitOffset>8</bitOffset>
            <bitWidth>2</bitWidth>
          </field>
          <field>
            <name>OSPEED5</name>
            <bitOffset>10</bitOffset>
            <bitWidth>2</bitWidth>
          </field>
          <field>
            <name>OSPEED6</name>
            <bitOffset>12</bitOffset>
            <bitWidth>2</bitWidth>
          </field>
          <field>
            <name>OSPEED7</name>
            <bitOffset>14</bitOffset>
            <bitWidth>2</bitWidth>
          </field>
          <field>
            <name>OSPEED8</name>
            <bitOffset>16</bitOffset>
            <bitWidth>2</bitWidth>
          </field>
          <field>
            <name>OSPEED9</name>
            <bitOffset>18</bitOffset>
            <bitWidth>2</bitWidth>
          </field>
          <field>
            <name>OSPEED10</name>
            <bitOffset>20</bitOffset>
            <bitWidth>2</bitWidth>
          </field>
          <field>
            <name>OSPEED11</name>
            <bitOffset>22</bitOffset>
            <bitWidth>2</bitWidth>
          </field>
          <field>
            <name>OSPEED12</name>
            <bitOffset>24</bitOffset>
            <bitWidth>2</bitWidth>
          </field>
          <field>
            <name>OSPEED13</name>
            <bitOffset>26</bitOffset>
            <bitWidth>2</bitWidth>
          </field>
          <field>
            <name>OSPEED14</name>
            <bitOffset>28</bitOffset>
            <bitWidth>2</bitWidth>
          </field>
          <field>
            <name>OSPEED15</name>
            <bitOffset>30</bitOffset>
            <bitWidth>2</bitWidth>
          </field>
        </fields>
      </register>
      <register>
        <name>PUPDR</name>
        <addressOffset>0xc</addressOffset>
        <size>0x20</size>
        <fields>
          <field>
            <name>PUPD0</name>
            <bitOffset>0</bitOffset>
            <bitWidth>2</bitWidth>
          </field>
          <field>
            <name>PUPD1</name>
            <bitOffset>2</bitOffset>
            <bitWidth>2</bitWidth>
          </field>
          <field>
            <name>PUPD2</name>
            <bitOffset>4</bitOffset>
            <bitWidth>2</bitWidth>
          </field>
          <field>
            <name>PUPD3</name>
            <bitOffset>6</bitOffset>
            <bitWidth>2</bitWidth>
          </field>
          <field>
            <name>PUPD4</name>
            <bitOffset>8</bitOffset>
            <bitWidth>2</bitWidth>
          </field>
          <field>
            <name>PUPD5</name>
            <bitOffset>10</bitOffset>
            <bitWidth>2</bitWidth>
          </field>
          <field>
            <name>PUPD6</name>
            <bitOffset>12</bitOffset>
            <bitWidth>2</bitWidth>
          </field>
          <field>
            <name>PUPD7</name>
            <bitOffset>14</bitOffset>
            <bitWidth>2</bitWidth>
          </field>
          <field>
            <name>PUPD8</name>
            <bitOffset>16</bitOffset>
            <bitWidth>2</bitWidth>
          </field>
          <field>
            <name>PUPD9</name>
            <bitOffset>18</bitOffset>
            <bitWidth>2</bitWidth>
          </field>
          <field>
            <name>PUPD10</name>
            <bitOffset>20</bitOffset>
            <bitWidth>2</bitWidth>
          </field>
          <field>
            <name>PUPD11</name>
            <bitOffset>22</bitOffset>
            <bitWidth>2</bitWidth>
          </field>
          <field>
            <name>PUPD12</name>
            <bitOffset>24</bitOffset>
            <bitWidth>2</bitWidth>
          </field>
          <field>
            <name>PUPD13</name>
            <bitOffset>26</bitOffset>
            <bitWidth>2</bitWidth>
          </field>
          <field>
            <name>PUPD14</name>
            <bitOffset>28</bitOffset>
            <bitWidth>2</bitWidth>
          </field>
          <field>
            <name>PUPD15</name>
            <bitOffset>30</bitOffset>
            <bitWidth>2</bitWidth>
          </field>
        </fields>
      </register>
      <register>
        <name>IDR</name>
        <addressOffset>0x10</addressOffset>
        <size>0x20</size>
        <fields>
          <field>
            <name>ID0</name>
            <bitOffset>0</bitOffset>
            <bitWidth>1</bitWidth>
          </field>
          <field>
            <name>ID1</name>
            <bitOffset>1</bitOffset>
            <bitWidth>1</bitWidth>
          </field>
          <field>
            <name>ID2</name>
            <bitOffset>2</bitOffset>
            <bitWidth>1</bitWidth>
          </field>
          <field>
            <name>ID3</name>
            <bitOffset>3</bitOffset>
            <bitWidth>1</bitWidth>
          </field>
          <field>
            <name>ID4</name>
            <bitOffset>4</bitOffset>
            <bitWidth>1</bitWidth>
          </field>
          <field>
            <name>ID5</name>
            <bitOffset>5</bitOffset>
            <bitWidth>1</bitWidth>
          </field>
          <field>
            <name>ID6</name>
            <bitOffset>6</bitOffset>
            <bitWidth>1</bitWidth>
          </field>
          <field>
            <name>ID7</name>
            <bitOffset>7</bitOffset>
            <bitWidth>1</bitWidth>
          </field>
          <field>
            <name>ID8</name>
            <bitOffset>8</bitOffset>
            <bitWidth>1</bitWidth>
          </field>
          <field>
            <name>ID9</name>
            <bitOffset>9</bitOffset>
            <bitWidth>1</bitWidth>
          </field>
          <field>
            <name>ID10</name>
            <bitOffset>10</bitOffset>
            <bitWidth>1</bitWidth>
          </field>
          <field>
            <name>ID11</name>
            <bitOffset>11</bitOffset>
            <bitWidth>1</bitWidth>
          </field>
          <field>
            <name>ID12</name>
            <bitOffset>12</bitOffset>
            <bitWidth>1</bitWidth>
          </field>
          <field>
            <name>ID13</name>
            <bitOffset>13</bitOffset>
            <bitWidth>1</bitWidth>
          </field>
          <field>
            <name>ID14</name>
            <bitOffset>14</bitOffset>
            <bitWidth>1</bitWidth>
          </field>
          <field>
            <name>ID15</name>
            <bitOffset>15</bitOffset>
            <bitWidth>1</bitWidth>
          </field>
        </fields>
      </register>
      <register>
        <name>ODR</name>
        <addressOffset>0x14</addressOffset>
        <size>0x20</size>
        <fields>
          <field>
            <name>OD0</name>
            <bitOffset>0</bitOffset>
            <bitWidth>1</bitWidth>
          </field>
          <field>
            <name>OD1</name>
            <bitOffset>1</bitOffset>
            <bitWidth>1</bitWidth>
          </field>
          <field>
            <name>OD2</name>
            <bitOffset>2</bitOffset>
            <bitWidth>1</bitWidth>
          </field>
          <field>
            <name>OD3</name>
            <bitOffset>3</bitOffset>
            <bitWidth>1</bitWidth>
          </field>
          <field>
            <name>OD4</name>
            <bitOffset>4</bitOffset>
            <bitWidth>1</bitWidth>
          </field>
          <field>
            <name>OD5</name>
            <bitOffset>5</bitOffset>
            <bitWidth>1</bitWidth>
          </field>
          <field>
            <name>OD6</name>
            <bitOffset>6</bitOffset>
            <bitWidth>1</bitWidth>
          </field>
          <field>
            <name>OD7</name>
            <bitOffset>7</bitOffset>
            <bitWidth>1</bitWidth>
          </field>
          <field>
            <name>OD8</name>
            <bitOffset>8</bitOffset>
            <bitWidth>1</bitWidth>
          </field>
          <field>
            <name>OD9</name>
            <bitOffset>9</bitOffset>
            <bitWidth>1</bitWidth>
          </field>
          <field>
            <name>OD10</name>
            <bitOffset>10</bitOffset>
            <bitWidth>1</bitWidth>
          </field>
          <field>
            <name>OD11</name>
            <bitOffset>11</bitOffset>
            <bitWidth>1</bitWidth>
          </field>
          <field>
            <name>OD12</name>
            <bitOffset>12</bitOffset>
            <bitWidth>1</bitWidth>
          </field>
          <field>
            <name>OD13</name>
            <bitOffset>13</bitOffset>
            <bitWidth>1</bitWidth>
          </field>
          <field>
            <name>OD14</name>
            <bitOffset>14</bitOffset>
            <bitWidth>1</bitWidth>
          </field>
          <field>
            <name>OD15</name>
            <bitOffset>15</bitOffset>
            <bitWidth>1</bitWidth>
          </field>
        </fields>
      </register>
      <register>
        <name>BSRR</name>
        <addressOffset>0x18</addressOffset>
        <size>0x20</size>
        <fields>
          <field>
            <name>BS0</name>
            <bitOffset>0</bitOffset>
            <bitWidth>1</bitWidth>
          </field>
          <field>
            <name>BS1</name>
            <bitOffset>1</bitOffset>
            <bitWidth>1</bitWidth>
          </field>
          <field>
            <name>BS2</name>
            <bitOffset>2</bitOffset>
            <bitWidth>1</bitWidth>
          </field>
          <field>
            <name>BS3</name>
            <bitOffset>3</bitOffset>
            <bitWidth>1</bitWidth>
          </field>
          <field>
            <name>BS4</name>
            <bitOffset>4</bitOffset>
            <bitWidth>1</bitWidth>
          </field>
          <field>
            <name>BS5</name>
            <bitOffset>5</bitOffset>
            <bitWidth>1</bitWidth>
          </field>
          <field>
            <name>BS6</name>
            <bitOffset>6</bitOffset>
            <bitWidth>1</bitWidth>
          </field>
          <field>
            <name>BS7</name>
            <bitOffset>7</bitOffset>
            <bitWidth>1</bitWidth>
          </field>
          <field>
            <name>BS8</name>
            <bitOffset>8</bitOffset>
            <bitWidth>1</bitWidth>
          </field>
          <field>
            <name>BS9</name>
            <bitOffset>9</bitOffset>
            <bitWidth>1</bitWidth>
          </field>
          <field>
            <name>BS10</name>
            <bitOffset>10</bitOffset>
            <bitWidth>1</bitWidth>
          </field>
          <field>
            <name>BS11</name>
            <bitOffset>11</bitOffset>
            <bitWidth>1</bitWidth>
          </field>
          <field>
            <name>BS12</name>
            <bitOffset>12</bitOffset>
            <bitWidth>1</bitWidth>
          </field>
          <field>
            <name>BS13</name>
            <bitOffset>13</bitOffset>
            <bitWidth>1</bitWidth>
          </field>
          <field>
            <name>BS14</name>
            <bitOffset>14</bitOffset>
            <bitWidth>1</bitWidth>
          </field>
          <field>
            <name>BS15</name>
            <bitOffset>15</bitOffset>
            <bitWidth>1</bitWidth>
          </field>
          <field>
            <name>BR0</name>
            <bitOffset>16</bitOffset>
            <bitWidth>1</bitWidth>
          </field>
          <field>
            <name>BR1</name>
            <bitOffset>17</bitOffset>
            <bitWidth>1</bitWidth>
          </field>
          <field>
            <name>BR2</name>
            <bitOffset>18</bitOffset>
            <bitWidth>1</bitWidth>
          </field>
          <field>
            <name>BR3</name>
            <bitOffset>19</bitOffset>
            <bitWidth>1</bitWidth>
          </field>
          <field>
            <name>BR4</name>
            <bitOffset>20</bitOffset>
            <bitWidth>1</bitWidth>
          </field>
          <field>
            <name>BR5</name>
            <bitOffset>21</bitOffset>
            <bitWidth>1</bitWidth>
          </field>
          <field>
            <name>BR6</name>
            <bitOffset>22</bitOffset>
            <bitWidth>1</bitWidth>
          </field>
          <field>
            <name>BR7</name>
            <bitOffset>23</bitOffset>
            <bitWidth>1</bitWidth>
          </field>
          <field>
            <name>BR8</name>
            <bitOffset>24</bitOffset>
            <bitWidth>1</bitWidth>
          </field>
          <field>
            <name>BR9</name>
            <bitOffset>25</bitOffset>
            <bitWidth>1</bitWidth>
          </field>
          <field>
            <name>BR10</name>
            <bitOffset>26</bitOffset>
            <bitWidth>1</bitWidth>
          </field>
          <field>
            <name>BR11</name>
            <bitOffset>27</bitOffset>
            <bitWidth>1</bitWidth>
          </field>
          <field>
            <name>BR12</name>
            <bitOffset>28</bitOffset>
            <bitWidth>1</bitWidth>
          </field>
          <field>
            <name>BR13</name>
            <bitOffset>29</bitOffset>
            <bitWidth>1</bitWidth>
          </field>
          <field>
            <name>BR14</name>
            <bitOffset>30</bitOffset>
            <bitWidth>1</bitWidth>
          </field>
          <field>
            <name>BR15</name>
            <bitOffset>31</bitOffset>
            <bitWidth>1</bitWidth>
          </field>
        </fields>
      </register>
      <register>
        <name>LCKR</name>
        <addressOffset>0x1c</addressOffset>
        <size>0x20</size>
        <fields>
          <field>
            <name>LCK0</name>
            <bitOffset>0</bitOffset>
            <bitWidth>1</bitWidth>
          </field>
          <field>
            <name>LCK1</name>
            <bitOffset>1</bitOffset>
            <bitWidth>1</bitWidth>
          </field>
          <field>
            <name>LCK2</name>
            <bitOffset>2</bitOffset>
            <bitWidth>1</bitWidth>
          </field>
          <field>
            <name>LCK3</name>
            <bitOffset>3</bitOffset>
            <bitWidth>1</bitWidth>
          </field>
          <field>
            <name>LCK4</name>
            <bitOffset>4</bitOffset>
            <bitWidth>1</bitWidth>
          </field>
          <field>
            <name>LCK5</name>
            <bitOffset>5</bitOffset>
            <bitWidth>1</bitWidth>
          </field>
          <field>
            <name>LCK6</name>
            <bitOffset>6</bitOffset>
            <bitWidth>1</bitWidth>
          </field>
          <field>
            <name>LCK7</name>
            <bitOffset>7</bitOffset>
            <bitWidth>1</bitWidth>
          </field>
          <field>
            <name>LCK8</name>
            <bitOffset>8</bitOffset>
            <bitWidth>1</bitWidth>
          </field>
          <field>
            <name>LCK9</name>
            <bitOffset>9</bitOffset>
            <bitWidth>1</bitWidth>
          </field>
          <field>
            <name>LCK10</name>
            <bitOffset>10</bitOffset>
            <bitWidth>1</bitWidth>
          </field>
          <field>
            <name>LCK11</name>
            <bitOffset>11</bitOffset>
            <bitWidth>1</bitWidth>
          </field>
          <field>
            <name>LCK12</name>
            <bitOffset>12</bitOffset>
            <bitWidth>1</bitWidth>
          </field>
          <field>
            <name>LCK13</name>
            <bitOffset>13</bitOffset>
            <bitWidth>1</bitWidth>
          </field>
          <field>
            <name>LCK14</name>
            <bitOffset>14</bitOffset>
            <bitWidth>1</bitWidth>
          </field>
          <field>
            <name>LCK15</name>
            <bitOffset>15</bitOffset>
            <bitWidth>1</bitWidth>
          </field>
          <field>
            <name>LCKK</name>
            <bitOffset>16</bitOffset>
            <bitWidth>1</bitWidth>
          </field>
        </fields>
      </register>
      <register>
        <name>AFR.0</name>
        <addressOffset>0x20</addressOffset>
        <size>0x20</size>
        <fields>
          <field>
            <name>AFSEL0</name>
            <bitOffset>0</bitOffset>
            <bitWidth>4</bitWidth>
          </field>
          <field>
            <name>AFSEL1</name>
            <bitOffset>4</bitOffset>
            <bitWidth>4</bitWidth>
          </field>
          <field>
            <name>AFSEL2</name>
            <bitOffset>8</bitOffset>
            <bitWidth>4</bitWidth>
          </field>
          <field>
            <name>AFSEL3</name>
            <bitOffset>12</bitOffset>
            <bitWidth>4</bitWidth>
          </field>
          <field>
            <name>AFSEL4</name>
            <bitOffset>16</bitOffset>
            <bitWidth>4</bitWidth>
          </field>
          <field>
            <name>AFSEL5</name>
            <bitOffset>20</bitOffset>
            <bitWidth>4</bitWidth>
          </field>
          <field>
            <name>AFSEL6</name>
            <bitOffset>24</bitOffset>
            <bitWidth>4</bitWidth>
          </field>
          <field>
            <name>AFSEL7</name>
            <bitOffset>28</bitOffset>
            <bitWidth>4</bitWidth>
          </field>
        </fields>
      </register>
      <register>
        <name>AFR.1</name>
        <addressOffset>0x24</addressOffset>
        <size>0x20</size>
        <fields>
          <field>
            <name>AFSEL8</name>
            <bitOffset>0</bitOffset>
            <bitWidth>4</bitWidth>
          </field>
          <field>
            <name>AFSEL9</name>
            <bitOffset>4</bitOffset>
            <bitWidth>4</bitWidth>
          </field>
          <field>
            <name>AFSEL10</name>
            <bitOffset>8</bitOffset>
            <bitWidth>4</bitWidth>
          </field>
          <field>
            <name>AFSEL11</name>
            <bitOffset>12</bitOffset>
            <bitWidth>4</bitWidth>
          </field>
          <field>
            <name>AFSEL12</name>
            <bitOffset>16</bitOffset>
            <bitWidth>4</bitWidth>
          </field>
          <field>
            <name>AFSEL13</name>
            <bitOffset>20</bitOffset>
            <bitWidth>4</bitWidth>
          </field>
          <field>
            <name>AFSEL14</name>
            <bitOffset>24</bitOffset>
            <bitWidth>4</bitWidth>
          </field>
          <field>
            <name>AFSEL15</name>
            <bitOffset>28</bitOffset>
            <bitWidth>4</bitWidth>
          </field>
        </fields>
      </register>
      <register>
        <name>BRR</name>
        <addressOffset>0x28</addressOffset>
        <size>0x20</size>
        <fields>
          <field>
            <name>BR0</name>
            <bitOffset>0</bitOffset>
            <bitWidth>1</bitWidth>
          </field>
          <field>
            <name>BR1</name>
            <bitOffset>1</bitOffset>
            <bitWidth>1</bitWidth>
          </field>
          <field>
            <name>BR2</name>
            <bitOffset>2</bitOffset>
            <bitWidth>1</bitWidth>
          </field>
          <field>
            <name>BR3</name>
            <bitOffset>3</bitOffset>
            <bitWidth>1</bitWidth>
          </field>
          <field>
            <name>BR4</name>
            <bitOffset>4</bitOffset>
            <bitWidth>1</bitWidth>
          </field>
          <field>
            <name>BR5</name>
            <bitOffset>5</bitOffset>
            <bitWidth>1</bitWidth>
          </field>
          <field>
            <name>BR6</name>
            <bitOffset>6</bitOffset>
            <bitWidth>1</bitWidth>
          </field>
          <field>
            <name>BR7</name>
            <bitOffset>7</bitOffset>
            <bitWidth>1</bitWidth>
          </field>
          <field>
            <name>BR8</name>
            <bitOffset>8</bitOffset>
            <bitWidth>1</bitWidth>
          </field>
          <field>
            <name>BR9</name>
            <bitOffset>9</bitOffset>
            <bitWidth>1</bitWidth>
          </field>
          <field>
            <name>BR10</name>
            <bitOffset>10</bitOffset>
            <bitWidth>1</bitWidth>
          </field>
          <field>
            <name>BR11</name>
            <bitOffset>11</bitOffset>
            <bitWidth>1</bitWidth>
          </field>
          <field>
            <name>BR12</name>
            <bitOffset>12</bitOffset>
            <bitWidth>1</bitWidth>
          </field>
          <field>
            <name>BR13</name>
            <bitOffset>13</bitOffset>
            <bitWidth>1</bitWidth>
          </field>
          <field>
            <name>BR14</name>
            <bitOffset>14</bitOffset>
            <bitWidth>1</bitWidth>
          </field>
          <field>
            <name>BR15</name>
            <bitOffset>15</bitOffset>
            <bitWidth>1</bitWidth>
          </field>
        </fields>
      </register>
    </peripheral>
    <peripheral>
      <name>GPIOB</name>
      <baseAddress>0x48000400</baseAddress>
      <register>
        <name>MODER</name>
        <addressOffset>0x0</addressOffset>
        <size>0x20</size>
        <fields>
          <field>
            <name>MODE0</name>
            <bitOffset>0</bitOffset>
            <bitWidth>2</bitWidth>
          </field>
          <field>
            <name>MODE1</name>
            <bitOffset>2</bitOffset>
            <bitWidth>2</bitWidth>
          </field>
          <field>
            <name>MODE2</name>
            <bitOffset>4</bitOffset>
            <bitWidth>2</bitWidth>
          </field>
          <field>
            <name>MODE3</name>
            <bitOffset>6</bitOffset>
            <bitWidth>2</bitWidth>
          </field>
          <field>
            <name>MODE4</name>
            <bitOffset>8</bitOffset>
            <bitWidth>2</bitWidth>
          </field>
          <field>
            <name>MODE5</name>
            <bitOffset>10</bitOffset>
            <bitWidth>2</bitWidth>
          </field>
          <field>
            <name>MODE6</name>
            <bitOffset>12</bitOffset>
            <bitWidth>2</bitWidth>
          </field>
          <field>
            <name>MODE7</name>
            <bitOffset>14</bitOffset>
            <bitWidth>2</bitWidth>
          </field>
          <field>
            <name>MODE8</name>
            <bitOffset>16</bitOffset>
            <bitWidth>2</bitWidth>
          </field>
          <field>
            <name>MODE9</name>
            <bitOffset>18</bitOffset>
            <bitWidth>2</bitWidth>
          </field>
          <field>
            <name>MODE10</name>
            <bitOffset>20</bitOffset>
            <bitWidth>2</bitWidth>
          </field>
          <field>
            <name>MODE11</name>
            <bitOffset>22</bitOffset>
            <bitWidth>2</bitWidth>
          </field>
          <field>
            <name>MODE12</name>
            <bitOffset>24</bitOffset>
            <bitWidth>2</bitWidth>
          </field>
          <field>
            <name>MODE13</name>
            <bitOffset>26</bitOffset>
            <bitWidth>2</bitWidth>
          </field>
          <field>
            <name>MODE14</name>
            <bitOffset>28</bitOffset>
            <bitWidth>2</bitWidth>
          </field>
          <field>
            <name>MODE15</name>
            <bitOffset>30</bitOffset>
            <bitWidth>2</bitWidth>
          </field>
        </fields>
      </register>
      <register>
        <name>OTYPER</name>
        <addressOffset>0x4</addressOffset>
        <size>0x20</size>
        <fields>
          <field>
            <name>OT0</name>
            <bitOffset>0</bitOffset>
            <bitWidth>1</bitWidth>
          </field>
          <field>
            <name>OT1</name>
            <bitOffset>1</bitOffset>
            <bitWidth>1</bitWidth>
          </field>
          <field>
            <name>OT2</name>
            <bitOffset>2</bitOffset>
            <bitWidth>1</bitWidth>
          </field>
          <field>
            <name>OT3</name>
            <bitOffset>3</bitOffset>
            <bitWidth>1</bitWidth>
          </field>
          <field>
            <name>OT4</name>
            <bitOffset>4</bitOffset>
            <bitWidth>1</bitWidth>
          </field>
          <field>
            <name>OT5</name>
            <bitOffset>5</bitOffset>
            <bitWidth>1</bitWidth>
          </field>
          <field>
            <name>OT6</name>
            <bitOffset>6</bitOffset>
            <bitWidth>1</bitWidth>
          </field>
          <field>
            <name>OT7</name>
            <bitOffset>7</bitOffset>
            <bitWidth>1</bitWidth>
          </field>
          <field>
            <name>OT8</name>
            <bitOffset>8</bitOffset>
            <bitWidth>1</bitWidth>
          </field>
          <field>
            <name>OT9</name>
            <bitOffset>9</bitOffset>
            <bitWidth>1</bitWidth>
          </field>
          <field>
            <name>OT10</name>
            <bitOffset>10</bitOffset>
            <bitWidth>1</bitWidth>
          </field>
          <field>
            <name>OT11</name>
            <bitOffset>11</bitOffset>
            <bitWidth>1</bitWidth>
          </field>
          <field>
            <name>OT12</name>
            <bitOffset>12</bitOffset>
            <bitWidth>1</bitWidth>
          </field>
          <field>
            <name>OT13</name>
            <bitOffset>13</bitOffset>
            <bitWidth>1</bitWidth>
          </field>
          <field>
            <name>OT14</name>
            <bitOffset>14</bitOffset>
            <bitWidth>1</bitWidth>
          </field>
          <field>
            <name>OT15</name>
            <bitOffset>15</bitOffset>
            <bitWidth>1</bitWidth>
          </field>
        </fields>
      </register>
      <register>
        <name>OSPEEDR</name>
        <addressOffset>0x8</addressOffset>
        <size>0x20</size>
        <fields>
          <field>
            <name>OSPEED0</name>
            <bitOffset>0</bitOffset>
            <bitWidth>2</bitWidth>
          </field>
          <field>
            <name>OSPEED1</name>
            <bitOffset>2</bitOffset>
            <bitWidth>2</bitWidth>
          </field>
          <field>
            <name>OSPEED2</name>
            <bitOffset>4</bitOffset>
            <bitWidth>2</bitWidth>
          </field>
          <field>
            <name>OSPEED3</name>
            <bitOffset>6</bitOffset>
            <bitWidth>2</bitWidth>
          </field>
          <field>
            <name>OSPEED4</name>
            <bitOffset>8</bitOffset>
            <bitWidth>2</bitWidth>
          </field>
          <field>
            <name>OSPEED5</name>
            <bitOffset>10</bitOffset>
            <bitWidth>2</bitWidth>
          </field>
          <field>
            <name>OSPEED6</name>
            <bitOffset>12</bitOffset>
            <bitWidth>2</bitWidth>
          </field>
          <field>
            <name>OSPEED7</name>
            <bitOffset>14</bitOffset>
            <bitWidth>2</bitWidth>
          </field>
          <field>
            <name>OSPEED8</name>
            <bitOffset>16</bitOffset>
            <bitWidth>2</bitWidth>
          </field>
          <field>
            <name>OSPEED9</name>
            <bitOffset>18</bitOffset>
            <bitWidth>2</bitWidth>
          </field>
          <field>
            <name>OSPEED10</name>
            <bitOffset>20</bitOffset>
            <bitWidth>2</bitWidth>
          </field>
          <field>
            <name>OSPEED11</name>
            <bitOffset>22</bitOffset>
            <bitWidth>2</bitWidth>
          </field>
          <field>
            <name>OSPEED12</name>
            <bitOffset>24</bitOffset>
            <bitWidth>2</bitWidth>
          </field>
          <field>
            <name>OSPEED13</name>
            <bitOffset>26</bitOffset>
            <bitWidth>2</bitWidth>
          </field>
          <field>
            <name>OSPEED14</name>
            <bitOffset>28</bitOffset>
            <bitWidth>2</bitWidth>
          </field>
          <field>
            <name>OSPEED15</name>
            <bitOffset>30</bitOffset>
            <bitWidth>2</bitWidth>
          </field>
        </fields>
      </register>
      <register>
        <name>PUPDR</name>
        <addressOffset>0xc</addressOffset>
        <size>0x20</size>
        <fields>
          <field>
            <name>PUPD0</name>
            <bitOffset>0</bitOffset>
            <bitWidth>2</bitWidth>
          </field>
          <field>
            <name>PUPD1</name>
            <bitOffset>2</bitOffset>
            <bitWidth>2</bitWidth>
          </field>
          <field>
            <name>PUPD2</name>
            <bitOffset>4</bitOffset>
            <bitWidth>2</bitWidth>
          </field>
          <field>
            <name>PUPD3</name>
            <bitOffset>6</bitOffset>
            <bitWidth>2</bitWidth>
          </field>
          <field>
            <name>PUPD4</name>
            <bitOffset>8</bitOffset>
            <bitWidth>2</bitWidth>
          </field>
          <field>
            <name>PUPD5</name>
            <bitOffset>10</bitOffset>
            <bitWidth>2</bitWidth>
          </field>
          <field>
            <name>PUPD6</name>
            <bitOffset>12</bitOffset>
            <bitWidth>2</bitWidth>
          </field>
          <field>
            <name>PUPD7</name>
            <bitOffset>14</bitOffset>
            <bitWidth>2</bitWidth>
          </field>
          <field>
            <name>PUPD8</name>
            <bitOffset>16</bitOffset>
            <bitWidth>2</bitWidth>
          </field>
          <field>
            <name>PUPD9</name>
            <bitOffset>18</bitOffset>
            <bitWidth>2</bitWidth>
          </field>
          <field>
            <name>PUPD10</name>
            <bitOffset>20</bitOffset>
            <bitWidth>2</bitWidth>
          </field>
          <field>
            <name>PUPD11</name>
            <bitOffset>22</bitOffset>
            <bitWidth>2</bitWidth>
          </field>
          <field>
            <name>PUPD12</name>
            <bitOffset>24</bitOffset>
            <bitWidth>2</bitWidth>
          </field>
          <field>
            <name>PUPD13</name>
            <bitOffset>26</bitOffset>
            <bitWidth>2</bitWidth>
          </field>
          <field>
            <name>PUPD14</name>
            <bitOffset>28</bitOffset>
            <bitWidth>2</bitWidth>
          </field>
          <field>
            <name>PUPD15</name>
            <bitOffset>30</bitOffset>
            <bitWidth>2</bitWidth>
          </field>
        </fields>
      </register>
      <register>
        <name>IDR</name>
        <addressOffset>0x10</addressOffset>
        <size>0x20</size>
        <fields>
          <field>
            <name>ID0</name>
            <bitOffset>0</bitOffset>
            <bitWidth>1</bitWidth>
          </field>
          <field>
            <name>ID1</name>
            <bitOffset>1</bitOffset>
            <bitWidth>1</bitWidth>
          </field>
          <field>
            <name>ID2</name>
            <bitOffset>2</bitOffset>
            <bitWidth>1</bitWidth>
          </field>
          <field>
            <name>ID3</name>
            <bitOffset>3</bitOffset>
            <bitWidth>1</bitWidth>
          </field>
          <field>
            <name>ID4</name>
            <bitOffset>4</bitOffset>
            <bitWidth>1</bitWidth>
          </field>
          <field>
            <name>ID5</name>
            <bitOffset>5</bitOffset>
            <bitWidth>1</bitWidth>
          </field>
          <field>
            <name>ID6</name>
            <bitOffset>6</bitOffset>
            <bitWidth>1</bitWidth>
          </field>
          <field>
            <name>ID7</name>
            <bitOffset>7</bitOffset>
            <bitWidth>1</bitWidth>
          </field>
          <field>
            <name>ID8</name>
            <bitOffset>8</bitOffset>
            <bitWidth>1</bitWidth>
          </field>
          <field>
            <name>ID9</name>
            <bitOffset>9</bitOffset>
            <bitWidth>1</bitWidth>
          </field>
          <field>
            <name>ID10</name>
            <bitOffset>10</bitOffset>
            <bitWidth>1</bitWidth>
          </field>
          <field>
            <name>ID11</name>
            <bitOffset>11</bitOffset>
            <bitWidth>1</bitWidth>
          </field>
          <field>
            <name>ID12</name>
            <bitOffset>12</bitOffset>
            <bitWidth>1</bitWidth>
          </field>
          <field>
            <name>ID13</name>
            <bitOffset>13</bitOffset>
            <bitWidth>1</bitWidth>
          </field>
          <field>
            <name>ID14</name>
            <bitOffset>14</bitOffset>
            <bitWidth>1</bitWidth>
          </field>
          <field>
            <name>ID15</name>
            <bitOffset>15</bitOffset>
            <bitWidth>1</bitWidth>
          </field>
        </fields>
      </register>
      <register>
        <name>ODR</name>
        <addressOffset>0x14</addressOffset>
        <size>0x20</size>
        <fields>
          <field>
            <name>OD0</name>
            <bitOffset>0</bitOffset>
            <bitWidth>1</bitWidth>
          </field>
          <field>
            <name>OD1</name>
            <bitOffset>1</bitOffset>
            <bitWidth>1</bitWidth>
          </field>
          <field>
            <name>OD2</name>
            <bitOffset>2</bitOffset>
            <bitWidth>1</bitWidth>
          </field>
          <field>
            <name>OD3</name>
            <bitOffset>3</bitOffset>
            <bitWidth>1</bitWidth>
          </field>
          <field>
            <name>OD4</name>
            <bitOffset>4</bitOffset>
            <bitWidth>1</bitWidth>
          </field>
          <field>
            <name>OD5</name>
            <bitOffset>5</bitOffset>
            <bitWidth>1</bitWidth>
          </field>
          <field>
            <name>OD6</name>
            <bitOffset>6</bitOffset>
            <bitWidth>1</bitWidth>
          </field>
          <field>
            <name>OD7</name>
            <bitOffset>7</bitOffset>
            <bitWidth>1</bitWidth>
          </field>
          <field>
            <name>OD8</name>
            <bitOffset>8</bitOffset>
            <bitWidth>1</bitWidth>
          </field>
          <field>
            <name>OD9</name>
            <bitOffset>9</bitOffset>
            <bitWidth>1</bitWidth>
          </field>
          <field>
            <name>OD10</name>
            <bitOffset>10</bitOffset>
            <bitWidth>1</bitWidth>
          </field>
          <field>
            <name>OD11</name>
            <bitOffset>11</bitOffset>
            <bitWidth>1</bitWidth>
          </field>
          <field>
            <name>OD12</name>
            <bitOffset>12</bitOffset>
            <bitWidth>1</bitWidth>
          </field>
          <field>
            <name>OD13</name>
            <bitOffset>13</bitOffset>
            <bitWidth>1</bitWidth>
          </field>
          <field>
            <name>OD14</name>
            <bitOffset>14</bitOffset>
            <bitWidth>1</bitWidth>
          </field>
          <field>
            <name>OD15</name>
            <bitOffset>15</bitOffset>
            <bitWidth>1</bitWidth>
          </field>
        </fields>
      </register>
      <register>
        <name>BSRR</name>
        <addressOffset>0x18</addressOffset>
        <size>0x20</size>
        <fields>
          <field>
            <name>BS0</name>
            <bitOffset>0</bitOffset>
            <bitWidth>1</bitWidth>
          </field>
          <field>
            <name>BS1</name>
            <bitOffset>1</bitOffset>
            <bitWidth>1</bitWidth>
          </field>
          <field>
            <name>BS2</name>
            <bitOffset>2</bitOffset>
            <bitWidth>1</bitWidth>
          </field>
          <field>
            <name>BS3</name>
            <bitOffset>3</bitOffset>
            <bitWidth>1</bitWidth>
          </field>
          <field>
            <name>BS4</name>
            <bitOffset>4</bitOffset>
            <bitWidth>1</bitWidth>
          </field>
          <field>
            <name>BS5</name>
            <bitOffset>5</bitOffset>
            <bitWidth>1</bitWidth>
          </field>
          <field>
            <name>BS6</name>
            <bitOffset>6</bitOffset>
            <bitWidth>1</bitWidth>
          </field>
          <field>
            <name>BS7</name>
            <bitOffset>7</bitOffset>
            <bitWidth>1</bitWidth>
          </field>
          <field>
            <name>BS8</name>
            <bitOffset>8</bitOffset>
            <bitWidth>1</bitWidth>
          </field>
          <field>
            <name>BS9</name>
            <bitOffset>9</bitOffset>
            <bitWidth>1</bitWidth>
          </field>
          <field>
            <name>BS10</name>
            <bitOffset>10</bitOffset>
            <bitWidth>1</bitWidth>
          </field>
          <field>
            <name>BS11</name>
            <bitOffset>11</bitOffset>
            <bitWidth>1</bitWidth>
          </field>
          <field>
            <name>BS12</name>
            <bitOffset>12</bitOffset>
            <bitWidth>1</bitWidth>
          </field>
          <field>
            <name>BS13</name>
            <bitOffset>13</bitOffset>
            <bitWidth>1</bitWidth>
          </field>
          <field>
            <name>BS14</name>
            <bitOffset>14</bitOffset>
            <bitWidth>1</bitWidth>
          </field>
          <field>
            <name>BS15</name>
            <bitOffset>15</bitOffset>
            <bitWidth>1</bitWidth>
          </field>
          <field>
            <name>BR0</name>
            <bitOffset>16</bitOffset>
            <bitWidth>1</bitWidth>
          </field>
          <field>
            <name>BR1</name>
            <bitOffset>17</bitOffset>
            <bitWidth>1</bitWidth>
          </field>
          <field>
            <name>BR2</name>
            <bitOffset>18</bitOffset>
            <bitWidth>1</bitWidth>
          </field>
          <field>
            <name>BR3</name>
            <bitOffset>19</bitOffset>
            <bitWidth>1</bitWidth>
          </field>
          <field>
            <name>BR4</name>
            <bitOffset>20</bitOffset>
            <bitWidth>1</bitWidth>
          </field>
          <field>
            <name>BR5</name>
            <bitOffset>21</bitOffset>
            <bitWidth>1</bitWidth>
          </field>
          <field>
            <name>BR6</name>
            <bitOffset>22</bitOffset>
            <bitWidth>1</bitWidth>
          </field>
          <field>
            <name>BR7</name>
            <bitOffset>23</bitOffset>
            <bitWidth>1</bitWidth>
          </field>
          <field>
            <name>BR8</name>
            <bitOffset>24</bitOffset>
            <bitWidth>1</bitWidth>
          </field>
          <field>
            <name>BR9</name>
            <bitOffset>25</bitOffset>
            <bitWidth>1</bitWidth>
          </field>
          <field>
            <name>BR10</name>
            <bitOffset>26</bitOffset>
            <bitWidth>1</bitWidth>
          </field>
          <field>
            <name>BR11</name>
            <bitOffset>27</bitOffset>
            <bitWidth>1</bitWidth>
          </field>
          <field>
            <name>BR12</name>
            <bitOffset>28</bitOffset>
            <bitWidth>1</bitWidth>
          </field>
          <field>
            <name>BR13</name>
            <bitOffset>29</bitOffset>
            <bitWidth>1</bitWidth>
          </field>
          <field>
            <name>BR14</name>
            <bitOffset>30</bitOffset>
            <bitWidth>1</bitWidth>
          </field>
          <field>
            <name>BR15</name>
            <bitOffset>31</bitOffset>
            <bitWidth>1</bitWidth>
          </field>
        </fields>
      </register>
      <register>
        <name>LCKR</name>
        <addressOffset>0x1c</addressOffset>
        <size>0x20</size>
        <fields>
          <field>
            <name>LCK0</name>
            <bitOffset>0</bitOffset>
            <bitWidth>1</bitWidth>
          </field>
          <field>
            <name>LCK1</name>
            <bitOffset>1</bitOffset>
            <bitWidth>1</bitWidth>
          </field>
          <field>
            <name>LCK2</name>
            <bitOffset>2</bitOffset>
            <bitWidth>1</bitWidth>
          </field>
          <field>
            <name>LCK3</name>
            <bitOffset>3</bitOffset>
            <bitWidth>1</bitWidth>
          </field>
          <field>
            <name>LCK4</name>
            <bitOffset>4</bitOffset>
            <bitWidth>1</bitWidth>
          </field>
          <field>
            <name>LCK5</name>
            <bitOffset>5</bitOffset>
            <bitWidth>1</bitWidth>
          </field>
          <field>
            <name>LCK6</name>
            <bitOffset>6</bitOffset>
            <bitWidth>1</bitWidth>
          </field>
          <field>
            <name>LCK7</name>
            <bitOffset>7</bitOffset>
            <bitWidth>1</bitWidth>
          </field>
          <field>
            <name>LCK8</name>
            <bitOffset>8</bitOffset>
            <bitWidth>1</bitWidth>
          </field>
          <field>
            <name>LCK9</name>
            <bitOffset>9</bitOffset>
            <bitWidth>1</bitWidth>
          </field>
          <field>
            <name>LCK10</name>
            <bitOffset>10</bitOffset>
            <bitWidth>1</bitWidth>
          </field>
          <field>
            <name>LCK11</name>
            <bitOffset>11</bitOffset>
            <bitWidth>1</bitWidth>
          </field>
          <field>
            <name>LCK12</name>
            <bitOffset>12</bitOffset>
            <bitWidth>1</bitWidth>
          </field>
          <field>
            <name>LCK13</name>
            <bitOffset>13</bitOffset>
            <bitWidth>1</bitWidth>
          </field>
          <field>
            <name>LCK14</name>
            <bitOffset>14</bitOffset>
            <bitWidth>1</bitWidth>
          </field>
          <field>
            <name>LCK15</name>
            <bitOffset>15</bitOffset>
            <bitWidth>1</bitWidth>
          </field>
          <field>
            <name>LCKK</name>
            <bitOffset>16</bitOffset>
            <bitWidth>1</bitWidth>
          </field>
        </fields>
      </register>
      <register>
        <name>AFR.0</name>
        <addressOffset>0x20</addressOffset>
        <size>0x20</size>
        <fields>
          <field>
            <name>AFSEL0</name>
            <bitOffset>0</bitOffset>
            <bitWidth>4</bitWidth>
          </field>
          <field>
            <name>AFSEL1</name>
            <bitOffset>4</bitOffset>
            <bitWidth>4</bitWidth>
          </field>
          <field>
            <name>AFSEL2</name>
            <bitOffset>8</bitOffset>
            <bitWidth>4</bitWidth>
          </field>
          <field>
            <name>AFSEL3</name>
            <bitOffset>12</bitOffset>
            <bitWidth>4</bitWidth>
          </field>
          <field>
            <name>AFSEL4</name>
            <bitOffset>16</bitOffset>
            <bitWidth>4</bitWidth>
          </field>
          <field>
            <name>AFSEL5</name>
            <bitOffset>20</bitOffset>
            <bitWidth>4</bitWidth>
          </field>
          <field>
            <name>AFSEL6</name>
            <bitOffset>24</bitOffset>
            <bitWidth>4</bitWidth>
          </field>
          <field>
            <name>AFSEL7</name>
            <bitOffset>28</bitOffset>
            <bitWidth>4</bitWidth>
          </field>
        </fields>
      </register>
      <register>
        <name>AFR.1</name>
        <addressOffset>0x24</addressOffset>
        <size>0x20</size>
        <fields>
          <field>
            <name>AFSEL8</name>
            <bitOffset>0</bitOffset>
            <bitWidth>4</bitWidth>
          </field>
          <field>
            <name>AFSEL9</name>
            <bitOffset>4</bitOffset>
            <bitWidth>4</bitWidth>
          </field>
          <field>
            <name>AFSEL10</name>
            <bitOffset>8</bitOffset>
            <bitWidth>4</bitWidth>
          </field>
          <field>
            <name>AFSEL11</name>
            <bitOffset>12</bitOffset>
            <bitWidth>4</bitWidth>
          </field>
          <field>
            <name>AFSEL12</name>
            <bitOffset>16</bitOffset>
            <bitWidth>4</bitWidth>
          </field>
          <field>
            <name>AFSEL13</name>
            <bitOffset>20</bitOffset>
            <bitWidth>4</bitWidth>
          </field>
          <field>
            <name>AFSEL14</name>
            <bitOffset>24</bitOffset>
            <bitWidth>4</bitWidth>
          </field>
          <field>
            <name>AFSEL15</name>
            <bitOffset>28</bitOffset>
            <bitWidth>4</bitWidth>
          </field>
        </fields>
      </register>
      <register>
        <name>BRR</name>
        <addressOffset>0x28</addressOffset>
        <size>0x20</size>
        <fields>
          <field>
            <name>BR0</name>
            <bitOffset>0</bitOffset>
            <bitWidth>1</bitWidth>
          </field>
          <field>
            <name>BR1</name>
            <bitOffset>1</bitOffset>
            <bitWidth>1</bitWidth>
          </field>
          <field>
            <name>BR2</name>
            <bitOffset>2</bitOffset>
            <bitWidth>1</bitWidth>
          </field>
          <field>
            <name>BR3</name>
            <bitOffset>3</bitOffset>
            <bitWidth>1</bitWidth>
          </field>
          <field>
            <name>BR4</name>
            <bitOffset>4</bitOffset>
            <bitWidth>1</bitWidth>
          </field>
          <field>
            <name>BR5</name>
            <bitOffset>5</bitOffset>
            <bitWidth>1</bitWidth>
          </field>
          <field>
            <name>BR6</name>
            <bitOffset>6</bitOffset>
            <bitWidth>1</bitWidth>
          </field>
          <field>
            <name>BR7</name>
            <bitOffset>7</bitOffset>
            <bitWidth>1</bitWidth>
          </field>
          <field>
            <name>BR8</name>
            <bitOffset>8</bitOffset>
            <bitWidth>1</bitWidth>
          </field>
          <field>
            <name>BR9</name>
            <bitOffset>9</bitOffset>
            <bitWidth>1</bitWidth>
          </field>
          <field>
            <name>BR10</name>
            <bitOffset>10</bitOffset>
            <bitWidth>1</bitWidth>
          </field>
          <field>
            <name>BR11</name>
            <bitOffset>11</bitOffset>
            <bitWidth>1</bitWidth>
          </field>
          <field>
            <name>BR12</name>
            <bitOffset>12</bitOffset>
            <bitWidth>1</bitWidth>
          </field>
          <field>
            <name>BR13</name>
            <bitOffset>13</bitOffset>
            <bitWidth>1</bitWidth>
          </field>
          <field>
            <name>BR14</name>
            <bitOffset>14</bitOffset>
            <bitWidth>1</bitWidth>
          </field>
          <field>
            <name>BR15</name>
            <bitOffset>15</bitOffset>
            <bitWidth>1</bitWidth>
          </field>
        </fields>
      </register>
    </peripheral>
    <peripheral>
      <name>GPIOC</name>
      <baseAddress>0x48000800</baseAddress>
      <register>
        <name>MODER</name>
        <addressOffset>0x0</addressOffset>
        <size>0x20</size>
        <fields>
          <field>
            <name>MODE0</name>
            <bitOffset>0</bitOffset>
            <bitWidth>2</bitWidth>
          </field>
          <field>
            <name>MODE1</name>
            <bitOffset>2</bitOffset>
            <bitWidth>2</bitWidth>
          </field>
          <field>
            <name>MODE2</name>
            <bitOffset>4</bitOffset>
            <bitWidth>2</bitWidth>
          </field>
          <field>
            <name>MODE3</name>
            <bitOffset>6</bitOffset>
            <bitWidth>2</bitWidth>
          </field>
          <field>
            <name>MODE4</name>
            <bitOffset>8</bitOffset>
            <bitWidth>2</bitWidth>
          </field>
          <field>
            <name>MODE5</name>
            <bitOffset>10</bitOffset>
            <bitWidth>2</bitWidth>
          </field>
          <field>
            <name>MODE6</name>
            <bitOffset>12</bitOffset>
            <bitWidth>2</bitWidth>
          </field>
          <field>
            <name>MODE7</name>
            <bitOffset>14</bitOffset>
            <bitWidth>2</bitWidth>
          </field>
          <field>
            <name>MODE8</name>
            <bitOffset>16</bitOffset>
            <bitWidth>2</bitWidth>
          </field>
          <field>
            <name>MODE9</name>
            <bitOffset>18</bitOffset>
            <bitWidth>2</bitWidth>
          </field>
          <field>
            <name>MODE10</name>
            <bitOffset>20</bitOffset>
            <bitWidth>2</bitWidth>
          </field>
          <field>
            <name>MODE11</name>
            <bitOffset>22</bitOffset>
            <bitWidth>2</bitWidth>
          </field>
          <field>
            <name>MODE12</name>
            <bitOffset>24</bitOffset>
            <bitWidth>2</bitWidth>
          </field>
          <field>
            <name>MODE13</name>
            <bitOffset>26</bitOffset>
            <bitWidth>2</bitWidth>
          </field>
          <field>
            <name>MODE14</name>
            <bitOffset>28</bitOffset>
            <bitWidth>2</bitWidth>
          </field>
          <field>
            <name>MODE15</name>
            <bitOffset>30</bitOffset>
            <bitWidth>2</bitWidth>
          </field>
        </fields>
      </register>
      <register>
        <name>OTYPER</name>
        <addressOffset>0x4</addressOffset>
        <size>0x20</size>
        <fields>
          <field>
            <name>OT0</name>
            <bitOffset>0</bitOffset>
            <bitWidth>1</bitWidth>
          </field>
          <field>
            <name>OT1</name>
            <bitOffset>1</bitOffset>
            <bitWidth>1</bitWidth>
          </field>
          <field>
            <name>OT2</name>
            <bitOffset>2</bitOffset>
            <bitWidth>1</bitWidth>
          </field>
          <field>
            <name>OT3</name>
            <bitOffset>3</bitOffset>
            <bitWidth>1</bitWidth>
          </field>
          <field>
            <name>OT4</name>
            <bitOffset>4</bitOffset>
            <bitWidth>1</bitWidth>
          </field>
          <field>
            <name>OT5</name>
            <bitOffset>5</bitOffset>
            <bitWidth>1</bitWidth>
          </field>
          <field>
            <name>OT6</name>
            <bitOffset>6</bitOffset>
            <bitWidth>1</bitWidth>
          </field>
          <field>
            <name>OT7</name>
            <bitOffset>7</bitOffset>
            <bitWidth>1</bitWidth>
          </field>
          <field>
            <name>OT8</name>
            <bitOffset>8</bitOffset>
            <bitWidth>1</bitWidth>
          </field>
          <field>
            <name>OT9</name>
            <bitOffset>9</bitOffset>
            <bitWidth>1</bitWidth>
          </field>
          <field>
            <name>OT10</name>
            <bitOffset>10</bitOffset>
            <bitWidth>1</bitWidth>
          </field>
          <field>
            <name>OT11</name>
            <bitOffset>11</bitOffset>
            <bitWidth>1</bitWidth>
          </field>
          <field>
            <name>OT12</name>
            <bitOffset>12</bitOffset>
            <bitWidth>1</bitWidth>
          </field>
          <field>
            <name>OT13</name>
            <bitOffset>13</bitOffset>
            <bitWidth>1</bitWidth>
          </field>
          <field>
            <name>OT14</name>
            <bitOffset>14</bitOffset>
            <bitWidth>1</bitWidth>
          </field>
          <field>
            <name>OT15</name>
            <bitOffset>15</bitOffset>
            <bitWidth>1</bitWidth>
          </field>
        </fields>
      </register>
      <register>
        <name>OSPEEDR</name>
        <addressOffset>0x8</addressOffset>
        <size>0x20</size>
        <fields>
          <field>
            <name>OSPEED0</name>
            <bitOffset>0</bitOffset>
            <bitWidth>2</bitWidth>
          </field>
          <field>
            <name>OSPEED1</name>
            <bitOffset>2</bitOffset>
            <bitWidth>2</bitWidth>
          </field>
          <field>
            <name>OSPEED2</name>
            <bitOffset>4</bitOffset>
            <bitWidth>2</bitWidth>
          </field>
          <field>
            <name>OSPEED3</name>
            <bitOffset>6</bitOffset>
            <bitWidth>2</bitWidth>
          </field>
          <field>
            <name>OSPEED4</name>
            <bitOffset>8</bitOffset>
            <bitWidth>2</bitWidth>
          </field>
          <field>
            <name>OSPEED5</name>
            <bitOffset>10</bitOffset>
            <bitWidth>2</bitWidth>
          </field>
          <field>
            <name>OSPEED6</name>
            <bitOffset>12</bitOffset>
            <bitWidth>2</bitWidth>
          </field>
          <field>
            <name>OSPEED7</name>
            <bitOffset>14</bitOffset>
            <bitWidth>2</bitWidth>
          </field>
          <field>
            <name>OSPEED8</name>
            <bitOffset>16</bitOffset>
            <bitWidth>2</bitWidth>
          </field>
          <field>
            <name>OSPEED9</name>
            <bitOffset>18</bitOffset>
            <bitWidth>2</bitWidth>
          </field>
          <field>
            <name>OSPEED10</name>
            <bitOffset>20</bitOffset>
            <bitWidth>2</bitWidth>
          </field>
          <field>
            <name>OSPEED11</name>
            <bitOffset>22</bitOffset>
            <bitWidth>2</bitWidth>
          </field>
          <field>
            <name>OSPEED12</name>
            <bitOffset>24</bitOffset>
            <bitWidth>2</bitWidth>
          </field>
          <field>
            <name>OSPEED13</name>
            <bitOffset>26</bitOffset>
            <bitWidth>2</bitWidth>
          </field>
          <field>
            <name>OSPEED14</name>
            <bitOffset>28</bitOffset>
            <bitWidth>2</bitWidth>
          </field>
          <field>
            <name>OSPEED15</name>
            <bitOffset>30</bitOffset>
            <bitWidth>2</bitWidth>
          </field>
        </fields>
      </register>
      <register>
        <name>PUPDR</name>
        <addressOffset>0xc</addressOffset>
        <size>0x20</size>
        <fields>
          <field>
            <name>PUPD0</name>
            <bitOffset>0</bitOffset>
            <bitWidth>2</bitWidth>
          </field>
          <field>
            <name>PUPD1</name>
            <bitOffset>2</bitOffset>
            <bitWidth>2</bitWidth>
          </field>
          <field>
            <name>PUPD2</name>
            <bitOffset>4</bitOffset>
            <bitWidth>2</bitWidth>
          </field>
          <field>
            <name>PUPD3</name>
            <bitOffset>6</bitOffset>
            <bitWidth>2</bitWidth>
          </field>
          <field>
            <name>PUPD4</name>
            <bitOffset>8</bitOffset>
            <bitWidth>2</bitWidth>
          </field>
          <field>
            <name>PUPD5</name>
            <bitOffset>10</bitOffset>
            <bitWidth>2</bitWidth>
          </field>
          <field>
            <name>PUPD6</name>
            <bitOffset>12</bitOffset>
            <bitWidth>2</bitWidth>
          </field>
          <field>
            <name>PUPD7</name>
            <bitOffset>14</bitOffset>
            <bitWidth>2</bitWidth>
          </field>
          <field>
            <name>PUPD8</name>
            <bitOffset>16</bitOffset>
            <bitWidth>2</bitWidth>
          </field>
          <field>
            <name>PUPD9</name>
            <bitOffset>18</bitOffset>
            <bitWidth>2</bitWidth>
          </field>
          <field>
            <name>PUPD10</name>
            <bitOffset>20</bitOffset>
            <bitWidth>2</bitWidth>
          </field>
          <field>
            <name>PUPD11</name>
            <bitOffset>22</bitOffset>
            <bitWidth>2</bitWidth>
          </field>
          <field>
            <name>PUPD12</name>
            <bitOffset>24</bitOffset>
            <bitWidth>2</bitWidth>
          </field>
          <field>
            <name>PUPD13</name>
            <bitOffset>26</bitOffset>
            <bitWidth>2</bitWidth>
          </field>
          <field>
            <name>PUPD14</name>
            <bitOffset>28</bitOffset>
            <bitWidth>2</bitWidth>
          </field>
          <field>
            <name>PUPD15</name>
            <bitOffset>30</bitOffset>
            <bitWidth>2</bitWidth>
          </field>
        </fields>
      </register>
      <register>
        <name>IDR</name>
        <addressOffset>0x10</addressOffset>
        <size>0x20</size>
        <fields>
          <field>
            <name>ID0</name>
            <bitOffset>0</bitOffset>
            <bitWidth>1</bitWidth>
          </field>
          <field>
            <name>ID1</name>
            <bitOffset>1</bitOffset>
            <bitWidth>1</bitWidth>
          </field>
          <field>
            <name>ID2</name>
            <bitOffset>2</bitOffset>
            <bitWidth>1</bitWidth>
          </field>
          <field>
            <name>ID3</name>
            <bitOffset>3</bitOffset>
            <bitWidth>1</bitWidth>
          </field>
          <field>
            <name>ID4</name>
            <bitOffset>4</bitOffset>
            <bitWidth>1</bitWidth>
          </field>
          <field>
            <name>ID5</name>
            <bitOffset>5</bitOffset>
            <bitWidth>1</bitWidth>
          </field>
          <field>
            <name>ID6</name>
            <bitOffset>6</bitOffset>
            <bitWidth>1</bitWidth>
          </field>
          <field>
            <name>ID7</name>
            <bitOffset>7</bitOffset>
            <bitWidth>1</bitWidth>
          </field>
          <field>
            <name>ID8</name>
            <bitOffset>8</bitOffset>
            <bitWidth>1</bitWidth>
          </field>
          <field>
            <name>ID9</name>
            <bitOffset>9</bitOffset>
            <bitWidth>1</bitWidth>
          </field>
          <field>
            <name>ID10</name>
            <bitOffset>10</bitOffset>
            <bitWidth>1</bitWidth>
          </field>
          <field>
            <name>ID11</name>
            <bitOffset>11</bitOffset>
            <bitWidth>1</bitWidth>
          </field>
          <field>
            <name>ID12</name>
            <bitOffset>12</bitOffset>
            <bitWidth>1</bitWidth>
          </field>
          <field>
            <name>ID13</name>
            <bitOffset>13</bitOffset>
            <bitWidth>1</bitWidth>
          </field>
          <field>
            <name>ID14</name>
            <bitOffset>14</bitOffset>
            <bitWidth>1</bitWidth>
          </field>
          <field>
            <name>ID15</name>
            <bitOffset>15</bitOffset>
            <bitWidth>1</bitWidth>
          </field>
        </fields>
      </register>
      <register>
        <name>ODR</name>
        <addressOffset>0x14</addressOffset>
        <size>0x20</size>
        <fields>
          <field>
            <name>OD0</name>
            <bitOffset>0</bitOffset>
            <bitWidth>1</bitWidth>
          </field>
          <field>
            <name>OD1</name>
            <bitOffset>1</bitOffset>
            <bitWidth>1</bitWidth>
          </field>
          <field>
            <name>OD2</name>
            <bitOffset>2</bitOffset>
            <bitWidth>1</bitWidth>
          </field>
          <field>
            <name>OD3</name>
            <bitOffset>3</bitOffset>
            <bitWidth>1</bitWidth>
          </field>
          <field>
            <name>OD4</name>
            <bitOffset>4</bitOffset>
            <bitWidth>1</bitWidth>
          </field>
          <field>
            <name>OD5</name>
            <bitOffset>5</bitOffset>
            <bitWidth>1</bitWidth>
          </field>
          <field>
            <name>OD6</name>
            <bitOffset>6</bitOffset>
            <bitWidth>1</bitWidth>
          </field>
          <field>
            <name>OD7</name>
            <bitOffset>7</bitOffset>
            <bitWidth>1</bitWidth>
          </field>
          <field>
            <name>OD8</name>
            <bitOffset>8</bitOffset>
            <bitWidth>1</bitWidth>
          </field>
          <field>
            <name>OD9</name>
            <bitOffset>9</bitOffset>
            <bitWidth>1</bitWidth>
          </field>
          <field>
            <name>OD10</name>
            <bitOffset>10</bitOffset>
            <bitWidth>1</bitWidth>
          </field>
          <field>
            <name>OD11</name>
            <bitOffset>11</bitOffset>
            <bitWidth>1</bitWidth>
          </field>
          <field>
            <name>OD12</name>
            <bitOffset>12</bitOffset>
            <bitWidth>1</bitWidth>
          </field>
          <field>
            <name>OD13</name>
            <bitOffset>13</bitOffset>
            <bitWidth>1</bitWidth>
          </field>
          <field>
            <name>OD14</name>
            <bitOffset>14</bitOffset>
            <bitWidth>1</bitWidth>
          </field>
          <field>
            <name>OD15</name>
            <bitOffset>15</bitOffset>
            <bitWidth>1</bitWidth>
          </field>
        </fields>
      </register>
      <register>
        <name>BSRR</name>
        <addressOffset>0x18</addressOffset>
        <size>0x20</size>
        <fields>
          <field>
            <name>BS0</name>
            <bitOffset>0</bitOffset>
            <bitWidth>1</bitWidth>
          </field>
          <field>
            <name>BS1</name>
            <bitOffset>1</bitOffset>
            <bitWidth>1</bitWidth>
          </field>
          <field>
            <name>BS2</name>
            <bitOffset>2</bitOffset>
            <bitWidth>1</bitWidth>
          </field>
          <field>
            <name>BS3</name>
            <bitOffset>3</bitOffset>
            <bitWidth>1</bitWidth>
          </field>
          <field>
            <name>BS4</name>
            <bitOffset>4</bitOffset>
            <bitWidth>1</bitWidth>
          </field>
          <field>
            <name>BS5</name>
            <bitOffset>5</bitOffset>
            <bitWidth>1</bitWidth>
          </field>
          <field>
            <name>BS6</name>
            <bitOffset>6</bitOffset>
            <bitWidth>1</bitWidth>
          </field>
          <field>
            <name>BS7</name>
            <bitOffset>7</bitOffset>
            <bitWidth>1</bitWidth>
          </field>
          <field>
            <name>BS8</name>
            <bitOffset>8</bitOffset>
            <bitWidth>1</bitWidth>
          </field>
          <field>
            <name>BS9</name>
            <bitOffset>9</bitOffset>
            <bitWidth>1</bitWidth>
          </field>
          <field>
            <name>BS10</name>
            <bitOffset>10</bitOffset>
            <bitWidth>1</bitWidth>
          </field>
          <field>
            <name>BS11</name>
            <bitOffset>11</bitOffset>
            <bitWidth>1</bitWidth>
          </field>
          <field>
            <name>BS12</name>
            <bitOffset>12</bitOffset>
            <bitWidth>1</bitWidth>
          </field>
          <field>
            <name>BS13</name>
            <bitOffset>13</bitOffset>
            <bitWidth>1</bitWidth>
          </field>
          <field>
            <name>BS14</name>
            <bitOffset>14</bitOffset>
            <bitWidth>1</bitWidth>
          </field>
          <field>
            <name>BS15</name>
            <bitOffset>15</bitOffset>
            <bitWidth>1</bitWidth>
          </field>
          <field>
            <name>BR0</name>
            <bitOffset>16</bitOffset>
            <bitWidth>1</bitWidth>
          </field>
          <field>
            <name>BR1</name>
            <bitOffset>17</bitOffset>
            <bitWidth>1</bitWidth>
          </field>
          <field>
            <name>BR2</name>
            <bitOffset>18</bitOffset>
            <bitWidth>1</bitWidth>
          </field>
          <field>
            <name>BR3</name>
            <bitOffset>19</bitOffset>
            <bitWidth>1</bitWidth>
          </field>
          <field>
            <name>BR4</name>
            <bitOffset>20</bitOffset>
            <bitWidth>1</bitWidth>
          </field>
          <field>
            <name>BR5</name>
            <bitOffset>21</bitOffset>
            <bitWidth>1</bitWidth>
          </field>
          <field>
            <name>BR6</name>
            <bitOffset>22</bitOffset>
            <bitWidth>1</bitWidth>
          </field>
          <field>
            <name>BR7</name>
            <bitOffset>23</bitOffset>
            <bitWidth>1</bitWidth>
          </field>
          <field>
            <name>BR8</name>
            <bitOffset>24</bitOffset>
            <bitWidth>1</bitWidth>
          </field>
          <field>
            <name>BR9</name>
            <bitOffset>25</bitOffset>
            <bitWidth>1</bitWidth>
          </field>
          <field>
            <name>BR10</name>
            <bitOffset>26</bitOffset>
            <bitWidth>1</bitWidth>
          </field>
          <field>
            <name>BR11</name>
            <bitOffset>27</bitOffset>
            <bitWidth>1</bitWidth>
          </field>
          <field>
            <name>BR12</name>
            <bitOffset>28</bitOffset>
            <bitWidth>1</bitWidth>
          </field>
          <field>
            <name>BR13</name>
            <bitOffset>29</bitOffset>
            <bitWidth>1</bitWidth>
          </field>
          <field>
            <name>BR14</name>
            <bitOffset>30</bitOffset>
            <bitWidth>1</bitWidth>
          </field>
          <field>
            <name>BR15</name>
            <bitOffset>31</bitOffset>
            <bitWidth>1</bitWidth>
          </field>
        </fields>
      </register>
      <register>
        <name>LCKR</name>
        <addressOffset>0x1c</addressOffset>
        <size>0x20</size>
        <fields>
          <field>
            <name>LCK0</name>
            <bitOffset>0</bitOffset>
            <bitWidth>1</bitWidth>
          </field>
          <field>
            <name>LCK1</name>
            <bitOffset>1</bitOffset>
            <bitWidth>1</bitWidth>
          </field>
          <field>
            <name>LCK2</name>
            <bitOffset>2</bitOffset>
            <bitWidth>1</bitWidth>
          </field>
          <field>
            <name>LCK3</name>
            <bitOffset>3</bitOffset>
            <bitWidth>1</bitWidth>
          </field>
          <field>
            <name>LCK4</name>
            <bitOffset>4</bitOffset>
            <bitWidth>1</bitWidth>
          </field>
          <field>
            <name>LCK5</name>
            <bitOffset>5</bitOffset>
            <bitWidth>1</bitWidth>
          </field>
          <field>
            <name>LCK6</name>
            <bitOffset>6</bitOffset>
            <bitWidth>1</bitWidth>
          </field>
          <field>
            <name>LCK7</name>
            <bitOffset>7</bitOffset>
            <bitWidth>1</bitWidth>
          </field>
          <field>
            <name>LCK8</name>
            <bitOffset>8</bitOffset>
            <bitWidth>1</bitWidth>
          </field>
          <field>
            <name>LCK9</name>
            <bitOffset>9</bitOffset>
            <bitWidth>1</bitWidth>
          </field>
          <field>
            <name>LCK10</name>
            <bitOffset>10</bitOffset>
            <bitWidth>1</bitWidth>
          </field>
          <field>
            <name>LCK11</name>
            <bitOffset>11</bitOffset>
            <bitWidth>1</bitWidth>
          </field>
          <field>
            <name>LCK12</name>
            <bitOffset>12</bitOffset>
            <bitWidth>1</bitWidth>
          </field>
          <field>
            <name>LCK13</name>
            <bitOffset>13</bitOffset>
            <bitWidth>1</bitWidth>
          </field>
          <field>
            <name>LCK14</name>
            <bitOffset>14</bitOffset>
            <bitWidth>1</bitWidth>
          </field>
          <field>
            <name>LCK15</name>
            <bitOffset>15</bitOffset>
            <bitWidth>1</bitWidth>
          </field>
          <field>
            <name>LCKK</name>
            <bitOffset>16</bitOffset>
            <bitWidth>1</bitWidth>
          </field>
        </fields>
      </register>
      <register>
        <name>AFR.0</name>
        <addressOffset>0x20</addressOffset>
        <size>0x20</size>
        <fields>
          <field>
            <name>AFSEL0</name>
            <bitOffset>0</bitOffset>
            <bitWidth>4</bitWidth>
          </field>
          <field>
            <name>AFSEL1</name>
            <bitOffset>4</bitOffset>
            <bitWidth>4</bitWidth>
          </field>
          <field>
            <name>AFSEL2</name>
            <bitOffset>8</bitOffset>
            <bitWidth>4</bitWidth>
          </field>
          <field>
            <name>AFSEL3</name>
            <bitOffset>12</bitOffset>
            <bitWidth>4</bitWidth>
          </field>
          <field>
            <name>AFSEL4</name>
            <bitOffset>16</bitOffset>
            <bitWidth>4</bitWidth>
          </field>
          <field>
            <name>AFSEL5</name>
            <bitOffset>20</bitOffset>
            <bitWidth>4</bitWidth>
          </field>
          <field>
            <name>AFSEL6</name>
            <bitOffset>24</bitOffset>
            <bitWidth>4</bitWidth>
          </field>
          <field>
            <name>AFSEL7</name>
            <bitOffset>28</bitOffset>
            <bitWidth>4</bitWidth>
          </field>
        </fields>
      </register>
      <register>
        <name>AFR.1</name>
        <addressOffset>0x24</addressOffset>
        <size>0x20</size>
        <fields>
          <field>
            <name>AFSEL8</name>
            <bitOffset>0</bitOffset>
            <bitWidth>4</bitWidth>
          </field>
          <field>
            <name>AFSEL9</name>
            <bitOffset>4</bitOffset>
            <bitWidth>4</bitWidth>
          </field>
          <field>
            <name>AFSEL10</name>
            <bitOffset>8</bitOffset>
            <bitWidth>4</bitWidth>
          </field>
          <field>
            <name>AFSEL11</name>
            <bitOffset>12</bitOffset>
            <bitWidth>4</bitWidth>
          </field>
          <field>
            <name>AFSEL12</name>
            <bitOffset>16</bitOffset>
            <bitWidth>4</bitWidth>
          </field>
          <field>
            <name>AFSEL13</name>
            <bitOffset>20</bitOffset>
            <bitWidth>4</bitWidth>
          </field>
          <field>
            <name>AFSEL14</name>
            <bitOffset>24</bitOffset>
            <bitWidth>4</bitWidth>
          </field>
          <field>
            <name>AFSEL15</name>
            <bitOffset>28</bitOffset>
            <bitWidth>4</bitWidth>
          </field>
        </fields>
      </register>
      <register>
        <name>BRR</name>
        <addressOffset>0x28</addressOffset>
        <size>0x20</size>
        <fields>
          <field>
            <name>BR0</name>
            <bitOffset>0</bitOffset>
            <bitWidth>1</bitWidth>
          </field>
          <field>
            <name>BR1</name>
            <bitOffset>1</bitOffset>
            <bitWidth>1</bitWidth>
          </field>
          <field>
            <name>BR2</name>
            <bitOffset>2</bitOffset>
            <bitWidth>1</bitWidth>
          </field>
          <field>
            <name>BR3</name>
            <bitOffset>3</bitOffset>
            <bitWidth>1</bitWidth>
          </field>
          <field>
            <name>BR4</name>
            <bitOffset>4</bitOffset>
            <bitWidth>1</bitWidth>
          </field>
          <field>
            <name>BR5</name>
            <bitOffset>5</bitOffset>
            <bitWidth>1</bitWidth>
          </field>
          <field>
            <name>BR6</name>
            <bitOffset>6</bitOffset>
            <bitWidth>1</bitWidth>
          </field>
          <field>
            <name>BR7</name>
            <bitOffset>7</bitOffset>
            <bitWidth>1</bitWidth>
          </field>
          <field>
            <name>BR8</name>
            <bitOffset>8</bitOffset>
            <bitWidth>1</bitWidth>
          </field>
          <field>
            <name>BR9</name>
            <bitOffset>9</bitOffset>
            <bitWidth>1</bitWidth>
          </field>
          <field>
            <name>BR10</name>
            <bitOffset>10</bitOffset>
            <bitWidth>1</bitWidth>
          </field>
          <field>
            <name>BR11</name>
            <bitOffset>11</bitOffset>
            <bitWidth>1</bitWidth>
          </field>
          <field>
            <name>BR12</name>
            <bitOffset>12</bitOffset>
            <bitWidth>1</bitWidth>
          </field>
          <field>
            <name>BR13</name>
            <bitOffset>13</bitOffset>
            <bitWidth>1</bitWidth>
          </field>
          <field>
            <name>BR14</name>
            <bitOffset>14</bitOffset>
            <bitWidth>1</bitWidth>
          </field>
          <field>
            <name>BR15</name>
            <bitOffset>15</bitOffset>
            <bitWidth>1</bitWidth>
          </field>
        </fields>
      </register>
    </peripheral>
    <peripheral>
      <name>GPIOD</name>
      <baseAddress>0x48000c00</baseAddress>
      <register>
        <name>MODER</name>
        <addressOffset>0x0</addressOffset>
        <size>0x20</size>
        <fields>
          <field>
            <name>MODE0</name>
            <bitOffset>0</bitOffset>
            <bitWidth>2</bitWidth>
          </field>
          <field>
            <name>MODE1</name>
            <bitOffset>2</bitOffset>
            <bitWidth>2</bitWidth>
          </field>
          <field>
            <name>MODE2</name>
            <bitOffset>4</bitOffset>
            <bitWidth>2</bitWidth>
          </field>
          <field>
            <name>MODE3</name>
            <bitOffset>6</bitOffset>
            <bitWidth>2</bitWidth>
          </field>
          <field>
            <name>MODE4</name>
            <bitOffset>8</bitOffset>
            <bitWidth>2</bitWidth>
          </field>
          <field>
            <name>MODE5</name>
            <bitOffset>10</bitOffset>
            <bitWidth>2</bitWidth>
          </field>
          <field>
            <name>MODE6</name>
            <bitOffset>12</bitOffset>
            <bitWidth>2</bitWidth>
          </field>
          <field>
            <name>MODE7</name>
            <bitOffset>14</bitOffset>
            <bitWidth>2</bitWidth>
          </field>
          <field>
            <name>MODE8</name>
            <bitOffset>16</bitOffset>
            <bitWidth>2</bitWidth>
          </field>
          <field>
            <name>MODE9</name>
            <bitOffset>18</bitOffset>
            <bitWidth>2</bitWidth>
          </field>
          <field>
            <name>MODE10</name>
            <bitOffset>20</bitOffset>
            <bitWidth>2</bitWidth>
          </field>
          <field>
            <name>MODE11</name>
            <bitOffset>22</bitOffset>
            <bitWidth>2</bitWidth>
          </field>
          <field>
            <name>MODE12</name>
            <bitOffset>24</bitOffset>
            <bitWidth>2</bitWidth>
          </field>
          <field>
            <name>MODE13</name>
            <bitOffset>26</bitOffset>
            <bitWidth>2</bitWidth>
          </field>
          <field>
            <name>MODE14</name>
            <bitOffset>28</bitOffset>
            <bitWidth>2</bitWidth>
          </field>
          <field>
            <name>MODE15</name>
            <bitOffset>30</bitOffset>
            <bitWidth>2</bitWidth>
          </field>
        </fields>
      </register>
      <register>
        <name>OTYPER</name>
        <addressOffset>0x4</addressOffset>
        <size>0x20</size>
        <fields>
          <field>
            <name>OT0</name>
            <bitOffset>0</bitOffset>
            <bitWidth>1</bitWidth>
          </field>
          <field>
            <name>OT1</name>
            <bitOffset>1</bitOffset>
            <bitWidth>1</bitWidth>
          </field>
          <field>
            <name>OT2</name>
            <bitOffset>2</bitOffset>
            <bitWidth>1</bitWidth>
          </field>
          <field>
            <name>OT3</name>
            <bitOffset>3</bitOffset>
            <bitWidth>1</bitWidth>
          </field>
          <field>
            <name>OT4</name>
            <bitOffset>4</bitOffset>
            <bitWidth>1</bitWidth>
          </field>
          <field>
            <name>OT5</name>
            <bitOffset>5</bitOffset>
            <bitWidth>1</bitWidth>
          </field>
          <field>
            <name>OT6</name>
            <bitOffset>6</bitOffset>
            <bitWidth>1</bitWidth>
          </field>
          <field>
            <name>OT7</name>
            <bitOffset>7</bitOffset>
            <bitWidth>1</bitWidth>
          </field>
          <field>
            <name>OT8</name>
            <bitOffset>8</bitOffset>
            <bitWidth>1</bitWidth>
          </field>
          <field>
            <name>OT9</name>
            <bitOffset>9</bitOffset>
            <bitWidth>1</bitWidth>
          </field>
          <field>
            <name>OT10</name>
            <bitOffset>10</bitOffset>
            <bitWidth>1</bitWidth>
          </field>
          <field>
            <name>OT11</name>
            <bitOffset>11</bitOffset>
            <bitWidth>1</bitWidth>
          </field>
          <field>
            <name>OT12</name>
            <bitOffset>12</bitOffset>
            <bitWidth>1</bitWidth>
          </field>
          <field>
            <name>OT13</name>
            <bitOffset>13</bitOffset>
            <bitWidth>1</bitWidth>
          </field>
          <field>
            <name>OT14</name>
            <bitOffset>14</bitOffset>
            <bitWidth>1</bitWidth>
          </field>
          <field>
            <name>OT15</name>
            <bitOffset>15</bitOffset>
            <bitWidth>1</bitWidth>
          </field>
        </fields>
      </register>
      <register>
        <name>OSPEEDR</name>
        <addressOffset>0x8</addressOffset>
        <size>0x20</size>
        <fields>
          <field>
            <name>OSPEED0</name>
            <bitOffset>0</bitOffset>
            <bitWidth>2</bitWidth>
          </field>
          <field>
            <name>OSPEED1</name>
            <bitOffset>2</bitOffset>
            <bitWidth>2</bitWidth>
          </field>
          <field>
            <name>OSPEED2</name>
            <bitOffset>4</bitOffset>
            <bitWidth>2</bitWidth>
          </field>
          <field>
            <name>OSPEED3</name>
            <bitOffset>6</bitOffset>
            <bitWidth>2</bitWidth>
          </field>
          <field>
            <name>OSPEED4</name>
            <bitOffset>8</bitOffset>
            <bitWidth>2</bitWidth>
          </field>
          <field>
            <name>OSPEED5</name>
            <bitOffset>10</bitOffset>
            <bitWidth>2</bitWidth>
          </field>
          <field>
            <name>OSPEED6</name>
            <bitOffset>12</bitOffset>
            <bitWidth>2</bitWidth>
          </field>
          <field>
            <name>OSPEED7</name>
            <bitOffset>14</bitOffset>
            <bitWidth>2</bitWidth>
          </field>
          <field>
            <name>OSPEED8</name>
            <bitOffset>16</bitOffset>
            <bitWidth>2</bitWidth>
          </field>
          <field>
            <name>OSPEED9</name>
            <bitOffset>18</bitOffset>
            <bitWidth>2</bitWidth>
          </field>
          <field>
            <name>OSPEED10</name>
            <bitOffset>20</bitOffset>
            <bitWidth>2</bitWidth>
          </field>
          <field>
            <name>OSPEED11</name>
            <bitOffset>22</bitOffset>
            <bitWidth>2</bitWidth>
          </field>
          <field>
            <name>OSPEED12</name>
            <bitOffset>24</bitOffset>
            <bitWidth>2</bitWidth>
          </field>
          <field>
            <name>OSPEED13</name>
            <bitOffset>26</bitOffset>
            <bitWidth>2</bitWidth>
          </field>
          <field>
            <name>OSPEED14</name>
            <bitOffset>28</bitOffset>
            <bitWidth>2</bitWidth>
          </field>
          <field>
            <name>OSPEED15</name>
            <bitOffset>30</bitOffset>
            <bitWidth>2</bitWidth>
          </field>
        </fields>
      </register>
      <register>
        <name>PUPDR</name>
        <addressOffset>0xc</addressOffset>
        <size>0x20</size>
        <fields>
          <field>
            <name>PUPD0</name>
            <bitOffset>0</bitOffset>
            <bitWidth>2</bitWidth>
          </field>
          <field>
            <name>PUPD1</name>
            <bitOffset>2</bitOffset>
            <bitWidth>2</bitWidth>
          </field>
          <field>
            <name>PUPD2</name>
            <bitOffset>4</bitOffset>
            <bitWidth>2</bitWidth>
          </field>
          <field>
            <name>PUPD3</name>
            <bitOffset>6</bitOffset>
            <bitWidth>2</bitWidth>
          </field>
          <field>
            <name>PUPD4</name>
            <bitOffset>8</bitOffset>
            <bitWidth>2</bitWidth>
          </field>
          <field>
            <name>PUPD5</name>
            <bitOffset>10</bitOffset>
            <bitWidth>2</bitWidth>
          </field>
          <field>
            <name>PUPD6</name>
            <bitOffset>12</bitOffset>
            <bitWidth>2</bitWidth>
          </field>
          <field>
            <name>PUPD7</name>
            <bitOffset>14</bitOffset>
            <bitWidth>2</bitWidth>
          </field>
          <field>
            <name>PUPD8</name>
            <bitOffset>16</bitOffset>
            <bitWidth>2</bitWidth>
          </field>
          <field>
            <name>PUPD9</name>
            <bitOffset>18</bitOffset>
            <bitWidth>2</bitWidth>
          </field>
          <field>
            <name>PUPD10</name>
            <bitOffset>20</bitOffset>
            <bitWidth>2</bitWidth>
          </field>
          <field>
            <name>PUPD11</name>
            <bitOffset>22</bitOffset>
            <bitWidth>2</bitWidth>
          </field>
          <field>
            <name>PUPD12</name>
            <bitOffset>24</bitOffset>
            <bitWidth>2</bitWidth>
          </field>
          <field>
            <name>PUPD13</name>
            <bitOffset>26</bitOffset>
            <bitWidth>2</bitWidth>
          </field>
          <field>
            <name>PUPD14</name>
            <bitOffset>28</bitOffset>
            <bitWidth>2</bitWidth>
          </field>
          <field>
            <name>PUPD15</name>
            <bitOffset>30</bitOffset>
            <bitWidth>2</bitWidth>
          </field>
        </fields>
      </register>
      <register>
        <name>IDR</name>
        <addressOffset>0x10</addressOffset>
        <size>0x20</size>
        <fields>
          <field>
            <name>ID0</name>
            <bitOffset>0</bitOffset>
            <bitWidth>1</bitWidth>
          </field>
          <field>
            <name>ID1</name>
            <bitOffset>1</bitOffset>
            <bitWidth>1</bitWidth>
          </field>
          <field>
            <name>ID2</name>
            <bitOffset>2</bitOffset>
            <bitWidth>1</bitWidth>
          </field>
          <field>
            <name>ID3</name>
            <bitOffset>3</bitOffset>
            <bitWidth>1</bitWidth>
          </field>
          <field>
            <name>ID4</name>
            <bitOffset>4</bitOffset>
            <bitWidth>1</bitWidth>
          </field>
          <field>
            <name>ID5</name>
            <bitOffset>5</bitOffset>
            <bitWidth>1</bitWidth>
          </field>
          <field>
            <name>ID6</name>
            <bitOffset>6</bitOffset>
            <bitWidth>1</bitWidth>
          </field>
          <field>
            <name>ID7</name>
            <bitOffset>7</bitOffset>
            <bitWidth>1</bitWidth>
          </field>
          <field>
            <name>ID8</name>
            <bitOffset>8</bitOffset>
            <bitWidth>1</bitWidth>
          </field>
          <field>
            <name>ID9</name>
            <bitOffset>9</bitOffset>
            <bitWidth>1</bitWidth>
          </field>
          <field>
            <name>ID10</name>
            <bitOffset>10</bitOffset>
            <bitWidth>1</bitWidth>
          </field>
          <field>
            <name>ID11</name>
            <bitOffset>11</bitOffset>
            <bitWidth>1</bitWidth>
          </field>
          <field>
            <name>ID12</name>
            <bitOffset>12</bitOffset>
            <bitWidth>1</bitWidth>
          </field>
          <field>
            <name>ID13</name>
            <bitOffset>13</bitOffset>
            <bitWidth>1</bitWidth>
          </field>
          <field>
            <name>ID14</name>
            <bitOffset>14</bitOffset>
            <bitWidth>1</bitWidth>
          </field>
          <field>
            <name>ID15</name>
            <bitOffset>15</bitOffset>
            <bitWidth>1</bitWidth>
          </field>
        </fields>
      </register>
      <register>
        <name>ODR</name>
        <addressOffset>0x14</addressOffset>
        <size>0x20</size>
        <fields>
          <field>
            <name>OD0</name>
            <bitOffset>0</bitOffset>
            <bitWidth>1</bitWidth>
          </field>
          <field>
            <name>OD1</name>
            <bitOffset>1</bitOffset>
            <bitWidth>1</bitWidth>
          </field>
          <field>
            <name>OD2</name>
            <bitOffset>2</bitOffset>
            <bitWidth>1</bitWidth>
          </field>
          <field>
            <name>OD3</name>
            <bitOffset>3</bitOffset>
            <bitWidth>1</bitWidth>
          </field>
          <field>
            <name>OD4</name>
            <bitOffset>4</bitOffset>
            <bitWidth>1</bitWidth>
          </field>
          <field>
            <name>OD5</name>
            <bitOffset>5</bitOffset>
            <bitWidth>1</bitWidth>
          </field>
          <field>
            <name>OD6</name>
            <bitOffset>6</bitOffset>
            <bitWidth>1</bitWidth>
          </field>
          <field>
            <name>OD7</name>
            <bitOffset>7</bitOffset>
            <bitWidth>1</bitWidth>
          </field>
          <field>
            <name>OD8</name>
            <bitOffset>8</bitOffset>
            <bitWidth>1</bitWidth>
          </field>
          <field>
            <name>OD9</name>
            <bitOffset>9</bitOffset>
            <bitWidth>1</bitWidth>
          </field>
          <field>
            <name>OD10</name>
            <bitOffset>10</bitOffset>
            <bitWidth>1</bitWidth>
          </field>
          <field>
            <name>OD11</name>
            <bitOffset>11</bitOffset>
            <bitWidth>1</bitWidth>
          </field>
          <field>
            <name>OD12</name>
            <bitOffset>12</bitOffset>
            <bitWidth>1</bitWidth>
          </field>
          <field>
            <name>OD13</name>
            <bitOffset>13</bitOffset>
            <bitWidth>1</bitWidth>
          </field>
          <field>
            <name>OD14</name>
            <bitOffset>14</bitOffset>
            <bitWidth>1</bitWidth>
          </field>
          <field>
            <name>OD15</name>
            <bitOffset>15</bitOffset>
            <bitWidth>1</bitWidth>
          </field>
        </fields>
      </register>
      <register>
        <name>BSRR</name>
        <addressOffset>0x18</addressOffset>
        <size>0x20</size>
        <fields>
          <field>
            <name>BS0</name>
            <bitOffset>0</bitOffset>
            <bitWidth>1</bitWidth>
          </field>
          <field>
            <name>BS1</name>
            <bitOffset>1</bitOffset>
            <bitWidth>1</bitWidth>
          </field>
          <field>
            <name>BS2</name>
            <bitOffset>2</bitOffset>
            <bitWidth>1</bitWidth>
          </field>
          <field>
            <name>BS3</name>
            <bitOffset>3</bitOffset>
            <bitWidth>1</bitWidth>
          </field>
          <field>
            <name>BS4</name>
            <bitOffset>4</bitOffset>
            <bitWidth>1</bitWidth>
          </field>
          <field>
            <name>BS5</name>
            <bitOffset>5</bitOffset>
            <bitWidth>1</bitWidth>
          </field>
          <field>
            <name>BS6</name>
            <bitOffset>6</bitOffset>
            <bitWidth>1</bitWidth>
          </field>
          <field>
            <name>BS7</name>
            <bitOffset>7</bitOffset>
            <bitWidth>1</bitWidth>
          </field>
          <field>
            <name>BS8</name>
            <bitOffset>8</bitOffset>
            <bitWidth>1</bitWidth>
          </field>
          <field>
            <name>BS9</name>
            <bitOffset>9</bitOffset>
            <bitWidth>1</bitWidth>
          </field>
          <field>
            <name>BS10</name>
            <bitOffset>10</bitOffset>
            <bitWidth>1</bitWidth>
          </field>
          <field>
            <name>BS11</name>
            <bitOffset>11</bitOffset>
            <bitWidth>1</bitWidth>
          </field>
          <field>
            <name>BS12</name>
            <bitOffset>12</bitOffset>
            <bitWidth>1</bitWidth>
          </field>
          <field>
            <name>BS13</name>
            <bitOffset>13</bitOffset>
            <bitWidth>1</bitWidth>
          </field>
          <field>
            <name>BS14</name>
            <bitOffset>14</bitOffset>
            <bitWidth>1</bitWidth>
          </field>
          <field>
            <name>BS15</name>
            <bitOffset>15</bitOffset>
            <bitWidth>1</bitWidth>
          </field>
          <field>
            <name>BR0</name>
            <bitOffset>16</bitOffset>
            <bitWidth>1</bitWidth>
          </field>
          <field>
            <name>BR1</name>
            <bitOffset>17</bitOffset>
            <bitWidth>1</bitWidth>
          </field>
          <field>
            <name>BR2</name>
            <bitOffset>18</bitOffset>
            <bitWidth>1</bitWidth>
          </field>
          <field>
            <name>BR3</name>
            <bitOffset>19</bitOffset>
            <bitWidth>1</bitWidth>
          </field>
          <field>
            <name>BR4</name>
            <bitOffset>20</bitOffset>
            <bitWidth>1</bitWidth>
          </field>
          <field>
            <name>BR5</name>
            <bitOffset>21</bitOffset>
            <bitWidth>1</bitWidth>
          </field>
          <field>
            <name>BR6</name>
            <bitOffset>22</bitOffset>
            <bitWidth>1</bitWidth>
          </field>
          <field>
            <name>BR7</name>
            <bitOffset>23</bitOffset>
            <bitWidth>1</bitWidth>
          </field>
          <field>
            <name>BR8</name>
            <bitOffset>24</bitOffset>
            <bitWidth>1</bitWidth>
          </field>
          <field>
            <name>BR9</name>
            <bitOffset>25</bitOffset>
            <bitWidth>1</bitWidth>
          </field>
          <field>
            <name>BR10</name>
            <bitOffset>26</bitOffset>
            <bitWidth>1</bitWidth>
          </field>
          <field>
            <name>BR11</name>
            <bitOffset>27</bitOffset>
            <bitWidth>1</bitWidth>
          </field>
          <field>
            <name>BR12</name>
            <bitOffset>28</bitOffset>
            <bitWidth>1</bitWidth>
          </field>
          <field>
            <name>BR13</name>
            <bitOffset>29</bitOffset>
            <bitWidth>1</bitWidth>
          </field>
          <field>
            <name>BR14</name>
            <bitOffset>30</bitOffset>
            <bitWidth>1</bitWidth>
          </field>
          <field>
            <name>BR15</name>
            <bitOffset>31</bitOffset>
            <bitWidth>1</bitWidth>
          </field>
        </fields>
      </register>
      <register>
        <name>LCKR</name>
        <addressOffset>0x1c</addressOffset>
        <size>0x20</size>
        <fields>
          <field>
            <name>LCK0</name>
            <bitOffset>0</bitOffset>
            <bitWidth>1</bitWidth>
          </field>
          <field>
            <name>LCK1</name>
            <bitOffset>1</bitOffset>
            <bitWidth>1</bitWidth>
          </field>
          <field>
            <name>LCK2</name>
            <bitOffset>2</bitOffset>
            <bitWidth>1</bitWidth>
          </field>
          <field>
            <name>LCK3</name>
            <bitOffset>3</bitOffset>
            <bitWidth>1</bitWidth>
          </field>
          <field>
            <name>LCK4</name>
            <bitOffset>4</bitOffset>
            <bitWidth>1</bitWidth>
          </field>
          <field>
            <name>LCK5</name>
            <bitOffset>5</bitOffset>
            <bitWidth>1</bitWidth>
          </field>
          <field>
            <name>LCK6</name>
            <bitOffset>6</bitOffset>
            <bitWidth>1</bitWidth>
          </field>
          <field>
            <name>LCK7</name>
            <bitOffset>7</bitOffset>
            <bitWidth>1</bitWidth>
          </field>
          <field>
            <name>LCK8</name>
            <bitOffset>8</bitOffset>
            <bitWidth>1</bitWidth>
          </field>
          <field>
            <name>LCK9</name>
            <bitOffset>9</bitOffset>
            <bitWidth>1</bitWidth>
          </field>
          <field>
            <name>LCK10</name>
            <bitOffset>10</bitOffset>
            <bitWidth>1</bitWidth>
          </field>
          <field>
            <name>LCK11</name>
            <bitOffset>11</bitOffset>
            <bitWidth>1</bitWidth>
          </field>
          <field>
            <name>LCK12</name>
            <bitOffset>12</bitOffset>
            <bitWidth>1</bitWidth>
          </field>
          <field>
            <name>LCK13</name>
            <bitOffset>13</bitOffset>
            <bitWidth>1</bitWidth>
          </field>
          <field>
            <name>LCK14</name>
            <bitOffset>14</bitOffset>
            <bitWidth>1</bitWidth>
          </field>
          <field>
            <name>LCK15</name>
            <bitOffset>15</bitOffset>
            <bitWidth>1</bitWidth>
          </field>
          <field>
            <name>LCKK</name>
            <bitOffset>16</bitOffset>
            <bitWidth>1</bitWidth>
          </field>
        </fields>
      </register>
      <register>
        <name>AFR.0</name>
        <addressOffset>0x20</addressOffset>
        <size>0x20</size>
        <fields>
          <field>
            <name>AFSEL0</name>
            <bitOffset>0</bitOffset>
            <bitWidth>4</bitWidth>
          </field>
          <field>
            <name>AFSEL1</name>
            <bitOffset>4</bitOffset>
            <bitWidth>4</bitWidth>
          </field>
          <field>
            <name>AFSEL2</name>
            <bitOffset>8</bitOffset>
            <bitWidth>4</bitWidth>
          </field>
          <field>
            <name>AFSEL3</name>
            <bitOffset>12</bitOffset>
            <bitWidth>4</bitWidth>
          </field>
          <field>
            <name>AFSEL4</name>
            <bitOffset>16</bitOffset>
            <bitWidth>4</bitWidth>
          </field>
          <field>
            <name>AFSEL5</name>
            <bitOffset>20</bitOffset>
            <bitWidth>4</bitWidth>
          </field>
          <field>
            <name>AFSEL6</name>
            <bitOffset>24</bitOffset>
            <bitWidth>4</bitWidth>
          </field>
          <field>
            <name>AFSEL7</name>
            <bitOffset>28</bitOffset>
            <bitWidth>4</bitWidth>
          </field>
        </fields>
      </register>
      <register>
        <name>AFR.1</name>
        <addressOffset>0x24</addressOffset>
        <size>0x20</size>
        <fields>
          <field>
            <name>AFSEL8</name>
            <bitOffset>0</bitOffset>
            <bitWidth>4</bitWidth>
          </field>
          <field>
            <name>AFSEL9</name>
            <bitOffset>4</bitOffset>
            <bitWidth>4</bitWidth>
          </field>
          <field>
            <name>AFSEL10</name>
            <bitOffset>8</bitOffset>
            <bitWidth>4</bitWidth>
          </field>
          <field>
            <name>AFSEL11</name>
            <bitOffset>12</bitOffset>
            <bitWidth>4</bitWidth>
          </field>
          <field>
            <name>AFSEL12</name>
            <bitOffset>16</bitOffset>
            <bitWidth>4</bitWidth>
          </field>
          <field>
            <name>AFSEL13</name>
            <bitOffset>20</bitOffset>
            <bitWidth>4</bitWidth>
          </field>
          <field>
            <name>AFSEL14</name>
            <bitOffset>24</bitOffset>
            <bitWidth>4</bitWidth>
          </field>
          <field>
            <name>AFSEL15</name>
            <bitOffset>28</bitOffset>
            <bitWidth>4</bitWidth>
          </field>
        </fields>
      </register>
      <register>
        <name>BRR</name>
        <addressOffset>0x28</addressOffset>
        <size>0x20</size>
        <fields>
          <field>
            <name>BR0</name>
            <bitOffset>0</bitOffset>
            <bitWidth>1</bitWidth>
          </field>
          <field>
            <name>BR1</name>
            <bitOffset>1</bitOffset>
            <bitWidth>1</bitWidth>
          </field>
          <field>
            <name>BR2</name>
            <bitOffset>2</bitOffset>
            <bitWidth>1</bitWidth>
          </field>
          <field>
            <name>BR3</name>
            <bitOffset>3</bitOffset>
            <bitWidth>1</bitWidth>
          </field>
          <field>
            <name>BR4</name>
            <bitOffset>4</bitOffset>
            <bitWidth>1</bitWidth>
          </field>
          <field>
            <name>BR5</name>
            <bitOffset>5</bitOffset>
            <bitWidth>1</bitWidth>
          </field>
          <field>
            <name>BR6</name>
            <bitOffset>6</bitOffset>
            <bitWidth>1</bitWidth>
          </field>
          <field>
            <name>BR7</name>
            <bitOffset>7</bitOffset>
            <bitWidth>1</bitWidth>
          </field>
          <field>
            <name>BR8</name>
            <bitOffset>8</bitOffset>
            <bitWidth>1</bitWidth>
          </field>
          <field>
            <name>BR9</name>
            <bitOffset>9</bitOffset>
            <bitWidth>1</bitWidth>
          </field>
          <field>
            <name>BR10</name>
            <bitOffset>10</bitOffset>
            <bitWidth>1</bitWidth>
          </field>
          <field>
            <name>BR11</name>
            <bitOffset>11</bitOffset>
            <bitWidth>1</bitWidth>
          </field>
          <field>
            <name>BR12</name>
            <bitOffset>12</bitOffset>
            <bitWidth>1</bitWidth>
          </field>
          <field>
            <name>BR13</name>
            <bitOffset>13</bitOffset>
            <bitWidth>1</bitWidth>
          </field>
          <field>
            <name>BR14</name>
            <bitOffset>14</bitOffset>
            <bitWidth>1</bitWidth>
          </field>
          <field>
            <name>BR15</name>
            <bitOffset>15</bitOffset>
            <bitWidth>1</bitWidth>
          </field>
        </fields>
      </register>
    </peripheral>
    <peripheral>
      <name>GPIOE</name>
      <baseAddress>0x48001000</baseAddress>
      <register>
        <name>MODER</name>
        <addressOffset>0x0</addressOffset>
        <size>0x20</size>
        <fields>
          <field>
            <name>MODE0</name>
            <bitOffset>0</bitOffset>
            <bitWidth>2</bitWidth>
          </field>
          <field>
            <name>MODE1</name>
            <bitOffset>2</bitOffset>
            <bitWidth>2</bitWidth>
          </field>
          <field>
            <name>MODE2</name>
            <bitOffset>4</bitOffset>
            <bitWidth>2</bitWidth>
          </field>
          <field>
            <name>MODE3</name>
            <bitOffset>6</bitOffset>
            <bitWidth>2</bitWidth>
          </field>
          <field>
            <name>MODE4</name>
            <bitOffset>8</bitOffset>
            <bitWidth>2</bitWidth>
          </field>
          <field>
            <name>MODE5</name>
            <bitOffset>10</bitOffset>
            <bitWidth>2</bitWidth>
          </field>
          <field>
            <name>MODE6</name>
            <bitOffset>12</bitOffset>
            <bitWidth>2</bitWidth>
          </field>
          <field>
            <name>MODE7</name>
            <bitOffset>14</bitOffset>
            <bitWidth>2</bitWidth>
          </field>
          <field>
            <name>MODE8</name>
            <bitOffset>16</bitOffset>
            <bitWidth>2</bitWidth>
          </field>
          <field>
            <name>MODE9</name>
            <bitOffset>18</bitOffset>
            <bitWidth>2</bitWidth>
          </field>
          <field>
            <name>MODE10</name>
            <bitOffset>20</bitOffset>
            <bitWidth>2</bitWidth>
          </field>
          <field>
            <name>MODE11</name>
            <bitOffset>22</bitOffset>
            <bitWidth>2</bitWidth>
          </field>
          <field>
            <name>MODE12</name>
            <bitOffset>24</bitOffset>
            <bitWidth>2</bitWidth>
          </field>
          <field>
            <name>MODE13</name>
            <bitOffset>26</bitOffset>
            <bitWidth>2</bitWidth>
          </field>
          <field>
            <name>MODE14</name>
            <bitOffset>28</bitOffset>
            <bitWidth>2</bitWidth>
          </field>
          <field>
            <name>MODE15</name>
            <bitOffset>30</bitOffset>
            <bitWidth>2</bitWidth>
          </field>
        </fields>
      </register>
      <register>
        <name>OTYPER</name>
        <addressOffset>0x4</addressOffset>
        <size>0x20</size>
        <fields>
          <field>
            <name>OT0</name>
            <bitOffset>0</bitOffset>
            <bitWidth>1</bitWidth>
          </field>
          <field>
            <name>OT1</name>
            <bitOffset>1</bitOffset>
            <bitWidth>1</bitWidth>
          </field>
          <field>
            <name>OT2</name>
            <bitOffset>2</bitOffset>
            <bitWidth>1</bitWidth>
          </field>
          <field>
            <name>OT3</name>
            <bitOffset>3</bitOffset>
            <bitWidth>1</bitWidth>
          </field>
          <field>
            <name>OT4</name>
            <bitOffset>4</bitOffset>
            <bitWidth>1</bitWidth>
          </field>
          <field>
            <name>OT5</name>
            <bitOffset>5</bitOffset>
            <bitWidth>1</bitWidth>
          </field>
          <field>
            <name>OT6</name>
            <bitOffset>6</bitOffset>
            <bitWidth>1</bitWidth>
          </field>
          <field>
            <name>OT7</name>
            <bitOffset>7</bitOffset>
            <bitWidth>1</bitWidth>
          </field>
          <field>
            <name>OT8</name>
            <bitOffset>8</bitOffset>
            <bitWidth>1</bitWidth>
          </field>
          <field>
            <name>OT9</name>
            <bitOffset>9</bitOffset>
            <bitWidth>1</bitWidth>
          </field>
          <field>
            <name>OT10</name>
            <bitOffset>10</bitOffset>
            <bitWidth>1</bitWidth>
          </field>
          <field>
            <name>OT11</name>
            <bitOffset>11</bitOffset>
            <bitWidth>1</bitWidth>
          </field>
          <field>
            <name>OT12</name>
            <bitOffset>12</bitOffset>
            <bitWidth>1</bitWidth>
          </field>
          <field>
            <name>OT13</name>
            <bitOffset>13</bitOffset>
            <bitWidth>1</bitWidth>
          </field>
          <field>
            <name>OT14</name>
            <bitOffset>14</bitOffset>
            <bitWidth>1</bitWidth>
          </field>
          <field>
            <name>OT15</name>
            <bitOffset>15</bitOffset>
            <bitWidth>1</bitWidth>
          </field>
        </fields>
      </register>
      <register>
        <name>OSPEEDR</name>
        <addressOffset>0x8</addressOffset>
        <size>0x20</size>
        <fields>
          <field>
            <name>OSPEED0</name>
            <bitOffset>0</bitOffset>
            <bitWidth>2</bitWidth>
          </field>
          <field>
            <name>OSPEED1</name>
            <bitOffset>2</bitOffset>
            <bitWidth>2</bitWidth>
          </field>
          <field>
            <name>OSPEED2</name>
            <bitOffset>4</bitOffset>
            <bitWidth>2</bitWidth>
          </field>
          <field>
            <name>OSPEED3</name>
            <bitOffset>6</bitOffset>
            <bitWidth>2</bitWidth>
          </field>
          <field>
            <name>OSPEED4</name>
            <bitOffset>8</bitOffset>
            <bitWidth>2</bitWidth>
          </field>
          <field>
            <name>OSPEED5</name>
            <bitOffset>10</bitOffset>
            <bitWidth>2</bitWidth>
          </field>
          <field>
            <name>OSPEED6</name>
            <bitOffset>12</bitOffset>
            <bitWidth>2</bitWidth>
          </field>
          <field>
            <name>OSPEED7</name>
            <bitOffset>14</bitOffset>
            <bitWidth>2</bitWidth>
          </field>
          <field>
            <name>OSPEED8</name>
            <bitOffset>16</bitOffset>
            <bitWidth>2</bitWidth>
          </field>
          <field>
            <name>OSPEED9</name>
            <bitOffset>18</bitOffset>
            <bitWidth>2</bitWidth>
          </field>
          <field>
            <name>OSPEED10</name>
            <bitOffset>20</bitOffset>
            <bitWidth>2</bitWidth>
          </field>
          <field>
            <name>OSPEED11</name>
            <bitOffset>22</bitOffset>
            <bitWidth>2</bitWidth>
          </field>
          <field>
            <name>OSPEED12</name>
            <bitOffset>24</bitOffset>
            <bitWidth>2</bitWidth>
          </field>
          <field>
            <name>OSPEED13</name>
            <bitOffset>26</bitOffset>
            <bitWidth>2</bitWidth>
          </field>
          <field>
            <name>OSPEED14</name>
            <bitOffset>28</bitOffset>
            <bitWidth>2</bitWidth>
          </field>
          <field>
            <name>OSPEED15</name>
            <bitOffset>30</bitOffset>
            <bitWidth>2</bitWidth>
          </field>
        </fields>
      </register>
      <register>
        <name>PUPDR</name>
        <addressOffset>0xc</addressOffset>
        <size>0x20</size>
        <fields>
          <field>
            <name>PUPD0</name>
            <bitOffset>0</bitOffset>
            <bitWidth>2</bitWidth>
          </field>
          <field>
            <name>PUPD1</name>
            <bitOffset>2</bitOffset>
            <bitWidth>2</bitWidth>
          </field>
          <field>
            <name>PUPD2</name>
            <bitOffset>4</bitOffset>
            <bitWidth>2</bitWidth>
          </field>
          <field>
            <name>PUPD3</name>
            <bitOffset>6</bitOffset>
            <bitWidth>2</bitWidth>
          </field>
          <field>
            <name>PUPD4</name>
            <bitOffset>8</bitOffset>
            <bitWidth>2</bitWidth>
          </field>
          <field>
            <name>PUPD5</name>
            <bitOffset>10</bitOffset>
            <bitWidth>2</bitWidth>
          </field>
          <field>
            <name>PUPD6</name>
            <bitOffset>12</bitOffset>
            <bitWidth>2</bitWidth>
          </field>
          <field>
            <name>PUPD7</name>
            <bitOffset>14</bitOffset>
            <bitWidth>2</bitWidth>
          </field>
          <field>
            <name>PUPD8</name>
            <bitOffset>16</bitOffset>
            <bitWidth>2</bitWidth>
          </field>
          <field>
            <name>PUPD9</name>
            <bitOffset>18</bitOffset>
            <bitWidth>2</bitWidth>
          </field>
          <field>
            <name>PUPD10</name>
            <bitOffset>20</bitOffset>
            <bitWidth>2</bitWidth>
          </field>
          <field>
            <name>PUPD11</name>
            <bitOffset>22</bitOffset>
            <bitWidth>2</bitWidth>
          </field>
          <field>
            <name>PUPD12</name>
            <bitOffset>24</bitOffset>
            <bitWidth>2</bitWidth>
          </field>
          <field>
            <name>PUPD13</name>
            <bitOffset>26</bitOffset>
            <bitWidth>2</bitWidth>
          </field>
          <field>
            <name>PUPD14</name>
            <bitOffset>28</bitOffset>
            <bitWidth>2</bitWidth>
          </field>
          <field>
            <name>PUPD15</name>
            <bitOffset>30</bitOffset>
            <bitWidth>2</bitWidth>
          </field>
        </fields>
      </register>
      <register>
        <name>IDR</name>
        <addressOffset>0x10</addressOffset>
        <size>0x20</size>
        <fields>
          <field>
            <name>ID0</name>
            <bitOffset>0</bitOffset>
            <bitWidth>1</bitWidth>
          </field>
          <field>
            <name>ID1</name>
            <bitOffset>1</bitOffset>
            <bitWidth>1</bitWidth>
          </field>
          <field>
            <name>ID2</name>
            <bitOffset>2</bitOffset>
            <bitWidth>1</bitWidth>
          </field>
          <field>
            <name>ID3</name>
            <bitOffset>3</bitOffset>
            <bitWidth>1</bitWidth>
          </field>
          <field>
            <name>ID4</name>
            <bitOffset>4</bitOffset>
            <bitWidth>1</bitWidth>
          </field>
          <field>
            <name>ID5</name>
            <bitOffset>5</bitOffset>
            <bitWidth>1</bitWidth>
          </field>
          <field>
            <name>ID6</name>
            <bitOffset>6</bitOffset>
            <bitWidth>1</bitWidth>
          </field>
          <field>
            <name>ID7</name>
            <bitOffset>7</bitOffset>
            <bitWidth>1</bitWidth>
          </field>
          <field>
            <name>ID8</name>
            <bitOffset>8</bitOffset>
            <bitWidth>1</bitWidth>
          </field>
          <field>
            <name>ID9</name>
            <bitOffset>9</bitOffset>
            <bitWidth>1</bitWidth>
          </field>
          <field>
            <name>ID10</name>
            <bitOffset>10</bitOffset>
            <bitWidth>1</bitWidth>
          </field>
          <field>
            <name>ID11</name>
            <bitOffset>11</bitOffset>
            <bitWidth>1</bitWidth>
          </field>
          <field>
            <name>ID12</name>
            <bitOffset>12</bitOffset>
            <bitWidth>1</bitWidth>
          </field>
          <field>
            <name>ID13</name>
            <bitOffset>13</bitOffset>
            <bitWidth>1</bitWidth>
          </field>
          <field>
            <name>ID14</name>
            <bitOffset>14</bitOffset>
            <bitWidth>1</bitWidth>
          </field>
          <field>
            <name>ID15</name>
            <bitOffset>15</bitOffset>
            <bitWidth>1</bitWidth>
          </field>
        </fields>
      </register>
      <register>
        <name>ODR</name>
        <addressOffset>0x14</addressOffset>
        <size>0x20</size>
        <fields>
          <field>
            <name>OD0</name>
            <bitOffset>0</bitOffset>
            <bitWidth>1</bitWidth>
          </field>
          <field>
            <name>OD1</name>
            <bitOffset>1</bitOffset>
            <bitWidth>1</bitWidth>
          </field>
          <field>
            <name>OD2</name>
            <bitOffset>2</bitOffset>
            <bitWidth>1</bitWidth>
          </field>
          <field>
            <name>OD3</name>
            <bitOffset>3</bitOffset>
            <bitWidth>1</bitWidth>
          </field>
          <field>
            <name>OD4</name>
            <bitOffset>4</bitOffset>
            <bitWidth>1</bitWidth>
          </field>
          <field>
            <name>OD5</name>
            <bitOffset>5</bitOffset>
            <bitWidth>1</bitWidth>
          </field>
          <field>
            <name>OD6</name>
            <bitOffset>6</bitOffset>
            <bitWidth>1</bitWidth>
          </field>
          <field>
            <name>OD7</name>
            <bitOffset>7</bitOffset>
            <bitWidth>1</bitWidth>
          </field>
          <field>
            <name>OD8</name>
            <bitOffset>8</bitOffset>
            <bitWidth>1</bitWidth>
          </field>
          <field>
            <name>OD9</name>
            <bitOffset>9</bitOffset>
            <bitWidth>1</bitWidth>
          </field>
          <field>
            <name>OD10</name>
            <bitOffset>10</bitOffset>
            <bitWidth>1</bitWidth>
          </field>
          <field>
            <name>OD11</name>
            <bitOffset>11</bitOffset>
            <bitWidth>1</bitWidth>
          </field>
          <field>
            <name>OD12</name>
            <bitOffset>12</bitOffset>
            <bitWidth>1</bitWidth>
          </field>
          <field>
            <name>OD13</name>
            <bitOffset>13</bitOffset>
            <bitWidth>1</bitWidth>
          </field>
          <field>
            <name>OD14</name>
            <bitOffset>14</bitOffset>
            <bitWidth>1</bitWidth>
          </field>
          <field>
            <name>OD15</name>
            <bitOffset>15</bitOffset>
            <bitWidth>1</bitWidth>
          </field>
        </fields>
      </register>
      <register>
        <name>BSRR</name>
        <addressOffset>0x18</addressOffset>
        <size>0x20</size>
        <fields>
          <field>
            <name>BS0</name>
            <bitOffset>0</bitOffset>
            <bitWidth>1</bitWidth>
          </field>
          <field>
            <name>BS1</name>
            <bitOffset>1</bitOffset>
            <bitWidth>1</bitWidth>
          </field>
          <field>
            <name>BS2</name>
            <bitOffset>2</bitOffset>
            <bitWidth>1</bitWidth>
          </field>
          <field>
            <name>BS3</name>
            <bitOffset>3</bitOffset>
            <bitWidth>1</bitWidth>
          </field>
          <field>
            <name>BS4</name>
            <bitOffset>4</bitOffset>
            <bitWidth>1</bitWidth>
          </field>
          <field>
            <name>BS5</name>
            <bitOffset>5</bitOffset>
            <bitWidth>1</bitWidth>
          </field>
          <field>
            <name>BS6</name>
            <bitOffset>6</bitOffset>
            <bitWidth>1</bitWidth>
          </field>
          <field>
            <name>BS7</name>
            <bitOffset>7</bitOffset>
            <bitWidth>1</bitWidth>
          </field>
          <field>
            <name>BS8</name>
            <bitOffset>8</bitOffset>
            <bitWidth>1</bitWidth>
          </field>
          <field>
            <name>BS9</name>
            <bitOffset>9</bitOffset>
            <bitWidth>1</bitWidth>
          </field>
          <field>
            <name>BS10</name>
            <bitOffset>10</bitOffset>
            <bitWidth>1</bitWidth>
          </field>
          <field>
            <name>BS11</name>
            <bitOffset>11</bitOffset>
            <bitWidth>1</bitWidth>
          </field>
          <field>
            <name>BS12</name>
            <bitOffset>12</bitOffset>
            <bitWidth>1</bitWidth>
          </field>
          <field>
            <name>BS13</name>
            <bitOffset>13</bitOffset>
            <bitWidth>1</bitWidth>
          </field>
          <field>
            <name>BS14</name>
            <bitOffset>14</bitOffset>
            <bitWidth>1</bitWidth>
          </field>
          <field>
            <name>BS15</name>
            <bitOffset>15</bitOffset>
            <bitWidth>1</bitWidth>
          </field>
          <field>
            <name>BR0</name>
            <bitOffset>16</bitOffset>
            <bitWidth>1</bitWidth>
          </field>
          <field>
            <name>BR1</name>
            <bitOffset>17</bitOffset>
            <bitWidth>1</bitWidth>
          </field>
          <field>
            <name>BR2</name>
            <bitOffset>18</bitOffset>
            <bitWidth>1</bitWidth>
          </field>
          <field>
            <name>BR3</name>
            <bitOffset>19</bitOffset>
            <bitWidth>1</bitWidth>
          </field>
          <field>
            <name>BR4</name>
            <bitOffset>20</bitOffset>
            <bitWidth>1</bitWidth>
          </field>
          <field>
            <name>BR5</name>
            <bitOffset>21</bitOffset>
            <bitWidth>1</bitWidth>
          </field>
          <field>
            <name>BR6</name>
            <bitOffset>22</bitOffset>
            <bitWidth>1</bitWidth>
          </field>
          <field>
            <name>BR7</name>
            <bitOffset>23</bitOffset>
            <bitWidth>1</bitWidth>
          </field>
          <field>
            <name>BR8</name>
            <bitOffset>24</bitOffset>
            <bitWidth>1</bitWidth>
          </field>
          <field>
            <name>BR9</name>
            <bitOffset>25</bitOffset>
            <bitWidth>1</bitWidth>
          </field>
          <field>
            <name>BR10</name>
            <bitOffset>26</bitOffset>
            <bitWidth>1</bitWidth>
          </field>
          <field>
            <name>BR11</name>
            <bitOffset>27</bitOffset>
            <bitWidth>1</bitWidth>
          </field>
          <field>
            <name>BR12</name>
            <bitOffset>28</bitOffset>
            <bitWidth>1</bitWidth>
          </field>
          <field>
            <name>BR13</name>
            <bitOffset>29</bitOffset>
            <bitWidth>1</bitWidth>
          </field>
          <field>
            <name>BR14</name>
            <bitOffset>30</bitOffset>
            <bitWidth>1</bitWidth>
          </field>
          <field>
            <name>BR15</name>
            <bitOffset>31</bitOffset>
            <bitWidth>1</bitWidth>
          </field>
        </fields>
      </register>
      <register>
        <name>LCKR</name>
        <addressOffset>0x1c</addressOffset>
        <size>0x20</size>
        <fields>
          <field>
            <name>LCK0</name>
            <bitOffset>0</bitOffset>
            <bitWidth>1</bitWidth>
          </field>
          <field>
            <name>LCK1</name>
            <bitOffset>1</bitOffset>
            <bitWidth>1</bitWidth>
          </field>
          <field>
            <name>LCK2</name>
            <bitOffset>2</bitOffset>
            <bitWidth>1</bitWidth>
          </field>
          <field>
            <name>LCK3</name>
            <bitOffset>3</bitOffset>
            <bitWidth>1</bitWidth>
          </field>
          <field>
            <name>LCK4</name>
            <bitOffset>4</bitOffset>
            <bitWidth>1</bitWidth>
          </field>
          <field>
            <name>LCK5</name>
            <bitOffset>5</bitOffset>
            <bitWidth>1</bitWidth>
          </field>
          <field>
            <name>LCK6</name>
            <bitOffset>6</bitOffset>
            <bitWidth>1</bitWidth>
          </field>
          <field>
            <name>LCK7</name>
            <bitOffset>7</bitOffset>
            <bitWidth>1</bitWidth>
          </field>
          <field>
            <name>LCK8</name>
            <bitOffset>8</bitOffset>
            <bitWidth>1</bitWidth>
          </field>
          <field>
            <name>LCK9</name>
            <bitOffset>9</bitOffset>
            <bitWidth>1</bitWidth>
          </field>
          <field>
            <name>LCK10</name>
            <bitOffset>10</bitOffset>
            <bitWidth>1</bitWidth>
          </field>
          <field>
            <name>LCK11</name>
            <bitOffset>11</bitOffset>
            <bitWidth>1</bitWidth>
          </field>
          <field>
            <name>LCK12</name>
            <bitOffset>12</bitOffset>
            <bitWidth>1</bitWidth>
          </field>
          <field>
            <name>LCK13</name>
            <bitOffset>13</bitOffset>
            <bitWidth>1</bitWidth>
          </field>
          <field>
            <name>LCK14</name>
            <bitOffset>14</bitOffset>
            <bitWidth>1</bitWidth>
          </field>
          <field>
            <name>LCK15</name>
            <bitOffset>15</bitOffset>
            <bitWidth>1</bitWidth>
          </field>
          <field>
            <name>LCKK</name>
            <bitOffset>16</bitOffset>
            <bitWidth>1</bitWidth>
          </field>
        </fields>
      </register>
      <register>
        <name>AFR.0</name>
        <addressOffset>0x20</addressOffset>
        <size>0x20</size>
        <fields>
          <field>
            <name>AFSEL0</name>
            <bitOffset>0</bitOffset>
            <bitWidth>4</bitWidth>
          </field>
          <field>
            <name>AFSEL1</name>
            <bitOffset>4</bitOffset>
            <bitWidth>4</bitWidth>
          </field>
          <field>
            <name>AFSEL2</name>
            <bitOffset>8</bitOffset>
            <bitWidth>4</bitWidth>
          </field>
          <field>
            <name>AFSEL3</name>
            <bitOffset>12</bitOffset>
            <bitWidth>4</bitWidth>
          </field>
          <field>
            <name>AFSEL4</name>
            <bitOffset>16</bitOffset>
            <bitWidth>4</bitWidth>
          </field>
          <field>
            <name>AFSEL5</name>
            <bitOffset>20</bitOffset>
            <bitWidth>4</bitWidth>
          </field>
          <field>
            <name>AFSEL6</name>
            <bitOffset>24</bitOffset>
            <bitWidth>4</bitWidth>
          </field>
          <field>
            <name>AFSEL7</name>
            <bitOffset>28</bitOffset>
            <bitWidth>4</bitWidth>
          </field>
        </fields>
      </register>
      <register>
        <name>AFR.1</name>
        <addressOffset>0x24</addressOffset>
        <size>0x20</size>
        <fields>
          <field>
            <name>AFSEL8</name>
            <bitOffset>0</bitOffset>
            <bitWidth>4</bitWidth>
          </field>
          <field>
            <name>AFSEL9</name>
            <bitOffset>4</bitOffset>
            <bitWidth>4</bitWidth>
          </field>
          <field>
            <name>AFSEL10</name>
            <bitOffset>8</bitOffset>
            <bitWidth>4</bitWidth>
          </field>
          <field>
            <name>AFSEL11</name>
            <bitOffset>12</bitOffset>
            <bitWidth>4</bitWidth>
          </field>
          <field>
            <name>AFSEL12</name>
            <bitOffset>16</bitOffset>
            <bitWidth>4</bitWidth>
          </field>
          <field>
            <name>AFSEL13</name>
            <bitOffset>20</bitOffset>
            <bitWidth>4</bitWidth>
          </field>
          <field>
            <name>AFSEL14</name>
            <bitOffset>24</bitOffset>
            <bitWidth>4</bitWidth>
          </field>
          <field>
            <name>AFSEL15</name>
            <bitOffset>28</bitOffset>
            <bitWidth>4</bitWidth>
          </field>
        </fields>
      </register>
      <register>
        <name>BRR</name>
        <addressOffset>0x28</addressOffset>
        <size>0x20</size>
        <fields>
          <field>
            <name>BR0</name>
            <bitOffset>0</bitOffset>
            <bitWidth>1</bitWidth>
          </field>
          <field>
            <name>BR1</name>
            <bitOffset>1</bitOffset>
            <bitWidth>1</bitWidth>
          </field>
          <field>
            <name>BR2</name>
            <bitOffset>2</bitOffset>
            <bitWidth>1</bitWidth>
          </field>
          <field>
            <name>BR3</name>
            <bitOffset>3</bitOffset>
            <bitWidth>1</bitWidth>
          </field>
          <field>
            <name>BR4</name>
            <bitOffset>4</bitOffset>
            <bitWidth>1</bitWidth>
          </field>
          <field>
            <name>BR5</name>
            <bitOffset>5</bitOffset>
            <bitWidth>1</bitWidth>
          </field>
          <field>
            <name>BR6</name>
            <bitOffset>6</bitOffset>
            <bitWidth>1</bitWidth>
          </field>
          <field>
            <name>BR7</name>
            <bitOffset>7</bitOffset>
            <bitWidth>1</bitWidth>
          </field>
          <field>
            <name>BR8</name>
            <bitOffset>8</bitOffset>
            <bitWidth>1</bitWidth>
          </field>
          <field>
            <name>BR9</name>
            <bitOffset>9</bitOffset>
            <bitWidth>1</bitWidth>
          </field>
          <field>
            <name>BR10</name>
            <bitOffset>10</bitOffset>
            <bitWidth>1</bitWidth>
          </field>
          <field>
            <name>BR11</name>
            <bitOffset>11</bitOffset>
            <bitWidth>1</bitWidth>
          </field>
          <field>
            <name>BR12</name>
            <bitOffset>12</bitOffset>
            <bitWidth>1</bitWidth>
          </field>
          <field>
            <name>BR13</name>
            <bitOffset>13</bitOffset>
            <bitWidth>1</bitWidth>
          </field>
          <field>
            <name>BR14</name>
            <bitOffset>14</bitOffset>
            <bitWidth>1</bitWidth>
          </field>
          <field>
            <name>BR15</name>
            <bitOffset>15</bitOffset>
            <bitWidth>1</bitWidth>
          </field>
        </fields>
      </register>
    </peripheral>
    <peripheral>
      <name>GPIOF</name>
      <baseAddress>0x48001400</baseAddress>
      <register>
        <name>MODER</name>
        <addressOffset>0x0</addressOffset>
        <size>0x20</size>
        <fields>
          <field>
            <name>MODE0</name>
            <bitOffset>0</bitOffset>
            <bitWidth>2</bitWidth>
          </field>
          <field>
            <name>MODE1</name>
            <bitOffset>2</bitOffset>
            <bitWidth>2</bitWidth>
          </field>
          <field>
            <name>MODE2</name>
            <bitOffset>4</bitOffset>
            <bitWidth>2</bitWidth>
          </field>
          <field>
            <name>MODE3</name>
            <bitOffset>6</bitOffset>
            <bitWidth>2</bitWidth>
          </field>
          <field>
            <name>MODE4</name>
            <bitOffset>8</bitOffset>
            <bitWidth>2</bitWidth>
          </field>
          <field>
            <name>MODE5</name>
            <bitOffset>10</bitOffset>
            <bitWidth>2</bitWidth>
          </field>
          <field>
            <name>MODE6</name>
            <bitOffset>12</bitOffset>
            <bitWidth>2</bitWidth>
          </field>
          <field>
            <name>MODE7</name>
            <bitOffset>14</bitOffset>
            <bitWidth>2</bitWidth>
          </field>
          <field>
            <name>MODE8</name>
            <bitOffset>16</bitOffset>
            <bitWidth>2</bitWidth>
          </field>
          <field>
            <name>MODE9</name>
            <bitOffset>18</bitOffset>
            <bitWidth>2</bitWidth>
          </field>
          <field>
            <name>MODE10</name>
            <bitOffset>20</bitOffset>
            <bitWidth>2</bitWidth>
          </field>
          <field>
            <name>MODE11</name>
            <bitOffset>22</bitOffset>
            <bitWidth>2</bitWidth>
          </field>
          <field>
            <name>MODE12</name>
            <bitOffset>24</bitOffset>
            <bitWidth>2</bitWidth>
          </field>
          <field>
            <name>MODE13</name>
            <bitOffset>26</bitOffset>
            <bitWidth>2</bitWidth>
          </field>
          <field>
            <name>MODE14</name>
            <bitOffset>28</bitOffset>
            <bitWidth>2</bitWidth>
          </field>
          <field>
            <name>MODE15</name>
            <bitOffset>30</bitOffset>
            <bitWidth>2</bitWidth>
          </field>
        </fields>
      </register>
      <register>
        <name>OTYPER</name>
        <addressOffset>0x4</addressOffset>
        <size>0x20</size>
        <fields>
          <field>
            <name>OT0</name>
            <bitOffset>0</bitOffset>
            <bitWidth>1</bitWidth>
          </field>
          <field>
            <name>OT1</name>
            <bitOffset>1</bitOffset>
            <bitWidth>1</bitWidth>
          </field>
          <field>
            <name>OT2</name>
            <bitOffset>2</bitOffset>
            <bitWidth>1</bitWidth>
          </field>
          <field>
            <name>OT3</name>
            <bitOffset>3</bitOffset>
            <bitWidth>1</bitWidth>
          </field>
          <field>
            <name>OT4</name>
            <bitOffset>4</bitOffset>
            <bitWidth>1</bitWidth>
          </field>
          <field>
            <name>OT5</name>
            <bitOffset>5</bitOffset>
            <bitWidth>1</bitWidth>
          </field>
          <field>
            <name>OT6</name>
            <bitOffset>6</bitOffset>
            <bitWidth>1</bitWidth>
          </field>
          <field>
            <name>OT7</name>
            <bitOffset>7</bitOffset>
            <bitWidth>1</bitWidth>
          </field>
          <field>
            <name>OT8</name>
            <bitOffset>8</bitOffset>
            <bitWidth>1</bitWidth>
          </field>
          <field>
            <name>OT9</name>
            <bitOffset>9</bitOffset>
            <bitWidth>1</bitWidth>
          </field>
          <field>
            <name>OT10</name>
            <bitOffset>10</bitOffset>
            <bitWidth>1</bitWidth>
          </field>
          <field>
            <name>OT11</name>
            <bitOffset>11</bitOffset>
            <bitWidth>1</bitWidth>
          </field>
          <field>
            <name>OT12</name>
            <bitOffset>12</bitOffset>
            <bitWidth>1</bitWidth>
          </field>
          <field>
            <name>OT13</name>
            <bitOffset>13</bitOffset>
            <bitWidth>1</bitWidth>
          </field>
          <field>
            <name>OT14</name>
            <bitOffset>14</bitOffset>
            <bitWidth>1</bitWidth>
          </field>
          <field>
            <name>OT15</name>
            <bitOffset>15</bitOffset>
            <bitWidth>1</bitWidth>
          </field>
        </fields>
      </register>
      <register>
        <name>OSPEEDR</name>
        <addressOffset>0x8</addressOffset>
        <size>0x20</size>
        <fields>
          <field>
            <name>OSPEED0</name>
            <bitOffset>0</bitOffset>
            <bitWidth>2</bitWidth>
          </field>
          <field>
            <name>OSPEED1</name>
            <bitOffset>2</bitOffset>
            <bitWidth>2</bitWidth>
          </field>
          <field>
            <name>OSPEED2</name>
            <bitOffset>4</bitOffset>
            <bitWidth>2</bitWidth>
          </field>
          <field>
            <name>OSPEED3</name>
            <bitOffset>6</bitOffset>
            <bitWidth>2</bitWidth>
          </field>
          <field>
            <name>OSPEED4</name>
            <bitOffset>8</bitOffset>
            <bitWidth>2</bitWidth>
          </field>
          <field>
            <name>OSPEED5</name>
            <bitOffset>10</bitOffset>
            <bitWidth>2</bitWidth>
          </field>
          <field>
            <name>OSPEED6</name>
            <bitOffset>12</bitOffset>
            <bitWidth>2</bitWidth>
          </field>
          <field>
            <name>OSPEED7</name>
            <bitOffset>14</bitOffset>
            <bitWidth>2</bitWidth>
          </field>
          <field>
            <name>OSPEED8</name>
            <bitOffset>16</bitOffset>
            <bitWidth>2</bitWidth>
          </field>
          <field>
            <name>OSPEED9</name>
            <bitOffset>18</bitOffset>
            <bitWidth>2</bitWidth>
          </field>
          <field>
            <name>OSPEED10</name>
            <bitOffset>20</bitOffset>
            <bitWidth>2</bitWidth>
          </field>
          <field>
            <name>OSPEED11</name>
            <bitOffset>22</bitOffset>
            <bitWidth>2</bitWidth>
          </field>
          <field>
            <name>OSPEED12</name>
            <bitOffset>24</bitOffset>
            <bitWidth>2</bitWidth>
          </field>
          <field>
            <name>OSPEED13</name>
            <bitOffset>26</bitOffset>
            <bitWidth>2</bitWidth>
          </field>
          <field>
            <name>OSPEED14</name>
            <bitOffset>28</bitOffset>
            <bitWidth>2</bitWidth>
          </field>
          <field>
            <name>OSPEED15</name>
            <bitOffset>30</bitOffset>
            <bitWidth>2</bitWidth>
          </field>
        </fields>
      </register>
      <register>
        <name>PUPDR</name>
        <addressOffset>0xc</addressOffset>
        <size>0x20</size>
        <fields>
          <field>
            <name>PUPD0</name>
            <bitOffset>0</bitOffset>
            <bitWidth>2</bitWidth>
          </field>
          <field>
            <name>PUPD1</name>
            <bitOffset>2</bitOffset>
            <bitWidth>2</bitWidth>
          </field>
          <field>
            <name>PUPD2</name>
            <bitOffset>4</bitOffset>
            <bitWidth>2</bitWidth>
          </field>
          <field>
            <name>PUPD3</name>
            <bitOffset>6</bitOffset>
            <bitWidth>2</bitWidth>
          </field>
          <field>
            <name>PUPD4</name>
            <bitOffset>8</bitOffset>
            <bitWidth>2</bitWidth>
          </field>
          <field>
            <name>PUPD5</name>
            <bitOffset>10</bitOffset>
            <bitWidth>2</bitWidth>
          </field>
          <field>
            <name>PUPD6</name>
            <bitOffset>12</bitOffset>
            <bitWidth>2</bitWidth>
          </field>
          <field>
            <name>PUPD7</name>
            <bitOffset>14</bitOffset>
            <bitWidth>2</bitWidth>
          </field>
          <field>
            <name>PUPD8</name>
            <bitOffset>16</bitOffset>
            <bitWidth>2</bitWidth>
          </field>
          <field>
            <name>PUPD9</name>
            <bitOffset>18</bitOffset>
            <bitWidth>2</bitWidth>
          </field>
          <field>
            <name>PUPD10</name>
            <bitOffset>20</bitOffset>
            <bitWidth>2</bitWidth>
          </field>
          <field>
            <name>PUPD11</name>
            <bitOffset>22</bitOffset>
            <bitWidth>2</bitWidth>
          </field>
          <field>
            <name>PUPD12</name>
            <bitOffset>24</bitOffset>
            <bitWidth>2</bitWidth>
          </field>
          <field>
            <name>PUPD13</name>
            <bitOffset>26</bitOffset>
            <bitWidth>2</bitWidth>
          </field>
          <field>
            <name>PUPD14</name>
            <bitOffset>28</bitOffset>
            <bitWidth>2</bitWidth>
          </field>
          <field>
            <name>PUPD15</name>
            <bitOffset>30</bitOffset>
            <bitWidth>2</bitWidth>
          </field>
        </fields>
      </register>
      <register>
        <name>IDR</name>
        <addressOffset>0x10</addressOffset>
        <size>0x20</size>
        <fields>
          <field>
            <name>ID0</name>
            <bitOffset>0</bitOffset>
            <bitWidth>1</bitWidth>
          </field>
          <field>
            <name>ID1</name>
            <bitOffset>1</bitOffset>
            <bitWidth>1</bitWidth>
          </field>
          <field>
            <name>ID2</name>
            <bitOffset>2</bitOffset>
            <bitWidth>1</bitWidth>
          </field>
          <field>
            <name>ID3</name>
            <bitOffset>3</bitOffset>
            <bitWidth>1</bitWidth>
          </field>
          <field>
            <name>ID4</name>
            <bitOffset>4</bitOffset>
            <bitWidth>1</bitWidth>
          </field>
          <field>
            <name>ID5</name>
            <bitOffset>5</bitOffset>
            <bitWidth>1</bitWidth>
          </field>
          <field>
            <name>ID6</name>
            <bitOffset>6</bitOffset>
            <bitWidth>1</bitWidth>
          </field>
          <field>
            <name>ID7</name>
            <bitOffset>7</bitOffset>
            <bitWidth>1</bitWidth>
          </field>
          <field>
            <name>ID8</name>
            <bitOffset>8</bitOffset>
            <bitWidth>1</bitWidth>
          </field>
          <field>
            <name>ID9</name>
            <bitOffset>9</bitOffset>
            <bitWidth>1</bitWidth>
          </field>
          <field>
            <name>ID10</name>
            <bitOffset>10</bitOffset>
            <bitWidth>1</bitWidth>
          </field>
          <field>
            <name>ID11</name>
            <bitOffset>11</bitOffset>
            <bitWidth>1</bitWidth>
          </field>
          <field>
            <name>ID12</name>
            <bitOffset>12</bitOffset>
            <bitWidth>1</bitWidth>
          </field>
          <field>
            <name>ID13</name>
            <bitOffset>13</bitOffset>
            <bitWidth>1</bitWidth>
          </field>
          <field>
            <name>ID14</name>
            <bitOffset>14</bitOffset>
            <bitWidth>1</bitWidth>
          </field>
          <field>
            <name>ID15</name>
            <bitOffset>15</bitOffset>
            <bitWidth>1</bitWidth>
          </field>
        </fields>
      </register>
      <register>
        <name>ODR</name>
        <addressOffset>0x14</addressOffset>
        <size>0x20</size>
        <fields>
          <field>
            <name>OD0</name>
            <bitOffset>0</bitOffset>
            <bitWidth>1</bitWidth>
          </field>
          <field>
            <name>OD1</name>
            <bitOffset>1</bitOffset>
            <bitWidth>1</bitWidth>
          </field>
          <field>
            <name>OD2</name>
            <bitOffset>2</bitOffset>
            <bitWidth>1</bitWidth>
          </field>
          <field>
            <name>OD3</name>
            <bitOffset>3</bitOffset>
            <bitWidth>1</bitWidth>
          </field>
          <field>
            <name>OD4</name>
            <bitOffset>4</bitOffset>
            <bitWidth>1</bitWidth>
          </field>
          <field>
            <name>OD5</name>
            <bitOffset>5</bitOffset>
            <bitWidth>1</bitWidth>
          </field>
          <field>
            <name>OD6</name>
            <bitOffset>6</bitOffset>
            <bitWidth>1</bitWidth>
          </field>
          <field>
            <name>OD7</name>
            <bitOffset>7</bitOffset>
            <bitWidth>1</bitWidth>
          </field>
          <field>
            <name>OD8</name>
            <bitOffset>8</bitOffset>
            <bitWidth>1</bitWidth>
          </field>
          <field>
            <name>OD9</name>
            <bitOffset>9</bitOffset>
            <bitWidth>1</bitWidth>
          </field>
          <field>
            <name>OD10</name>
            <bitOffset>10</bitOffset>
            <bitWidth>1</bitWidth>
          </field>
          <field>
            <name>OD11</name>
            <bitOffset>11</bitOffset>
            <bitWidth>1</bitWidth>
          </field>
          <field>
            <name>OD12</name>
            <bitOffset>12</bitOffset>
            <bitWidth>1</bitWidth>
          </field>
          <field>
            <name>OD13</name>
            <bitOffset>13</bitOffset>
            <bitWidth>1</bitWidth>
          </field>
          <field>
            <name>OD14</name>
            <bitOffset>14</bitOffset>
            <bitWidth>1</bitWidth>
          </field>
          <field>
            <name>OD15</name>
            <bitOffset>15</bitOffset>
            <bitWidth>1</bitWidth>
          </field>
        </fields>
      </register>
      <register>
        <name>BSRR</name>
        <addressOffset>0x18</addressOffset>
        <size>0x20</size>
        <fields>
          <field>
            <name>BS0</name>
            <bitOffset>0</bitOffset>
            <bitWidth>1</bitWidth>
          </field>
          <field>
            <name>BS1</name>
            <bitOffset>1</bitOffset>
            <bitWidth>1</bitWidth>
          </field>
          <field>
            <name>BS2</name>
            <bitOffset>2</bitOffset>
            <bitWidth>1</bitWidth>
          </field>
          <field>
            <name>BS3</name>
            <bitOffset>3</bitOffset>
            <bitWidth>1</bitWidth>
          </field>
          <field>
            <name>BS4</name>
            <bitOffset>4</bitOffset>
            <bitWidth>1</bitWidth>
          </field>
          <field>
            <name>BS5</name>
            <bitOffset>5</bitOffset>
            <bitWidth>1</bitWidth>
          </field>
          <field>
            <name>BS6</name>
            <bitOffset>6</bitOffset>
            <bitWidth>1</bitWidth>
          </field>
          <field>
            <name>BS7</name>
            <bitOffset>7</bitOffset>
            <bitWidth>1</bitWidth>
          </field>
          <field>
            <name>BS8</name>
            <bitOffset>8</bitOffset>
            <bitWidth>1</bitWidth>
          </field>
          <field>
            <name>BS9</name>
            <bitOffset>9</bitOffset>
            <bitWidth>1</bitWidth>
          </field>
          <field>
            <name>BS10</name>
            <bitOffset>10</bitOffset>
            <bitWidth>1</bitWidth>
          </field>
          <field>
            <name>BS11</name>
            <bitOffset>11</bitOffset>
            <bitWidth>1</bitWidth>
          </field>
          <field>
            <name>BS12</name>
            <bitOffset>12</bitOffset>
            <bitWidth>1</bitWidth>
          </field>
          <field>
            <name>BS13</name>
            <bitOffset>13</bitOffset>
            <bitWidth>1</bitWidth>
          </field>
          <field>
            <name>BS14</name>
            <bitOffset>14</bitOffset>
            <bitWidth>1</bitWidth>
          </field>
          <field>
            <name>BS15</name>
            <bitOffset>15</bitOffset>
            <bitWidth>1</bitWidth>
          </field>
          <field>
            <name>BR0</name>
            <bitOffset>16</bitOffset>
            <bitWidth>1</bitWidth>
          </field>
          <field>
            <name>BR1</name>
            <bitOffset>17</bitOffset>
            <bitWidth>1</bitWidth>
          </field>
          <field>
            <name>BR2</name>
            <bitOffset>18</bitOffset>
            <bitWidth>1</bitWidth>
          </field>
          <field>
            <name>BR3</name>
            <bitOffset>19</bitOffset>
            <bitWidth>1</bitWidth>
          </field>
          <field>
            <name>BR4</name>
            <bitOffset>20</bitOffset>
            <bitWidth>1</bitWidth>
          </field>
          <field>
            <name>BR5</name>
            <bitOffset>21</bitOffset>
            <bitWidth>1</bitWidth>
          </field>
          <field>
            <name>BR6</name>
            <bitOffset>22</bitOffset>
            <bitWidth>1</bitWidth>
          </field>
          <field>
            <name>BR7</name>
            <bitOffset>23</bitOffset>
            <bitWidth>1</bitWidth>
          </field>
          <field>
            <name>BR8</name>
            <bitOffset>24</bitOffset>
            <bitWidth>1</bitWidth>
          </field>
          <field>
            <name>BR9</name>
            <bitOffset>25</bitOffset>
            <bitWidth>1</bitWidth>
          </field>
          <field>
            <name>BR10</name>
            <bitOffset>26</bitOffset>
            <bitWidth>1</bitWidth>
          </field>
          <field>
            <name>BR11</name>
            <bitOffset>27</bitOffset>
            <bitWidth>1</bitWidth>
          </field>
          <field>
            <name>BR12</name>
            <bitOffset>28</bitOffset>
            <bitWidth>1</bitWidth>
          </field>
          <field>
            <name>BR13</name>
            <bitOffset>29</bitOffset>
            <bitWidth>1</bitWidth>
          </field>
          <field>
            <name>BR14</name>
            <bitOffset>30</bitOffset>
            <bitWidth>1</bitWidth>
          </field>
          <field>
            <name>BR15</name>
            <bitOffset>31</bitOffset>
            <bitWidth>1</bitWidth>
          </field>
        </fields>
      </register>
      <register>
        <name>LCKR</name>
        <addressOffset>0x1c</addressOffset>
        <size>0x20</size>
        <fields>
          <field>
            <name>LCK0</name>
            <bitOffset>0</bitOffset>
            <bitWidth>1</bitWidth>
          </field>
          <field>
            <name>LCK1</name>
            <bitOffset>1</bitOffset>
            <bitWidth>1</bitWidth>
          </field>
          <field>
            <name>LCK2</name>
            <bitOffset>2</bitOffset>
            <bitWidth>1</bitWidth>
          </field>
          <field>
            <name>LCK3</name>
            <bitOffset>3</bitOffset>
            <bitWidth>1</bitWidth>
          </field>
          <field>
            <name>LCK4</name>
            <bitOffset>4</bitOffset>
            <bitWidth>1</bitWidth>
          </field>
          <field>
            <name>LCK5</name>
            <bitOffset>5</bitOffset>
            <bitWidth>1</bitWidth>
          </field>
          <field>
            <name>LCK6</name>
            <bitOffset>6</bitOffset>
            <bitWidth>1</bitWidth>
          </field>
          <field>
            <name>LCK7</name>
            <bitOffset>7</bitOffset>
            <bitWidth>1</bitWidth>
          </field>
          <field>
            <name>LCK8</name>
            <bitOffset>8</bitOffset>
            <bitWidth>1</bitWidth>
          </field>
          <field>
            <name>LCK9</name>
            <bitOffset>9</bitOffset>
            <bitWidth>1</bitWidth>
          </field>
          <field>
            <name>LCK10</name>
            <bitOffset>10</bitOffset>
            <bitWidth>1</bitWidth>
          </field>
          <field>
            <name>LCK11</name>
            <bitOffset>11</bitOffset>
            <bitWidth>1</bitWidth>
          </field>
          <field>
            <name>LCK12</name>
            <bitOffset>12</bitOffset>
            <bitWidth>1</bitWidth>
          </field>
          <field>
            <name>LCK13</name>
            <bitOffset>13</bitOffset>
            <bitWidth>1</bitWidth>
          </field>
          <field>
            <name>LCK14</name>
            <bitOffset>14</bitOffset>
            <bitWidth>1</bitWidth>
          </field>
          <field>
            <name>LCK15</name>
            <bitOffset>15</bitOffset>
            <bitWidth>1</bitWidth>
          </field>
          <field>
            <name>LCKK</name>
            <bitOffset>16</bitOffset>
            <bitWidth>1</bitWidth>
          </field>
        </fields>
      </register>
      <register>
        <name>AFR.0</name>
        <addressOffset>0x20</addressOffset>
        <size>0x20</size>
        <fields>
          <field>
            <name>AFSEL0</name>
            <bitOffset>0</bitOffset>
            <bitWidth>4</bitWidth>
          </field>
          <field>
            <name>AFSEL1</name>
            <bitOffset>4</bitOffset>
            <bitWidth>4</bitWidth>
          </field>
          <field>
            <name>AFSEL2</name>
            <bitOffset>8</bitOffset>
            <bitWidth>4</bitWidth>
          </field>
          <field>
            <name>AFSEL3</name>
            <bitOffset>12</bitOffset>
            <bitWidth>4</bitWidth>
          </field>
          <field>
            <name>AFSEL4</name>
            <bitOffset>16</bitOffset>
            <bitWidth>4</bitWidth>
          </field>
          <field>
            <name>AFSEL5</name>
            <bitOffset>20</bitOffset>
            <bitWidth>4</bitWidth>
          </field>
          <field>
            <name>AFSEL6</name>
            <bitOffset>24</bitOffset>
            <bitWidth>4</bitWidth>
          </field>
          <field>
            <name>AFSEL7</name>
            <bitOffset>28</bitOffset>
            <bitWidth>4</bitWidth>
          </field>
        </fields>
      </register>
      <register>
        <name>AFR.1</name>
        <addressOffset>0x24</addressOffset>
        <size>0x20</size>
        <fields>
          <field>
            <name>AFSEL8</name>
            <bitOffset>0</bitOffset>
            <bitWidth>4</bitWidth>
          </field>
          <field>
            <name>AFSEL9</name>
            <bitOffset>4</bitOffset>
            <bitWidth>4</bitWidth>
          </field>
          <field>
            <name>AFSEL10</name>
            <bitOffset>8</bitOffset>
            <bitWidth>4</bitWidth>
          </field>
          <field>
            <name>AFSEL11</name>
            <bitOffset>12</bitOffset>
            <bitWidth>4</bitWidth>
          </field>
          <field>
            <name>AFSEL12</name>
            <bitOffset>16</bitOffset>
            <bitWidth>4</bitWidth>
          </field>
          <field>
            <name>AFSEL13</name>
            <bitOffset>20</bitOffset>
            <bitWidth>4</bitWidth>
          </field>
          <field>
            <name>AFSEL14</name>
            <bitOffset>24</bitOffset>
            <bitWidth>4</bitWidth>
          </field>
          <field>
            <name>AFSEL15</name>
            <bitOffset>28</bitOffset>
            <bitWidth>4</bitWidth>
          </field>
        </fields>
      </register>
      <register>
        <name>BRR</name>
        <addressOffset>0x28</addressOffset>
        <size>0x20</size>
        <fields>
          <field>
            <name>BR0</name>
            <bitOffset>0</bitOffset>
            <bitWidth>1</bitWidth>
          </field>
          <field>
            <name>BR1</name>
            <bitOffset>1</bitOffset>
            <bitWidth>1</bitWidth>
          </field>
          <field>
            <name>BR2</name>
            <bitOffset>2</bitOffset>
            <bitWidth>1</bitWidth>
          </field>
          <field>
            <name>BR3</name>
            <bitOffset>3</bitOffset>
            <bitWidth>1</bitWidth>
          </field>
          <field>
            <name>BR4</name>
            <bitOffset>4</bitOffset>
            <bitWidth>1</bitWidth>
          </field>
          <field>
            <name>BR5</name>
            <bitOffset>5</bitOffset>
            <bitWidth>1</bitWidth>
          </field>
          <field>
            <name>BR6</name>
            <bitOffset>6</bitOffset>
            <bitWidth>1</bitWidth>
          </field>
          <field>
            <name>BR7</name>
            <bitOffset>7</bitOffset>
            <bitWidth>1</bitWidth>
          </field>
          <field>
            <name>BR8</name>
            <bitOffset>8</bitOffset>
            <bitWidth>1</bitWidth>
          </field>
          <field>
            <name>BR9</name>
            <bitOffset>9</bitOffset>
            <bitWidth>1</bitWidth>
          </field>
          <field>
            <name>BR10</name>
            <bitOffset>10</bitOffset>
            <bitWidth>1</bitWidth>
          </field>
          <field>
            <name>BR11</name>
            <bitOffset>11</bitOffset>
            <bitWidth>1</bitWidth>
          </field>
          <field>
            <name>BR12</name>
            <bitOffset>12</bitOffset>
            <bitWidth>1</bitWidth>
          </field>
          <field>
            <name>BR13</name>
            <bitOffset>13</bitOffset>
            <bitWidth>1</bitWidth>
          </field>
          <field>
            <name>BR14</name>
            <bitOffset>14</bitOffset>
            <bitWidth>1</bitWidth>
          </field>
          <field>
            <name>BR15</name>
            <bitOffset>15</bitOffset>
            <bitWidth>1</bitWidth>
          </field>
        </fields>
      </register>
    </peripheral>
    <peripheral>
      <name>GPIOG</name>
      <baseAddress>0x48001800</baseAddress>
      <register>
        <name>MODER</name>
        <addressOffset>0x0</addressOffset>
        <size>0x20</size>
        <fields>
          <field>
            <name>MODE0</name>
            <bitOffset>0</bitOffset>
            <bitWidth>2</bitWidth>
          </field>
          <field>
            <name>MODE1</name>
            <bitOffset>2</bitOffset>
            <bitWidth>2</bitWidth>
          </field>
          <field>
            <name>MODE2</name>
            <bitOffset>4</bitOffset>
            <bitWidth>2</bitWidth>
          </field>
          <field>
            <name>MODE3</name>
            <bitOffset>6</bitOffset>
            <bitWidth>2</bitWidth>
          </field>
          <field>
            <name>MODE4</name>
            <bitOffset>8</bitOffset>
            <bitWidth>2</bitWidth>
          </field>
          <field>
            <name>MODE5</name>
            <bitOffset>10</bitOffset>
            <bitWidth>2</bitWidth>
          </field>
          <field>
            <name>MODE6</name>
            <bitOffset>12</bitOffset>
            <bitWidth>2</bitWidth>
          </field>
          <field>
            <name>MODE7</name>
            <bitOffset>14</bitOffset>
            <bitWidth>2</bitWidth>
          </field>
          <field>
            <name>MODE8</name>
            <bitOffset>16</bitOffset>
            <bitWidth>2</bitWidth>
          </field>
          <field>
            <name>MODE9</name>
            <bitOffset>18</bitOffset>
            <bitWidth>2</bitWidth>
          </field>
          <field>
            <name>MODE10</name>
            <bitOffset>20</bitOffset>
            <bitWidth>2</bitWidth>
          </field>
          <field>
            <name>MODE11</name>
            <bitOffset>22</bitOffset>
            <bitWidth>2</bitWidth>
          </field>
          <field>
            <name>MODE12</name>
            <bitOffset>24</bitOffset>
            <bitWidth>2</bitWidth>
          </field>
          <field>
            <name>MODE13</name>
            <bitOffset>26</bitOffset>
            <bitWidth>2</bitWidth>
          </field>
          <field>
            <name>MODE14</name>
            <bitOffset>28</bitOffset>
            <bitWidth>2</bitWidth>
          </field>
          <field>
            <name>MODE15</name>
            <bitOffset>30</bitOffset>
            <bitWidth>2</bitWidth>
          </field>
        </fields>
      </register>
      <register>
        <name>OTYPER</name>
        <addressOffset>0x4</addressOffset>
        <size>0x20</size>
        <fields>
          <field>
            <name>OT0</name>
            <bitOffset>0</bitOffset>
            <bitWidth>1</bitWidth>
          </field>
          <field>
            <name>OT1</name>
            <bitOffset>1</bitOffset>
            <bitWidth>1</bitWidth>
          </field>
          <field>
            <name>OT2</name>
            <bitOffset>2</bitOffset>
            <bitWidth>1</bitWidth>
          </field>
          <field>
            <name>OT3</name>
            <bitOffset>3</bitOffset>
            <bitWidth>1</bitWidth>
          </field>
          <field>
            <name>OT4</name>
            <bitOffset>4</bitOffset>
            <bitWidth>1</bitWidth>
          </field>
          <field>
            <name>OT5</name>
            <bitOffset>5</bitOffset>
            <bitWidth>1</bitWidth>
          </field>
          <field>
            <name>OT6</name>
            <bitOffset>6</bitOffset>
            <bitWidth>1</bitWidth>
          </field>
          <field>
            <name>OT7</name>
            <bitOffset>7</bitOffset>
            <bitWidth>1</bitWidth>
          </field>
          <field>
            <name>OT8</name>
            <bitOffset>8</bitOffset>
            <bitWidth>1</bitWidth>
          </field>
          <field>
            <name>OT9</name>
            <bitOffset>9</bitOffset>
            <bitWidth>1</bitWidth>
          </field>
          <field>
            <name>OT10</name>
            <bitOffset>10</bitOffset>
            <bitWidth>1</bitWidth>
          </field>
          <field>
            <name>OT11</name>
            <bitOffset>11</bitOffset>
            <bitWidth>1</bitWidth>
          </field>
          <field>
            <name>OT12</name>
            <bitOffset>12</bitOffset>
            <bitWidth>1</bitWidth>
          </field>
          <field>
            <name>OT13</name>
            <bitOffset>13</bitOffset>
            <bitWidth>1</bitWidth>
          </field>
          <field>
            <name>OT14</name>
            <bitOffset>14</bitOffset>
            <bitWidth>1</bitWidth>
          </field>
          <field>
            <name>OT15</name>
            <bitOffset>15</bitOffset>
            <bitWidth>1</bitWidth>
          </field>
        </fields>
      </register>
      <register>
        <name>OSPEEDR</name>
        <addressOffset>0x8</addressOffset>
        <size>0x20</size>
        <fields>
          <field>
            <name>OSPEED0</name>
            <bitOffset>0</bitOffset>
            <bitWidth>2</bitWidth>
          </field>
          <field>
            <name>OSPEED1</name>
            <bitOffset>2</bitOffset>
            <bitWidth>2</bitWidth>
          </field>
          <field>
            <name>OSPEED2</name>
            <bitOffset>4</bitOffset>
            <bitWidth>2</bitWidth>
          </field>
          <field>
            <name>OSPEED3</name>
            <bitOffset>6</bitOffset>
            <bitWidth>2</bitWidth>
          </field>
          <field>
            <name>OSPEED4</name>
            <bitOffset>8</bitOffset>
            <bitWidth>2</bitWidth>
          </field>
          <field>
            <name>OSPEED5</name>
            <bitOffset>10</bitOffset>
            <bitWidth>2</bitWidth>
          </field>
          <field>
            <name>OSPEED6</name>
            <bitOffset>12</bitOffset>
            <bitWidth>2</bitWidth>
          </field>
          <field>
            <name>OSPEED7</name>
            <bitOffset>14</bitOffset>
            <bitWidth>2</bitWidth>
          </field>
          <field>
            <name>OSPEED8</name>
            <bitOffset>16</bitOffset>
            <bitWidth>2</bitWidth>
          </field>
          <field>
            <name>OSPEED9</name>
            <bitOffset>18</bitOffset>
            <bitWidth>2</bitWidth>
          </field>
          <field>
            <name>OSPEED10</name>
            <bitOffset>20</bitOffset>
            <bitWidth>2</bitWidth>
          </field>
          <field>
            <name>OSPEED11</name>
            <bitOffset>22</bitOffset>
            <bitWidth>2</bitWidth>
          </field>
          <field>
            <name>OSPEED12</name>
            <bitOffset>24</bitOffset>
            <bitWidth>2</bitWidth>
          </field>
          <field>
            <name>OSPEED13</name>
            <bitOffset>26</bitOffset>
            <bitWidth>2</bitWidth>
          </field>
          <field>
            <name>OSPEED14</name>
            <bitOffset>28</bitOffset>
            <bitWidth>2</bitWidth>
          </field>
          <field>
            <name>OSPEED15</name>
            <bitOffset>30</bitOffset>
            <bitWidth>2</bitWidth>
          </field>
        </fields>
      </register>
      <register>
        <name>PUPDR</name>
        <addressOffset>0xc</addressOffset>
        <size>0x20</size>
        <fields>
          <field>
            <name>PUPD0</name>
            <bitOffset>0</bitOffset>
            <bitWidth>2</bitWidth>
          </field>
          <field>
            <name>PUPD1</name>
            <bitOffset>2</bitOffset>
            <bitWidth>2</bitWidth>
          </field>
          <field>
            <name>PUPD2</name>
            <bitOffset>4</bitOffset>
            <bitWidth>2</bitWidth>
          </field>
          <field>
            <name>PUPD3</name>
            <bitOffset>6</bitOffset>
            <bitWidth>2</bitWidth>
          </field>
          <field>
            <name>PUPD4</name>
            <bitOffset>8</bitOffset>
            <bitWidth>2</bitWidth>
          </field>
          <field>
            <name>PUPD5</name>
            <bitOffset>10</bitOffset>
            <bitWidth>2</bitWidth>
          </field>
          <field>
            <name>PUPD6</name>
            <bitOffset>12</bitOffset>
            <bitWidth>2</bitWidth>
          </field>
          <field>
            <name>PUPD7</name>
            <bitOffset>14</bitOffset>
            <bitWidth>2</bitWidth>
          </field>
          <field>
            <name>PUPD8</name>
            <bitOffset>16</bitOffset>
            <bitWidth>2</bitWidth>
          </field>
          <field>
            <name>PUPD9</name>
            <bitOffset>18</bitOffset>
            <bitWidth>2</bitWidth>
          </field>
          <field>
            <name>PUPD10</name>
            <bitOffset>20</bitOffset>
            <bitWidth>2</bitWidth>
          </field>
          <field>
            <name>PUPD11</name>
            <bitOffset>22</bitOffset>
            <bitWidth>2</bitWidth>
          </field>
          <field>
            <name>PUPD12</name>
            <bitOffset>24</bitOffset>
            <bitWidth>2</bitWidth>
          </field>
          <field>
            <name>PUPD13</name>
            <bitOffset>26</bitOffset>
            <bitWidth>2</bitWidth>
          </field>
          <field>
            <name>PUPD14</name>
            <bitOffset>28</bitOffset>
            <bitWidth>2</bitWidth>
          </field>
          <field>
            <name>PUPD15</name>
            <bitOffset>30</bitOffset>
            <bitWidth>2</bitWidth>
          </field>
        </fields>
      </register>
      <register>
        <name>IDR</name>
        <addressOffset>0x10</addressOffset>
        <size>0x20</size>
        <fields>
          <field>
            <name>ID0</name>
            <bitOffset>0</bitOffset>
            <bitWidth>1</bitWidth>
          </field>
          <field>
            <name>ID1</name>
            <bitOffset>1</bitOffset>
            <bitWidth>1</bitWidth>
          </field>
          <field>
            <name>ID2</name>
            <bitOffset>2</bitOffset>
            <bitWidth>1</bitWidth>
          </field>
          <field>
            <name>ID3</name>
            <bitOffset>3</bitOffset>
            <bitWidth>1</bitWidth>
          </field>
          <field>
            <name>ID4</name>
            <bitOffset>4</bitOffset>
            <bitWidth>1</bitWidth>
          </field>
          <field>
            <name>ID5</name>
            <bitOffset>5</bitOffset>
            <bitWidth>1</bitWidth>
          </field>
          <field>
            <name>ID6</name>
            <bitOffset>6</bitOffset>
            <bitWidth>1</bitWidth>
          </field>
          <field>
            <name>ID7</name>
            <bitOffset>7</bitOffset>
            <bitWidth>1</bitWidth>
          </field>
          <field>
            <name>ID8</name>
            <bitOffset>8</bitOffset>
            <bitWidth>1</bitWidth>
          </field>
          <field>
            <name>ID9</name>
            <bitOffset>9</bitOffset>
            <bitWidth>1</bitWidth>
          </field>
          <field>
            <name>ID10</name>
            <bitOffset>10</bitOffset>
            <bitWidth>1</bitWidth>
          </field>
          <field>
            <name>ID11</name>
            <bitOffset>11</bitOffset>
            <bitWidth>1</bitWidth>
          </field>
          <field>
            <name>ID12</name>
            <bitOffset>12</bitOffset>
            <bitWidth>1</bitWidth>
          </field>
          <field>
            <name>ID13</name>
            <bitOffset>13</bitOffset>
            <bitWidth>1</bitWidth>
          </field>
          <field>
            <name>ID14</name>
            <bitOffset>14</bitOffset>
            <bitWidth>1</bitWidth>
          </field>
          <field>
            <name>ID15</name>
            <bitOffset>15</bitOffset>
            <bitWidth>1</bitWidth>
          </field>
        </fields>
      </register>
      <register>
        <name>ODR</name>
        <addressOffset>0x14</addressOffset>
        <size>0x20</size>
        <fields>
          <field>
            <name>OD0</name>
            <bitOffset>0</bitOffset>
            <bitWidth>1</bitWidth>
          </field>
          <field>
            <name>OD1</name>
            <bitOffset>1</bitOffset>
            <bitWidth>1</bitWidth>
          </field>
          <field>
            <name>OD2</name>
            <bitOffset>2</bitOffset>
            <bitWidth>1</bitWidth>
          </field>
          <field>
            <name>OD3</name>
            <bitOffset>3</bitOffset>
            <bitWidth>1</bitWidth>
          </field>
          <field>
            <name>OD4</name>
            <bitOffset>4</bitOffset>
            <bitWidth>1</bitWidth>
          </field>
          <field>
            <name>OD5</name>
            <bitOffset>5</bitOffset>
            <bitWidth>1</bitWidth>
          </field>
          <field>
            <name>OD6</name>
            <bitOffset>6</bitOffset>
            <bitWidth>1</bitWidth>
          </field>
          <field>
            <name>OD7</name>
            <bitOffset>7</bitOffset>
            <bitWidth>1</bitWidth>
          </field>
          <field>
            <name>OD8</name>
            <bitOffset>8</bitOffset>
            <bitWidth>1</bitWidth>
          </field>
          <field>
            <name>OD9</name>
            <bitOffset>9</bitOffset>
            <bitWidth>1</bitWidth>
          </field>
          <field>
            <name>OD10</name>
            <bitOffset>10</bitOffset>
            <bitWidth>1</bitWidth>
          </field>
          <field>
            <name>OD11</name>
            <bitOffset>11</bitOffset>
            <bitWidth>1</bitWidth>
          </field>
          <field>
            <name>OD12</name>
            <bitOffset>12</bitOffset>
            <bitWidth>1</bitWidth>
          </field>
          <field>
            <name>OD13</name>
            <bitOffset>13</bitOffset>
            <bitWidth>1</bitWidth>
          </field>
          <field>
            <name>OD14</name>
            <bitOffset>14</bitOffset>
            <bitWidth>1</bitWidth>
          </field>
          <field>
            <name>OD15</name>
            <bitOffset>15</bitOffset>
            <bitWidth>1</bitWidth>
          </field>
        </fields>
      </register>
      <register>
        <name>BSRR</name>
        <addressOffset>0x18</addressOffset>
        <size>0x20</size>
        <fields>
          <field>
            <name>BS0</name>
            <bitOffset>0</bitOffset>
            <bitWidth>1</bitWidth>
          </field>
          <field>
            <name>BS1</name>
            <bitOffset>1</bitOffset>
            <bitWidth>1</bitWidth>
          </field>
          <field>
            <name>BS2</name>
            <bitOffset>2</bitOffset>
            <bitWidth>1</bitWidth>
          </field>
          <field>
            <name>BS3</name>
            <bitOffset>3</bitOffset>
            <bitWidth>1</bitWidth>
          </field>
          <field>
            <name>BS4</name>
            <bitOffset>4</bitOffset>
            <bitWidth>1</bitWidth>
          </field>
          <field>
            <name>BS5</name>
            <bitOffset>5</bitOffset>
            <bitWidth>1</bitWidth>
          </field>
          <field>
            <name>BS6</name>
            <bitOffset>6</bitOffset>
            <bitWidth>1</bitWidth>
          </field>
          <field>
            <name>BS7</name>
            <bitOffset>7</bitOffset>
            <bitWidth>1</bitWidth>
          </field>
          <field>
            <name>BS8</name>
            <bitOffset>8</bitOffset>
            <bitWidth>1</bitWidth>
          </field>
          <field>
            <name>BS9</name>
            <bitOffset>9</bitOffset>
            <bitWidth>1</bitWidth>
          </field>
          <field>
            <name>BS10</name>
            <bitOffset>10</bitOffset>
            <bitWidth>1</bitWidth>
          </field>
          <field>
            <name>BS11</name>
            <bitOffset>11</bitOffset>
            <bitWidth>1</bitWidth>
          </field>
          <field>
            <name>BS12</name>
            <bitOffset>12</bitOffset>
            <bitWidth>1</bitWidth>
          </field>
          <field>
            <name>BS13</name>
            <bitOffset>13</bitOffset>
            <bitWidth>1</bitWidth>
          </field>
          <field>
            <name>BS14</name>
            <bitOffset>14</bitOffset>
            <bitWidth>1</bitWidth>
          </field>
          <field>
            <name>BS15</name>
            <bitOffset>15</bitOffset>
            <bitWidth>1</bitWidth>
          </field>
          <field>
            <name>BR0</name>
            <bitOffset>16</bitOffset>
            <bitWidth>1</bitWidth>
          </field>
          <field>
            <name>BR1</name>
            <bitOffset>17</bitOffset>
            <bitWidth>1</bitWidth>
          </field>
          <field>
            <name>BR2</name>
            <bitOffset>18</bitOffset>
            <bitWidth>1</bitWidth>
          </field>
          <field>
            <name>BR3</name>
            <bitOffset>19</bitOffset>
            <bitWidth>1</bitWidth>
          </field>
          <field>
            <name>BR4</name>
            <bitOffset>20</bitOffset>
            <bitWidth>1</bitWidth>
          </field>
          <field>
            <name>BR5</name>
            <bitOffset>21</bitOffset>
            <bitWidth>1</bitWidth>
          </field>
          <field>
            <name>BR6</name>
            <bitOffset>22</bitOffset>
            <bitWidth>1</bitWidth>
          </field>
          <field>
            <name>BR7</name>
            <bitOffset>23</bitOffset>
            <bitWidth>1</bitWidth>
          </field>
          <field>
            <name>BR8</name>
            <bitOffset>24</bitOffset>
            <bitWidth>1</bitWidth>
          </field>
          <field>
            <name>BR9</name>
            <bitOffset>25</bitOffset>
            <bitWidth>1</bitWidth>
          </field>
          <field>
            <name>BR10</name>
            <bitOffset>26</bitOffset>
            <bitWidth>1</bitWidth>
          </field>
          <field>
            <name>BR11</name>
            <bitOffset>27</bitOffset>
            <bitWidth>1</bitWidth>
          </field>
          <field>
            <name>BR12</name>
            <bitOffset>28</bitOffset>
            <bitWidth>1</bitWidth>
          </field>
          <field>
            <name>BR13</name>
            <bitOffset>29</bitOffset>
            <bitWidth>1</bitWidth>
          </field>
          <field>
            <name>BR14</name>
            <bitOffset>30</bitOffset>
            <bitWidth>1</bitWidth>
          </field>
          <field>
            <name>BR15</name>
            <bitOffset>31</bitOffset>
            <bitWidth>1</bitWidth>
          </field>
        </fields>
      </register>
      <register>
        <name>LCKR</name>
        <addressOffset>0x1c</addressOffset>
        <size>0x20</size>
        <fields>
          <field>
            <name>LCK0</name>
            <bitOffset>0</bitOffset>
            <bitWidth>1</bitWidth>
          </field>
          <field>
            <name>LCK1</name>
            <bitOffset>1</bitOffset>
            <bitWidth>1</bitWidth>
          </field>
          <field>
            <name>LCK2</name>
            <bitOffset>2</bitOffset>
            <bitWidth>1</bitWidth>
          </field>
          <field>
            <name>LCK3</name>
            <bitOffset>3</bitOffset>
            <bitWidth>1</bitWidth>
          </field>
          <field>
            <name>LCK4</name>
            <bitOffset>4</bitOffset>
            <bitWidth>1</bitWidth>
          </field>
          <field>
            <name>LCK5</name>
            <bitOffset>5</bitOffset>
            <bitWidth>1</bitWidth>
          </field>
          <field>
            <name>LCK6</name>
            <bitOffset>6</bitOffset>
            <bitWidth>1</bitWidth>
          </field>
          <field>
            <name>LCK7</name>
            <bitOffset>7</bitOffset>
            <bitWidth>1</bitWidth>
          </field>
          <field>
            <name>LCK8</name>
            <bitOffset>8</bitOffset>
            <bitWidth>1</bitWidth>
          </field>
          <field>
            <name>LCK9</name>
            <bitOffset>9</bitOffset>
            <bitWidth>1</bitWidth>
          </field>
          <field>
            <name>LCK10</name>
            <bitOffset>10</bitOffset>
            <bitWidth>1</bitWidth>
          </field>
          <field>
            <name>LCK11</name>
            <bitOffset>11</bitOffset>
            <bitWidth>1</bitWidth>
          </field>
          <field>
            <name>LCK12</name>
            <bitOffset>12</bitOffset>
            <bitWidth>1</bitWidth>
          </field>
          <field>
            <name>LCK13</name>
            <bitOffset>13</bitOffset>
            <bitWidth>1</bitWidth>
          </field>
          <field>
            <name>LCK14</name>
            <bitOffset>14</bitOffset>
            <bitWidth>1</bitWidth>
          </field>
          <field>
            <name>LCK15</name>
            <bitOffset>15</bitOffset>
            <bitWidth>1</bitWidth>
          </field>
          <field>
            <name>LCKK</name>
            <bitOffset>16</bitOffset>
            <bitWidth>1</bitWidth>
          </field>
        </fields>
      </register>
      <register>
        <name>AFR.0</name>
        <addressOffset>0x20</addressOffset>
        <size>0x20</size>
        <fields>
          <field>
            <name>AFSEL0</name>
            <bitOffset>0</bitOffset>
            <bitWidth>4</bitWidth>
          </field>
          <field>
            <name>AFSEL1</name>
            <bitOffset>4</bitOffset>
            <bitWidth>4</bitWidth>
          </field>
          <field>
            <name>AFSEL2</name>
            <bitOffset>8</bitOffset>
            <bitWidth>4</bitWidth>
          </field>
          <field>
            <name>AFSEL3</name>
            <bitOffset>12</bitOffset>
            <bitWidth>4</bitWidth>
          </field>
          <field>
            <name>AFSEL4</name>
            <bitOffset>16</bitOffset>
            <bitWidth>4</bitWidth>
          </field>
          <field>
            <name>AFSEL5</name>
            <bitOffset>20</bitOffset>
            <bitWidth>4</bitWidth>
          </field>
          <field>
            <name>AFSEL6</name>
            <bitOffset>24</bitOffset>
            <bitWidth>4</bitWidth>
          </field>
          <field>
            <name>AFSEL7</name>
            <bitOffset>28</bitOffset>
            <bitWidth>4</bitWidth>
          </field>
        </fields>
      </register>
      <register>
        <name>AFR.1</name>
        <addressOffset>0x24</addressOffset>
        <size>0x20</size>
        <fields>
          <field>
            <name>AFSEL8</name>
            <bitOffset>0</bitOffset>
            <bitWidth>4</bitWidth>
          </field>
          <field>
            <name>AFSEL9</name>
            <bitOffset>4</bitOffset>
            <bitWidth>4</bitWidth>
          </field>
          <field>
            <name>AFSEL10</name>
            <bitOffset>8</bitOffset>
            <bitWidth>4</bitWidth>
          </field>
          <field>
            <name>AFSEL11</name>
            <bitOffset>12</bitOffset>
            <bitWidth>4</bitWidth>
          </field>
          <field>
            <name>AFSEL12</name>
            <bitOffset>16</bitOffset>
            <bitWidth>4</bitWidth>
          </field>
          <field>
            <name>AFSEL13</name>
            <bitOffset>20</bitOffset>
            <bitWidth>4</bitWidth>
          </field>
          <field>
            <name>AFSEL14</name>
            <bitOffset>24</bitOffset>
            <bitWidth>4</bitWidth>
          </field>
          <field>
            <name>AFSEL15</name>
            <bitOffset>28</bitOffset>
            <bitWidth>4</bitWidth>
          </field>
        </fields>
      </register>
      <register>
        <name>BRR</name>
        <addressOffset>0x28</addressOffset>
        <size>0x20</size>
        <fields>
          <field>
            <name>BR0</name>
            <bitOffset>0</bitOffset>
            <bitWidth>1</bitWidth>
          </field>
          <field>
            <name>BR1</name>
            <bitOffset>1</bitOffset>
            <bitWidth>1</bitWidth>
          </field>
          <field>
            <name>BR2</name>
            <bitOffset>2</bitOffset>
            <bitWidth>1</bitWidth>
          </field>
          <field>
            <name>BR3</name>
            <bitOffset>3</bitOffset>
            <bitWidth>1</bitWidth>
          </field>
          <field>
            <name>BR4</name>
            <bitOffset>4</bitOffset>
            <bitWidth>1</bitWidth>
          </field>
          <field>
            <name>BR5</name>
            <bitOffset>5</bitOffset>
            <bitWidth>1</bitWidth>
          </field>
          <field>
            <name>BR6</name>
            <bitOffset>6</bitOffset>
            <bitWidth>1</bitWidth>
          </field>
          <field>
            <name>BR7</name>
            <bitOffset>7</bitOffset>
            <bitWidth>1</bitWidth>
          </field>
          <field>
            <name>BR8</name>
            <bitOffset>8</bitOffset>
            <bitWidth>1</bitWidth>
          </field>
          <field>
            <name>BR9</name>
            <bitOffset>9</bitOffset>
            <bitWidth>1</bitWidth>
          </field>
          <field>
            <name>BR10</name>
            <bitOffset>10</bitOffset>
            <bitWidth>1</bitWidth>
          </field>
          <field>
            <name>BR11</name>
            <bitOffset>11</bitOffset>
            <bitWidth>1</bitWidth>
          </field>
          <field>
            <name>BR12</name>
            <bitOffset>12</bitOffset>
            <bitWidth>1</bitWidth>
          </field>
          <field>
            <name>BR13</name>
            <bitOffset>13</bitOffset>
            <bitWidth>1</bitWidth>
          </field>
          <field>
            <name>BR14</name>
            <bitOffset>14</bitOffset>
            <bitWidth>1</bitWidth>
          </field>
          <field>
            <name>BR15</name>
            <bitOffset>15</bitOffset>
            <bitWidth>1</bitWidth>
          </field>
        </fields>
      </register>
    </peripheral>
    <peripheral>
      <name>GPIOH</name>
      <baseAddress>0x48001c00</baseAddress>
      <register>
        <name>MODER</name>
        <addressOffset>0x0</addressOffset>
        <size>0x20</size>
        <fields>
          <field>
            <name>MODE0</name>
            <bitOffset>0</bitOffset>
            <bitWidth>2</bitWidth>
          </field>
          <field>
            <name>MODE1</name>
            <bitOffset>2</bitOffset>
            <bitWidth>2</bitWidth>
          </field>
          <field>
            <name>MODE2</name>
            <bitOffset>4</bitOffset>
            <bitWidth>2</bitWidth>
          </field>
          <field>
            <name>MODE3</name>
            <bitOffset>6</bitOffset>
            <bitWidth>2</bitWidth>
          </field>
          <field>
            <name>MODE4</name>
            <bitOffset>8</bitOffset>
            <bitWidth>2</bitWidth>
          </field>
          <field>
            <name>MODE5</name>
            <bitOffset>10</bitOffset>
            <bitWidth>2</bitWidth>
          </field>
          <field>
            <name>MODE6</name>
            <bitOffset>12</bitOffset>
            <bitWidth>2</bitWidth>
          </field>
          <field>
            <name>MODE7</name>
            <bitOffset>14</bitOffset>
            <bitWidth>2</bitWidth>
          </field>
          <field>
            <name>MODE8</name>
            <bitOffset>16</bitOffset>
            <bitWidth>2</bitWidth>
          </field>
          <field>
            <name>MODE9</name>
            <bitOffset>18</bitOffset>
            <bitWidth>2</bitWidth>
          </field>
          <field>
            <name>MODE10</name>
            <bitOffset>20</bitOffset>
            <bitWidth>2</bitWidth>
          </field>
          <field>
            <name>MODE11</name>
            <bitOffset>22</bitOffset>
            <bitWidth>2</bitWidth>
          </field>
          <field>
            <name>MODE12</name>
            <bitOffset>24</bitOffset>
            <bitWidth>2</bitWidth>
          </field>
          <field>
            <name>MODE13</name>
            <bitOffset>26</bitOffset>
            <bitWidth>2</bitWidth>
          </field>
          <field>
            <name>MODE14</name>
            <bitOffset>28</bitOffset>
            <bitWidth>2</bitWidth>
          </field>
          <field>
            <name>MODE15</name>
            <bitOffset>30</bitOffset>
            <bitWidth>2</bitWidth>
          </field>
        </fields>
      </register>
      <register>
        <name>OTYPER</name>
        <addressOffset>0x4</addressOffset>
        <size>0x20</size>
        <fields>
          <field>
            <name>OT0</name>
            <bitOffset>0</bitOffset>
            <bitWidth>1</bitWidth>
          </field>
          <field>
            <name>OT1</name>
            <bitOffset>1</bitOffset>
            <bitWidth>1</bitWidth>
          </field>
          <field>
            <name>OT2</name>
            <bitOffset>2</bitOffset>
            <bitWidth>1</bitWidth>
          </field>
          <field>
            <name>OT3</name>
            <bitOffset>3</bitOffset>
            <bitWidth>1</bitWidth>
          </field>
          <field>
            <name>OT4</name>
            <bitOffset>4</bitOffset>
            <bitWidth>1</bitWidth>
          </field>
          <field>
            <name>OT5</name>
            <bitOffset>5</bitOffset>
            <bitWidth>1</bitWidth>
          </field>
          <field>
            <name>OT6</name>
            <bitOffset>6</bitOffset>
            <bitWidth>1</bitWidth>
          </field>
          <field>
            <name>OT7</name>
            <bitOffset>7</bitOffset>
            <bitWidth>1</bitWidth>
          </field>
          <field>
            <name>OT8</name>
            <bitOffset>8</bitOffset>
            <bitWidth>1</bitWidth>
          </field>
          <field>
            <name>OT9</name>
            <bitOffset>9</bitOffset>
            <bitWidth>1</bitWidth>
          </field>
          <field>
            <name>OT10</name>
            <bitOffset>10</bitOffset>
            <bitWidth>1</bitWidth>
          </field>
          <field>
            <name>OT11</name>
            <bitOffset>11</bitOffset>
            <bitWidth>1</bitWidth>
          </field>
          <field>
            <name>OT12</name>
            <bitOffset>12</bitOffset>
            <bitWidth>1</bitWidth>
          </field>
          <field>
            <name>OT13</name>
            <bitOffset>13</bitOffset>
            <bitWidth>1</bitWidth>
          </field>
          <field>
            <name>OT14</name>
            <bitOffset>14</bitOffset>
            <bitWidth>1</bitWidth>
          </field>
          <field>
            <name>OT15</name>
            <bitOffset>15</bitOffset>
            <bitWidth>1</bitWidth>
          </field>
        </fields>
      </register>
      <register>
        <name>OSPEEDR</name>
        <addressOffset>0x8</addressOffset>
        <size>0x20</size>
        <fields>
          <field>
            <name>OSPEED0</name>
            <bitOffset>0</bitOffset>
            <bitWidth>2</bitWidth>
          </field>
          <field>
            <name>OSPEED1</name>
            <bitOffset>2</bitOffset>
            <bitWidth>2</bitWidth>
          </field>
          <field>
            <name>OSPEED2</name>
            <bitOffset>4</bitOffset>
            <bitWidth>2</bitWidth>
          </field>
          <field>
            <name>OSPEED3</name>
            <bitOffset>6</bitOffset>
            <bitWidth>2</bitWidth>
          </field>
          <field>
            <name>OSPEED4</name>
            <bitOffset>8</bitOffset>
            <bitWidth>2</bitWidth>
          </field>
          <field>
            <name>OSPEED5</name>
            <bitOffset>10</bitOffset>
            <bitWidth>2</bitWidth>
          </field>
          <field>
            <name>OSPEED6</name>
            <bitOffset>12</bitOffset>
            <bitWidth>2</bitWidth>
          </field>
          <field>
            <name>OSPEED7</name>
            <bitOffset>14</bitOffset>
            <bitWidth>2</bitWidth>
          </field>
          <field>
            <name>OSPEED8</name>
            <bitOffset>16</bitOffset>
            <bitWidth>2</bitWidth>
          </field>
          <field>
            <name>OSPEED9</name>
            <bitOffset>18</bitOffset>
            <bitWidth>2</bitWidth>
          </field>
          <field>
            <name>OSPEED10</name>
            <bitOffset>20</bitOffset>
            <bitWidth>2</bitWidth>
          </field>
          <field>
            <name>OSPEED11</name>
            <bitOffset>22</bitOffset>
            <bitWidth>2</bitWidth>
          </field>
          <field>
            <name>OSPEED12</name>
            <bitOffset>24</bitOffset>
            <bitWidth>2</bitWidth>
          </field>
          <field>
            <name>OSPEED13</name>
            <bitOffset>26</bitOffset>
            <bitWidth>2</bitWidth>
          </field>
          <field>
            <name>OSPEED14</name>
            <bitOffset>28</bitOffset>
            <bitWidth>2</bitWidth>
          </field>
          <field>
            <name>OSPEED15</name>
            <bitOffset>30</bitOffset>
            <bitWidth>2</bitWidth>
          </field>
        </fields>
      </register>
      <register>
        <name>PUPDR</name>
        <addressOffset>0xc</addressOffset>
        <size>0x20</size>
        <fields>
          <field>
            <name>PUPD0</name>
            <bitOffset>0</bitOffset>
            <bitWidth>2</bitWidth>
          </field>
          <field>
            <name>PUPD1</name>
            <bitOffset>2</bitOffset>
            <bitWidth>2</bitWidth>
          </field>
          <field>
            <name>PUPD2</name>
            <bitOffset>4</bitOffset>
            <bitWidth>2</bitWidth>
          </field>
          <field>
            <name>PUPD3</name>
            <bitOffset>6</bitOffset>
            <bitWidth>2</bitWidth>
          </field>
          <field>
            <name>PUPD4</name>
            <bitOffset>8</bitOffset>
            <bitWidth>2</bitWidth>
          </field>
          <field>
            <name>PUPD5</name>
            <bitOffset>10</bitOffset>
            <bitWidth>2</bitWidth>
          </field>
          <field>
            <name>PUPD6</name>
            <bitOffset>12</bitOffset>
            <bitWidth>2</bitWidth>
          </field>
          <field>
            <name>PUPD7</name>
            <bitOffset>14</bitOffset>
            <bitWidth>2</bitWidth>
          </field>
          <field>
            <name>PUPD8</name>
            <bitOffset>16</bitOffset>
            <bitWidth>2</bitWidth>
          </field>
          <field>
            <name>PUPD9</name>
            <bitOffset>18</bitOffset>
            <bitWidth>2</bitWidth>
          </field>
          <field>
            <name>PUPD10</name>
            <bitOffset>20</bitOffset>
            <bitWidth>2</bitWidth>
          </field>
          <field>
            <name>PUPD11</name>
            <bitOffset>22</bitOffset>
            <bitWidth>2</bitWidth>
          </field>
          <field>
            <name>PUPD12</name>
            <bitOffset>24</bitOffset>
            <bitWidth>2</bitWidth>
          </field>
          <field>
            <name>PUPD13</name>
            <bitOffset>26</bitOffset>
            <bitWidth>2</bitWidth>
          </field>
          <field>
            <name>PUPD14</name>
            <bitOffset>28</bitOffset>
            <bitWidth>2</bitWidth>
          </field>
          <field>
            <name>PUPD15</name>
            <bitOffset>30</bitOffset>
            <bitWidth>2</bitWidth>
          </field>
        </fields>
      </register>
      <register>
        <name>IDR</name>
        <addressOffset>0x10</addressOffset>
        <size>0x20</size>
        <fields>
          <field>
            <name>ID0</name>
            <bitOffset>0</bitOffset>
            <bitWidth>1</bitWidth>
          </field>
          <field>
            <name>ID1</name>
            <bitOffset>1</bitOffset>
            <bitWidth>1</bitWidth>
          </field>
          <field>
            <name>ID2</name>
            <bitOffset>2</bitOffset>
            <bitWidth>1</bitWidth>
          </field>
          <field>
            <name>ID3</name>
            <bitOffset>3</bitOffset>
            <bitWidth>1</bitWidth>
          </field>
          <field>
            <name>ID4</name>
            <bitOffset>4</bitOffset>
            <bitWidth>1</bitWidth>
          </field>
          <field>
            <name>ID5</name>
            <bitOffset>5</bitOffset>
            <bitWidth>1</bitWidth>
          </field>
          <field>
            <name>ID6</name>
            <bitOffset>6</bitOffset>
            <bitWidth>1</bitWidth>
          </field>
          <field>
            <name>ID7</name>
            <bitOffset>7</bitOffset>
            <bitWidth>1</bitWidth>
          </field>
          <field>
            <name>ID8</name>
            <bitOffset>8</bitOffset>
            <bitWidth>1</bitWidth>
          </field>
          <field>
            <name>ID9</name>
            <bitOffset>9</bitOffset>
            <bitWidth>1</bitWidth>
          </field>
          <field>
            <name>ID10</name>
            <bitOffset>10</bitOffset>
            <bitWidth>1</bitWidth>
          </field>
          <field>
            <name>ID11</name>
            <bitOffset>11</bitOffset>
            <bitWidth>1</bitWidth>
          </field>
          <field>
            <name>ID12</name>
            <bitOffset>12</bitOffset>
            <bitWidth>1</bitWidth>
          </field>
          <field>
            <name>ID13</name>
            <bitOffset>13</bitOffset>
            <bitWidth>1</bitWidth>
          </field>
          <field>
            <name>ID14</name>
            <bitOffset>14</bitOffset>
            <bitWidth>1</bitWidth>
          </field>
          <field>
            <name>ID15</name>
            <bitOffset>15</bitOffset>
            <bitWidth>1</bitWidth>
          </field>
        </fields>
      </register>
      <register>
        <name>ODR</name>
        <addressOffset>0x14</addressOffset>
        <size>0x20</size>
        <fields>
          <field>
            <name>OD0</name>
            <bitOffset>0</bitOffset>
            <bitWidth>1</bitWidth>
          </field>
          <field>
            <name>OD1</name>
            <bitOffset>1</bitOffset>
            <bitWidth>1</bitWidth>
          </field>
          <field>
            <name>OD2</name>
            <bitOffset>2</bitOffset>
            <bitWidth>1</bitWidth>
          </field>
          <field>
            <name>OD3</name>
            <bitOffset>3</bitOffset>
            <bitWidth>1</bitWidth>
          </field>
          <field>
            <name>OD4</name>
            <bitOffset>4</bitOffset>
            <bitWidth>1</bitWidth>
          </field>
          <field>
            <name>OD5</name>
            <bitOffset>5</bitOffset>
            <bitWidth>1</bitWidth>
          </field>
          <field>
            <name>OD6</name>
            <bitOffset>6</bitOffset>
            <bitWidth>1</bitWidth>
          </field>
          <field>
            <name>OD7</name>
            <bitOffset>7</bitOffset>
            <bitWidth>1</bitWidth>
          </field>
          <field>
            <name>OD8</name>
            <bitOffset>8</bitOffset>
            <bitWidth>1</bitWidth>
          </field>
          <field>
            <name>OD9</name>
            <bitOffset>9</bitOffset>
            <bitWidth>1</bitWidth>
          </field>
          <field>
            <name>OD10</name>
            <bitOffset>10</bitOffset>
            <bitWidth>1</bitWidth>
          </field>
          <field>
            <name>OD11</name>
            <bitOffset>11</bitOffset>
            <bitWidth>1</bitWidth>
          </field>
          <field>
            <name>OD12</name>
            <bitOffset>12</bitOffset>
            <bitWidth>1</bitWidth>
          </field>
          <field>
            <name>OD13</name>
            <bitOffset>13</bitOffset>
            <bitWidth>1</bitWidth>
          </field>
          <field>
            <name>OD14</name>
            <bitOffset>14</bitOffset>
            <bitWidth>1</bitWidth>
          </field>
          <field>
            <name>OD15</name>
            <bitOffset>15</bitOffset>
            <bitWidth>1</bitWidth>
          </field>
        </fields>
      </register>
      <register>
        <name>BSRR</name>
        <addressOffset>0x18</addressOffset>
        <size>0x20</size>
        <fields>
          <field>
            <name>BS0</name>
            <bitOffset>0</bitOffset>
            <bitWidth>1</bitWidth>
          </field>
          <field>
            <name>BS1</name>
            <bitOffset>1</bitOffset>
            <bitWidth>1</bitWidth>
          </field>
          <field>
            <name>BS2</name>
            <bitOffset>2</bitOffset>
            <bitWidth>1</bitWidth>
          </field>
          <field>
            <name>BS3</name>
            <bitOffset>3</bitOffset>
            <bitWidth>1</bitWidth>
          </field>
          <field>
            <name>BS4</name>
            <bitOffset>4</bitOffset>
            <bitWidth>1</bitWidth>
          </field>
          <field>
            <name>BS5</name>
            <bitOffset>5</bitOffset>
            <bitWidth>1</bitWidth>
          </field>
          <field>
            <name>BS6</name>
            <bitOffset>6</bitOffset>
            <bitWidth>1</bitWidth>
          </field>
          <field>
            <name>BS7</name>
            <bitOffset>7</bitOffset>
            <bitWidth>1</bitWidth>
          </field>
          <field>
            <name>BS8</name>
            <bitOffset>8</bitOffset>
            <bitWidth>1</bitWidth>
          </field>
          <field>
            <name>BS9</name>
            <bitOffset>9</bitOffset>
            <bitWidth>1</bitWidth>
          </field>
          <field>
            <name>BS10</name>
            <bitOffset>10</bitOffset>
            <bitWidth>1</bitWidth>
          </field>
          <field>
            <name>BS11</name>
            <bitOffset>11</bitOffset>
            <bitWidth>1</bitWidth>
          </field>
          <field>
            <name>BS12</name>
            <bitOffset>12</bitOffset>
            <bitWidth>1</bitWidth>
          </field>
          <field>
            <name>BS13</name>
            <bitOffset>13</bitOffset>
            <bitWidth>1</bitWidth>
          </field>
          <field>
            <name>BS14</name>
            <bitOffset>14</bitOffset>
            <bitWidth>1</bitWidth>
          </field>
          <field>
            <name>BS15</name>
            <bitOffset>15</bitOffset>
            <bitWidth>1</bitWidth>
          </field>
          <field>
            <name>BR0</name>
            <bitOffset>16</bitOffset>
            <bitWidth>1</bitWidth>
          </field>
          <field>
            <name>BR1</name>
            <bitOffset>17</bitOffset>
            <bitWidth>1</bitWidth>
          </field>
          <field>
            <name>BR2</name>
            <bitOffset>18</bitOffset>
            <bitWidth>1</bitWidth>
          </field>
          <field>
            <name>BR3</name>
            <bitOffset>19</bitOffset>
            <bitWidth>1</bitWidth>
          </field>
          <field>
            <name>BR4</name>
            <bitOffset>20</bitOffset>
            <bitWidth>1</bitWidth>
          </field>
          <field>
            <name>BR5</name>
            <bitOffset>21</bitOffset>
            <bitWidth>1</bitWidth>
          </field>
          <field>
            <name>BR6</name>
            <bitOffset>22</bitOffset>
            <bitWidth>1</bitWidth>
          </field>
          <field>
            <name>BR7</name>
            <bitOffset>23</bitOffset>
            <bitWidth>1</bitWidth>
          </field>
          <field>
            <name>BR8</name>
            <bitOffset>24</bitOffset>
            <bitWidth>1</bitWidth>
          </field>
          <field>
            <name>BR9</name>
            <bitOffset>25</bitOffset>
            <bitWidth>1</bitWidth>
          </field>
          <field>
            <name>BR10</name>
            <bitOffset>26</bitOffset>
            <bitWidth>1</bitWidth>
          </field>
          <field>
            <name>BR11</name>
            <bitOffset>27</bitOffset>
            <bitWidth>1</bitWidth>
          </field>
          <field>
            <name>BR12</name>
            <bitOffset>28</bitOffset>
            <bitWidth>1</bitWidth>
          </field>
          <field>
            <name>BR13</name>
            <bitOffset>29</bitOffset>
            <bitWidth>1</bitWidth>
          </field>
          <field>
            <name>BR14</name>
            <bitOffset>30</bitOffset>
            <bitWidth>1</bitWidth>
          </field>
          <field>
            <name>BR15</name>
            <bitOffset>31</bitOffset>
            <bitWidth>1</bitWidth>
          </field>
        </fields>
      </register>
      <register>
        <name>LCKR</name>
        <addressOffset>0x1c</addressOffset>
        <size>0x20</size>
        <fields>
          <field>
            <name>LCK0</name>
            <bitOffset>0</bitOffset>
            <bitWidth>1</bitWidth>
          </field>
          <field>
            <name>LCK1</name>
            <bitOffset>1</bitOffset>
            <bitWidth>1</bitWidth>
          </field>
          <field>
            <name>LCK2</name>
            <bitOffset>2</bitOffset>
            <bitWidth>1</bitWidth>
          </field>
          <field>
            <name>LCK3</name>
            <bitOffset>3</bitOffset>
            <bitWidth>1</bitWidth>
          </field>
          <field>
            <name>LCK4</name>
            <bitOffset>4</bitOffset>
            <bitWidth>1</bitWidth>
          </field>
          <field>
            <name>LCK5</name>
            <bitOffset>5</bitOffset>
            <bitWidth>1</bitWidth>
          </field>
          <field>
            <name>LCK6</name>
            <bitOffset>6</bitOffset>
            <bitWidth>1</bitWidth>
          </field>
          <field>
            <name>LCK7</name>
            <bitOffset>7</bitOffset>
            <bitWidth>1</bitWidth>
          </field>
          <field>
            <name>LCK8</name>
            <bitOffset>8</bitOffset>
            <bitWidth>1</bitWidth>
          </field>
          <field>
            <name>LCK9</name>
            <bitOffset>9</bitOffset>
            <bitWidth>1</bitWidth>
          </field>
          <field>
            <name>LCK10</name>
            <bitOffset>10</bitOffset>
            <bitWidth>1</bitWidth>
          </field>
          <field>
            <name>LCK11</name>
            <bitOffset>11</bitOffset>
            <bitWidth>1</bitWidth>
          </field>
          <field>
            <name>LCK12</name>
            <bitOffset>12</bitOffset>
            <bitWidth>1</bitWidth>
          </field>
          <field>
            <name>LCK13</name>
            <bitOffset>13</bitOffset>
            <bitWidth>1</bitWidth>
          </field>
          <field>
            <name>LCK14</name>
            <bitOffset>14</bitOffset>
            <bitWidth>1</bitWidth>
          </field>
          <field>
            <name>LCK15</name>
            <bitOffset>15</bitOffset>
            <bitWidth>1</bitWidth>
          </field>
          <field>
            <name>LCKK</name>
            <bitOffset>16</bitOffset>
            <bitWidth>1</bitWidth>
          </field>
        </fields>
      </register>
      <register>
        <name>AFR.0</name>
        <addressOffset>0x20</addressOffset>
        <size>0x20</size>
        <fields>
          <field>
            <name>AFSEL0</name>
            <bitOffset>0</bitOffset>
            <bitWidth>4</bitWidth>
          </field>
          <field>
            <name>AFSEL1</name>
            <bitOffset>4</bitOffset>
            <bitWidth>4</bitWidth>
          </field>
          <field>
            <name>AFSEL2</name>
            <bitOffset>8</bitOffset>
            <bitWidth>4</bitWidth>
          </field>
          <field>
            <name>AFSEL3</name>
            <bitOffset>12</bitOffset>
            <bitWidth>4</bitWidth>
          </field>
          <field>
            <name>AFSEL4</name>
            <bitOffset>16</bitOffset>
            <bitWidth>4</bitWidth>
          </field>
          <field>
            <name>AFSEL5</name>
            <bitOffset>20</bitOffset>
            <bitWidth>4</bitWidth>
          </field>
          <field>
            <name>AFSEL6</name>
            <bitOffset>24</bitOffset>
            <bitWidth>4</bitWidth>
          </field>
          <field>
            <name>AFSEL7</name>
            <bitOffset>28</bitOffset>
            <bitWidth>4</bitWidth>
          </field>
        </fields>
      </register>
      <register>
        <name>AFR.1</name>
        <addressOffset>0x24</addressOffset>
        <size>0x20</size>
        <fields>
          <field>
            <name>AFSEL8</name>
            <bitOffset>0</bitOffset>
            <bitWidth>4</bitWidth>
          </field>
          <field>
            <name>AFSEL9</name>
            <bitOffset>4</bitOffset>
            <bitWidth>4</bitWidth>
          </field>
          <field>
            <name>AFSEL10</name>
            <bitOffset>8</bitOffset>
            <bitWidth>4</bitWidth>
          </field>
          <field>
            <name>AFSEL11</name>
            <bitOffset>12</bitOffset>
            <bitWidth>4</bitWidth>
          </field>
          <field>
            <name>AFSEL12</name>
            <bitOffset>16</bitOffset>
            <bitWidth>4</bitWidth>
          </field>
          <field>
            <name>AFSEL13</name>
            <bitOffset>20</bitOffset>
            <bitWidth>4</bitWidth>
          </field>
          <field>
            <name>AFSEL14</name>
            <bitOffset>24</bitOffset>
            <bitWidth>4</bitWidth>
          </field>
          <field>
            <name>AFSEL15</name>
            <bitOffset>28</bitOffset>
            <bitWidth>4</bitWidth>
          </field>
        </fields>
      </register>
      <register>
        <name>BRR</name>
        <addressOffset>0x28</addressOffset>
        <size>0x20</size>
        <fields>
          <field>
            <name>BR0</name>
            <bitOffset>0</bitOffset>
            <bitWidth>1</bitWidth>
          </field>
          <field>
            <name>BR1</name>
            <bitOffset>1</bitOffset>
            <bitWidth>1</bitWidth>
          </field>
          <field>
            <name>BR2</name>
            <bitOffset>2</bitOffset>
            <bitWidth>1</bitWidth>
          </field>
          <field>
            <name>BR3</name>
            <bitOffset>3</bitOffset>
            <bitWidth>1</bitWidth>
          </field>
          <field>
            <name>BR4</name>
            <bitOffset>4</bitOffset>
            <bitWidth>1</bitWidth>
          </field>
          <field>
            <name>BR5</name>
            <bitOffset>5</bitOffset>
            <bitWidth>1</bitWidth>
          </field>
          <field>
            <name>BR6</name>
            <bitOffset>6</bitOffset>
            <bitWidth>1</bitWidth>
          </field>
          <field>
            <name>BR7</name>
            <bitOffset>7</bitOffset>
            <bitWidth>1</bitWidth>
          </field>
          <field>
            <name>BR8</name>
            <bitOffset>8</bitOffset>
            <bitWidth>1</bitWidth>
          </field>
          <field>
            <name>BR9</name>
            <bitOffset>9</bitOffset>
            <bitWidth>1</bitWidth>
          </field>
          <field>
            <name>BR10</name>
            <bitOffset>10</bitOffset>
            <bitWidth>1</bitWidth>
          </field>
          <field>
            <name>BR11</name>
            <bitOffset>11</bitOffset>
            <bitWidth>1</bitWidth>
          </field>
          <field>
            <name>BR12</name>
            <bitOffset>12</bitOffset>
            <bitWidth>1</bitWidth>
          </field>
          <field>
            <name>BR13</name>
            <bitOffset>13</bitOffset>
            <bitWidth>1</bitWidth>
          </field>
          <field>
            <name>BR14</name>
            <bitOffset>14</bitOffset>
            <bitWidth>1</bitWidth>
          </field>
          <field>
            <name>BR15</name>
            <bitOffset>15</bitOffset>
            <bitWidth>1</bitWidth>
          </field>
        </fields>
      </register>
    </peripheral>
    <peripheral>
      <name>GPIOI</name>
      <baseAddress>0x48002000</baseAddress>
      <register>
        <name>MODER</name>
        <addressOffset>0x0</addressOffset>
        <size>0x20</size>
        <fields>
          <field>
            <name>MODE0</name>
            <bitOffset>0</bitOffset>
            <bitWidth>2</bitWidth>
          </field>
          <field>
            <name>MODE1</name>
            <bitOffset>2</bitOffset>
            <bitWidth>2</bitWidth>
          </field>
          <field>
            <name>MODE2</name>
            <bitOffset>4</bitOffset>
            <bitWidth>2</bitWidth>
          </field>
          <field>
            <name>MODE3</name>
            <bitOffset>6</bitOffset>
            <bitWidth>2</bitWidth>
          </field>
          <field>
            <name>MODE4</name>
            <bitOffset>8</bitOffset>
            <bitWidth>2</bitWidth>
          </field>
          <field>
            <name>MODE5</name>
            <bitOffset>10</bitOffset>
            <bitWidth>2</bitWidth>
          </field>
          <field>
            <name>MODE6</name>
            <bitOffset>12</bitOffset>
            <bitWidth>2</bitWidth>
          </field>
          <field>
            <name>MODE7</name>
            <bitOffset>14</bitOffset>
            <bitWidth>2</bitWidth>
          </field>
          <field>
            <name>MODE8</name>
            <bitOffset>16</bitOffset>
            <bitWidth>2</bitWidth>
          </field>
          <field>
            <name>MODE9</name>
            <bitOffset>18</bitOffset>
            <bitWidth>2</bitWidth>
          </field>
          <field>
            <name>MODE10</name>
            <bitOffset>20</bitOffset>
            <bitWidth>2</bitWidth>
          </field>
          <field>
            <name>MODE11</name>
            <bitOffset>22</bitOffset>
            <bitWidth>2</bitWidth>
          </field>
          <field>
            <name>MODE12</name>
            <bitOffset>24</bitOffset>
            <bitWidth>2</bitWidth>
          </field>
          <field>
            <name>MODE13</name>
            <bitOffset>26</bitOffset>
            <bitWidth>2</bitWidth>
          </field>
          <field>
            <name>MODE14</name>
            <bitOffset>28</bitOffset>
            <bitWidth>2</bitWidth>
          </field>
          <field>
            <name>MODE15</name>
            <bitOffset>30</bitOffset>
            <bitWidth>2</bitWidth>
          </field>
        </fields>
      </register>
      <register>
        <name>OTYPER</name>
        <addressOffset>0x4</addressOffset>
        <size>0x20</size>
        <fields>
          <field>
            <name>OT0</name>
            <bitOffset>0</bitOffset>
            <bitWidth>1</bitWidth>
          </field>
          <field>
            <name>OT1</name>
            <bitOffset>1</bitOffset>
            <bitWidth>1</bitWidth>
          </field>
          <field>
            <name>OT2</name>
            <bitOffset>2</bitOffset>
            <bitWidth>1</bitWidth>
          </field>
          <field>
            <name>OT3</name>
            <bitOffset>3</bitOffset>
            <bitWidth>1</bitWidth>
          </field>
          <field>
            <name>OT4</name>
            <bitOffset>4</bitOffset>
            <bitWidth>1</bitWidth>
          </field>
          <field>
            <name>OT5</name>
            <bitOffset>5</bitOffset>
            <bitWidth>1</bitWidth>
          </field>
          <field>
            <name>OT6</name>
            <bitOffset>6</bitOffset>
            <bitWidth>1</bitWidth>
          </field>
          <field>
            <name>OT7</name>
            <bitOffset>7</bitOffset>
            <bitWidth>1</bitWidth>
          </field>
          <field>
            <name>OT8</name>
            <bitOffset>8</bitOffset>
            <bitWidth>1</bitWidth>
          </field>
          <field>
            <name>OT9</name>
            <bitOffset>9</bitOffset>
            <bitWidth>1</bitWidth>
          </field>
          <field>
            <name>OT10</name>
            <bitOffset>10</bitOffset>
            <bitWidth>1</bitWidth>
          </field>
          <field>
            <name>OT11</name>
            <bitOffset>11</bitOffset>
            <bitWidth>1</bitWidth>
          </field>
          <field>
            <name>OT12</name>
            <bitOffset>12</bitOffset>
            <bitWidth>1</bitWidth>
          </field>
          <field>
            <name>OT13</name>
            <bitOffset>13</bitOffset>
            <bitWidth>1</bitWidth>
          </field>
          <field>
            <name>OT14</name>
            <bitOffset>14</bitOffset>
            <bitWidth>1</bitWidth>
          </field>
          <field>
            <name>OT15</name>
            <bitOffset>15</bitOffset>
            <bitWidth>1</bitWidth>
          </field>
        </fields>
      </register>
      <register>
        <name>OSPEEDR</name>
        <addressOffset>0x8</addressOffset>
        <size>0x20</size>
        <fields>
          <field>
            <name>OSPEED0</name>
            <bitOffset>0</bitOffset>
            <bitWidth>2</bitWidth>
          </field>
          <field>
            <name>OSPEED1</name>
            <bitOffset>2</bitOffset>
            <bitWidth>2</bitWidth>
          </field>
          <field>
            <name>OSPEED2</name>
            <bitOffset>4</bitOffset>
            <bitWidth>2</bitWidth>
          </field>
          <field>
            <name>OSPEED3</name>
            <bitOffset>6</bitOffset>
            <bitWidth>2</bitWidth>
          </field>
          <field>
            <name>OSPEED4</name>
            <bitOffset>8</bitOffset>
            <bitWidth>2</bitWidth>
          </field>
          <field>
            <name>OSPEED5</name>
            <bitOffset>10</bitOffset>
            <bitWidth>2</bitWidth>
          </field>
          <field>
            <name>OSPEED6</name>
            <bitOffset>12</bitOffset>
            <bitWidth>2</bitWidth>
          </field>
          <field>
            <name>OSPEED7</name>
            <bitOffset>14</bitOffset>
            <bitWidth>2</bitWidth>
          </field>
          <field>
            <name>OSPEED8</name>
            <bitOffset>16</bitOffset>
            <bitWidth>2</bitWidth>
          </field>
          <field>
            <name>OSPEED9</name>
            <bitOffset>18</bitOffset>
            <bitWidth>2</bitWidth>
          </field>
          <field>
            <name>OSPEED10</name>
            <bitOffset>20</bitOffset>
            <bitWidth>2</bitWidth>
          </field>
          <field>
            <name>OSPEED11</name>
            <bitOffset>22</bitOffset>
            <bitWidth>2</bitWidth>
          </field>
          <field>
            <name>OSPEED12</name>
            <bitOffset>24</bitOffset>
            <bitWidth>2</bitWidth>
          </field>
          <field>
            <name>OSPEED13</name>
            <bitOffset>26</bitOffset>
            <bitWidth>2</bitWidth>
          </field>
          <field>
            <name>OSPEED14</name>
            <bitOffset>28</bitOffset>
            <bitWidth>2</bitWidth>
          </field>
          <field>
            <name>OSPEED15</name>
            <bitOffset>30</bitOffset>
            <bitWidth>2</bitWidth>
          </field>
        </fields>
      </register>
      <register>
        <name>PUPDR</name>
        <addressOffset>0xc</addressOffset>
        <size>0x20</size>
        <fields>
          <field>
            <name>PUPD0</name>
            <bitOffset>0</bitOffset>
            <bitWidth>2</bitWidth>
          </field>
          <field>
            <name>PUPD1</name>
            <bitOffset>2</bitOffset>
            <bitWidth>2</bitWidth>
          </field>
          <field>
            <name>PUPD2</name>
            <bitOffset>4</bitOffset>
            <bitWidth>2</bitWidth>
          </field>
          <field>
            <name>PUPD3</name>
            <bitOffset>6</bitOffset>
            <bitWidth>2</bitWidth>
          </field>
          <field>
            <name>PUPD4</name>
            <bitOffset>8</bitOffset>
            <bitWidth>2</bitWidth>
          </field>
          <field>
            <name>PUPD5</name>
            <bitOffset>10</bitOffset>
            <bitWidth>2</bitWidth>
          </field>
          <field>
            <name>PUPD6</name>
            <bitOffset>12</bitOffset>
            <bitWidth>2</bitWidth>
          </field>
          <field>
            <name>PUPD7</name>
            <bitOffset>14</bitOffset>
            <bitWidth>2</bitWidth>
          </field>
          <field>
            <name>PUPD8</name>
            <bitOffset>16</bitOffset>
            <bitWidth>2</bitWidth>
          </field>
          <field>
            <name>PUPD9</name>
            <bitOffset>18</bitOffset>
            <bitWidth>2</bitWidth>
          </field>
          <field>
            <name>PUPD10</name>
            <bitOffset>20</bitOffset>
            <bitWidth>2</bitWidth>
          </field>
          <field>
            <name>PUPD11</name>
            <bitOffset>22</bitOffset>
            <bitWidth>2</bitWidth>
          </field>
          <field>
            <name>PUPD12</name>
            <bitOffset>24</bitOffset>
            <bitWidth>2</bitWidth>
          </field>
          <field>
            <name>PUPD13</name>
            <bitOffset>26</bitOffset>
            <bitWidth>2</bitWidth>
          </field>
          <field>
            <name>PUPD14</name>
            <bitOffset>28</bitOffset>
            <bitWidth>2</bitWidth>
          </field>
          <field>
            <name>PUPD15</name>
            <bitOffset>30</bitOffset>
            <bitWidth>2</bitWidth>
          </field>
        </fields>
      </register>
      <register>
        <name>IDR</name>
        <addressOffset>0x10</addressOffset>
        <size>0x20</size>
        <fields>
          <field>
            <name>ID0</name>
            <bitOffset>0</bitOffset>
            <bitWidth>1</bitWidth>
          </field>
          <field>
            <name>ID1</name>
            <bitOffset>1</bitOffset>
            <bitWidth>1</bitWidth>
          </field>
          <field>
            <name>ID2</name>
            <bitOffset>2</bitOffset>
            <bitWidth>1</bitWidth>
          </field>
          <field>
            <name>ID3</name>
            <bitOffset>3</bitOffset>
            <bitWidth>1</bitWidth>
          </field>
          <field>
            <name>ID4</name>
            <bitOffset>4</bitOffset>
            <bitWidth>1</bitWidth>
          </field>
          <field>
            <name>ID5</name>
            <bitOffset>5</bitOffset>
            <bitWidth>1</bitWidth>
          </field>
          <field>
            <name>ID6</name>
            <bitOffset>6</bitOffset>
            <bitWidth>1</bitWidth>
          </field>
          <field>
            <name>ID7</name>
            <bitOffset>7</bitOffset>
            <bitWidth>1</bitWidth>
          </field>
          <field>
            <name>ID8</name>
            <bitOffset>8</bitOffset>
            <bitWidth>1</bitWidth>
          </field>
          <field>
            <name>ID9</name>
            <bitOffset>9</bitOffset>
            <bitWidth>1</bitWidth>
          </field>
          <field>
            <name>ID10</name>
            <bitOffset>10</bitOffset>
            <bitWidth>1</bitWidth>
          </field>
          <field>
            <name>ID11</name>
            <bitOffset>11</bitOffset>
            <bitWidth>1</bitWidth>
          </field>
          <field>
            <name>ID12</name>
            <bitOffset>12</bitOffset>
            <bitWidth>1</bitWidth>
          </field>
          <field>
            <name>ID13</name>
            <bitOffset>13</bitOffset>
            <bitWidth>1</bitWidth>
          </field>
          <field>
            <name>ID14</name>
            <bitOffset>14</bitOffset>
            <bitWidth>1</bitWidth>
          </field>
          <field>
            <name>ID15</name>
            <bitOffset>15</bitOffset>
            <bitWidth>1</bitWidth>
          </field>
        </fields>
      </register>
      <register>
        <name>ODR</name>
        <addressOffset>0x14</addressOffset>
        <size>0x20</size>
        <fields>
          <field>
            <name>OD0</name>
            <bitOffset>0</bitOffset>
            <bitWidth>1</bitWidth>
          </field>
          <field>
            <name>OD1</name>
            <bitOffset>1</bitOffset>
            <bitWidth>1</bitWidth>
          </field>
          <field>
            <name>OD2</name>
            <bitOffset>2</bitOffset>
            <bitWidth>1</bitWidth>
          </field>
          <field>
            <name>OD3</name>
            <bitOffset>3</bitOffset>
            <bitWidth>1</bitWidth>
          </field>
          <field>
            <name>OD4</name>
            <bitOffset>4</bitOffset>
            <bitWidth>1</bitWidth>
          </field>
          <field>
            <name>OD5</name>
            <bitOffset>5</bitOffset>
            <bitWidth>1</bitWidth>
          </field>
          <field>
            <name>OD6</name>
            <bitOffset>6</bitOffset>
            <bitWidth>1</bitWidth>
          </field>
          <field>
            <name>OD7</name>
            <bitOffset>7</bitOffset>
            <bitWidth>1</bitWidth>
          </field>
          <field>
            <name>OD8</name>
            <bitOffset>8</bitOffset>
            <bitWidth>1</bitWidth>
          </field>
          <field>
            <name>OD9</name>
            <bitOffset>9</bitOffset>
            <bitWidth>1</bitWidth>
          </field>
          <field>
            <name>OD10</name>
            <bitOffset>10</bitOffset>
            <bitWidth>1</bitWidth>
          </field>
          <field>
            <name>OD11</name>
            <bitOffset>11</bitOffset>
            <bitWidth>1</bitWidth>
          </field>
          <field>
            <name>OD12</name>
            <bitOffset>12</bitOffset>
            <bitWidth>1</bitWidth>
          </field>
          <field>
            <name>OD13</name>
            <bitOffset>13</bitOffset>
            <bitWidth>1</bitWidth>
          </field>
          <field>
            <name>OD14</name>
            <bitOffset>14</bitOffset>
            <bitWidth>1</bitWidth>
          </field>
          <field>
            <name>OD15</name>
            <bitOffset>15</bitOffset>
            <bitWidth>1</bitWidth>
          </field>
        </fields>
      </register>
      <register>
        <name>BSRR</name>
        <addressOffset>0x18</addressOffset>
        <size>0x20</size>
        <fields>
          <field>
            <name>BS0</name>
            <bitOffset>0</bitOffset>
            <bitWidth>1</bitWidth>
          </field>
          <field>
            <name>BS1</name>
            <bitOffset>1</bitOffset>
            <bitWidth>1</bitWidth>
          </field>
          <field>
            <name>BS2</name>
            <bitOffset>2</bitOffset>
            <bitWidth>1</bitWidth>
          </field>
          <field>
            <name>BS3</name>
            <bitOffset>3</bitOffset>
            <bitWidth>1</bitWidth>
          </field>
          <field>
            <name>BS4</name>
            <bitOffset>4</bitOffset>
            <bitWidth>1</bitWidth>
          </field>
          <field>
            <name>BS5</name>
            <bitOffset>5</bitOffset>
            <bitWidth>1</bitWidth>
          </field>
          <field>
            <name>BS6</name>
            <bitOffset>6</bitOffset>
            <bitWidth>1</bitWidth>
          </field>
          <field>
            <name>BS7</name>
            <bitOffset>7</bitOffset>
            <bitWidth>1</bitWidth>
          </field>
          <field>
            <name>BS8</name>
            <bitOffset>8</bitOffset>
            <bitWidth>1</bitWidth>
          </field>
          <field>
            <name>BS9</name>
            <bitOffset>9</bitOffset>
            <bitWidth>1</bitWidth>
          </field>
          <field>
            <name>BS10</name>
            <bitOffset>10</bitOffset>
            <bitWidth>1</bitWidth>
          </field>
          <field>
            <name>BS11</name>
            <bitOffset>11</bitOffset>
            <bitWidth>1</bitWidth>
          </field>
          <field>
            <name>BS12</name>
            <bitOffset>12</bitOffset>
            <bitWidth>1</bitWidth>
          </field>
          <field>
            <name>BS13</name>
            <bitOffset>13</bitOffset>
            <bitWidth>1</bitWidth>
          </field>
          <field>
            <name>BS14</name>
            <bitOffset>14</bitOffset>
            <bitWidth>1</bitWidth>
          </field>
          <field>
            <name>BS15</name>
            <bitOffset>15</bitOffset>
            <bitWidth>1</bitWidth>
          </field>
          <field>
            <name>BR0</name>
            <bitOffset>16</bitOffset>
            <bitWidth>1</bitWidth>
          </field>
          <field>
            <name>BR1</name>
            <bitOffset>17</bitOffset>
            <bitWidth>1</bitWidth>
          </field>
          <field>
            <name>BR2</name>
            <bitOffset>18</bitOffset>
            <bitWidth>1</bitWidth>
          </field>
          <field>
            <name>BR3</name>
            <bitOffset>19</bitOffset>
            <bitWidth>1</bitWidth>
          </field>
          <field>
            <name>BR4</name>
            <bitOffset>20</bitOffset>
            <bitWidth>1</bitWidth>
          </field>
          <field>
            <name>BR5</name>
            <bitOffset>21</bitOffset>
            <bitWidth>1</bitWidth>
          </field>
          <field>
            <name>BR6</name>
            <bitOffset>22</bitOffset>
            <bitWidth>1</bitWidth>
          </field>
          <field>
            <name>BR7</name>
            <bitOffset>23</bitOffset>
            <bitWidth>1</bitWidth>
          </field>
          <field>
            <name>BR8</name>
            <bitOffset>24</bitOffset>
            <bitWidth>1</bitWidth>
          </field>
          <field>
            <name>BR9</name>
            <bitOffset>25</bitOffset>
            <bitWidth>1</bitWidth>
          </field>
          <field>
            <name>BR10</name>
            <bitOffset>26</bitOffset>
            <bitWidth>1</bitWidth>
          </field>
          <field>
            <name>BR11</name>
            <bitOffset>27</bitOffset>
            <bitWidth>1</bitWidth>
          </field>
          <field>
            <name>BR12</name>
            <bitOffset>28</bitOffset>
            <bitWidth>1</bitWidth>
          </field>
          <field>
            <name>BR13</name>
            <bitOffset>29</bitOffset>
            <bitWidth>1</bitWidth>
          </field>
          <field>
            <name>BR14</name>
            <bitOffset>30</bitOffset>
            <bitWidth>1</bitWidth>
          </field>
          <field>
            <name>BR15</name>
            <bitOffset>31</bitOffset>
            <bitWidth>1</bitWidth>
          </field>
        </fields>
      </register>
      <register>
        <name>LCKR</name>
        <addressOffset>0x1c</addressOffset>
        <size>0x20</size>
        <fields>
          <field>
            <name>LCK0</name>
            <bitOffset>0</bitOffset>
            <bitWidth>1</bitWidth>
          </field>
          <field>
            <name>LCK1</name>
            <bitOffset>1</bitOffset>
            <bitWidth>1</bitWidth>
          </field>
          <field>
            <name>LCK2</name>
            <bitOffset>2</bitOffset>
            <bitWidth>1</bitWidth>
          </field>
          <field>
            <name>LCK3</name>
            <bitOffset>3</bitOffset>
            <bitWidth>1</bitWidth>
          </field>
          <field>
            <name>LCK4</name>
            <bitOffset>4</bitOffset>
            <bitWidth>1</bitWidth>
          </field>
          <field>
            <name>LCK5</name>
            <bitOffset>5</bitOffset>
            <bitWidth>1</bitWidth>
          </field>
          <field>
            <name>LCK6</name>
            <bitOffset>6</bitOffset>
            <bitWidth>1</bitWidth>
          </field>
          <field>
            <name>LCK7</name>
            <bitOffset>7</bitOffset>
            <bitWidth>1</bitWidth>
          </field>
          <field>
            <name>LCK8</name>
            <bitOffset>8</bitOffset>
            <bitWidth>1</bitWidth>
          </field>
          <field>
            <name>LCK9</name>
            <bitOffset>9</bitOffset>
            <bitWidth>1</bitWidth>
          </field>
          <field>
            <name>LCK10</name>
            <bitOffset>10</bitOffset>
            <bitWidth>1</bitWidth>
          </field>
          <field>
            <name>LCK11</name>
            <bitOffset>11</bitOffset>
            <bitWidth>1</bitWidth>
          </field>
          <field>
            <name>LCK12</name>
            <bitOffset>12</bitOffset>
            <bitWidth>1</bitWidth>
          </field>
          <field>
            <name>LCK13</name>
            <bitOffset>13</bitOffset>
            <bitWidth>1</bitWidth>
          </field>
          <field>
            <name>LCK14</name>
            <bitOffset>14</bitOffset>
            <bitWidth>1</bitWidth>
          </field>
          <field>
            <name>LCK15</name>
            <bitOffset>15</bitOffset>
            <bitWidth>1</bitWidth>
          </field>
          <field>
            <name>LCKK</name>
            <bitOffset>16</bitOffset>
            <bitWidth>1</bitWidth>
          </field>
        </fields>
      </register>
      <register>
        <name>AFR.0</name>
        <addressOffset>0x20</addressOffset>
        <size>0x20</size>
        <fields>
          <field>
            <name>AFSEL0</name>
            <bitOffset>0</bitOffset>
            <bitWidth>4</bitWidth>
          </field>
          <field>
            <name>AFSEL1</name>
            <bitOffset>4</bitOffset>
            <bitWidth>4</bitWidth>
          </field>
          <field>
            <name>AFSEL2</name>
            <bitOffset>8</bitOffset>
            <bitWidth>4</bitWidth>
          </field>
          <field>
            <name>AFSEL3</name>
            <bitOffset>12</bitOffset>
            <bitWidth>4</bitWidth>
          </field>
          <field>
            <name>AFSEL4</name>
            <bitOffset>16</bitOffset>
            <bitWidth>4</bitWidth>
          </field>
          <field>
            <name>AFSEL5</name>
            <bitOffset>20</bitOffset>
            <bitWidth>4</bitWidth>
          </field>
          <field>
            <name>AFSEL6</name>
            <bitOffset>24</bitOffset>
            <bitWidth>4</bitWidth>
          </field>
          <field>
            <name>AFSEL7</name>
            <bitOffset>28</bitOffset>
            <bitWidth>4</bitWidth>
          </field>
        </fields>
      </register>
      <register>
        <name>AFR.1</name>
        <addressOffset>0x24</addressOffset>
        <size>0x20</size>
        <fields>
          <field>
            <name>AFSEL8</name>
            <bitOffset>0</bitOffset>
            <bitWidth>4</bitWidth>
          </field>
          <field>
            <name>AFSEL9</name>
            <bitOffset>4</bitOffset>
            <bitWidth>4</bitWidth>
          </field>
          <field>
            <name>AFSEL10</name>
            <bitOffset>8</bitOffset>
            <bitWidth>4</bitWidth>
          </field>
          <field>
            <name>AFSEL11</name>
            <bitOffset>12</bitOffset>
            <bitWidth>4</bitWidth>
          </field>
          <field>
            <name>AFSEL12</name>
            <bitOffset>16</bitOffset>
            <bitWidth>4</bitWidth>
          </field>
          <field>
            <name>AFSEL13</name>
            <bitOffset>20</bitOffset>
            <bitWidth>4</bitWidth>
          </field>
          <field>
            <name>AFSEL14</name>
            <bitOffset>24</bitOffset>
            <bitWidth>4</bitWidth>
          </field>
          <field>
            <name>AFSEL15</name>
            <bitOffset>28</bitOffset>
            <bitWidth>4</bitWidth>
          </field>
        </fields>
      </register>
      <register>
        <name>BRR</name>
        <addressOffset>0x28</addressOffset>
        <size>0x20</size>
        <fields>
          <field>
            <name>BR0</name>
            <bitOffset>0</bitOffset>
            <bitWidth>1</bitWidth>
          </field>
          <field>
            <name>BR1</name>
            <bitOffset>1</bitOffset>
            <bitWidth>1</bitWidth>
          </field>
          <field>
            <name>BR2</name>
            <bitOffset>2</bitOffset>
            <bitWidth>1</bitWidth>
          </field>
          <field>
            <name>BR3</name>
            <bitOffset>3</bitOffset>
            <bitWidth>1</bitWidth>
          </field>
          <field>
            <name>BR4</name>
            <bitOffset>4</bitOffset>
            <bitWidth>1</bitWidth>
          </field>
          <field>
            <name>BR5</name>
            <bitOffset>5</bitOffset>
            <bitWidth>1</bitWidth>
          </field>
          <field>
            <name>BR6</name>
            <bitOffset>6</bitOffset>
            <bitWidth>1</bitWidth>
          </field>
          <field>
            <name>BR7</name>
            <bitOffset>7</bitOffset>
            <bitWidth>1</bitWidth>
          </field>
          <field>
            <name>BR8</name>
            <bitOffset>8</bitOffset>
            <bitWidth>1</bitWidth>
          </field>
          <field>
            <name>BR9</name>
            <bitOffset>9</bitOffset>
            <bitWidth>1</bitWidth>
          </field>
          <field>
            <name>BR10</name>
            <bitOffset>10</bitOffset>
            <bitWidth>1</bitWidth>
          </field>
          <field>
            <name>BR11</name>
            <bitOffset>11</bitOffset>
            <bitWidth>1</bitWidth>
          </field>
          <field>
            <name>BR12</name>
            <bitOffset>12</bitOffset>
            <bitWidth>1</bitWidth>
          </field>
          <field>
            <name>BR13</name>
            <bitOffset>13</bitOffset>
            <bitWidth>1</bitWidth>
          </field>
          <field>
            <name>BR14</name>
            <bitOffset>14</bitOffset>
            <bitWidth>1</bitWidth>
          </field>
          <field>
            <name>BR15</name>
            <bitOffset>15</bitOffset>
            <bitWidth>1</bitWidth>
          </field>
        </fields>
      </register>
    </peripheral>
    <peripheral>
      <name>USB_OTG_FS</name>
      <baseAddress>0x50000000</baseAddress>
      <register>
        <name>GOTGCTL</name>
        <addressOffset>0x0</addressOffset>
        <size>0x20</size>
        <fields>
          <field>
            <name>SRQSCS</name>
            <bitOffset>0</bitOffset>
            <bitWidth>1</bitWidth>
          </field>
          <field>
            <name>SRQ</name>
            <bitOffset>1</bitOffset>
            <bitWidth>1</bitWidth>
          </field>
          <field>
            <name>VBVALOEN</name>
            <bitOffset>2</bitOffset>
            <bitWidth>1</bitWidth>
          </field>
          <field>
            <name>VBVALOVAL</name>
            <bitOffset>3</bitOffset>
            <bitWidth>1</bitWidth>
          </field>
          <field>
            <name>AVALOEN</name>
            <bitOffset>4</bitOffset>
            <bitWidth>1</bitWidth>
          </field>
          <field>
            <name>AVALOVAL</name>
            <bitOffset>5</bitOffset>
            <bitWidth>1</bitWidth>
          </field>
          <field>
            <name>BVALOEN</name>
            <bitOffset>6</bitOffset>
            <bitWidth>1</bitWidth>
          </field>
          <field>
            <name>BVALOVAL</name>
            <bitOffset>7</bitOffset>
            <bitWidth>1</bitWidth>
          </field>
          <field>
            <name>BSESVLD</name>
            <bitOffset>19</bitOffset>
            <bitWidth>1</bitWidth>
          </field>
        </fields>
      </register>
      <register>
        <name>GOTGINT</name>
        <addressOffset>0x4</addressOffset>
        <size>0x20</size>
        <fields>
          <field>
            <name>SEDET</name>
            <bitOffset>2</bitOffset>
            <bitWidth>1</bitWidth>
          </field>
          <field>
            <name>SRSSCHG</name>
            <bitOffset>8</bitOffset>
            <bitWidth>1</bitWidth>
          </field>
          <field>
            <name>HNSSCHG</name>
            <bitOffset>9</bitOffset>
            <bitWidth>1</bitWidth>
          </field>
          <field>
            <name>HNGDET</name>
            <bitOffset>17</bitOffset>
            <bitWidth>1</bitWidth>
          </field>
          <field>
            <name>ADTOCHG</name>
            <bitOffset>18</bitOffset>
            <bitWidth>1</bitWidth>
          </field>
          <field>
            <name>DBCDNE</name>
            <bitOffset>19</bitOffset>
            <bitWidth>1</bitWidth>
          </field>
        </fields>
      </register>
      <register>
        <name>GAHBCFG</name>
        <addressOffset>0x8</addressOffset>
        <size>0x20</size>
        <fields>
          <field>
            <name>GINT</name>
            <bitOffset>0</bitOffset>
            <bitWidth>1</bitWidth>
          </field>
          <field>
            <name>HBSTLEN</name>
            <bitOffset>1</bitOffset>
            <bitWidth>4</bitWidth>
          </field>
          <field>
            <name>DMAEN</name>
            <bitOffset>5</bitOffset>
            <bitWidth>1</bitWidth>
          </field>
          <field>
            <name>TXFELVL</name>
            <bitOffset>7</bitOffset>
            <bitWidth>1</bitWidth>
          </field>
          <field>
            <name>PTXFELVL</name>
            <bitOffset>8</bitOffset>
            <bitWidth>1</bitWidth>
          </field>
        </fields>
      </register>
      <register>
        <name>GUSBCFG</name>
        <addressOffset>0xc</addressOffset>
        <size>0x20</size>
        <fields>
          <field>
            <name>TOCAL</name>
            <bitOffset>0</bitOffset>
            <bitWidth>3</bitWidth>
          </field>
          <field>
            <name>PHYSEL</name>
            <bitOffset>6</bitOffset>
            <bitWidth>1</bitWidth>
          </field>
          <field>
            <name>SRPCAP</name>
            <bitOffset>8</bitOffset>
            <bitWidth>1</bitWidth>
          </field>
          <field>
            <name>HNPCAP</name>
            <bitOffset>9</bitOffset>
            <bitWidth>1</bitWidth>
          </field>
          <field>
            <name>TRDT</name>
            <bitOffset>10</bitOffset>
            <bitWidth>4</bitWidth>
          </field>
          <field>
            <name>PHYLPCS</name>
            <bitOffset>15</bitOffset>
            <bitWidth>1</bitWidth>
          </field>
          <field>
            <name>ULPIFSLS</name>
            <bitOffset>17</bitOffset>
            <bitWidth>1</bitWidth>
          </field>
          <field>
            <name>ULPIAR</name>
            <bitOffset>18</bitOffset>
            <bitWidth>1</bitWidth>
          </field>
          <field>
            <name>ULPICSM</name>
            <bitOffset>19</bitOffset>
            <bitWidth>1</bitWidth>
          </field>
          <field>
            <name>ULPIEVBUSD</name>
            <bitOffset>20</bitOffset>
            <bitWidth>1</bitWidth>
          </field>
          <field>
            <name>ULPIEVBUSI</name>
            <bitOffset>21</bitOffset>
            <bitWidth>1</bitWidth>
          </field>
          <field>
            <name>TSDPS</name>
            <bitOffset>22</bitOffset>
            <bitWidth>1</bitWidth>
          </field>
          <field>
            <name>PCCI</name>
            <bitOffset>23</bitOffset>
            <bitWidth>1</bitWidth>
          </field>
          <field>
            <name>PTCI</name>
            <bitOffset>24</bitOffset>
            <bitWidth>1</bitWidth>
          </field>
          <field>
            <name>ULPIIPD</name>
            <bitOffset>25</bitOffset>
            <bitWidth>1</bitWidth>
          </field>
          <field>
            <name>FHMOD</name>
            <bitOffset>29</bitOffset>
            <bitWidth>1</bitWidth>
          </field>
          <field>
            <name>FDMOD</name>
            <bitOffset>30</bitOffset>
            <bitWidth>1</bitWidth>
          </field>
          <field>
            <name>CTXPKT</name>
            <bitOffset>31</bitOffset>
            <bitWidth>1</bitWidth>
          </field>
        </fields>
      </register>
      <register>
        <name>GRSTCTL</name>
        <addressOffset>0x10</addressOffset>
        <size>0x20</size>
        <fields>
          <field>
            <name>CSRST</name>
            <bitOffset>0</bitOffset>
            <bitWidth>1</bitWidth>
          </field>
          <field>
            <name>HSRST</name>
            <bitOffset>1</bitOffset>
            <bitWidth>1</bitWidth>
          </field>
          <field>
            <name>FCRST</name>
            <bitOffset>2</bitOffset>
            <bitWidth>1</bitWidth>
          </field>
          <field>
            <name>RXFFLSH</name>
            <bitOffset>4</bitOffset>
            <bitWidth>1</bitWidth>
          </field>
          <field>
            <name>TXFFLSH</name>
            <bitOffset>5</bitOffset>
            <bitWidth>1</bitWidth>
          </field>
          <field>
            <name>TXFNUM</name>
            <bitOffset>6</bitOffset>
            <bitWidth>5</bitWidth>
          </field>
          <field>
            <name>DMAREQ</name>
            <bitOffset>30</bitOffset>
            <bitWidth>1</bitWidth>
          </field>
          <field>
            <name>AHBIDL</name>
            <bitOffset>31</bitOffset>
            <bitWidth>1</bitWidth>
          </field>
        </fields>
      </register>
      <register>
        <name>GINTSTS</name>
        <addressOffset>0x14</addressOffset>
        <size>0x20</size>
        <fields>
          <field>
            <name>CMOD</name>
            <bitOffset>0</bitOffset>
            <bitWidth>1</bitWidth>
          </field>
          <field>
            <name>MMIS</name>
            <bitOffset>1</bitOffset>
            <bitWidth>1</bitWidth>
          </field>
          <field>
            <name>OTGINT</name>
            <bitOffset>2</bitOffset>
            <bitWidth>1</bitWidth>
          </field>
          <field>
            <name>SOF</name>
            <bitOffset>3</bitOffset>
            <bitWidth>1</bitWidth>
          </field>
          <field>
            <name>RXFLVL</name>
            <bitOffset>4</bitOffset>
            <bitWidth>1</bitWidth>
          </field>
          <field>
            <name>NPTXFE</name>
            <bitOffset>5</bitOffset>
            <bitWidth>1</bitWidth>
          </field>
          <field>
            <name>GINAKEFF</name>
            <bitOffset>6</bitOffset>
            <bitWidth>1</bitWidth>
          </field>
          <field>
            <name>BOUTNAKEFF</name>
            <bitOffset>7</bitOffset>
            <bitWidth>1</bitWidth>
          </field>
          <field>
            <name>ESUSP</name>
            <bitOffset>10</bitOffset>
            <bitWidth>1</bitWidth>
          </field>
          <field>
            <name>USBSUSP</name>
            <bitOffset>11</bitOffset>
            <bitWidth>1</bitWidth>
          </field>
          <field>
            <name>USBRST</name>
            <bitOffset>12</bitOffset>
            <bitWidth>1</bitWidth>
          </field>
          <field>
            <name>ENUMDNE</name>
            <bitOffset>13</bitOffset>
            <bitWidth>1</bitWidth>
          </field>
          <field>
            <name>ISOODRP</name>
            <bitOffset>14</bitOffset>
            <bitWidth>1</bitWidth>
          </field>
          <field>
            <name>EOPF</name>
            <bitOffset>15</bitOffset>
            <bitWidth>1</bitWidth>
          </field>
          <field>
            <name>IEPINT</name>
            <bitOffset>18</bitOffset>
            <bitWidth>1</bitWidth>
          </field>
          <field>
            <name>OEPINT</name>
            <bitOffset>19</bitOffset>
            <bitWidth>1</bitWidth>
          </field>
          <field>
            <name>IISOIXFR</name>
            <bitOffset>20</bitOffset>
            <bitWidth>1</bitWidth>
          </field>
          <field>
            <name>PXFR_INCOMPISOOUT</name>
            <bitOffset>21</bitOffset>
            <bitWidth>1</bitWidth>
          </field>
          <field>
            <name>DATAFSUSP</name>
            <bitOffset>22</bitOffset>
            <bitWidth>1</bitWidth>
          </field>
          <field>
            <name>HPRTINT</name>
            <bitOffset>24</bitOffset>
            <bitWidth>1</bitWidth>
          </field>
          <field>
            <name>HCINT</name>
            <bitOffset>25</bitOffset>
            <bitWidth>1</bitWidth>
          </field>
          <field>
            <name>PTXFE</name>
            <bitOffset>26</bitOffset>
            <bitWidth>1</bitWidth>
          </field>
          <field>
            <name>LPMINT</name>
            <bitOffset>27</bitOffset>
            <bitWidth>1</bitWidth>
          </field>
          <field>
            <name>CIDSCHG</name>
            <bitOffset>28</bitOffset>
            <bitWidth>1</bitWidth>
          </field>
          <field>
            <name>DISCINT</name>
            <bitOffset>29</bitOffset>
            <bitWidth>1</bitWidth>
          </field>
          <field>
            <name>SRQINT</name>
            <bitOffset>30</bitOffset>
            <bitWidth>1</bitWidth>
          </field>
          <field>
            <name>WKUINT</name>
            <bitOffset>31</bitOffset>
            <bitWidth>1</bitWidth>
          </field>
        </fields>
      </register>
      <register>
        <name>GINTMSK</name>
        <addressOffset>0x18</addressOffset>
        <size>0x20</size>
        <fields>
          <field>
            <name>MMISM</name>
            <bitOffset>1</bitOffset>
            <bitWidth>1</bitWidth>
          </field>
          <field>
            <name>OTGINT</name>
            <bitOffset>2</bitOffset>
            <bitWidth>1</bitWidth>
          </field>
          <field>
            <name>SOFM</name>
            <bitOffset>3</bitOffset>
            <bitWidth>1</bitWidth>
          </field>
          <field>
            <name>RXFLVLM</name>
            <bitOffset>4</bitOffset>
            <bitWidth>1</bitWidth>
          </field>
          <field>
            <name>NPTXFEM</name>
            <bitOffset>5</bitOffset>
            <bitWidth>1</bitWidth>
          </field>
          <field>
            <name>GINAKEFFM</name>
            <bitOffset>6</bitOffset>
            <bitWidth>1</bitWidth>
          </field>
          <field>
            <name>GONAKEFFM</name>
            <bitOffset>7</bitOffset>
            <bitWidth>1</bitWidth>
          </field>
          <field>
            <name>ESUSPM</name>
            <bitOffset>10</bitOffset>
            <bitWidth>1</bitWidth>
          </field>
          <field>
            <name>USBSUSPM</name>
            <bitOffset>11</bitOffset>
            <bitWidth>1</bitWidth>
          </field>
          <field>
            <name>USBRST</name>
            <bitOffset>12</bitOffset>
            <bitWidth>1</bitWidth>
          </field>
          <field>
            <name>ENUMDNEM</name>
            <bitOffset>13</bitOffset>
            <bitWidth>1</bitWidth>
          </field>
          <field>
            <name>ISOODRPM</name>
            <bitOffset>14</bitOffset>
            <bitWidth>1</bitWidth>
          </field>
          <field>
            <name>EOPFM</name>
            <bitOffset>15</bitOffset>
            <bitWidth>1</bitWidth>
          </field>
          <field>
            <name>EPMISM</name>
            <bitOffset>17</bitOffset>
            <bitWidth>1</bitWidth>
          </field>
          <field>
            <name>IEPINT</name>
            <bitOffset>18</bitOffset>
            <bitWidth>1</bitWidth>
          </field>
          <field>
            <name>OEPINT</name>
            <bitOffset>19</bitOffset>
            <bitWidth>1</bitWidth>
          </field>
          <field>
            <name>IISOIXFRM</name>
            <bitOffset>20</bitOffset>
            <bitWidth>1</bitWidth>
          </field>
          <field>
            <name>PXFRM_IISOOXFRM</name>
            <bitOffset>21</bitOffset>
            <bitWidth>1</bitWidth>
          </field>
          <field>
            <name>FSUSPM</name>
            <bitOffset>22</bitOffset>
            <bitWidth>1</bitWidth>
          </field>
          <field>
            <name>PRTIM</name>
            <bitOffset>24</bitOffset>
            <bitWidth>1</bitWidth>
          </field>
          <field>
            <name>HCIM</name>
            <bitOffset>25</bitOffset>
            <bitWidth>1</bitWidth>
          </field>
          <field>
            <name>PTXFEM</name>
            <bitOffset>26</bitOffset>
            <bitWidth>1</bitWidth>
          </field>
          <field>
            <name>LPMINTM</name>
            <bitOffset>27</bitOffset>
            <bitWidth>1</bitWidth>
          </field>
          <field>
            <name>CIDSCHGM</name>
            <bitOffset>28</bitOffset>
            <bitWidth>1</bitWidth>
          </field>
          <field>
            <name>DISCINT</name>
            <bitOffset>29</bitOffset>
            <bitWidth>1</bitWidth>
          </field>
          <field>
            <name>SRQIM</name>
            <bitOffset>30</bitOffset>
            <bitWidth>1</bitWidth>
          </field>
          <field>
            <name>WUIM</name>
            <bitOffset>31</bitOffset>
            <bitWidth>1</bitWidth>
          </field>
        </fields>
      </register>
      <register>
        <name>GRXSTSR</name>
        <addressOffset>0x1c</addressOffset>
        <size>0x20</size>
      </register>
      <register>
        <name>GRXSTSP</name>
        <addressOffset>0x20</addressOffset>
        <size>0x20</size>
        <fields>
          <field>
            <name>EPNUM</name>
            <bitOffset>0</bitOffset>
            <bitWidth>4</bitWidth>
          </field>
          <field>
            <name>BCNT</name>
            <bitOffset>4</bitOffset>
            <bitWidth>11</bitWidth>
          </field>
          <field>
            <name>DPID</name>
            <bitOffset>15</bitOffset>
            <bitWidth>2</bitWidth>
          </field>
          <field>
            <name>PKTSTS</name>
            <bitOffset>17</bitOffset>
            <bitWidth>4</bitWidth>
          </field>
        </fields>
      </register>
      <register>
        <name>GRXFSIZ</name>
        <addressOffset>0x24</addressOffset>
        <size>0x20</size>
        <fields>
          <field>
            <name>RXFD</name>
            <bitOffset>0</bitOffset>
            <bitWidth>16</bitWidth>
          </field>
        </fields>
      </register>
      <register>
        <name>DIEPTXF0_HNPTXFSIZ</name>
        <addressOffset>0x28</addressOffset>
        <size>0x20</size>
      </register>
      <register>
        <name>HNPTXSTS</name>
        <addressOffset>0x2c</addressOffset>
        <size>0x20</size>
      </register>
      <register>
        <name>GCCFG</name>
        <addressOffset>0x38</addressOffset>
        <size>0x20</size>
        <fields>
          <field>
            <name>DCDET</name>
            <bitOffset>0</bitOffset>
            <bitWidth>1</bitWidth>
          </field>
          <field>
            <name>PDET</name>
            <bitOffset>1</bitOffset>
            <bitWidth>1</bitWidth>
          </field>
          <field>
            <name>SDET</name>
            <bitOffset>2</bitOffset>
            <bitWidth>1</bitWidth>
          </field>
          <field>
            <name>PS2DET</name>
            <bitOffset>3</bitOffset>
            <bitWidth>1</bitWidth>
          </field>
          <field>
            <name>PWRDWN</name>
            <bitOffset>16</bitOffset>
            <bitWidth>1</bitWidth>
          </field>
          <field>
            <name>BCDEN</name>
            <bitOffset>17</bitOffset>
            <bitWidth>1</bitWidth>
          </field>
          <field>
            <name>DCDEN</name>
            <bitOffset>18</bitOffset>
            <bitWidth>1</bitWidth>
          </field>
          <field>
            <name>PDEN</name>
            <bitOffset>19</bitOffset>
            <bitWidth>1</bitWidth>
          </field>
          <field>
            <name>SDEN</name>
            <bitOffset>20</bitOffset>
            <bitWidth>1</bitWidth>
          </field>
          <field>
            <name>VBDEN</name>
            <bitOffset>21</bitOffset>
            <bitWidth>1</bitWidth>
          </field>
        </fields>
      </register>
      <register>
        <name>CID</name>
        <addressOffset>0x3c</addressOffset>
        <size>0x20</size>
        <fields>
          <field>
            <name>PRODUCT_ID</name>
            <bitOffset>0</bitOffset>
            <bitWidth>32</bitWidth>
          </field>
        </fields>
      </register>
      <register>
        <name>GSNPSID</name>
        <addressOffset>0x40</addressOffset>
        <size>0x20</size>
      </register>
      <register>
        <name>GHWCFG1</name>
        <addressOffset>0x44</addressOffset>
        <size>0x20</size>
      </register>
      <register>
        <name>GHWCFG2</name>
        <addressOffset>0x48</addressOffset>
        <size>0x20</size>
      </register>
      <register>
        <name>GHWCFG3</name>
        <addressOffset>0x4c</addressOffset>
        <size>0x20</size>
      </register>
      <register>
        <name>GLPMCFG</name>
        <addressOffset>0x54</addressOffset>
        <size>0x20</size>
        <fields>
          <field>
            <name>LPMEN</name>
            <bitOffset>0</bitOffset>
            <bitWidth>1</bitWidth>
          </field>
          <field>
            <name>LPMACK</name>
            <bitOffset>1</bitOffset>
            <bitWidth>1</bitWidth>
          </field>
          <field>
            <name>BESL</name>
            <bitOffset>2</bitOffset>
            <bitWidth>4</bitWidth>
          </field>
          <field>
            <name>REMWAKE</name>
            <bitOffset>6</bitOffset>
            <bitWidth>1</bitWidth>
          </field>
          <field>
            <name>L1SSEN</name>
            <bitOffset>7</bitOffset>
            <bitWidth>1</bitWidth>
          </field>
          <field>
            <name>BESLTHRS</name>
            <bitOffset>8</bitOffset>
            <bitWidth>4</bitWidth>
          </field>
          <field>
            <name>L1DSEN</name>
            <bitOffset>12</bitOffset>
            <bitWidth>1</bitWidth>
          </field>
          <field>
            <name>LPMRSP</name>
            <bitOffset>13</bitOffset>
            <bitWidth>2</bitWidth>
          </field>
          <field>
            <name>SLPSTS</name>
            <bitOffset>15</bitOffset>
            <bitWidth>1</bitWidth>
          </field>
          <field>
            <name>L1RSMOK</name>
            <bitOffset>16</bitOffset>
            <bitWidth>1</bitWidth>
          </field>
          <field>
            <name>LPMCHIDX</name>
            <bitOffset>17</bitOffset>
            <bitWidth>4</bitWidth>
          </field>
          <field>
            <name>LPMRCNT</name>
            <bitOffset>21</bitOffset>
            <bitWidth>3</bitWidth>
          </field>
          <field>
            <name>SNDLPM</name>
            <bitOffset>24</bitOffset>
            <bitWidth>1</bitWidth>
          </field>
          <field>
            <name>LPMRCNTSTS</name>
            <bitOffset>25</bitOffset>
            <bitWidth>3</bitWidth>
          </field>
          <field>
            <name>ENBESL</name>
            <bitOffset>28</bitOffset>
            <bitWidth>1</bitWidth>
          </field>
        </fields>
      </register>
      <register>
        <name>GPWRDN</name>
        <addressOffset>0x58</addressOffset>
        <size>0x20</size>
        <fields>
          <field>
            <name>DISABLEVBUS</name>
            <bitOffset>6</bitOffset>
            <bitWidth>1</bitWidth>
          </field>
        </fields>
      </register>
      <register>
        <name>GDFIFOCFG</name>
        <addressOffset>0x5c</addressOffset>
        <size>0x20</size>
      </register>
      <register>
        <name>GADPCTL</name>
        <addressOffset>0x60</addressOffset>
        <size>0x20</size>
      </register>
      <register>
        <name>HPTXFSIZ</name>
        <addressOffset>0x100</addressOffset>
        <size>0x20</size>
        <fields>
          <field>
            <name>PTXSA</name>
            <bitOffset>0</bitOffset>
            <bitWidth>16</bitWidth>
          </field>
          <field>
            <name>PTXFD</name>
            <bitOffset>16</bitOffset>
            <bitWidth>16</bitWidth>
          </field>
        </fields>
      </register>
      <register>
        <name>DIEPTXF.0</name>
        <addressOffset>0x104</addressOffset>
        <size>0x20</size>
        <fields>
          <field>
            <name>INEPTXSA</name>
            <bitOffset>0</bitOffset>
            <bitWidth>16</bitWidth>
          </field>
          <field>
            <name>INEPTXFD</name>
            <bitOffset>16</bitOffset>
            <bitWidth>16</bitWidth>
          </field>
        </fields>
      </register>
      <register>
        <name>DIEPTXF.1</name>
        <addressOffset>0x108</addressOffset>
        <size>0x20</size>
        <fields>
          <field>
            <name>INEPTXSA</name>
            <bitOffset>0</bitOffset>
            <bitWidth>16</bitWidth>
          </field>
          <field>
            <name>INEPTXFD</name>
            <bitOffset>16</bitOffset>
            <bitWidth>16</bitWidth>
          </field>
        </fields>
      </register>
      <register>
        <name>DIEPTXF.2</name>
        <addressOffset>0x10c</addressOffset>
        <size>0x20</size>
        <fields>
          <field>
            <name>INEPTXSA</name>
            <bitOffset>0</bitOffset>
            <bitWidth>16</bitWidth>
          </field>
          <field>
            <name>INEPTXFD</name>
            <bitOffset>16</bitOffset>
            <bitWidth>16</bitWidth>
          </field>
        </fields>
      </register>
      <register>
        <name>DIEPTXF.3</name>
        <addressOffset>0x110</addressOffset>
        <size>0x20</size>
        <fields>
          <field>
            <name>INEPTXSA</name>
            <bitOffset>0</bitOffset>
            <bitWidth>16</bitWidth>
          </field>
          <field>
            <name>INEPTXFD</name>
            <bitOffset>16</bitOffset>
            <bitWidth>16</bitWidth>
          </field>
        </fields>
      </register>
      <register>
        <name>DIEPTXF.4</name>
        <addressOffset>0x114</addressOffset>
        <size>0x20</size>
        <fields>
          <field>
            <name>INEPTXSA</name>
            <bitOffset>0</bitOffset>
            <bitWidth>16</bitWidth>
          </field>
          <field>
            <name>INEPTXFD</name>
            <bitOffset>16</bitOffset>
            <bitWidth>16</bitWidth>
          </field>
        </fields>
      </register>
      <register>
        <name>DIEPTXF.5</name>
        <addressOffset>0x118</addressOffset>
        <size>0x20</size>
        <fields>
          <field>
            <name>INEPTXSA</name>
            <bitOffset>0</bitOffset>
            <bitWidth>16</bitWidth>
          </field>
          <field>
            <name>INEPTXFD</name>
            <bitOffset>16</bitOffset>
            <bitWidth>16</bitWidth>
          </field>
        </fields>
      </register>
      <register>
        <name>DIEPTXF.6</name>
        <addressOffset>0x11c</addressOffset>
        <size>0x20</size>
        <fields>
          <field>
            <name>INEPTXSA</name>
            <bitOffset>0</bitOffset>
            <bitWidth>16</bitWidth>
          </field>
          <field>
            <name>INEPTXFD</name>
            <bitOffset>16</bitOffset>
            <bitWidth>16</bitWidth>
          </field>
        </fields>
      </register>
      <register>
        <name>DIEPTXF.7</name>
        <addressOffset>0x120</addressOffset>
        <size>0x20</size>
        <fields>
          <field>
            <name>INEPTXSA</name>
            <bitOffset>0</bitOffset>
            <bitWidth>16</bitWidth>
          </field>
          <field>
            <name>INEPTXFD</name>
            <bitOffset>16</bitOffset>
            <bitWidth>16</bitWidth>
          </field>
        </fields>
      </register>
      <register>
        <name>DIEPTXF.8</name>
        <addressOffset>0x124</addressOffset>
        <size>0x20</size>
        <fields>
          <field>
            <name>INEPTXSA</name>
            <bitOffset>0</bitOffset>
            <bitWidth>16</bitWidth>
          </field>
          <field>
            <name>INEPTXFD</name>
            <bitOffset>16</bitOffset>
            <bitWidth>16</bitWidth>
          </field>
        </fields>
      </register>
      <register>
        <name>DIEPTXF.9</name>
        <addressOffset>0x128</addressOffset>
        <size>0x20</size>
        <fields>
          <field>
            <name>INEPTXSA</name>
            <bitOffset>0</bitOffset>
            <bitWidth>16</bitWidth>
          </field>
          <field>
            <name>INEPTXFD</name>
            <bitOffset>16</bitOffset>
            <bitWidth>16</bitWidth>
          </field>
        </fields>
      </register>
      <register>
        <name>DIEPTXF.10</name>
        <addressOffset>0x12c</addressOffset>
        <size>0x20</size>
        <fields>
          <field>
            <name>INEPTXSA</name>
            <bitOffset>0</bitOffset>
            <bitWidth>16</bitWidth>
          </field>
          <field>
            <name>INEPTXFD</name>
            <bitOffset>16</bitOffset>
            <bitWidth>16</bitWidth>
          </field>
        </fields>
      </register>
      <register>
        <name>DIEPTXF.11</name>
        <addressOffset>0x130</addressOffset>
        <size>0x20</size>
        <fields>
          <field>
            <name>INEPTXSA</name>
            <bitOffset>0</bitOffset>
            <bitWidth>16</bitWidth>
          </field>
          <field>
            <name>INEPTXFD</name>
            <bitOffset>16</bitOffset>
            <bitWidth>16</bitWidth>
          </field>
        </fields>
      </register>
      <register>
        <name>DIEPTXF.12</name>
        <addressOffset>0x134</addressOffset>
        <size>0x20</size>
        <fields>
          <field>
            <name>INEPTXSA</name>
            <bitOffset>0</bitOffset>
            <bitWidth>16</bitWidth>
          </field>
          <field>
            <name>INEPTXFD</name>
            <bitOffset>16</bitOffset>
            <bitWidth>16</bitWidth>
          </field>
        </fields>
      </register>
      <register>
        <name>DIEPTXF.13</name>
        <addressOffset>0x138</addressOffset>
        <size>0x20</size>
        <fields>
          <field>
            <name>INEPTXSA</name>
            <bitOffset>0</bitOffset>
            <bitWidth>16</bitWidth>
          </field>
          <field>
            <name>INEPTXFD</name>
            <bitOffset>16</bitOffset>
            <bitWidth>16</bitWidth>
          </field>
        </fields>
      </register>
      <register>
        <name>DIEPTXF.14</name>
        <addressOffset>0x13c</addressOffset>
        <size>0x20</size>
        <fields>
          <field>
            <name>INEPTXSA</name>
            <bitOffset>0</bitOffset>
            <bitWidth>16</bitWidth>
          </field>
          <field>
            <name>INEPTXFD</name>
            <bitOffset>16</bitOffset>
            <bitWidth>16</bitWidth>
          </field>
        </fields>
      </register>
    </peripheral>
    <peripheral>
      <name>ADC1</name>
      <baseAddress>0x50040000</baseAddress>
      <register>
        <name>ISR</name>
        <addressOffset>0x0</addressOffset>
        <size>0x20</size>
        <fields>
          <field>
            <name>ADRDY</name>
            <bitOffset>0</bitOffset>
            <bitWidth>1</bitWidth>
          </field>
          <field>
            <name>EOSMP</name>
            <bitOffset>1</bitOffset>
            <bitWidth>1</bitWidth>
          </field>
          <field>
            <name>EOC</name>
            <bitOffset>2</bitOffset>
            <bitWidth>1</bitWidth>
          </field>
          <field>
            <name>EOS</name>
            <bitOffset>3</bitOffset>
            <bitWidth>1</bitWidth>
          </field>
          <field>
            <name>OVR</name>
            <bitOffset>4</bitOffset>
            <bitWidth>1</bitWidth>
          </field>
          <field>
            <name>JEOC</name>
            <bitOffset>5</bitOffset>
            <bitWidth>1</bitWidth>
          </field>
          <field>
            <name>JEOS</name>
            <bitOffset>6</bitOffset>
            <bitWidth>1</bitWidth>
          </field>
          <field>
            <name>AWD1</name>
            <bitOffset>7</bitOffset>
            <bitWidth>1</bitWidth>
          </field>
          <field>
            <name>AWD2</name>
            <bitOffset>8</bitOffset>
            <bitWidth>1</bitWidth>
          </field>
          <field>
            <name>AWD3</name>
            <bitOffset>9</bitOffset>
            <bitWidth>1</bitWidth>
          </field>
          <field>
            <name>JQOVF</name>
            <bitOffset>10</bitOffset>
            <bitWidth>1</bitWidth>
          </field>
        </fields>
      </register>
      <register>
        <name>IER</name>
        <addressOffset>0x4</addressOffset>
        <size>0x20</size>
        <fields>
          <field>
            <name>ADRDYIE</name>
            <bitOffset>0</bitOffset>
            <bitWidth>1</bitWidth>
          </field>
          <field>
            <name>EOSMPIE</name>
            <bitOffset>1</bitOffset>
            <bitWidth>1</bitWidth>
          </field>
          <field>
            <name>EOCIE</name>
            <bitOffset>2</bitOffset>
            <bitWidth>1</bitWidth>
          </field>
          <field>
            <name>EOSIE</name>
            <bitOffset>3</bitOffset>
            <bitWidth>1</bitWidth>
          </field>
          <field>
            <name>OVRIE</name>
            <bitOffset>4</bitOffset>
            <bitWidth>1</bitWidth>
          </field>
          <field>
            <name>JEOCIE</name>
            <bitOffset>5</bitOffset>
            <bitWidth>1</bitWidth>
          </field>
          <field>
            <name>JEOSIE</name>
            <bitOffset>6</bitOffset>
            <bitWidth>1</bitWidth>
          </field>
          <field>
            <name>AWD1IE</name>
            <bitOffset>7</bitOffset>
            <bitWidth>1</bitWidth>
          </field>
          <field>
            <name>AWD2IE</name>
            <bitOffset>8</bitOffset>
            <bitWidth>1</bitWidth>
          </field>
          <field>
            <name>AWD3IE</name>
            <bitOffset>9</bitOffset>
            <bitWidth>1</bitWidth>
          </field>
          <field>
            <name>JQOVFIE</name>
            <bitOffset>10</bitOffset>
            <bitWidth>1</bitWidth>
          </field>
        </fields>
      </register>
      <register>
        <name>CR</name>
        <addressOffset>0x8</addressOffset>
        <size>0x20</size>
        <fields>
          <field>
            <name>ADEN</name>
            <bitOffset>0</bitOffset>
            <bitWidth>1</bitWidth>
          </field>
          <field>
            <name>ADDIS</name>
            <bitOffset>1</bitOffset>
            <bitWidth>1</bitWidth>
          </field>
          <field>
            <name>ADSTART</name>
            <bitOffset>2</bitOffset>
            <bitWidth>1</bitWidth>
          </field>
          <field>
            <name>JADSTART</name>
            <bitOffset>3</bitOffset>
            <bitWidth>1</bitWidth>
          </field>
          <field>
            <name>ADSTP</name>
            <bitOffset>4</bitOffset>
            <bitWidth>1</bitWidth>
          </field>
          <field>
            <name>JADSTP</name>
            <bitOffset>5</bitOffset>
            <bitWidth>1</bitWidth>
          </field>
          <field>
            <name>ADVREGEN</name>
            <bitOffset>28</bitOffset>
            <bitWidth>1</bitWidth>
          </field>
          <field>
            <name>DEEPPWD</name>
            <bitOffset>29</bitOffset>
            <bitWidth>1</bitWidth>
          </field>
          <field>
            <name>ADCALDIF</name>
            <bitOffset>30</bitOffset>
            <bitWidth>1</bitWidth>
          </field>
          <field>
            <name>ADCAL</name>
            <bitOffset>31</bitOffset>
            <bitWidth>1</bitWidth>
          </field>
        </fields>
      </register>
      <register>
        <name>CFGR</name>
        <addressOffset>0xc</addressOffset>
        <size>0x20</size>
        <fields>
          <field>
            <name>DMAEN</name>
            <bitOffset>0</bitOffset>
            <bitWidth>1</bitWidth>
          </field>
          <field>
            <name>DMACFG</name>
            <bitOffset>1</bitOffset>
            <bitWidth>1</bitWidth>
          </field>
          <field>
            <name>DFSDMCFG</name>
            <bitOffset>2</bitOffset>
            <bitWidth>1</bitWidth>
          </field>
          <field>
            <name>RES</name>
            <bitOffset>3</bitOffset>
            <bitWidth>2</bitWidth>
          </field>
          <field>
            <name>ALIGN</name>
            <bitOffset>5</bitOffset>
            <bitWidth>1</bitWidth>
          </field>
          <field>
            <name>EXTSEL</name>
            <bitOffset>6</bitOffset>
            <bitWidth>4</bitWidth>
          </field>
          <field>
            <name>EXTEN</name>
            <bitOffset>10</bitOffset>
            <bitWidth>2</bitWidth>
          </field>
          <field>
            <name>OVRMOD</name>
            <bitOffset>12</bitOffset>
            <bitWidth>1</bitWidth>
          </field>
          <field>
            <name>CONT</name>
            <bitOffset>13</bitOffset>
            <bitWidth>1</bitWidth>
          </field>
          <field>
            <name>AUTDLY</name>
            <bitOffset>14</bitOffset>
            <bitWidth>1</bitWidth>
          </field>
          <field>
            <name>DISCEN</name>
            <bitOffset>16</bitOffset>
            <bitWidth>1</bitWidth>
          </field>
          <field>
            <name>DISCNUM</name>
            <bitOffset>17</bitOffset>
            <bitWidth>3</bitWidth>
          </field>
          <field>
            <name>JDISCEN</name>
            <bitOffset>20</bitOffset>
            <bitWidth>1</bitWidth>
          </field>
          <field>
            <name>JQM</name>
            <bitOffset>21</bitOffset>
            <bitWidth>1</bitWidth>
          </field>
          <field>
            <name>AWD1SGL</name>
            <bitOffset>22</bitOffset>
            <bitWidth>1</bitWidth>
          </field>
          <field>
            <name>AWD1EN</name>
            <bitOffset>23</bitOffset>
            <bitWidth>1</bitWidth>
          </field>
          <field>
            <name>JAWD1EN</name>
            <bitOffset>24</bitOffset>
            <bitWidth>1</bitWidth>
          </field>
          <field>
            <name>JAUTO</name>
            <bitOffset>25</bitOffset>
            <bitWidth>1</bitWidth>
          </field>
          <field>
            <name>AWD1CH</name>
            <bitOffset>26</bitOffset>
            <bitWidth>5</bitWidth>
          </field>
          <field>
            <name>JQDIS</name>
            <bitOffset>31</bitOffset>
            <bitWidth>1</bitWidth>
          </field>
        </fields>
      </register>
      <register>
        <name>CFGR2</name>
        <addressOffset>0x10</addressOffset>
        <size>0x20</size>
        <fields>
          <field>
            <name>ROVSE</name>
            <bitOffset>0</bitOffset>
            <bitWidth>1</bitWidth>
          </field>
          <field>
            <name>JOVSE</name>
            <bitOffset>1</bitOffset>
            <bitWidth>1</bitWidth>
          </field>
          <field>
            <name>OVSR</name>
            <bitOffset>2</bitOffset>
            <bitWidth>3</bitWidth>
          </field>
          <field>
            <name>OVSS</name>
            <bitOffset>5</bitOffset>
            <bitWidth>4</bitWidth>
          </field>
          <field>
            <name>TROVS</name>
            <bitOffset>9</bitOffset>
            <bitWidth>1</bitWidth>
          </field>
          <field>
            <name>ROVSM</name>
            <bitOffset>10</bitOffset>
            <bitWidth>1</bitWidth>
          </field>
        </fields>
      </register>
      <register>
        <name>SMPR1</name>
        <addressOffset>0x14</addressOffset>
        <size>0x20</size>
        <fields>
          <field>
            <name>SMP0</name>
            <bitOffset>0</bitOffset>
            <bitWidth>3</bitWidth>
          </field>
          <field>
            <name>SMP1</name>
            <bitOffset>3</bitOffset>
            <bitWidth>3</bitWidth>
          </field>
          <field>
            <name>SMP2</name>
            <bitOffset>6</bitOffset>
            <bitWidth>3</bitWidth>
          </field>
          <field>
            <name>SMP3</name>
            <bitOffset>9</bitOffset>
            <bitWidth>3</bitWidth>
          </field>
          <field>
            <name>SMP4</name>
            <bitOffset>12</bitOffset>
            <bitWidth>3</bitWidth>
          </field>
          <field>
            <name>SMP5</name>
            <bitOffset>15</bitOffset>
            <bitWidth>3</bitWidth>
          </field>
          <field>
            <name>SMP6</name>
            <bitOffset>18</bitOffset>
            <bitWidth>3</bitWidth>
          </field>
          <field>
            <name>SMP7</name>
            <bitOffset>21</bitOffset>
            <bitWidth>3</bitWidth>
          </field>
          <field>
            <name>SMP8</name>
            <bitOffset>24</bitOffset>
            <bitWidth>3</bitWidth>
          </field>
          <field>
            <name>SMP9</name>
            <bitOffset>27</bitOffset>
            <bitWidth>3</bitWidth>
          </field>
          <field>
            <name>SMPPLUS</name>
            <bitOffset>31</bitOffset>
            <bitWidth>1</bitWidth>
          </field>
        </fields>
      </register>
      <register>
        <name>SMPR2</name>
        <addressOffset>0x18</addressOffset>
        <size>0x20</size>
        <fields>
          <field>
            <name>SMP10</name>
            <bitOffset>0</bitOffset>
            <bitWidth>3</bitWidth>
          </field>
          <field>
            <name>SMP11</name>
            <bitOffset>3</bitOffset>
            <bitWidth>3</bitWidth>
          </field>
          <field>
            <name>SMP12</name>
            <bitOffset>6</bitOffset>
            <bitWidth>3</bitWidth>
          </field>
          <field>
            <name>SMP13</name>
            <bitOffset>9</bitOffset>
            <bitWidth>3</bitWidth>
          </field>
          <field>
            <name>SMP14</name>
            <bitOffset>12</bitOffset>
            <bitWidth>3</bitWidth>
          </field>
          <field>
            <name>SMP15</name>
            <bitOffset>15</bitOffset>
            <bitWidth>3</bitWidth>
          </field>
          <field>
            <name>SMP16</name>
            <bitOffset>18</bitOffset>
            <bitWidth>3</bitWidth>
          </field>
          <field>
            <name>SMP17</name>
            <bitOffset>21</bitOffset>
            <bitWidth>3</bitWidth>
          </field>
          <field>
            <name>SMP18</name>
            <bitOffset>24</bitOffset>
            <bitWidth>3</bitWidth>
          </field>
        </fields>
      </register>
      <register>
        <name>TR1</name>
        <addressOffset>0x20</addressOffset>
        <size>0x20</size>
        <fields>
          <field>
            <name>LT1</name>
            <bitOffset>0</bitOffset>
            <bitWidth>12</bitWidth>
          </field>
          <field>
            <name>HT1</name>
            <bitOffset>16</bitOffset>
            <bitWidth>12</bitWidth>
          </field>
        </fields>
      </register>
      <register>
        <name>TR2</name>
        <addressOffset>0x24</addressOffset>
        <size>0x20</size>
        <fields>
          <field>
            <name>LT2</name>
            <bitOffset>0</bitOffset>
            <bitWidth>8</bitWidth>
          </field>
          <field>
            <name>HT2</name>
            <bitOffset>16</bitOffset>
            <bitWidth>8</bitWidth>
          </field>
        </fields>
      </register>
      <register>
        <name>TR3</name>
        <addressOffset>0x28</addressOffset>
        <size>0x20</size>
        <fields>
          <field>
            <name>LT3</name>
            <bitOffset>0</bitOffset>
            <bitWidth>8</bitWidth>
          </field>
          <field>
            <name>HT3</name>
            <bitOffset>16</bitOffset>
            <bitWidth>8</bitWidth>
          </field>
        </fields>
      </register>
      <register>
        <name>SQR1</name>
        <addressOffset>0x30</addressOffset>
        <size>0x20</size>
        <fields>
          <field>
            <name>L</name>
            <bitOffset>0</bitOffset>
            <bitWidth>4</bitWidth>
          </field>
          <field>
            <name>SQ1</name>
            <bitOffset>6</bitOffset>
            <bitWidth>5</bitWidth>
          </field>
          <field>
            <name>SQ2</name>
            <bitOffset>12</bitOffset>
            <bitWidth>5</bitWidth>
          </field>
          <field>
            <name>SQ3</name>
            <bitOffset>18</bitOffset>
            <bitWidth>5</bitWidth>
          </field>
          <field>
            <name>SQ4</name>
            <bitOffset>24</bitOffset>
            <bitWidth>5</bitWidth>
          </field>
        </fields>
      </register>
      <register>
        <name>SQR2</name>
        <addressOffset>0x34</addressOffset>
        <size>0x20</size>
        <fields>
          <field>
            <name>SQ5</name>
            <bitOffset>0</bitOffset>
            <bitWidth>5</bitWidth>
          </field>
          <field>
            <name>SQ6</name>
            <bitOffset>6</bitOffset>
            <bitWidth>5</bitWidth>
          </field>
          <field>
            <name>SQ7</name>
            <bitOffset>12</bitOffset>
            <bitWidth>5</bitWidth>
          </field>
          <field>
            <name>SQ8</name>
            <bitOffset>18</bitOffset>
            <bitWidth>5</bitWidth>
          </field>
          <field>
            <name>SQ9</name>
            <bitOffset>24</bitOffset>
            <bitWidth>5</bitWidth>
          </field>
        </fields>
      </register>
      <register>
        <name>SQR3</name>
        <addressOffset>0x38</addressOffset>
        <size>0x20</size>
        <fields>
          <field>
            <name>SQ10</name>
            <bitOffset>0</bitOffset>
            <bitWidth>5</bitWidth>
          </field>
          <field>
            <name>SQ11</name>
            <bitOffset>6</bitOffset>
            <bitWidth>5</bitWidth>
          </field>
          <field>
            <name>SQ12</name>
            <bitOffset>12</bitOffset>
            <bitWidth>5</bitWidth>
          </field>
          <field>
            <name>SQ13</name>
            <bitOffset>18</bitOffset>
            <bitWidth>5</bitWidth>
          </field>
          <field>
            <name>SQ14</name>
            <bitOffset>24</bitOffset>
            <bitWidth>5</bitWidth>
          </field>
        </fields>
      </register>
      <register>
        <name>SQR4</name>
        <addressOffset>0x3c</addressOffset>
        <size>0x20</size>
        <fields>
          <field>
            <name>SQ15</name>
            <bitOffset>0</bitOffset>
            <bitWidth>5</bitWidth>
          </field>
          <field>
            <name>SQ16</name>
            <bitOffset>6</bitOffset>
            <bitWidth>5</bitWidth>
          </field>
        </fields>
      </register>
      <register>
        <name>DR</name>
        <addressOffset>0x40</addressOffset>
        <size>0x20</size>
        <fields>
          <field>
            <name>RDATA</name>
            <bitOffset>0</bitOffset>
            <bitWidth>16</bitWidth>
          </field>
        </fields>
      </register>
      <register>
        <name>JSQR</name>
        <addressOffset>0x4c</addressOffset>
        <size>0x20</size>
        <fields>
          <field>
            <name>JL</name>
            <bitOffset>0</bitOffset>
            <bitWidth>2</bitWidth>
          </field>
          <field>
            <name>JEXTSEL</name>
            <bitOffset>2</bitOffset>
            <bitWidth>4</bitWidth>
          </field>
          <field>
            <name>JEXTEN</name>
            <bitOffset>6</bitOffset>
            <bitWidth>2</bitWidth>
          </field>
          <field>
            <name>JSQ1</name>
            <bitOffset>8</bitOffset>
            <bitWidth>5</bitWidth>
          </field>
          <field>
            <name>JSQ2</name>
            <bitOffset>14</bitOffset>
            <bitWidth>5</bitWidth>
          </field>
          <field>
            <name>JSQ3</name>
            <bitOffset>20</bitOffset>
            <bitWidth>5</bitWidth>
          </field>
          <field>
            <name>JSQ4</name>
            <bitOffset>26</bitOffset>
            <bitWidth>5</bitWidth>
          </field>
        </fields>
      </register>
      <register>
        <name>OFR1</name>
        <addressOffset>0x60</addressOffset>
        <size>0x20</size>
        <fields>
          <field>
            <name>OFFSET1</name>
            <bitOffset>0</bitOffset>
            <bitWidth>12</bitWidth>
          </field>
          <field>
            <name>OFFSET1_CH</name>
            <bitOffset>26</bitOffset>
            <bitWidth>5</bitWidth>
          </field>
          <field>
            <name>OFFSET1_EN</name>
            <bitOffset>31</bitOffset>
            <bitWidth>1</bitWidth>
          </field>
        </fields>
      </register>
      <register>
        <name>OFR2</name>
        <addressOffset>0x64</addressOffset>
        <size>0x20</size>
        <fields>
          <field>
            <name>OFFSET2</name>
            <bitOffset>0</bitOffset>
            <bitWidth>12</bitWidth>
          </field>
          <field>
            <name>OFFSET2_CH</name>
            <bitOffset>26</bitOffset>
            <bitWidth>5</bitWidth>
          </field>
          <field>
            <name>OFFSET2_EN</name>
            <bitOffset>31</bitOffset>
            <bitWidth>1</bitWidth>
          </field>
        </fields>
      </register>
      <register>
        <name>OFR3</name>
        <addressOffset>0x68</addressOffset>
        <size>0x20</size>
        <fields>
          <field>
            <name>OFFSET3</name>
            <bitOffset>0</bitOffset>
            <bitWidth>12</bitWidth>
          </field>
          <field>
            <name>OFFSET3_CH</name>
            <bitOffset>26</bitOffset>
            <bitWidth>5</bitWidth>
          </field>
          <field>
            <name>OFFSET3_EN</name>
            <bitOffset>31</bitOffset>
            <bitWidth>1</bitWidth>
          </field>
        </fields>
      </register>
      <register>
        <name>OFR4</name>
        <addressOffset>0x6c</addressOffset>
        <size>0x20</size>
        <fields>
          <field>
            <name>OFFSET4</name>
            <bitOffset>0</bitOffset>
            <bitWidth>12</bitWidth>
          </field>
          <field>
            <name>OFFSET4_CH</name>
            <bitOffset>26</bitOffset>
            <bitWidth>5</bitWidth>
          </field>
          <field>
            <name>OFFSET4_EN</name>
            <bitOffset>31</bitOffset>
            <bitWidth>1</bitWidth>
          </field>
        </fields>
      </register>
      <register>
        <name>JDR1</name>
        <addressOffset>0x80</addressOffset>
        <size>0x20</size>
        <fields>
          <field>
            <name>JDATA</name>
            <bitOffset>0</bitOffset>
            <bitWidth>16</bitWidth>
          </field>
        </fields>
      </register>
      <register>
        <name>JDR2</name>
        <addressOffset>0x84</addressOffset>
        <size>0x20</size>
        <fields>
          <field>
            <name>JDATA</name>
            <bitOffset>0</bitOffset>
            <bitWidth>16</bitWidth>
          </field>
        </fields>
      </register>
      <register>
        <name>JDR3</name>
        <addressOffset>0x88</addressOffset>
        <size>0x20</size>
        <fields>
          <field>
            <name>JDATA</name>
            <bitOffset>0</bitOffset>
            <bitWidth>16</bitWidth>
          </field>
        </fields>
      </register>
      <register>
        <name>JDR4</name>
        <addressOffset>0x8c</addressOffset>
        <size>0x20</size>
        <fields>
          <field>
            <name>JDATA</name>
            <bitOffset>0</bitOffset>
            <bitWidth>16</bitWidth>
          </field>
        </fields>
      </register>
      <register>
        <name>AWD2CR</name>
        <addressOffset>0xa0</addressOffset>
        <size>0x20</size>
        <fields>
          <field>
            <name>AWD2CH</name>
            <bitOffset>0</bitOffset>
            <bitWidth>19</bitWidth>
          </field>
        </fields>
      </register>
      <register>
        <name>AWD3CR</name>
        <addressOffset>0xa4</addressOffset>
        <size>0x20</size>
        <fields>
          <field>
            <name>AWD3CH</name>
            <bitOffset>0</bitOffset>
            <bitWidth>19</bitWidth>
          </field>
        </fields>
      </register>
      <register>
        <name>DIFSEL</name>
        <addressOffset>0xb0</addressOffset>
        <size>0x20</size>
        <fields>
          <field>
            <name>DIFSEL</name>
            <bitOffset>0</bitOffset>
            <bitWidth>19</bitWidth>
          </field>
        </fields>
      </register>
      <register>
        <name>CALFACT</name>
        <addressOffset>0xb4</addressOffset>
        <size>0x20</size>
        <fields>
          <field>
            <name>CALFACT_S</name>
            <bitOffset>0</bitOffset>
            <bitWidth>7</bitWidth>
          </field>
          <field>
            <name>CALFACT_D</name>
            <bitOffset>16</bitOffset>
            <bitWidth>7</bitWidth>
          </field>
        </fields>
      </register>
    </peripheral>
    <peripheral>
      <name>ADC2</name>
      <baseAddress>0x50040100</baseAddress>
      <register>
        <name>ISR</name>
        <addressOffset>0x0</addressOffset>
        <size>0x20</size>
        <fields>
          <field>
            <name>ADRDY</name>
            <bitOffset>0</bitOffset>
            <bitWidth>1</bitWidth>
          </field>
          <field>
            <name>EOSMP</name>
            <bitOffset>1</bitOffset>
            <bitWidth>1</bitWidth>
          </field>
          <field>
            <name>EOC</name>
            <bitOffset>2</bitOffset>
            <bitWidth>1</bitWidth>
          </field>
          <field>
            <name>EOS</name>
            <bitOffset>3</bitOffset>
            <bitWidth>1</bitWidth>
          </field>
          <field>
            <name>OVR</name>
            <bitOffset>4</bitOffset>
            <bitWidth>1</bitWidth>
          </field>
          <field>
            <name>JEOC</name>
            <bitOffset>5</bitOffset>
            <bitWidth>1</bitWidth>
          </field>
          <field>
            <name>JEOS</name>
            <bitOffset>6</bitOffset>
            <bitWidth>1</bitWidth>
          </field>
          <field>
            <name>AWD1</name>
            <bitOffset>7</bitOffset>
            <bitWidth>1</bitWidth>
          </field>
          <field>
            <name>AWD2</name>
            <bitOffset>8</bitOffset>
            <bitWidth>1</bitWidth>
          </field>
          <field>
            <name>AWD3</name>
            <bitOffset>9</bitOffset>
            <bitWidth>1</bitWidth>
          </field>
          <field>
            <name>JQOVF</name>
            <bitOffset>10</bitOffset>
            <bitWidth>1</bitWidth>
          </field>
        </fields>
      </register>
      <register>
        <name>IER</name>
        <addressOffset>0x4</addressOffset>
        <size>0x20</size>
        <fields>
          <field>
            <name>ADRDYIE</name>
            <bitOffset>0</bitOffset>
            <bitWidth>1</bitWidth>
          </field>
          <field>
            <name>EOSMPIE</name>
            <bitOffset>1</bitOffset>
            <bitWidth>1</bitWidth>
          </field>
          <field>
            <name>EOCIE</name>
            <bitOffset>2</bitOffset>
            <bitWidth>1</bitWidth>
          </field>
          <field>
            <name>EOSIE</name>
            <bitOffset>3</bitOffset>
            <bitWidth>1</bitWidth>
          </field>
          <field>
            <name>OVRIE</name>
            <bitOffset>4</bitOffset>
            <bitWidth>1</bitWidth>
          </field>
          <field>
            <name>JEOCIE</name>
            <bitOffset>5</bitOffset>
            <bitWidth>1</bitWidth>
          </field>
          <field>
            <name>JEOSIE</name>
            <bitOffset>6</bitOffset>
            <bitWidth>1</bitWidth>
          </field>
          <field>
            <name>AWD1IE</name>
            <bitOffset>7</bitOffset>
            <bitWidth>1</bitWidth>
          </field>
          <field>
            <name>AWD2IE</name>
            <bitOffset>8</bitOffset>
            <bitWidth>1</bitWidth>
          </field>
          <field>
            <name>AWD3IE</name>
            <bitOffset>9</bitOffset>
            <bitWidth>1</bitWidth>
          </field>
          <field>
            <name>JQOVFIE</name>
            <bitOffset>10</bitOffset>
            <bitWidth>1</bitWidth>
          </field>
        </fields>
      </register>
      <register>
        <name>CR</name>
        <addressOffset>0x8</addressOffset>
        <size>0x20</size>
        <fields>
          <field>
            <name>ADEN</name>
            <bitOffset>0</bitOffset>
            <bitWidth>1</bitWidth>
          </field>
          <field>
            <name>ADDIS</name>
            <bitOffset>1</bitOffset>
            <bitWidth>1</bitWidth>
          </field>
          <field>
            <name>ADSTART</name>
            <bitOffset>2</bitOffset>
            <bitWidth>1</bitWidth>
          </field>
          <field>
            <name>JADSTART</name>
            <bitOffset>3</bitOffset>
            <bitWidth>1</bitWidth>
          </field>
          <field>
            <name>ADSTP</name>
            <bitOffset>4</bitOffset>
            <bitWidth>1</bitWidth>
          </field>
          <field>
            <name>JADSTP</name>
            <bitOffset>5</bitOffset>
            <bitWidth>1</bitWidth>
          </field>
          <field>
            <name>ADVREGEN</name>
            <bitOffset>28</bitOffset>
            <bitWidth>1</bitWidth>
          </field>
          <field>
            <name>DEEPPWD</name>
            <bitOffset>29</bitOffset>
            <bitWidth>1</bitWidth>
          </field>
          <field>
            <name>ADCALDIF</name>
            <bitOffset>30</bitOffset>
            <bitWidth>1</bitWidth>
          </field>
          <field>
            <name>ADCAL</name>
            <bitOffset>31</bitOffset>
            <bitWidth>1</bitWidth>
          </field>
        </fields>
      </register>
      <register>
        <name>CFGR</name>
        <addressOffset>0xc</addressOffset>
        <size>0x20</size>
        <fields>
          <field>
            <name>DMAEN</name>
            <bitOffset>0</bitOffset>
            <bitWidth>1</bitWidth>
          </field>
          <field>
            <name>DMACFG</name>
            <bitOffset>1</bitOffset>
            <bitWidth>1</bitWidth>
          </field>
          <field>
            <name>DFSDMCFG</name>
            <bitOffset>2</bitOffset>
            <bitWidth>1</bitWidth>
          </field>
          <field>
            <name>RES</name>
            <bitOffset>3</bitOffset>
            <bitWidth>2</bitWidth>
          </field>
          <field>
            <name>ALIGN</name>
            <bitOffset>5</bitOffset>
            <bitWidth>1</bitWidth>
          </field>
          <field>
            <name>EXTSEL</name>
            <bitOffset>6</bitOffset>
            <bitWidth>4</bitWidth>
          </field>
          <field>
            <name>EXTEN</name>
            <bitOffset>10</bitOffset>
            <bitWidth>2</bitWidth>
          </field>
          <field>
            <name>OVRMOD</name>
            <bitOffset>12</bitOffset>
            <bitWidth>1</bitWidth>
          </field>
          <field>
            <name>CONT</name>
            <bitOffset>13</bitOffset>
            <bitWidth>1</bitWidth>
          </field>
          <field>
            <name>AUTDLY</name>
            <bitOffset>14</bitOffset>
            <bitWidth>1</bitWidth>
          </field>
          <field>
            <name>DISCEN</name>
            <bitOffset>16</bitOffset>
            <bitWidth>1</bitWidth>
          </field>
          <field>
            <name>DISCNUM</name>
            <bitOffset>17</bitOffset>
            <bitWidth>3</bitWidth>
          </field>
          <field>
            <name>JDISCEN</name>
            <bitOffset>20</bitOffset>
            <bitWidth>1</bitWidth>
          </field>
          <field>
            <name>JQM</name>
            <bitOffset>21</bitOffset>
            <bitWidth>1</bitWidth>
          </field>
          <field>
            <name>AWD1SGL</name>
            <bitOffset>22</bitOffset>
            <bitWidth>1</bitWidth>
          </field>
          <field>
            <name>AWD1EN</name>
            <bitOffset>23</bitOffset>
            <bitWidth>1</bitWidth>
          </field>
          <field>
            <name>JAWD1EN</name>
            <bitOffset>24</bitOffset>
            <bitWidth>1</bitWidth>
          </field>
          <field>
            <name>JAUTO</name>
            <bitOffset>25</bitOffset>
            <bitWidth>1</bitWidth>
          </field>
          <field>
            <name>AWD1CH</name>
            <bitOffset>26</bitOffset>
            <bitWidth>5</bitWidth>
          </field>
          <field>
            <name>JQDIS</name>
            <bitOffset>31</bitOffset>
            <bitWidth>1</bitWidth>
          </field>
        </fields>
      </register>
      <register>
        <name>CFGR2</name>
        <addressOffset>0x10</addressOffset>
        <size>0x20</size>
        <fields>
          <field>
            <name>ROVSE</name>
            <bitOffset>0</bitOffset>
            <bitWidth>1</bitWidth>
          </field>
          <field>
            <name>JOVSE</name>
            <bitOffset>1</bitOffset>
            <bitWidth>1</bitWidth>
          </field>
          <field>
            <name>OVSR</name>
            <bitOffset>2</bitOffset>
            <bitWidth>3</bitWidth>
          </field>
          <field>
            <name>OVSS</name>
            <bitOffset>5</bitOffset>
            <bitWidth>4</bitWidth>
          </field>
          <field>
            <name>TROVS</name>
            <bitOffset>9</bitOffset>
            <bitWidth>1</bitWidth>
          </field>
          <field>
            <name>ROVSM</name>
            <bitOffset>10</bitOffset>
            <bitWidth>1</bitWidth>
          </field>
        </fields>
      </register>
      <register>
        <name>SMPR1</name>
        <addressOffset>0x14</addressOffset>
        <size>0x20</size>
        <fields>
          <field>
            <name>SMP0</name>
            <bitOffset>0</bitOffset>
            <bitWidth>3</bitWidth>
          </field>
          <field>
            <name>SMP1</name>
            <bitOffset>3</bitOffset>
            <bitWidth>3</bitWidth>
          </field>
          <field>
            <name>SMP2</name>
            <bitOffset>6</bitOffset>
            <bitWidth>3</bitWidth>
          </field>
          <field>
            <name>SMP3</name>
            <bitOffset>9</bitOffset>
            <bitWidth>3</bitWidth>
          </field>
          <field>
            <name>SMP4</name>
            <bitOffset>12</bitOffset>
            <bitWidth>3</bitWidth>
          </field>
          <field>
            <name>SMP5</name>
            <bitOffset>15</bitOffset>
            <bitWidth>3</bitWidth>
          </field>
          <field>
            <name>SMP6</name>
            <bitOffset>18</bitOffset>
            <bitWidth>3</bitWidth>
          </field>
          <field>
            <name>SMP7</name>
            <bitOffset>21</bitOffset>
            <bitWidth>3</bitWidth>
          </field>
          <field>
            <name>SMP8</name>
            <bitOffset>24</bitOffset>
            <bitWidth>3</bitWidth>
          </field>
          <field>
            <name>SMP9</name>
            <bitOffset>27</bitOffset>
            <bitWidth>3</bitWidth>
          </field>
          <field>
            <name>SMPPLUS</name>
            <bitOffset>31</bitOffset>
            <bitWidth>1</bitWidth>
          </field>
        </fields>
      </register>
      <register>
        <name>SMPR2</name>
        <addressOffset>0x18</addressOffset>
        <size>0x20</size>
        <fields>
          <field>
            <name>SMP10</name>
            <bitOffset>0</bitOffset>
            <bitWidth>3</bitWidth>
          </field>
          <field>
            <name>SMP11</name>
            <bitOffset>3</bitOffset>
            <bitWidth>3</bitWidth>
          </field>
          <field>
            <name>SMP12</name>
            <bitOffset>6</bitOffset>
            <bitWidth>3</bitWidth>
          </field>
          <field>
            <name>SMP13</name>
            <bitOffset>9</bitOffset>
            <bitWidth>3</bitWidth>
          </field>
          <field>
            <name>SMP14</name>
            <bitOffset>12</bitOffset>
            <bitWidth>3</bitWidth>
          </field>
          <field>
            <name>SMP15</name>
            <bitOffset>15</bitOffset>
            <bitWidth>3</bitWidth>
          </field>
          <field>
            <name>SMP16</name>
            <bitOffset>18</bitOffset>
            <bitWidth>3</bitWidth>
          </field>
          <field>
            <name>SMP17</name>
            <bitOffset>21</bitOffset>
            <bitWidth>3</bitWidth>
          </field>
          <field>
            <name>SMP18</name>
            <bitOffset>24</bitOffset>
            <bitWidth>3</bitWidth>
          </field>
        </fields>
      </register>
      <register>
        <name>TR1</name>
        <addressOffset>0x20</addressOffset>
        <size>0x20</size>
        <fields>
          <field>
            <name>LT1</name>
            <bitOffset>0</bitOffset>
            <bitWidth>12</bitWidth>
          </field>
          <field>
            <name>HT1</name>
            <bitOffset>16</bitOffset>
            <bitWidth>12</bitWidth>
          </field>
        </fields>
      </register>
      <register>
        <name>TR2</name>
        <addressOffset>0x24</addressOffset>
        <size>0x20</size>
        <fields>
          <field>
            <name>LT2</name>
            <bitOffset>0</bitOffset>
            <bitWidth>8</bitWidth>
          </field>
          <field>
            <name>HT2</name>
            <bitOffset>16</bitOffset>
            <bitWidth>8</bitWidth>
          </field>
        </fields>
      </register>
      <register>
        <name>TR3</name>
        <addressOffset>0x28</addressOffset>
        <size>0x20</size>
        <fields>
          <field>
            <name>LT3</name>
            <bitOffset>0</bitOffset>
            <bitWidth>8</bitWidth>
          </field>
          <field>
            <name>HT3</name>
            <bitOffset>16</bitOffset>
            <bitWidth>8</bitWidth>
          </field>
        </fields>
      </register>
      <register>
        <name>SQR1</name>
        <addressOffset>0x30</addressOffset>
        <size>0x20</size>
        <fields>
          <field>
            <name>L</name>
            <bitOffset>0</bitOffset>
            <bitWidth>4</bitWidth>
          </field>
          <field>
            <name>SQ1</name>
            <bitOffset>6</bitOffset>
            <bitWidth>5</bitWidth>
          </field>
          <field>
            <name>SQ2</name>
            <bitOffset>12</bitOffset>
            <bitWidth>5</bitWidth>
          </field>
          <field>
            <name>SQ3</name>
            <bitOffset>18</bitOffset>
            <bitWidth>5</bitWidth>
          </field>
          <field>
            <name>SQ4</name>
            <bitOffset>24</bitOffset>
            <bitWidth>5</bitWidth>
          </field>
        </fields>
      </register>
      <register>
        <name>SQR2</name>
        <addressOffset>0x34</addressOffset>
        <size>0x20</size>
        <fields>
          <field>
            <name>SQ5</name>
            <bitOffset>0</bitOffset>
            <bitWidth>5</bitWidth>
          </field>
          <field>
            <name>SQ6</name>
            <bitOffset>6</bitOffset>
            <bitWidth>5</bitWidth>
          </field>
          <field>
            <name>SQ7</name>
            <bitOffset>12</bitOffset>
            <bitWidth>5</bitWidth>
          </field>
          <field>
            <name>SQ8</name>
            <bitOffset>18</bitOffset>
            <bitWidth>5</bitWidth>
          </field>
          <field>
            <name>SQ9</name>
            <bitOffset>24</bitOffset>
            <bitWidth>5</bitWidth>
          </field>
        </fields>
      </register>
      <register>
        <name>SQR3</name>
        <addressOffset>0x38</addressOffset>
        <size>0x20</size>
        <fields>
          <field>
            <name>SQ10</name>
            <bitOffset>0</bitOffset>
            <bitWidth>5</bitWidth>
          </field>
          <field>
            <name>SQ11</name>
            <bitOffset>6</bitOffset>
            <bitWidth>5</bitWidth>
          </field>
          <field>
            <name>SQ12</name>
            <bitOffset>12</bitOffset>
            <bitWidth>5</bitWidth>
          </field>
          <field>
            <name>SQ13</name>
            <bitOffset>18</bitOffset>
            <bitWidth>5</bitWidth>
          </field>
          <field>
            <name>SQ14</name>
            <bitOffset>24</bitOffset>
            <bitWidth>5</bitWidth>
          </field>
        </fields>
      </register>
      <register>
        <name>SQR4</name>
        <addressOffset>0x3c</addressOffset>
        <size>0x20</size>
        <fields>
          <field>
            <name>SQ15</name>
            <bitOffset>0</bitOffset>
            <bitWidth>5</bitWidth>
          </field>
          <field>
            <name>SQ16</name>
            <bitOffset>6</bitOffset>
            <bitWidth>5</bitWidth>
          </field>
        </fields>
      </register>
      <register>
        <name>DR</name>
        <addressOffset>0x40</addressOffset>
        <size>0x20</size>
        <fields>
          <field>
            <name>RDATA</name>
            <bitOffset>0</bitOffset>
            <bitWidth>16</bitWidth>
          </field>
        </fields>
      </register>
      <register>
        <name>JSQR</name>
        <addressOffset>0x4c</addressOffset>
        <size>0x20</size>
        <fields>
          <field>
            <name>JL</name>
            <bitOffset>0</bitOffset>
            <bitWidth>2</bitWidth>
          </field>
          <field>
            <name>JEXTSEL</name>
            <bitOffset>2</bitOffset>
            <bitWidth>4</bitWidth>
          </field>
          <field>
            <name>JEXTEN</name>
            <bitOffset>6</bitOffset>
            <bitWidth>2</bitWidth>
          </field>
          <field>
            <name>JSQ1</name>
            <bitOffset>8</bitOffset>
            <bitWidth>5</bitWidth>
          </field>
          <field>
            <name>JSQ2</name>
            <bitOffset>14</bitOffset>
            <bitWidth>5</bitWidth>
          </field>
          <field>
            <name>JSQ3</name>
            <bitOffset>20</bitOffset>
            <bitWidth>5</bitWidth>
          </field>
          <field>
            <name>JSQ4</name>
            <bitOffset>26</bitOffset>
            <bitWidth>5</bitWidth>
          </field>
        </fields>
      </register>
      <register>
        <name>OFR1</name>
        <addressOffset>0x60</addressOffset>
        <size>0x20</size>
        <fields>
          <field>
            <name>OFFSET1</name>
            <bitOffset>0</bitOffset>
            <bitWidth>12</bitWidth>
          </field>
          <field>
            <name>OFFSET1_CH</name>
            <bitOffset>26</bitOffset>
            <bitWidth>5</bitWidth>
          </field>
          <field>
            <name>OFFSET1_EN</name>
            <bitOffset>31</bitOffset>
            <bitWidth>1</bitWidth>
          </field>
        </fields>
      </register>
      <register>
        <name>OFR2</name>
        <addressOffset>0x64</addressOffset>
        <size>0x20</size>
        <fields>
          <field>
            <name>OFFSET2</name>
            <bitOffset>0</bitOffset>
            <bitWidth>12</bitWidth>
          </field>
          <field>
            <name>OFFSET2_CH</name>
            <bitOffset>26</bitOffset>
            <bitWidth>5</bitWidth>
          </field>
          <field>
            <name>OFFSET2_EN</name>
            <bitOffset>31</bitOffset>
            <bitWidth>1</bitWidth>
          </field>
        </fields>
      </register>
      <register>
        <name>OFR3</name>
        <addressOffset>0x68</addressOffset>
        <size>0x20</size>
        <fields>
          <field>
            <name>OFFSET3</name>
            <bitOffset>0</bitOffset>
            <bitWidth>12</bitWidth>
          </field>
          <field>
            <name>OFFSET3_CH</name>
            <bitOffset>26</bitOffset>
            <bitWidth>5</bitWidth>
          </field>
          <field>
            <name>OFFSET3_EN</name>
            <bitOffset>31</bitOffset>
            <bitWidth>1</bitWidth>
          </field>
        </fields>
      </register>
      <register>
        <name>OFR4</name>
        <addressOffset>0x6c</addressOffset>
        <size>0x20</size>
        <fields>
          <field>
            <name>OFFSET4</name>
            <bitOffset>0</bitOffset>
            <bitWidth>12</bitWidth>
          </field>
          <field>
            <name>OFFSET4_CH</name>
            <bitOffset>26</bitOffset>
            <bitWidth>5</bitWidth>
          </field>
          <field>
            <name>OFFSET4_EN</name>
            <bitOffset>31</bitOffset>
            <bitWidth>1</bitWidth>
          </field>
        </fields>
      </register>
      <register>
        <name>JDR1</name>
        <addressOffset>0x80</addressOffset>
        <size>0x20</size>
        <fields>
          <field>
            <name>JDATA</name>
            <bitOffset>0</bitOffset>
            <bitWidth>16</bitWidth>
          </field>
        </fields>
      </register>
      <register>
        <name>JDR2</name>
        <addressOffset>0x84</addressOffset>
        <size>0x20</size>
        <fields>
          <field>
            <name>JDATA</name>
            <bitOffset>0</bitOffset>
            <bitWidth>16</bitWidth>
          </field>
        </fields>
      </register>
      <register>
        <name>JDR3</name>
        <addressOffset>0x88</addressOffset>
        <size>0x20</size>
        <fields>
          <field>
            <name>JDATA</name>
            <bitOffset>0</bitOffset>
            <bitWidth>16</bitWidth>
          </field>
        </fields>
      </register>
      <register>
        <name>JDR4</name>
        <addressOffset>0x8c</addressOffset>
        <size>0x20</size>
        <fields>
          <field>
            <name>JDATA</name>
            <bitOffset>0</bitOffset>
            <bitWidth>16</bitWidth>
          </field>
        </fields>
      </register>
      <register>
        <name>AWD2CR</name>
        <addressOffset>0xa0</addressOffset>
        <size>0x20</size>
        <fields>
          <field>
            <name>AWD2CH</name>
            <bitOffset>0</bitOffset>
            <bitWidth>19</bitWidth>
          </field>
        </fields>
      </register>
      <register>
        <name>AWD3CR</name>
        <addressOffset>0xa4</addressOffset>
        <size>0x20</size>
        <fields>
          <field>
            <name>AWD3CH</name>
            <bitOffset>0</bitOffset>
            <bitWidth>19</bitWidth>
          </field>
        </fields>
      </register>
      <register>
        <name>DIFSEL</name>
        <addressOffset>0xb0</addressOffset>
        <size>0x20</size>
        <fields>
          <field>
            <name>DIFSEL</name>
            <bitOffset>0</bitOffset>
            <bitWidth>19</bitWidth>
          </field>
        </fields>
      </register>
      <register>
        <name>CALFACT</name>
        <addressOffset>0xb4</addressOffset>
        <size>0x20</size>
        <fields>
          <field>
            <name>CALFACT_S</name>
            <bitOffset>0</bitOffset>
            <bitWidth>7</bitWidth>
          </field>
          <field>
            <name>CALFACT_D</name>
            <bitOffset>16</bitOffset>
            <bitWidth>7</bitWidth>
          </field>
        </fields>
      </register>
    </peripheral>
    <peripheral>
      <name>ADC12_COMMON</name>
      <baseAddress>0x50040300</baseAddress>
      <register>
        <name>CSR</name>
        <addressOffset>0x0</addressOffset>
        <size>0x20</size>
        <fields>
          <field>
            <name>ADRDY_MST</name>
            <bitOffset>0</bitOffset>
            <bitWidth>1</bitWidth>
          </field>
          <field>
            <name>EOSMP_MST</name>
            <bitOffset>1</bitOffset>
            <bitWidth>1</bitWidth>
          </field>
          <field>
            <name>EOC_MST</name>
            <bitOffset>2</bitOffset>
            <bitWidth>1</bitWidth>
          </field>
          <field>
            <name>EOS_MST</name>
            <bitOffset>3</bitOffset>
            <bitWidth>1</bitWidth>
          </field>
          <field>
            <name>OVR_MST</name>
            <bitOffset>4</bitOffset>
            <bitWidth>1</bitWidth>
          </field>
          <field>
            <name>JEOC_MST</name>
            <bitOffset>5</bitOffset>
            <bitWidth>1</bitWidth>
          </field>
          <field>
            <name>JEOS_MST</name>
            <bitOffset>6</bitOffset>
            <bitWidth>1</bitWidth>
          </field>
          <field>
            <name>AWD1_MST</name>
            <bitOffset>7</bitOffset>
            <bitWidth>1</bitWidth>
          </field>
          <field>
            <name>AWD2_MST</name>
            <bitOffset>8</bitOffset>
            <bitWidth>1</bitWidth>
          </field>
          <field>
            <name>AWD3_MST</name>
            <bitOffset>9</bitOffset>
            <bitWidth>1</bitWidth>
          </field>
          <field>
            <name>JQOVF_MST</name>
            <bitOffset>10</bitOffset>
            <bitWidth>1</bitWidth>
          </field>
          <field>
            <name>ADRDY_SLV</name>
            <bitOffset>16</bitOffset>
            <bitWidth>1</bitWidth>
          </field>
          <field>
            <name>EOSMP_SLV</name>
            <bitOffset>17</bitOffset>
            <bitWidth>1</bitWidth>
          </field>
          <field>
            <name>EOC_SLV</name>
            <bitOffset>18</bitOffset>
            <bitWidth>1</bitWidth>
          </field>
          <field>
            <name>EOS_SLV</name>
            <bitOffset>19</bitOffset>
            <bitWidth>1</bitWidth>
          </field>
          <field>
            <name>OVR_SLV</name>
            <bitOffset>20</bitOffset>
            <bitWidth>1</bitWidth>
          </field>
          <field>
            <name>JEOC_SLV</name>
            <bitOffset>21</bitOffset>
            <bitWidth>1</bitWidth>
          </field>
          <field>
            <name>JEOS_SLV</name>
            <bitOffset>22</bitOffset>
            <bitWidth>1</bitWidth>
          </field>
          <field>
            <name>AWD1_SLV</name>
            <bitOffset>23</bitOffset>
            <bitWidth>1</bitWidth>
          </field>
          <field>
            <name>AWD2_SLV</name>
            <bitOffset>24</bitOffset>
            <bitWidth>1</bitWidth>
          </field>
          <field>
            <name>AWD3_SLV</name>
            <bitOffset>25</bitOffset>
            <bitWidth>1</bitWidth>
          </field>
          <field>
            <name>JQOVF_SLV</name>
            <bitOffset>26</bitOffset>
            <bitWidth>1</bitWidth>
          </field>
        </fields>
      </register>
      <register>
        <name>CCR</name>
        <addressOffset>0x8</addressOffset>
        <size>0x20</size>
        <fields>
          <field>
            <name>DUAL</name>
            <bitOffset>0</bitOffset>
            <bitWidth>5</bitWidth>
          </field>
          <field>
            <name>DELAY</name>
            <bitOffset>8</bitOffset>
            <bitWidth>4</bitWidth>
          </field>
          <field>
            <name>DMACFG</name>
            <bitOffset>13</bitOffset>
            <bitWidth>1</bitWidth>
          </field>
          <field>
            <name>MDMA</name>
            <bitOffset>14</bitOffset>
            <bitWidth>2</bitWidth>
          </field>
          <field>
            <name>CKMODE</name>
            <bitOffset>16</bitOffset>
            <bitWidth>2</bitWidth>
          </field>
          <field>
            <name>PRESC</name>
            <bitOffset>18</bitOffset>
            <bitWidth>4</bitWidth>
          </field>
          <field>
            <name>VREFEN</name>
            <bitOffset>22</bitOffset>
            <bitWidth>1</bitWidth>
          </field>
          <field>
            <name>TSEN</name>
            <bitOffset>23</bitOffset>
            <bitWidth>1</bitWidth>
          </field>
          <field>
            <name>VBATEN</name>
            <bitOffset>24</bitOffset>
            <bitWidth>1</bitWidth>
          </field>
        </fields>
      </register>
      <register>
        <name>CDR</name>
        <addressOffset>0xc</addressOffset>
        <size>0x20</size>
        <fields>
          <field>
            <name>RDATA_MST</name>
            <bitOffset>0</bitOffset>
            <bitWidth>16</bitWidth>
          </field>
          <field>
            <name>RDATA_SLV</name>
            <bitOffset>16</bitOffset>
            <bitWidth>16</bitWidth>
          </field>
        </fields>
      </register>
    </peripheral>
    <peripheral>
      <name>DCMI</name>
      <baseAddress>0x50050000</baseAddress>
      <register>
        <name>CR</name>
        <addressOffset>0x0</addressOffset>
        <size>0x20</size>
        <fields>
          <field>
            <name>CAPTURE</name>
            <bitOffset>0</bitOffset>
            <bitWidth>1</bitWidth>
          </field>
          <field>
            <name>CM</name>
            <bitOffset>1</bitOffset>
            <bitWidth>1</bitWidth>
          </field>
          <field>
            <name>CROP</name>
            <bitOffset>2</bitOffset>
            <bitWidth>1</bitWidth>
          </field>
          <field>
            <name>JPEG</name>
            <bitOffset>3</bitOffset>
            <bitWidth>1</bitWidth>
          </field>
          <field>
            <name>ESS</name>
            <bitOffset>4</bitOffset>
            <bitWidth>1</bitWidth>
          </field>
          <field>
            <name>PCKPOL</name>
            <bitOffset>5</bitOffset>
            <bitWidth>1</bitWidth>
          </field>
          <field>
            <name>HSPOL</name>
            <bitOffset>6</bitOffset>
            <bitWidth>1</bitWidth>
          </field>
          <field>
            <name>VSPOL</name>
            <bitOffset>7</bitOffset>
            <bitWidth>1</bitWidth>
          </field>
          <field>
            <name>FCRC</name>
            <bitOffset>8</bitOffset>
            <bitWidth>2</bitWidth>
          </field>
          <field>
            <name>EDM</name>
            <bitOffset>10</bitOffset>
            <bitWidth>2</bitWidth>
          </field>
          <field>
            <name>ENABLE</name>
            <bitOffset>14</bitOffset>
            <bitWidth>1</bitWidth>
          </field>
          <field>
            <name>BSM</name>
            <bitOffset>16</bitOffset>
            <bitWidth>2</bitWidth>
          </field>
          <field>
            <name>OEBS</name>
            <bitOffset>18</bitOffset>
            <bitWidth>1</bitWidth>
          </field>
          <field>
            <name>LSM</name>
            <bitOffset>19</bitOffset>
            <bitWidth>1</bitWidth>
          </field>
          <field>
            <name>OELS</name>
            <bitOffset>20</bitOffset>
            <bitWidth>1</bitWidth>
          </field>
        </fields>
      </register>
      <register>
        <name>SR</name>
        <addressOffset>0x4</addressOffset>
        <size>0x20</size>
        <fields>
          <field>
            <name>HSYNC</name>
            <bitOffset>0</bitOffset>
            <bitWidth>1</bitWidth>
          </field>
          <field>
            <name>VSYNC</name>
            <bitOffset>1</bitOffset>
            <bitWidth>1</bitWidth>
          </field>
          <field>
            <name>FNE</name>
            <bitOffset>2</bitOffset>
            <bitWidth>1</bitWidth>
          </field>
        </fields>
      </register>
      <register>
        <name>RISR</name>
        <addressOffset>0x8</addressOffset>
        <size>0x20</size>
      </register>
      <register>
        <name>IER</name>
        <addressOffset>0xc</addressOffset>
        <size>0x20</size>
        <fields>
          <field>
            <name>INT_IE</name>
            <bitOffset>0</bitOffset>
            <bitWidth>5</bitWidth>
          </field>
          <field>
            <name>OVR_IE</name>
            <bitOffset>1</bitOffset>
            <bitWidth>1</bitWidth>
          </field>
          <field>
            <name>ERR_IE</name>
            <bitOffset>2</bitOffset>
            <bitWidth>1</bitWidth>
          </field>
          <field>
            <name>VSYNC_IE</name>
            <bitOffset>3</bitOffset>
            <bitWidth>1</bitWidth>
          </field>
          <field>
            <name>LINE_IE</name>
            <bitOffset>4</bitOffset>
            <bitWidth>1</bitWidth>
          </field>
        </fields>
      </register>
      <register>
        <name>MISR</name>
        <addressOffset>0x10</addressOffset>
        <size>0x20</size>
      </register>
      <register>
        <name>ICR</name>
        <addressOffset>0x14</addressOffset>
        <size>0x20</size>
        <fields>
          <field>
            <name>FRAME_ISC</name>
            <bitOffset>0</bitOffset>
            <bitWidth>1</bitWidth>
          </field>
          <field>
            <name>OVR_ISC</name>
            <bitOffset>1</bitOffset>
            <bitWidth>1</bitWidth>
          </field>
          <field>
            <name>ERR_ISC</name>
            <bitOffset>2</bitOffset>
            <bitWidth>1</bitWidth>
          </field>
          <field>
            <name>VSYNC_ISC</name>
            <bitOffset>3</bitOffset>
            <bitWidth>1</bitWidth>
          </field>
          <field>
            <name>LINE_ISC</name>
            <bitOffset>4</bitOffset>
            <bitWidth>1</bitWidth>
          </field>
        </fields>
      </register>
      <register>
        <name>ESCR</name>
        <addressOffset>0x18</addressOffset>
        <size>0x20</size>
        <fields>
          <field>
            <name>FSC</name>
            <bitOffset>0</bitOffset>
            <bitWidth>8</bitWidth>
          </field>
          <field>
            <name>LSC</name>
            <bitOffset>8</bitOffset>
            <bitWidth>8</bitWidth>
          </field>
          <field>
            <name>LEC</name>
            <bitOffset>16</bitOffset>
            <bitWidth>8</bitWidth>
          </field>
          <field>
            <name>FEC</name>
            <bitOffset>24</bitOffset>
            <bitWidth>8</bitWidth>
          </field>
        </fields>
      </register>
      <register>
        <name>ESUR</name>
        <addressOffset>0x1c</addressOffset>
        <size>0x20</size>
        <fields>
          <field>
            <name>FSU</name>
            <bitOffset>0</bitOffset>
            <bitWidth>8</bitWidth>
          </field>
          <field>
            <name>LSU</name>
            <bitOffset>8</bitOffset>
            <bitWidth>8</bitWidth>
          </field>
          <field>
            <name>LEU</name>
            <bitOffset>16</bitOffset>
            <bitWidth>8</bitWidth>
          </field>
          <field>
            <name>FEU</name>
            <bitOffset>24</bitOffset>
            <bitWidth>8</bitWidth>
          </field>
        </fields>
      </register>
      <register>
        <name>CWSTRTR</name>
        <addressOffset>0x20</addressOffset>
        <size>0x20</size>
      </register>
      <register>
        <name>CWSIZER</name>
        <addressOffset>0x24</addressOffset>
        <size>0x20</size>
      </register>
      <register>
        <name>DR</name>
        <addressOffset>0x28</addressOffset>
        <size>0x20</size>
        <fields>
          <field>
            <name>BYTE0</name>
            <bitOffset>0</bitOffset>
            <bitWidth>8</bitWidth>
          </field>
          <field>
            <name>BYTE1</name>
            <bitOffset>8</bitOffset>
            <bitWidth>8</bitWidth>
          </field>
          <field>
            <name>BYTE2</name>
            <bitOffset>16</bitOffset>
            <bitWidth>8</bitWidth>
          </field>
          <field>
            <name>BYTE3</name>
            <bitOffset>24</bitOffset>
            <bitWidth>8</bitWidth>
          </field>
        </fields>
      </register>
    </peripheral>
    <peripheral>
      <name>PSSI</name>
      <baseAddress>0x50050400</baseAddress>
      <register>
        <name>CR</name>
        <addressOffset>0x0</addressOffset>
        <size>0x20</size>
        <fields>
          <field>
            <name>CKPOL</name>
            <bitOffset>5</bitOffset>
            <bitWidth>1</bitWidth>
          </field>
          <field>
            <name>DEPOL</name>
            <bitOffset>6</bitOffset>
            <bitWidth>1</bitWidth>
          </field>
          <field>
            <name>RDYPOL</name>
            <bitOffset>8</bitOffset>
            <bitWidth>1</bitWidth>
          </field>
          <field>
            <name>EDM</name>
            <bitOffset>10</bitOffset>
            <bitWidth>2</bitWidth>
          </field>
          <field>
            <name>ENABLE</name>
            <bitOffset>14</bitOffset>
            <bitWidth>1</bitWidth>
          </field>
          <field>
            <name>DERDYCFG</name>
            <bitOffset>18</bitOffset>
            <bitWidth>3</bitWidth>
          </field>
          <field>
            <name>DMAEN</name>
            <bitOffset>30</bitOffset>
            <bitWidth>1</bitWidth>
          </field>
          <field>
            <name>OUTEN</name>
            <bitOffset>31</bitOffset>
            <bitWidth>1</bitWidth>
          </field>
        </fields>
      </register>
      <register>
        <name>SR</name>
        <addressOffset>0x4</addressOffset>
        <size>0x20</size>
        <fields>
          <field>
            <name>RTT4B</name>
            <bitOffset>2</bitOffset>
            <bitWidth>1</bitWidth>
          </field>
          <field>
            <name>RTT1B</name>
            <bitOffset>3</bitOffset>
            <bitWidth>1</bitWidth>
          </field>
        </fields>
      </register>
      <register>
        <name>RIS</name>
        <addressOffset>0x8</addressOffset>
        <size>0x20</size>
        <fields>
          <field>
            <name>OVR_RIS</name>
            <bitOffset>1</bitOffset>
            <bitWidth>1</bitWidth>
          </field>
        </fields>
      </register>
      <register>
        <name>IER</name>
        <addressOffset>0xc</addressOffset>
        <size>0x20</size>
        <fields>
          <field>
            <name>OVR_IE</name>
            <bitOffset>1</bitOffset>
            <bitWidth>1</bitWidth>
          </field>
        </fields>
      </register>
      <register>
        <name>MIS</name>
        <addressOffset>0x10</addressOffset>
        <size>0x20</size>
        <fields>
          <field>
            <name>OVR_MIS</name>
            <bitOffset>1</bitOffset>
            <bitWidth>1</bitWidth>
          </field>
        </fields>
      </register>
      <register>
        <name>ICR</name>
        <addressOffset>0x14</addressOffset>
        <size>0x20</size>
        <fields>
          <field>
            <name>OVR_ISC</name>
            <bitOffset>1</bitOffset>
            <bitWidth>1</bitWidth>
          </field>
        </fields>
      </register>
      <register>
        <name>DR</name>
        <addressOffset>0x28</addressOffset>
        <size>0x20</size>
        <fields>
          <field>
            <name>BYTE0</name>
            <bitOffset>0</bitOffset>
            <bitWidth>8</bitWidth>
          </field>
          <field>
            <name>BYTE1</name>
            <bitOffset>8</bitOffset>
            <bitWidth>8</bitWidth>
          </field>
          <field>
            <name>BYTE2</name>
            <bitOffset>16</bitOffset>
            <bitWidth>8</bitWidth>
          </field>
          <field>
            <name>BYTE3</name>
            <bitOffset>24</bitOffset>
            <bitWidth>8</bitWidth>
          </field>
        </fields>
      </register>
      <register>
        <name>HWCFGR</name>
        <addressOffset>0x3f0</addressOffset>
        <size>0x20</size>
      </register>
      <register>
        <name>VERR</name>
        <addressOffset>0x3f4</addressOffset>
        <size>0x20</size>
      </register>
      <register>
        <name>IPIDR</name>
        <addressOffset>0x3f8</addressOffset>
        <size>0x20</size>
      </register>
      <register>
        <name>SIDR</name>
        <addressOffset>0x3fc</addressOffset>
        <size>0x20</size>
      </register>
    </peripheral>
    <peripheral>
      <name>HASH</name>
      <baseAddress>0x50060400</baseAddress>
      <register>
        <name>CR</name>
        <addressOffset>0x0</addressOffset>
        <size>0x20</size>
        <fields>
          <field>
            <name>INIT</name>
            <bitOffset>2</bitOffset>
            <bitWidth>1</bitWidth>
          </field>
          <field>
            <name>DMAE</name>
            <bitOffset>3</bitOffset>
            <bitWidth>1</bitWidth>
          </field>
          <field>
            <name>DATATYPE</name>
            <bitOffset>4</bitOffset>
            <bitWidth>2</bitWidth>
          </field>
          <field>
            <name>MODE</name>
            <bitOffset>6</bitOffset>
            <bitWidth>1</bitWidth>
          </field>
          <field>
            <name>ALGO</name>
            <bitOffset>7</bitOffset>
            <bitWidth>12</bitWidth>
          </field>
          <field>
            <name>NBW</name>
            <bitOffset>8</bitOffset>
            <bitWidth>4</bitWidth>
          </field>
          <field>
            <name>DINNE</name>
            <bitOffset>12</bitOffset>
            <bitWidth>1</bitWidth>
          </field>
          <field>
            <name>MDMAT</name>
            <bitOffset>13</bitOffset>
            <bitWidth>1</bitWidth>
          </field>
          <field>
            <name>LKEY</name>
            <bitOffset>16</bitOffset>
            <bitWidth>1</bitWidth>
          </field>
        </fields>
      </register>
      <register>
        <name>DIN</name>
        <addressOffset>0x4</addressOffset>
        <size>0x20</size>
      </register>
      <register>
        <name>STR</name>
        <addressOffset>0x8</addressOffset>
        <size>0x20</size>
        <fields>
          <field>
            <name>NBLW</name>
            <bitOffset>0</bitOffset>
            <bitWidth>5</bitWidth>
          </field>
          <field>
            <name>DCAL</name>
            <bitOffset>8</bitOffset>
            <bitWidth>1</bitWidth>
          </field>
        </fields>
      </register>
      <register>
        <name>HR.0</name>
        <addressOffset>0xc</addressOffset>
        <size>0x20</size>
      </register>
      <register>
        <name>HR.1</name>
        <addressOffset>0x10</addressOffset>
        <size>0x20</size>
      </register>
      <register>
        <name>HR.2</name>
        <addressOffset>0x14</addressOffset>
        <size>0x20</size>
      </register>
      <register>
        <name>HR.3</name>
        <addressOffset>0x18</addressOffset>
        <size>0x20</size>
      </register>
      <register>
        <name>HR.4</name>
        <addressOffset>0x1c</addressOffset>
        <size>0x20</size>
      </register>
      <register>
        <name>IMR</name>
        <addressOffset>0x20</addressOffset>
        <size>0x20</size>
        <fields>
          <field>
            <name>DINIE</name>
            <bitOffset>0</bitOffset>
            <bitWidth>1</bitWidth>
          </field>
          <field>
            <name>DCIE</name>
            <bitOffset>1</bitOffset>
            <bitWidth>1</bitWidth>
          </field>
        </fields>
      </register>
      <register>
        <name>SR</name>
        <addressOffset>0x24</addressOffset>
        <size>0x20</size>
        <fields>
          <field>
            <name>DINIS</name>
            <bitOffset>0</bitOffset>
            <bitWidth>1</bitWidth>
          </field>
          <field>
            <name>DCIS</name>
            <bitOffset>1</bitOffset>
            <bitWidth>1</bitWidth>
          </field>
          <field>
            <name>DMAS</name>
            <bitOffset>2</bitOffset>
            <bitWidth>1</bitWidth>
          </field>
          <field>
            <name>BUSY</name>
            <bitOffset>3</bitOffset>
            <bitWidth>1</bitWidth>
          </field>
        </fields>
      </register>
      <register>
        <name>CSR.0</name>
        <addressOffset>0xf8</addressOffset>
        <size>0x20</size>
      </register>
      <register>
        <name>CSR.1</name>
        <addressOffset>0xfc</addressOffset>
        <size>0x20</size>
      </register>
      <register>
        <name>CSR.2</name>
        <addressOffset>0x100</addressOffset>
        <size>0x20</size>
      </register>
      <register>
        <name>CSR.3</name>
        <addressOffset>0x104</addressOffset>
        <size>0x20</size>
      </register>
      <register>
        <name>CSR.4</name>
        <addressOffset>0x108</addressOffset>
        <size>0x20</size>
      </register>
      <register>
        <name>CSR.5</name>
        <addressOffset>0x10c</addressOffset>
        <size>0x20</size>
      </register>
      <register>
        <name>CSR.6</name>
        <addressOffset>0x110</addressOffset>
        <size>0x20</size>
      </register>
      <register>
        <name>CSR.7</name>
        <addressOffset>0x114</addressOffset>
        <size>0x20</size>
      </register>
      <register>
        <name>CSR.8</name>
        <addressOffset>0x118</addressOffset>
        <size>0x20</size>
      </register>
      <register>
        <name>CSR.9</name>
        <addressOffset>0x11c</addressOffset>
        <size>0x20</size>
      </register>
      <register>
        <name>CSR.10</name>
        <addressOffset>0x120</addressOffset>
        <size>0x20</size>
      </register>
      <register>
        <name>CSR.11</name>
        <addressOffset>0x124</addressOffset>
        <size>0x20</size>
      </register>
      <register>
        <name>CSR.12</name>
        <addressOffset>0x128</addressOffset>
        <size>0x20</size>
      </register>
      <register>
        <name>CSR.13</name>
        <addressOffset>0x12c</addressOffset>
        <size>0x20</size>
      </register>
      <register>
        <name>CSR.14</name>
        <addressOffset>0x130</addressOffset>
        <size>0x20</size>
      </register>
      <register>
        <name>CSR.15</name>
        <addressOffset>0x134</addressOffset>
        <size>0x20</size>
      </register>
      <register>
        <name>CSR.16</name>
        <addressOffset>0x138</addressOffset>
        <size>0x20</size>
      </register>
      <register>
        <name>CSR.17</name>
        <addressOffset>0x13c</addressOffset>
        <size>0x20</size>
      </register>
      <register>
        <name>CSR.18</name>
        <addressOffset>0x140</addressOffset>
        <size>0x20</size>
      </register>
      <register>
        <name>CSR.19</name>
        <addressOffset>0x144</addressOffset>
        <size>0x20</size>
      </register>
      <register>
        <name>CSR.20</name>
        <addressOffset>0x148</addressOffset>
        <size>0x20</size>
      </register>
      <register>
        <name>CSR.21</name>
        <addressOffset>0x14c</addressOffset>
        <size>0x20</size>
      </register>
      <register>
        <name>CSR.22</name>
        <addressOffset>0x150</addressOffset>
        <size>0x20</size>
      </register>
      <register>
        <name>CSR.23</name>
        <addressOffset>0x154</addressOffset>
        <size>0x20</size>
      </register>
      <register>
        <name>CSR.24</name>
        <addressOffset>0x158</addressOffset>
        <size>0x20</size>
      </register>
      <register>
        <name>CSR.25</name>
        <addressOffset>0x15c</addressOffset>
        <size>0x20</size>
      </register>
      <register>
        <name>CSR.26</name>
        <addressOffset>0x160</addressOffset>
        <size>0x20</size>
      </register>
      <register>
        <name>CSR.27</name>
        <addressOffset>0x164</addressOffset>
        <size>0x20</size>
      </register>
      <register>
        <name>CSR.28</name>
        <addressOffset>0x168</addressOffset>
        <size>0x20</size>
      </register>
      <register>
        <name>CSR.29</name>
        <addressOffset>0x16c</addressOffset>
        <size>0x20</size>
      </register>
      <register>
        <name>CSR.30</name>
        <addressOffset>0x170</addressOffset>
        <size>0x20</size>
      </register>
      <register>
        <name>CSR.31</name>
        <addressOffset>0x174</addressOffset>
        <size>0x20</size>
      </register>
      <register>
        <name>CSR.32</name>
        <addressOffset>0x178</addressOffset>
        <size>0x20</size>
      </register>
      <register>
        <name>CSR.33</name>
        <addressOffset>0x17c</addressOffset>
        <size>0x20</size>
      </register>
      <register>
        <name>CSR.34</name>
        <addressOffset>0x180</addressOffset>
        <size>0x20</size>
      </register>
      <register>
        <name>CSR.35</name>
        <addressOffset>0x184</addressOffset>
        <size>0x20</size>
      </register>
      <register>
        <name>CSR.36</name>
        <addressOffset>0x188</addressOffset>
        <size>0x20</size>
      </register>
      <register>
        <name>CSR.37</name>
        <addressOffset>0x18c</addressOffset>
        <size>0x20</size>
      </register>
      <register>
        <name>CSR.38</name>
        <addressOffset>0x190</addressOffset>
        <size>0x20</size>
      </register>
      <register>
        <name>CSR.39</name>
        <addressOffset>0x194</addressOffset>
        <size>0x20</size>
      </register>
      <register>
        <name>CSR.40</name>
        <addressOffset>0x198</addressOffset>
        <size>0x20</size>
      </register>
      <register>
        <name>CSR.41</name>
        <addressOffset>0x19c</addressOffset>
        <size>0x20</size>
      </register>
      <register>
        <name>CSR.42</name>
        <addressOffset>0x1a0</addressOffset>
        <size>0x20</size>
      </register>
      <register>
        <name>CSR.43</name>
        <addressOffset>0x1a4</addressOffset>
        <size>0x20</size>
      </register>
      <register>
        <name>CSR.44</name>
        <addressOffset>0x1a8</addressOffset>
        <size>0x20</size>
      </register>
      <register>
        <name>CSR.45</name>
        <addressOffset>0x1ac</addressOffset>
        <size>0x20</size>
      </register>
      <register>
        <name>CSR.46</name>
        <addressOffset>0x1b0</addressOffset>
        <size>0x20</size>
      </register>
      <register>
        <name>CSR.47</name>
        <addressOffset>0x1b4</addressOffset>
        <size>0x20</size>
      </register>
      <register>
        <name>CSR.48</name>
        <addressOffset>0x1b8</addressOffset>
        <size>0x20</size>
      </register>
      <register>
        <name>CSR.49</name>
        <addressOffset>0x1bc</addressOffset>
        <size>0x20</size>
      </register>
      <register>
        <name>CSR.50</name>
        <addressOffset>0x1c0</addressOffset>
        <size>0x20</size>
      </register>
      <register>
        <name>CSR.51</name>
        <addressOffset>0x1c4</addressOffset>
        <size>0x20</size>
      </register>
      <register>
        <name>CSR.52</name>
        <addressOffset>0x1c8</addressOffset>
        <size>0x20</size>
      </register>
      <register>
        <name>CSR.53</name>
        <addressOffset>0x1cc</addressOffset>
        <size>0x20</size>
      </register>
    </peripheral>
    <peripheral>
      <name>HASH_DIGEST</name>
      <baseAddress>0x50060710</baseAddress>
      <register>
        <name>HR.0</name>
        <addressOffset>0x0</addressOffset>
        <size>0x20</size>
      </register>
      <register>
        <name>HR.1</name>
        <addressOffset>0x4</addressOffset>
        <size>0x20</size>
      </register>
      <register>
        <name>HR.2</name>
        <addressOffset>0x8</addressOffset>
        <size>0x20</size>
      </register>
      <register>
        <name>HR.3</name>
        <addressOffset>0xc</addressOffset>
        <size>0x20</size>
      </register>
      <register>
        <name>HR.4</name>
        <addressOffset>0x10</addressOffset>
        <size>0x20</size>
      </register>
      <register>
        <name>HR.5</name>
        <addressOffset>0x14</addressOffset>
        <size>0x20</size>
      </register>
      <register>
        <name>HR.6</name>
        <addressOffset>0x18</addressOffset>
        <size>0x20</size>
      </register>
      <register>
        <name>HR.7</name>
        <addressOffset>0x1c</addressOffset>
        <size>0x20</size>
      </register>
    </peripheral>
    <peripheral>
      <name>RNG</name>
      <baseAddress>0x50060800</baseAddress>
      <register>
        <name>CR</name>
        <addressOffset>0x0</addressOffset>
        <size>0x20</size>
        <fields>
          <field>
            <name>RNGEN</name>
            <bitOffset>2</bitOffset>
            <bitWidth>1</bitWidth>
          </field>
          <field>
            <name>IE</name>
            <bitOffset>3</bitOffset>
            <bitWidth>1</bitWidth>
          </field>
          <field>
            <name>CED</name>
            <bitOffset>5</bitOffset>
            <bitWidth>1</bitWidth>
          </field>
          <field>
            <name>RNG_CONFIG3</name>
            <bitOffset>8</bitOffset>
            <bitWidth>4</bitWidth>
          </field>
          <field>
            <name>NISTC</name>
            <bitOffset>12</bitOffset>
            <bitWidth>1</bitWidth>
          </field>
          <field>
            <name>RNG_CONFIG2</name>
            <bitOffset>13</bitOffset>
            <bitWidth>3</bitWidth>
          </field>
          <field>
            <name>CLKDIV</name>
            <bitOffset>16</bitOffset>
            <bitWidth>4</bitWidth>
          </field>
          <field>
            <name>RNG_CONFIG1</name>
            <bitOffset>20</bitOffset>
            <bitWidth>6</bitWidth>
          </field>
          <field>
            <name>CONDRST</name>
            <bitOffset>30</bitOffset>
            <bitWidth>1</bitWidth>
          </field>
          <field>
            <name>CONFIGLOCK</name>
            <bitOffset>31</bitOffset>
            <bitWidth>1</bitWidth>
          </field>
        </fields>
      </register>
      <register>
        <name>SR</name>
        <addressOffset>0x4</addressOffset>
        <size>0x20</size>
        <fields>
          <field>
            <name>DRDY</name>
            <bitOffset>0</bitOffset>
            <bitWidth>1</bitWidth>
          </field>
          <field>
            <name>CECS</name>
            <bitOffset>1</bitOffset>
            <bitWidth>1</bitWidth>
          </field>
          <field>
            <name>SECS</name>
            <bitOffset>2</bitOffset>
            <bitWidth>1</bitWidth>
          </field>
          <field>
            <name>CEIS</name>
            <bitOffset>5</bitOffset>
            <bitWidth>1</bitWidth>
          </field>
          <field>
            <name>SEIS</name>
            <bitOffset>6</bitOffset>
            <bitWidth>1</bitWidth>
          </field>
        </fields>
      </register>
      <register>
        <name>DR</name>
        <addressOffset>0x8</addressOffset>
        <size>0x20</size>
      </register>
      <register>
        <name>HTCR</name>
        <addressOffset>0x10</addressOffset>
        <size>0x20</size>
      </register>
    </peripheral>
    <peripheral>
      <name>OCTOSPIM</name>
      <baseAddress>0x50061c00</baseAddress>
      <register>
        <name>CR</name>
        <addressOffset>0x0</addressOffset>
        <size>0x20</size>
        <fields>
          <field>
            <name>MUXEN</name>
            <bitOffset>0</bitOffset>
            <bitWidth>1</bitWidth>
          </field>
          <field>
            <name>REQ2ACK_TIME</name>
            <bitOffset>16</bitOffset>
            <bitWidth>8</bitWidth>
          </field>
        </fields>
      </register>
      <register>
        <name>PCR.0</name>
        <addressOffset>0x4</addressOffset>
        <size>0x20</size>
        <fields>
          <field>
            <name>CLKEN</name>
            <bitOffset>0</bitOffset>
            <bitWidth>1</bitWidth>
          </field>
          <field>
            <name>CLKSRC</name>
            <bitOffset>1</bitOffset>
            <bitWidth>1</bitWidth>
          </field>
          <field>
            <name>DQSEN</name>
            <bitOffset>4</bitOffset>
            <bitWidth>1</bitWidth>
          </field>
          <field>
            <name>DQSSRC</name>
            <bitOffset>5</bitOffset>
            <bitWidth>1</bitWidth>
          </field>
          <field>
            <name>NCSEN</name>
            <bitOffset>8</bitOffset>
            <bitWidth>1</bitWidth>
          </field>
          <field>
            <name>NCSSRC</name>
            <bitOffset>9</bitOffset>
            <bitWidth>1</bitWidth>
          </field>
          <field>
            <name>IOLEN</name>
            <bitOffset>16</bitOffset>
            <bitWidth>1</bitWidth>
          </field>
          <field>
            <name>IOLSRC</name>
            <bitOffset>17</bitOffset>
            <bitWidth>2</bitWidth>
          </field>
          <field>
            <name>IOHEN</name>
            <bitOffset>24</bitOffset>
            <bitWidth>1</bitWidth>
          </field>
          <field>
            <name>IOHSRC</name>
            <bitOffset>25</bitOffset>
            <bitWidth>2</bitWidth>
          </field>
        </fields>
      </register>
      <register>
        <name>PCR.1</name>
        <addressOffset>0x8</addressOffset>
        <size>0x20</size>
        <fields>
          <field>
            <name>CLKEN</name>
            <bitOffset>0</bitOffset>
            <bitWidth>1</bitWidth>
          </field>
          <field>
            <name>CLKSRC</name>
            <bitOffset>1</bitOffset>
            <bitWidth>1</bitWidth>
          </field>
          <field>
            <name>DQSEN</name>
            <bitOffset>4</bitOffset>
            <bitWidth>1</bitWidth>
          </field>
          <field>
            <name>DQSSRC</name>
            <bitOffset>5</bitOffset>
            <bitWidth>1</bitWidth>
          </field>
          <field>
            <name>NCSEN</name>
            <bitOffset>8</bitOffset>
            <bitWidth>1</bitWidth>
          </field>
          <field>
            <name>NCSSRC</name>
            <bitOffset>9</bitOffset>
            <bitWidth>1</bitWidth>
          </field>
          <field>
            <name>IOLEN</name>
            <bitOffset>16</bitOffset>
            <bitWidth>1</bitWidth>
          </field>
          <field>
            <name>IOLSRC</name>
            <bitOffset>17</bitOffset>
            <bitWidth>2</bitWidth>
          </field>
          <field>
            <name>IOHEN</name>
            <bitOffset>24</bitOffset>
            <bitWidth>1</bitWidth>
          </field>
          <field>
            <name>IOHSRC</name>
            <bitOffset>25</bitOffset>
            <bitWidth>2</bitWidth>
          </field>
        </fields>
      </register>
    </peripheral>
    <peripheral>
      <name>SDMMC1</name>
      <baseAddress>0x50062400</baseAddress>
      <register>
        <name>POWER</name>
        <addressOffset>0x0</addressOffset>
        <size>0x20</size>
        <fields>
          <field>
            <name>PWRCTRL</name>
            <bitOffset>0</bitOffset>
            <bitWidth>2</bitWidth>
          </field>
          <field>
            <name>VSWITCH</name>
            <bitOffset>2</bitOffset>
            <bitWidth>1</bitWidth>
          </field>
          <field>
            <name>VSWITCHEN</name>
            <bitOffset>3</bitOffset>
            <bitWidth>1</bitWidth>
          </field>
          <field>
            <name>DIRPOL</name>
            <bitOffset>4</bitOffset>
            <bitWidth>1</bitWidth>
          </field>
        </fields>
      </register>
      <register>
        <name>CLKCR</name>
        <addressOffset>0x4</addressOffset>
        <size>0x20</size>
        <fields>
          <field>
            <name>CLKDIV</name>
            <bitOffset>0</bitOffset>
            <bitWidth>10</bitWidth>
          </field>
          <field>
            <name>PWRSAV</name>
            <bitOffset>12</bitOffset>
            <bitWidth>1</bitWidth>
          </field>
          <field>
            <name>WIDBUS</name>
            <bitOffset>14</bitOffset>
            <bitWidth>2</bitWidth>
          </field>
          <field>
            <name>NEGEDGE</name>
            <bitOffset>16</bitOffset>
            <bitWidth>1</bitWidth>
          </field>
          <field>
            <name>HWFC_EN</name>
            <bitOffset>17</bitOffset>
            <bitWidth>1</bitWidth>
          </field>
          <field>
            <name>DDR</name>
            <bitOffset>18</bitOffset>
            <bitWidth>1</bitWidth>
          </field>
          <field>
            <name>BUSSPEED</name>
            <bitOffset>19</bitOffset>
            <bitWidth>1</bitWidth>
          </field>
          <field>
            <name>SELCLKRX</name>
            <bitOffset>20</bitOffset>
            <bitWidth>2</bitWidth>
          </field>
        </fields>
      </register>
      <register>
        <name>ARG</name>
        <addressOffset>0x8</addressOffset>
        <size>0x20</size>
        <fields>
          <field>
            <name>CMDARG</name>
            <bitOffset>0</bitOffset>
            <bitWidth>32</bitWidth>
          </field>
        </fields>
      </register>
      <register>
        <name>CMD</name>
        <addressOffset>0xc</addressOffset>
        <size>0x20</size>
        <fields>
          <field>
            <name>CMDINDEX</name>
            <bitOffset>0</bitOffset>
            <bitWidth>6</bitWidth>
          </field>
          <field>
            <name>CMDTRANS</name>
            <bitOffset>6</bitOffset>
            <bitWidth>1</bitWidth>
          </field>
          <field>
            <name>CMDSTOP</name>
            <bitOffset>7</bitOffset>
            <bitWidth>1</bitWidth>
          </field>
          <field>
            <name>WAITRESP</name>
            <bitOffset>8</bitOffset>
            <bitWidth>2</bitWidth>
          </field>
          <field>
            <name>WAITINT</name>
            <bitOffset>10</bitOffset>
            <bitWidth>1</bitWidth>
          </field>
          <field>
            <name>WAITPEND</name>
            <bitOffset>11</bitOffset>
            <bitWidth>1</bitWidth>
          </field>
          <field>
            <name>CPSMEN</name>
            <bitOffset>12</bitOffset>
            <bitWidth>1</bitWidth>
          </field>
          <field>
            <name>DTHOLD</name>
            <bitOffset>13</bitOffset>
            <bitWidth>1</bitWidth>
          </field>
          <field>
            <name>BOOTMODE</name>
            <bitOffset>14</bitOffset>
            <bitWidth>1</bitWidth>
          </field>
          <field>
            <name>BOOTEN</name>
            <bitOffset>15</bitOffset>
            <bitWidth>1</bitWidth>
          </field>
          <field>
            <name>CMDSUSPEND</name>
            <bitOffset>16</bitOffset>
            <bitWidth>1</bitWidth>
          </field>
        </fields>
      </register>
      <register>
        <name>RESPCMD</name>
        <addressOffset>0x10</addressOffset>
        <size>0x20</size>
        <fields>
          <field>
            <name>RESPCMD</name>
            <bitOffset>0</bitOffset>
            <bitWidth>6</bitWidth>
          </field>
        </fields>
      </register>
      <register>
        <name>RESP1</name>
        <addressOffset>0x14</addressOffset>
        <size>0x20</size>
        <fields>
          <field>
            <name>CARDSTATUS1</name>
            <bitOffset>0</bitOffset>
            <bitWidth>32</bitWidth>
          </field>
        </fields>
      </register>
      <register>
        <name>RESP2</name>
        <addressOffset>0x18</addressOffset>
        <size>0x20</size>
        <fields>
          <field>
            <name>CARDSTATUS2</name>
            <bitOffset>0</bitOffset>
            <bitWidth>32</bitWidth>
          </field>
        </fields>
      </register>
      <register>
        <name>RESP3</name>
        <addressOffset>0x1c</addressOffset>
        <size>0x20</size>
        <fields>
          <field>
            <name>CARDSTATUS3</name>
            <bitOffset>0</bitOffset>
            <bitWidth>32</bitWidth>
          </field>
        </fields>
      </register>
      <register>
        <name>RESP4</name>
        <addressOffset>0x20</addressOffset>
        <size>0x20</size>
        <fields>
          <field>
            <name>CARDSTATUS4</name>
            <bitOffset>0</bitOffset>
            <bitWidth>32</bitWidth>
          </field>
        </fields>
      </register>
      <register>
        <name>DTIMER</name>
        <addressOffset>0x24</addressOffset>
        <size>0x20</size>
        <fields>
          <field>
            <name>DATATIME</name>
            <bitOffset>0</bitOffset>
            <bitWidth>32</bitWidth>
          </field>
        </fields>
      </register>
      <register>
        <name>DLEN</name>
        <addressOffset>0x28</addressOffset>
        <size>0x20</size>
        <fields>
          <field>
            <name>DATALENGTH</name>
            <bitOffset>0</bitOffset>
            <bitWidth>25</bitWidth>
          </field>
        </fields>
      </register>
      <register>
        <name>DCTRL</name>
        <addressOffset>0x2c</addressOffset>
        <size>0x20</size>
        <fields>
          <field>
            <name>DTEN</name>
            <bitOffset>0</bitOffset>
            <bitWidth>1</bitWidth>
          </field>
          <field>
            <name>DTDIR</name>
            <bitOffset>1</bitOffset>
            <bitWidth>1</bitWidth>
          </field>
          <field>
            <name>DTMODE</name>
            <bitOffset>2</bitOffset>
            <bitWidth>2</bitWidth>
          </field>
          <field>
            <name>DBLOCKSIZE</name>
            <bitOffset>4</bitOffset>
            <bitWidth>4</bitWidth>
          </field>
          <field>
            <name>RWSTART</name>
            <bitOffset>8</bitOffset>
            <bitWidth>1</bitWidth>
          </field>
          <field>
            <name>RWSTOP</name>
            <bitOffset>9</bitOffset>
            <bitWidth>1</bitWidth>
          </field>
          <field>
            <name>RWMOD</name>
            <bitOffset>10</bitOffset>
            <bitWidth>1</bitWidth>
          </field>
          <field>
            <name>SDIOEN</name>
            <bitOffset>11</bitOffset>
            <bitWidth>1</bitWidth>
          </field>
          <field>
            <name>BOOTACKEN</name>
            <bitOffset>12</bitOffset>
            <bitWidth>1</bitWidth>
          </field>
          <field>
            <name>FIFORST</name>
            <bitOffset>13</bitOffset>
            <bitWidth>1</bitWidth>
          </field>
        </fields>
      </register>
      <register>
        <name>DCOUNT</name>
        <addressOffset>0x30</addressOffset>
        <size>0x20</size>
        <fields>
          <field>
            <name>DATACOUNT</name>
            <bitOffset>0</bitOffset>
            <bitWidth>25</bitWidth>
          </field>
        </fields>
      </register>
      <register>
        <name>STA</name>
        <addressOffset>0x34</addressOffset>
        <size>0x20</size>
        <fields>
          <field>
            <name>CCRCFAIL</name>
            <bitOffset>0</bitOffset>
            <bitWidth>1</bitWidth>
          </field>
          <field>
            <name>DCRCFAIL</name>
            <bitOffset>1</bitOffset>
            <bitWidth>1</bitWidth>
          </field>
          <field>
            <name>CTIMEOUT</name>
            <bitOffset>2</bitOffset>
            <bitWidth>1</bitWidth>
          </field>
          <field>
            <name>DTIMEOUT</name>
            <bitOffset>3</bitOffset>
            <bitWidth>1</bitWidth>
          </field>
          <field>
            <name>TXUNDERR</name>
            <bitOffset>4</bitOffset>
            <bitWidth>1</bitWidth>
          </field>
          <field>
            <name>RXOVERR</name>
            <bitOffset>5</bitOffset>
            <bitWidth>1</bitWidth>
          </field>
          <field>
            <name>CMDREND</name>
            <bitOffset>6</bitOffset>
            <bitWidth>1</bitWidth>
          </field>
          <field>
            <name>CMDSENT</name>
            <bitOffset>7</bitOffset>
            <bitWidth>1</bitWidth>
          </field>
          <field>
            <name>DATAEND</name>
            <bitOffset>8</bitOffset>
            <bitWidth>1</bitWidth>
          </field>
          <field>
            <name>DHOLD</name>
            <bitOffset>9</bitOffset>
            <bitWidth>1</bitWidth>
          </field>
          <field>
            <name>DBCKEND</name>
            <bitOffset>10</bitOffset>
            <bitWidth>1</bitWidth>
          </field>
          <field>
            <name>DABORT</name>
            <bitOffset>11</bitOffset>
            <bitWidth>1</bitWidth>
          </field>
          <field>
            <name>DPSMACT</name>
            <bitOffset>12</bitOffset>
            <bitWidth>1</bitWidth>
          </field>
          <field>
            <name>CPSMACT</name>
            <bitOffset>13</bitOffset>
            <bitWidth>1</bitWidth>
          </field>
          <field>
            <name>TXFIFOHE</name>
            <bitOffset>14</bitOffset>
            <bitWidth>1</bitWidth>
          </field>
          <field>
            <name>RXFIFOHF</name>
            <bitOffset>15</bitOffset>
            <bitWidth>1</bitWidth>
          </field>
          <field>
            <name>TXFIFOF</name>
            <bitOffset>16</bitOffset>
            <bitWidth>1</bitWidth>
          </field>
          <field>
            <name>RXFIFOF</name>
            <bitOffset>17</bitOffset>
            <bitWidth>1</bitWidth>
          </field>
          <field>
            <name>TXFIFOE</name>
            <bitOffset>18</bitOffset>
            <bitWidth>1</bitWidth>
          </field>
          <field>
            <name>RXFIFOE</name>
            <bitOffset>19</bitOffset>
            <bitWidth>1</bitWidth>
          </field>
          <field>
            <name>BUSYD0</name>
            <bitOffset>20</bitOffset>
            <bitWidth>1</bitWidth>
          </field>
          <field>
            <name>BUSYD0END</name>
            <bitOffset>21</bitOffset>
            <bitWidth>1</bitWidth>
          </field>
          <field>
            <name>SDIOIT</name>
            <bitOffset>22</bitOffset>
            <bitWidth>1</bitWidth>
          </field>
          <field>
            <name>ACKFAIL</name>
            <bitOffset>23</bitOffset>
            <bitWidth>1</bitWidth>
          </field>
          <field>
            <name>ACKTIMEOUT</name>
            <bitOffset>24</bitOffset>
            <bitWidth>1</bitWidth>
          </field>
          <field>
            <name>VSWEND</name>
            <bitOffset>25</bitOffset>
            <bitWidth>1</bitWidth>
          </field>
          <field>
            <name>CKSTOP</name>
            <bitOffset>26</bitOffset>
            <bitWidth>1</bitWidth>
          </field>
          <field>
            <name>IDMATE</name>
            <bitOffset>27</bitOffset>
            <bitWidth>1</bitWidth>
          </field>
          <field>
            <name>IDMABTC</name>
            <bitOffset>28</bitOffset>
            <bitWidth>1</bitWidth>
          </field>
        </fields>
      </register>
      <register>
        <name>ICR</name>
        <addressOffset>0x38</addressOffset>
        <size>0x20</size>
        <fields>
          <field>
            <name>CCRCFAILC</name>
            <bitOffset>0</bitOffset>
            <bitWidth>1</bitWidth>
          </field>
          <field>
            <name>DCRCFAILC</name>
            <bitOffset>1</bitOffset>
            <bitWidth>1</bitWidth>
          </field>
          <field>
            <name>CTIMEOUTC</name>
            <bitOffset>2</bitOffset>
            <bitWidth>1</bitWidth>
          </field>
          <field>
            <name>DTIMEOUTC</name>
            <bitOffset>3</bitOffset>
            <bitWidth>1</bitWidth>
          </field>
          <field>
            <name>TXUNDERRC</name>
            <bitOffset>4</bitOffset>
            <bitWidth>1</bitWidth>
          </field>
          <field>
            <name>RXOVERRC</name>
            <bitOffset>5</bitOffset>
            <bitWidth>1</bitWidth>
          </field>
          <field>
            <name>CMDRENDC</name>
            <bitOffset>6</bitOffset>
            <bitWidth>1</bitWidth>
          </field>
          <field>
            <name>CMDSENTC</name>
            <bitOffset>7</bitOffset>
            <bitWidth>1</bitWidth>
          </field>
          <field>
            <name>DATAENDC</name>
            <bitOffset>8</bitOffset>
            <bitWidth>1</bitWidth>
          </field>
          <field>
            <name>DHOLDC</name>
            <bitOffset>9</bitOffset>
            <bitWidth>1</bitWidth>
          </field>
          <field>
            <name>DBCKENDC</name>
            <bitOffset>10</bitOffset>
            <bitWidth>1</bitWidth>
          </field>
          <field>
            <name>DABORTC</name>
            <bitOffset>11</bitOffset>
            <bitWidth>1</bitWidth>
          </field>
          <field>
            <name>BUSYD0ENDC</name>
            <bitOffset>21</bitOffset>
            <bitWidth>1</bitWidth>
          </field>
          <field>
            <name>SDIOITC</name>
            <bitOffset>22</bitOffset>
            <bitWidth>1</bitWidth>
          </field>
          <field>
            <name>ACKFAILC</name>
            <bitOffset>23</bitOffset>
            <bitWidth>1</bitWidth>
          </field>
          <field>
            <name>ACKTIMEOUTC</name>
            <bitOffset>24</bitOffset>
            <bitWidth>1</bitWidth>
          </field>
          <field>
            <name>VSWENDC</name>
            <bitOffset>25</bitOffset>
            <bitWidth>1</bitWidth>
          </field>
          <field>
            <name>CKSTOPC</name>
            <bitOffset>26</bitOffset>
            <bitWidth>1</bitWidth>
          </field>
          <field>
            <name>IDMATEC</name>
            <bitOffset>27</bitOffset>
            <bitWidth>1</bitWidth>
          </field>
          <field>
            <name>IDMABTCC</name>
            <bitOffset>28</bitOffset>
            <bitWidth>1</bitWidth>
          </field>
        </fields>
      </register>
      <register>
        <name>MASK</name>
        <addressOffset>0x3c</addressOffset>
        <size>0x20</size>
        <fields>
          <field>
            <name>CCRCFAILIE</name>
            <bitOffset>0</bitOffset>
            <bitWidth>1</bitWidth>
          </field>
          <field>
            <name>DCRCFAILIE</name>
            <bitOffset>1</bitOffset>
            <bitWidth>1</bitWidth>
          </field>
          <field>
            <name>CTIMEOUTIE</name>
            <bitOffset>2</bitOffset>
            <bitWidth>1</bitWidth>
          </field>
          <field>
            <name>DTIMEOUTIE</name>
            <bitOffset>3</bitOffset>
            <bitWidth>1</bitWidth>
          </field>
          <field>
            <name>TXUNDERRIE</name>
            <bitOffset>4</bitOffset>
            <bitWidth>1</bitWidth>
          </field>
          <field>
            <name>RXOVERRIE</name>
            <bitOffset>5</bitOffset>
            <bitWidth>1</bitWidth>
          </field>
          <field>
            <name>CMDRENDIE</name>
            <bitOffset>6</bitOffset>
            <bitWidth>1</bitWidth>
          </field>
          <field>
            <name>CMDSENTIE</name>
            <bitOffset>7</bitOffset>
            <bitWidth>1</bitWidth>
          </field>
          <field>
            <name>DATAENDIE</name>
            <bitOffset>8</bitOffset>
            <bitWidth>1</bitWidth>
          </field>
          <field>
            <name>DHOLDIE</name>
            <bitOffset>9</bitOffset>
            <bitWidth>1</bitWidth>
          </field>
          <field>
            <name>DBCKENDIE</name>
            <bitOffset>10</bitOffset>
            <bitWidth>1</bitWidth>
          </field>
          <field>
            <name>DABORTIE</name>
            <bitOffset>11</bitOffset>
            <bitWidth>1</bitWidth>
          </field>
          <field>
            <name>TXFIFOHEIE</name>
            <bitOffset>14</bitOffset>
            <bitWidth>1</bitWidth>
          </field>
          <field>
            <name>RXFIFOHFIE</name>
            <bitOffset>15</bitOffset>
            <bitWidth>1</bitWidth>
          </field>
          <field>
            <name>RXFIFOFIE</name>
            <bitOffset>17</bitOffset>
            <bitWidth>1</bitWidth>
          </field>
          <field>
            <name>TXFIFOEIE</name>
            <bitOffset>18</bitOffset>
            <bitWidth>1</bitWidth>
          </field>
          <field>
            <name>BUSYD0ENDIE</name>
            <bitOffset>21</bitOffset>
            <bitWidth>1</bitWidth>
          </field>
          <field>
            <name>SDIOITIE</name>
            <bitOffset>22</bitOffset>
            <bitWidth>1</bitWidth>
          </field>
          <field>
            <name>ACKFAILIE</name>
            <bitOffset>23</bitOffset>
            <bitWidth>1</bitWidth>
          </field>
          <field>
            <name>ACKTIMEOUTIE</name>
            <bitOffset>24</bitOffset>
            <bitWidth>1</bitWidth>
          </field>
          <field>
            <name>VSWENDIE</name>
            <bitOffset>25</bitOffset>
            <bitWidth>1</bitWidth>
          </field>
          <field>
            <name>CKSTOPIE</name>
            <bitOffset>26</bitOffset>
            <bitWidth>1</bitWidth>
          </field>
          <field>
            <name>IDMABTCIE</name>
            <bitOffset>28</bitOffset>
            <bitWidth>1</bitWidth>
          </field>
        </fields>
      </register>
      <register>
        <name>ACKTIME</name>
        <addressOffset>0x40</addressOffset>
        <size>0x20</size>
      </register>
      <register>
        <name>IDMACTRL</name>
        <addressOffset>0x50</addressOffset>
        <size>0x20</size>
      </register>
      <register>
        <name>IDMABSIZE</name>
        <addressOffset>0x54</addressOffset>
        <size>0x20</size>
      </register>
      <register>
        <name>IDMABASE0</name>
        <addressOffset>0x58</addressOffset>
        <size>0x20</size>
      </register>
      <register>
        <name>IDMABASE1</name>
        <addressOffset>0x5c</addressOffset>
        <size>0x20</size>
      </register>
      <register>
        <name>FIFO</name>
        <addressOffset>0x80</addressOffset>
        <size>0x20</size>
        <fields>
          <field>
            <name>FIFODATA</name>
            <bitOffset>0</bitOffset>
            <bitWidth>32</bitWidth>
          </field>
        </fields>
      </register>
    </peripheral>
    <peripheral>
      <name>SDMMC2</name>
      <baseAddress>0x50062800</baseAddress>
      <register>
        <name>POWER</name>
        <addressOffset>0x0</addressOffset>
        <size>0x20</size>
        <fields>
          <field>
            <name>PWRCTRL</name>
            <bitOffset>0</bitOffset>
            <bitWidth>2</bitWidth>
          </field>
          <field>
            <name>VSWITCH</name>
            <bitOffset>2</bitOffset>
            <bitWidth>1</bitWidth>
          </field>
          <field>
            <name>VSWITCHEN</name>
            <bitOffset>3</bitOffset>
            <bitWidth>1</bitWidth>
          </field>
          <field>
            <name>DIRPOL</name>
            <bitOffset>4</bitOffset>
            <bitWidth>1</bitWidth>
          </field>
        </fields>
      </register>
      <register>
        <name>CLKCR</name>
        <addressOffset>0x4</addressOffset>
        <size>0x20</size>
        <fields>
          <field>
            <name>CLKDIV</name>
            <bitOffset>0</bitOffset>
            <bitWidth>10</bitWidth>
          </field>
          <field>
            <name>PWRSAV</name>
            <bitOffset>12</bitOffset>
            <bitWidth>1</bitWidth>
          </field>
          <field>
            <name>WIDBUS</name>
            <bitOffset>14</bitOffset>
            <bitWidth>2</bitWidth>
          </field>
          <field>
            <name>NEGEDGE</name>
            <bitOffset>16</bitOffset>
            <bitWidth>1</bitWidth>
          </field>
          <field>
            <name>HWFC_EN</name>
            <bitOffset>17</bitOffset>
            <bitWidth>1</bitWidth>
          </field>
          <field>
            <name>DDR</name>
            <bitOffset>18</bitOffset>
            <bitWidth>1</bitWidth>
          </field>
          <field>
            <name>BUSSPEED</name>
            <bitOffset>19</bitOffset>
            <bitWidth>1</bitWidth>
          </field>
          <field>
            <name>SELCLKRX</name>
            <bitOffset>20</bitOffset>
            <bitWidth>2</bitWidth>
          </field>
        </fields>
      </register>
      <register>
        <name>ARG</name>
        <addressOffset>0x8</addressOffset>
        <size>0x20</size>
        <fields>
          <field>
            <name>CMDARG</name>
            <bitOffset>0</bitOffset>
            <bitWidth>32</bitWidth>
          </field>
        </fields>
      </register>
      <register>
        <name>CMD</name>
        <addressOffset>0xc</addressOffset>
        <size>0x20</size>
        <fields>
          <field>
            <name>CMDINDEX</name>
            <bitOffset>0</bitOffset>
            <bitWidth>6</bitWidth>
          </field>
          <field>
            <name>CMDTRANS</name>
            <bitOffset>6</bitOffset>
            <bitWidth>1</bitWidth>
          </field>
          <field>
            <name>CMDSTOP</name>
            <bitOffset>7</bitOffset>
            <bitWidth>1</bitWidth>
          </field>
          <field>
            <name>WAITRESP</name>
            <bitOffset>8</bitOffset>
            <bitWidth>2</bitWidth>
          </field>
          <field>
            <name>WAITINT</name>
            <bitOffset>10</bitOffset>
            <bitWidth>1</bitWidth>
          </field>
          <field>
            <name>WAITPEND</name>
            <bitOffset>11</bitOffset>
            <bitWidth>1</bitWidth>
          </field>
          <field>
            <name>CPSMEN</name>
            <bitOffset>12</bitOffset>
            <bitWidth>1</bitWidth>
          </field>
          <field>
            <name>DTHOLD</name>
            <bitOffset>13</bitOffset>
            <bitWidth>1</bitWidth>
          </field>
          <field>
            <name>BOOTMODE</name>
            <bitOffset>14</bitOffset>
            <bitWidth>1</bitWidth>
          </field>
          <field>
            <name>BOOTEN</name>
            <bitOffset>15</bitOffset>
            <bitWidth>1</bitWidth>
          </field>
          <field>
            <name>CMDSUSPEND</name>
            <bitOffset>16</bitOffset>
            <bitWidth>1</bitWidth>
          </field>
        </fields>
      </register>
      <register>
        <name>RESPCMD</name>
        <addressOffset>0x10</addressOffset>
        <size>0x20</size>
        <fields>
          <field>
            <name>RESPCMD</name>
            <bitOffset>0</bitOffset>
            <bitWidth>6</bitWidth>
          </field>
        </fields>
      </register>
      <register>
        <name>RESP1</name>
        <addressOffset>0x14</addressOffset>
        <size>0x20</size>
        <fields>
          <field>
            <name>CARDSTATUS1</name>
            <bitOffset>0</bitOffset>
            <bitWidth>32</bitWidth>
          </field>
        </fields>
      </register>
      <register>
        <name>RESP2</name>
        <addressOffset>0x18</addressOffset>
        <size>0x20</size>
        <fields>
          <field>
            <name>CARDSTATUS2</name>
            <bitOffset>0</bitOffset>
            <bitWidth>32</bitWidth>
          </field>
        </fields>
      </register>
      <register>
        <name>RESP3</name>
        <addressOffset>0x1c</addressOffset>
        <size>0x20</size>
        <fields>
          <field>
            <name>CARDSTATUS3</name>
            <bitOffset>0</bitOffset>
            <bitWidth>32</bitWidth>
          </field>
        </fields>
      </register>
      <register>
        <name>RESP4</name>
        <addressOffset>0x20</addressOffset>
        <size>0x20</size>
        <fields>
          <field>
            <name>CARDSTATUS4</name>
            <bitOffset>0</bitOffset>
            <bitWidth>32</bitWidth>
          </field>
        </fields>
      </register>
      <register>
        <name>DTIMER</name>
        <addressOffset>0x24</addressOffset>
        <size>0x20</size>
        <fields>
          <field>
            <name>DATATIME</name>
            <bitOffset>0</bitOffset>
            <bitWidth>32</bitWidth>
          </field>
        </fields>
      </register>
      <register>
        <name>DLEN</name>
        <addressOffset>0x28</addressOffset>
        <size>0x20</size>
        <fields>
          <field>
            <name>DATALENGTH</name>
            <bitOffset>0</bitOffset>
            <bitWidth>25</bitWidth>
          </field>
        </fields>
      </register>
      <register>
        <name>DCTRL</name>
        <addressOffset>0x2c</addressOffset>
        <size>0x20</size>
        <fields>
          <field>
            <name>DTEN</name>
            <bitOffset>0</bitOffset>
            <bitWidth>1</bitWidth>
          </field>
          <field>
            <name>DTDIR</name>
            <bitOffset>1</bitOffset>
            <bitWidth>1</bitWidth>
          </field>
          <field>
            <name>DTMODE</name>
            <bitOffset>2</bitOffset>
            <bitWidth>2</bitWidth>
          </field>
          <field>
            <name>DBLOCKSIZE</name>
            <bitOffset>4</bitOffset>
            <bitWidth>4</bitWidth>
          </field>
          <field>
            <name>RWSTART</name>
            <bitOffset>8</bitOffset>
            <bitWidth>1</bitWidth>
          </field>
          <field>
            <name>RWSTOP</name>
            <bitOffset>9</bitOffset>
            <bitWidth>1</bitWidth>
          </field>
          <field>
            <name>RWMOD</name>
            <bitOffset>10</bitOffset>
            <bitWidth>1</bitWidth>
          </field>
          <field>
            <name>SDIOEN</name>
            <bitOffset>11</bitOffset>
            <bitWidth>1</bitWidth>
          </field>
          <field>
            <name>BOOTACKEN</name>
            <bitOffset>12</bitOffset>
            <bitWidth>1</bitWidth>
          </field>
          <field>
            <name>FIFORST</name>
            <bitOffset>13</bitOffset>
            <bitWidth>1</bitWidth>
          </field>
        </fields>
      </register>
      <register>
        <name>DCOUNT</name>
        <addressOffset>0x30</addressOffset>
        <size>0x20</size>
        <fields>
          <field>
            <name>DATACOUNT</name>
            <bitOffset>0</bitOffset>
            <bitWidth>25</bitWidth>
          </field>
        </fields>
      </register>
      <register>
        <name>STA</name>
        <addressOffset>0x34</addressOffset>
        <size>0x20</size>
        <fields>
          <field>
            <name>CCRCFAIL</name>
            <bitOffset>0</bitOffset>
            <bitWidth>1</bitWidth>
          </field>
          <field>
            <name>DCRCFAIL</name>
            <bitOffset>1</bitOffset>
            <bitWidth>1</bitWidth>
          </field>
          <field>
            <name>CTIMEOUT</name>
            <bitOffset>2</bitOffset>
            <bitWidth>1</bitWidth>
          </field>
          <field>
            <name>DTIMEOUT</name>
            <bitOffset>3</bitOffset>
            <bitWidth>1</bitWidth>
          </field>
          <field>
            <name>TXUNDERR</name>
            <bitOffset>4</bitOffset>
            <bitWidth>1</bitWidth>
          </field>
          <field>
            <name>RXOVERR</name>
            <bitOffset>5</bitOffset>
            <bitWidth>1</bitWidth>
          </field>
          <field>
            <name>CMDREND</name>
            <bitOffset>6</bitOffset>
            <bitWidth>1</bitWidth>
          </field>
          <field>
            <name>CMDSENT</name>
            <bitOffset>7</bitOffset>
            <bitWidth>1</bitWidth>
          </field>
          <field>
            <name>DATAEND</name>
            <bitOffset>8</bitOffset>
            <bitWidth>1</bitWidth>
          </field>
          <field>
            <name>DHOLD</name>
            <bitOffset>9</bitOffset>
            <bitWidth>1</bitWidth>
          </field>
          <field>
            <name>DBCKEND</name>
            <bitOffset>10</bitOffset>
            <bitWidth>1</bitWidth>
          </field>
          <field>
            <name>DABORT</name>
            <bitOffset>11</bitOffset>
            <bitWidth>1</bitWidth>
          </field>
          <field>
            <name>DPSMACT</name>
            <bitOffset>12</bitOffset>
            <bitWidth>1</bitWidth>
          </field>
          <field>
            <name>CPSMACT</name>
            <bitOffset>13</bitOffset>
            <bitWidth>1</bitWidth>
          </field>
          <field>
            <name>TXFIFOHE</name>
            <bitOffset>14</bitOffset>
            <bitWidth>1</bitWidth>
          </field>
          <field>
            <name>RXFIFOHF</name>
            <bitOffset>15</bitOffset>
            <bitWidth>1</bitWidth>
          </field>
          <field>
            <name>TXFIFOF</name>
            <bitOffset>16</bitOffset>
            <bitWidth>1</bitWidth>
          </field>
          <field>
            <name>RXFIFOF</name>
            <bitOffset>17</bitOffset>
            <bitWidth>1</bitWidth>
          </field>
          <field>
            <name>TXFIFOE</name>
            <bitOffset>18</bitOffset>
            <bitWidth>1</bitWidth>
          </field>
          <field>
            <name>RXFIFOE</name>
            <bitOffset>19</bitOffset>
            <bitWidth>1</bitWidth>
          </field>
          <field>
            <name>BUSYD0</name>
            <bitOffset>20</bitOffset>
            <bitWidth>1</bitWidth>
          </field>
          <field>
            <name>BUSYD0END</name>
            <bitOffset>21</bitOffset>
            <bitWidth>1</bitWidth>
          </field>
          <field>
            <name>SDIOIT</name>
            <bitOffset>22</bitOffset>
            <bitWidth>1</bitWidth>
          </field>
          <field>
            <name>ACKFAIL</name>
            <bitOffset>23</bitOffset>
            <bitWidth>1</bitWidth>
          </field>
          <field>
            <name>ACKTIMEOUT</name>
            <bitOffset>24</bitOffset>
            <bitWidth>1</bitWidth>
          </field>
          <field>
            <name>VSWEND</name>
            <bitOffset>25</bitOffset>
            <bitWidth>1</bitWidth>
          </field>
          <field>
            <name>CKSTOP</name>
            <bitOffset>26</bitOffset>
            <bitWidth>1</bitWidth>
          </field>
          <field>
            <name>IDMATE</name>
            <bitOffset>27</bitOffset>
            <bitWidth>1</bitWidth>
          </field>
          <field>
            <name>IDMABTC</name>
            <bitOffset>28</bitOffset>
            <bitWidth>1</bitWidth>
          </field>
        </fields>
      </register>
      <register>
        <name>ICR</name>
        <addressOffset>0x38</addressOffset>
        <size>0x20</size>
        <fields>
          <field>
            <name>CCRCFAILC</name>
            <bitOffset>0</bitOffset>
            <bitWidth>1</bitWidth>
          </field>
          <field>
            <name>DCRCFAILC</name>
            <bitOffset>1</bitOffset>
            <bitWidth>1</bitWidth>
          </field>
          <field>
            <name>CTIMEOUTC</name>
            <bitOffset>2</bitOffset>
            <bitWidth>1</bitWidth>
          </field>
          <field>
            <name>DTIMEOUTC</name>
            <bitOffset>3</bitOffset>
            <bitWidth>1</bitWidth>
          </field>
          <field>
            <name>TXUNDERRC</name>
            <bitOffset>4</bitOffset>
            <bitWidth>1</bitWidth>
          </field>
          <field>
            <name>RXOVERRC</name>
            <bitOffset>5</bitOffset>
            <bitWidth>1</bitWidth>
          </field>
          <field>
            <name>CMDRENDC</name>
            <bitOffset>6</bitOffset>
            <bitWidth>1</bitWidth>
          </field>
          <field>
            <name>CMDSENTC</name>
            <bitOffset>7</bitOffset>
            <bitWidth>1</bitWidth>
          </field>
          <field>
            <name>DATAENDC</name>
            <bitOffset>8</bitOffset>
            <bitWidth>1</bitWidth>
          </field>
          <field>
            <name>DHOLDC</name>
            <bitOffset>9</bitOffset>
            <bitWidth>1</bitWidth>
          </field>
          <field>
            <name>DBCKENDC</name>
            <bitOffset>10</bitOffset>
            <bitWidth>1</bitWidth>
          </field>
          <field>
            <name>DABORTC</name>
            <bitOffset>11</bitOffset>
            <bitWidth>1</bitWidth>
          </field>
          <field>
            <name>BUSYD0ENDC</name>
            <bitOffset>21</bitOffset>
            <bitWidth>1</bitWidth>
          </field>
          <field>
            <name>SDIOITC</name>
            <bitOffset>22</bitOffset>
            <bitWidth>1</bitWidth>
          </field>
          <field>
            <name>ACKFAILC</name>
            <bitOffset>23</bitOffset>
            <bitWidth>1</bitWidth>
          </field>
          <field>
            <name>ACKTIMEOUTC</name>
            <bitOffset>24</bitOffset>
            <bitWidth>1</bitWidth>
          </field>
          <field>
            <name>VSWENDC</name>
            <bitOffset>25</bitOffset>
            <bitWidth>1</bitWidth>
          </field>
          <field>
            <name>CKSTOPC</name>
            <bitOffset>26</bitOffset>
            <bitWidth>1</bitWidth>
          </field>
          <field>
            <name>IDMATEC</name>
            <bitOffset>27</bitOffset>
            <bitWidth>1</bitWidth>
          </field>
          <field>
            <name>IDMABTCC</name>
            <bitOffset>28</bitOffset>
            <bitWidth>1</bitWidth>
          </field>
        </fields>
      </register>
      <register>
        <name>MASK</name>
        <addressOffset>0x3c</addressOffset>
        <size>0x20</size>
        <fields>
          <field>
            <name>CCRCFAILIE</name>
            <bitOffset>0</bitOffset>
            <bitWidth>1</bitWidth>
          </field>
          <field>
            <name>DCRCFAILIE</name>
            <bitOffset>1</bitOffset>
            <bitWidth>1</bitWidth>
          </field>
          <field>
            <name>CTIMEOUTIE</name>
            <bitOffset>2</bitOffset>
            <bitWidth>1</bitWidth>
          </field>
          <field>
            <name>DTIMEOUTIE</name>
            <bitOffset>3</bitOffset>
            <bitWidth>1</bitWidth>
          </field>
          <field>
            <name>TXUNDERRIE</name>
            <bitOffset>4</bitOffset>
            <bitWidth>1</bitWidth>
          </field>
          <field>
            <name>RXOVERRIE</name>
            <bitOffset>5</bitOffset>
            <bitWidth>1</bitWidth>
          </field>
          <field>
            <name>CMDRENDIE</name>
            <bitOffset>6</bitOffset>
            <bitWidth>1</bitWidth>
          </field>
          <field>
            <name>CMDSENTIE</name>
            <bitOffset>7</bitOffset>
            <bitWidth>1</bitWidth>
          </field>
          <field>
            <name>DATAENDIE</name>
            <bitOffset>8</bitOffset>
            <bitWidth>1</bitWidth>
          </field>
          <field>
            <name>DHOLDIE</name>
            <bitOffset>9</bitOffset>
            <bitWidth>1</bitWidth>
          </field>
          <field>
            <name>DBCKENDIE</name>
            <bitOffset>10</bitOffset>
            <bitWidth>1</bitWidth>
          </field>
          <field>
            <name>DABORTIE</name>
            <bitOffset>11</bitOffset>
            <bitWidth>1</bitWidth>
          </field>
          <field>
            <name>TXFIFOHEIE</name>
            <bitOffset>14</bitOffset>
            <bitWidth>1</bitWidth>
          </field>
          <field>
            <name>RXFIFOHFIE</name>
            <bitOffset>15</bitOffset>
            <bitWidth>1</bitWidth>
          </field>
          <field>
            <name>RXFIFOFIE</name>
            <bitOffset>17</bitOffset>
            <bitWidth>1</bitWidth>
          </field>
          <field>
            <name>TXFIFOEIE</name>
            <bitOffset>18</bitOffset>
            <bitWidth>1</bitWidth>
          </field>
          <field>
            <name>BUSYD0ENDIE</name>
            <bitOffset>21</bitOffset>
            <bitWidth>1</bitWidth>
          </field>
          <field>
            <name>SDIOITIE</name>
            <bitOffset>22</bitOffset>
            <bitWidth>1</bitWidth>
          </field>
          <field>
            <name>ACKFAILIE</name>
            <bitOffset>23</bitOffset>
            <bitWidth>1</bitWidth>
          </field>
          <field>
            <name>ACKTIMEOUTIE</name>
            <bitOffset>24</bitOffset>
            <bitWidth>1</bitWidth>
          </field>
          <field>
            <name>VSWENDIE</name>
            <bitOffset>25</bitOffset>
            <bitWidth>1</bitWidth>
          </field>
          <field>
            <name>CKSTOPIE</name>
            <bitOffset>26</bitOffset>
            <bitWidth>1</bitWidth>
          </field>
          <field>
            <name>IDMABTCIE</name>
            <bitOffset>28</bitOffset>
            <bitWidth>1</bitWidth>
          </field>
        </fields>
      </register>
      <register>
        <name>ACKTIME</name>
        <addressOffset>0x40</addressOffset>
        <size>0x20</size>
      </register>
      <register>
        <name>IDMACTRL</name>
        <addressOffset>0x50</addressOffset>
        <size>0x20</size>
      </register>
      <register>
        <name>IDMABSIZE</name>
        <addressOffset>0x54</addressOffset>
        <size>0x20</size>
      </register>
      <register>
        <name>IDMABASE0</name>
        <addressOffset>0x58</addressOffset>
        <size>0x20</size>
      </register>
      <register>
        <name>IDMABASE1</name>
        <addressOffset>0x5c</addressOffset>
        <size>0x20</size>
      </register>
      <register>
        <name>FIFO</name>
        <addressOffset>0x80</addressOffset>
        <size>0x20</size>
        <fields>
          <field>
            <name>FIFODATA</name>
            <bitOffset>0</bitOffset>
            <bitWidth>32</bitWidth>
          </field>
        </fields>
      </register>
    </peripheral>
    <peripheral>
      <name>FMC_Bank1_R</name>
      <baseAddress>0xa0000000</baseAddress>
      <register>
        <name>BTCR.0</name>
        <addressOffset>0x0</addressOffset>
        <size>0x20</size>
      </register>
      <register>
        <name>BTCR.1</name>
        <addressOffset>0x4</addressOffset>
        <size>0x20</size>
      </register>
      <register>
        <name>BTCR.2</name>
        <addressOffset>0x8</addressOffset>
        <size>0x20</size>
      </register>
      <register>
        <name>BTCR.3</name>
        <addressOffset>0xc</addressOffset>
        <size>0x20</size>
      </register>
      <register>
        <name>BTCR.4</name>
        <addressOffset>0x10</addressOffset>
        <size>0x20</size>
      </register>
      <register>
        <name>BTCR.5</name>
        <addressOffset>0x14</addressOffset>
        <size>0x20</size>
      </register>
      <register>
        <name>BTCR.6</name>
        <addressOffset>0x18</addressOffset>
        <size>0x20</size>
      </register>
      <register>
        <name>BTCR.7</name>
        <addressOffset>0x1c</addressOffset>
        <size>0x20</size>
      </register>
      <register>
        <name>PCSCNTR</name>
        <addressOffset>0x20</addressOffset>
        <size>0x20</size>
        <fields>
          <field>
            <name>CSCOUNT</name>
            <bitOffset>0</bitOffset>
            <bitWidth>16</bitWidth>
          </field>
          <field>
            <name>CNTB1EN</name>
            <bitOffset>16</bitOffset>
            <bitWidth>1</bitWidth>
          </field>
          <field>
            <name>CNTB2EN</name>
            <bitOffset>17</bitOffset>
            <bitWidth>1</bitWidth>
          </field>
          <field>
            <name>CNTB3EN</name>
            <bitOffset>18</bitOffset>
            <bitWidth>1</bitWidth>
          </field>
          <field>
            <name>CNTB4EN</name>
            <bitOffset>19</bitOffset>
            <bitWidth>1</bitWidth>
          </field>
        </fields>
      </register>
    </peripheral>
    <peripheral>
      <name>FMC_Bank3_R</name>
      <baseAddress>0xa0000080</baseAddress>
      <register>
        <name>PCR</name>
        <addressOffset>0x0</addressOffset>
        <size>0x20</size>
        <fields>
          <field>
            <name>PWAITEN</name>
            <bitOffset>1</bitOffset>
            <bitWidth>1</bitWidth>
          </field>
          <field>
            <name>PBKEN</name>
            <bitOffset>2</bitOffset>
            <bitWidth>1</bitWidth>
          </field>
          <field>
            <name>PTYP</name>
            <bitOffset>3</bitOffset>
            <bitWidth>1</bitWidth>
          </field>
          <field>
            <name>PWID</name>
            <bitOffset>4</bitOffset>
            <bitWidth>2</bitWidth>
          </field>
          <field>
            <name>ECCEN</name>
            <bitOffset>6</bitOffset>
            <bitWidth>1</bitWidth>
          </field>
          <field>
            <name>TCLR</name>
            <bitOffset>9</bitOffset>
            <bitWidth>4</bitWidth>
          </field>
          <field>
            <name>TAR</name>
            <bitOffset>13</bitOffset>
            <bitWidth>4</bitWidth>
          </field>
          <field>
            <name>ECCPS</name>
            <bitOffset>17</bitOffset>
            <bitWidth>3</bitWidth>
          </field>
        </fields>
      </register>
      <register>
        <name>SR</name>
        <addressOffset>0x4</addressOffset>
        <size>0x20</size>
        <fields>
          <field>
            <name>IRS</name>
            <bitOffset>0</bitOffset>
            <bitWidth>1</bitWidth>
          </field>
          <field>
            <name>ILS</name>
            <bitOffset>1</bitOffset>
            <bitWidth>1</bitWidth>
          </field>
          <field>
            <name>IFS</name>
            <bitOffset>2</bitOffset>
            <bitWidth>1</bitWidth>
          </field>
          <field>
            <name>IREN</name>
            <bitOffset>3</bitOffset>
            <bitWidth>1</bitWidth>
          </field>
          <field>
            <name>ILEN</name>
            <bitOffset>4</bitOffset>
            <bitWidth>1</bitWidth>
          </field>
          <field>
            <name>IFEN</name>
            <bitOffset>5</bitOffset>
            <bitWidth>1</bitWidth>
          </field>
          <field>
            <name>FEMPT</name>
            <bitOffset>6</bitOffset>
            <bitWidth>1</bitWidth>
          </field>
        </fields>
      </register>
      <register>
        <name>PMEM</name>
        <addressOffset>0x8</addressOffset>
        <size>0x20</size>
        <fields>
          <field>
            <name>MEMSET</name>
            <bitOffset>0</bitOffset>
            <bitWidth>8</bitWidth>
          </field>
          <field>
            <name>MEMWAIT</name>
            <bitOffset>8</bitOffset>
            <bitWidth>8</bitWidth>
          </field>
          <field>
            <name>MEMHOLD</name>
            <bitOffset>16</bitOffset>
            <bitWidth>8</bitWidth>
          </field>
          <field>
            <name>MEMHIZ</name>
            <bitOffset>24</bitOffset>
            <bitWidth>8</bitWidth>
          </field>
        </fields>
      </register>
      <register>
        <name>PATT</name>
        <addressOffset>0xc</addressOffset>
        <size>0x20</size>
        <fields>
          <field>
            <name>ATTSET</name>
            <bitOffset>0</bitOffset>
            <bitWidth>8</bitWidth>
          </field>
          <field>
            <name>ATTWAIT</name>
            <bitOffset>8</bitOffset>
            <bitWidth>8</bitWidth>
          </field>
          <field>
            <name>ATTHOLD</name>
            <bitOffset>16</bitOffset>
            <bitWidth>8</bitWidth>
          </field>
          <field>
            <name>ATTHIZ</name>
            <bitOffset>24</bitOffset>
            <bitWidth>8</bitWidth>
          </field>
        </fields>
      </register>
      <register>
        <name>ECCR</name>
        <addressOffset>0x14</addressOffset>
        <size>0x20</size>
        <fields>
          <field>
            <name>ECC</name>
            <bitOffset>0</bitOffset>
            <bitWidth>32</bitWidth>
          </field>
        </fields>
      </register>
    </peripheral>
    <peripheral>
      <name>FMC_Bank1E_R</name>
      <baseAddress>0xa0000104</baseAddress>
      <register>
        <name>BWTR.0</name>
        <addressOffset>0x0</addressOffset>
        <size>0x20</size>
        <fields>
          <field>
            <name>ADDSET</name>
            <bitOffset>0</bitOffset>
            <bitWidth>4</bitWidth>
          </field>
          <field>
            <name>ADDHLD</name>
            <bitOffset>4</bitOffset>
            <bitWidth>4</bitWidth>
          </field>
          <field>
            <name>DATAST</name>
            <bitOffset>8</bitOffset>
            <bitWidth>8</bitWidth>
          </field>
          <field>
            <name>BUSTURN</name>
            <bitOffset>16</bitOffset>
            <bitWidth>4</bitWidth>
          </field>
          <field>
            <name>ACCMOD</name>
            <bitOffset>28</bitOffset>
            <bitWidth>2</bitWidth>
          </field>
          <field>
            <name>DATAHLD</name>
            <bitOffset>30</bitOffset>
            <bitWidth>2</bitWidth>
          </field>
        </fields>
      </register>
      <register>
        <name>BWTR.1</name>
        <addressOffset>0x4</addressOffset>
        <size>0x20</size>
        <fields>
          <field>
            <name>ADDSET</name>
            <bitOffset>0</bitOffset>
            <bitWidth>4</bitWidth>
          </field>
          <field>
            <name>ADDHLD</name>
            <bitOffset>4</bitOffset>
            <bitWidth>4</bitWidth>
          </field>
          <field>
            <name>DATAST</name>
            <bitOffset>8</bitOffset>
            <bitWidth>8</bitWidth>
          </field>
          <field>
            <name>BUSTURN</name>
            <bitOffset>16</bitOffset>
            <bitWidth>4</bitWidth>
          </field>
          <field>
            <name>ACCMOD</name>
            <bitOffset>28</bitOffset>
            <bitWidth>2</bitWidth>
          </field>
          <field>
            <name>DATAHLD</name>
            <bitOffset>30</bitOffset>
            <bitWidth>2</bitWidth>
          </field>
        </fields>
      </register>
      <register>
        <name>BWTR.2</name>
        <addressOffset>0x8</addressOffset>
        <size>0x20</size>
        <fields>
          <field>
            <name>ADDSET</name>
            <bitOffset>0</bitOffset>
            <bitWidth>4</bitWidth>
          </field>
          <field>
            <name>ADDHLD</name>
            <bitOffset>4</bitOffset>
            <bitWidth>4</bitWidth>
          </field>
          <field>
            <name>DATAST</name>
            <bitOffset>8</bitOffset>
            <bitWidth>8</bitWidth>
          </field>
          <field>
            <name>BUSTURN</name>
            <bitOffset>16</bitOffset>
            <bitWidth>4</bitWidth>
          </field>
          <field>
            <name>ACCMOD</name>
            <bitOffset>28</bitOffset>
            <bitWidth>2</bitWidth>
          </field>
          <field>
            <name>DATAHLD</name>
            <bitOffset>30</bitOffset>
            <bitWidth>2</bitWidth>
          </field>
        </fields>
      </register>
      <register>
        <name>BWTR.3</name>
        <addressOffset>0xc</addressOffset>
        <size>0x20</size>
        <fields>
          <field>
            <name>ADDSET</name>
            <bitOffset>0</bitOffset>
            <bitWidth>4</bitWidth>
          </field>
          <field>
            <name>ADDHLD</name>
            <bitOffset>4</bitOffset>
            <bitWidth>4</bitWidth>
          </field>
          <field>
            <name>DATAST</name>
            <bitOffset>8</bitOffset>
            <bitWidth>8</bitWidth>
          </field>
          <field>
            <name>BUSTURN</name>
            <bitOffset>16</bitOffset>
            <bitWidth>4</bitWidth>
          </field>
          <field>
            <name>ACCMOD</name>
            <bitOffset>28</bitOffset>
            <bitWidth>2</bitWidth>
          </field>
          <field>
            <name>DATAHLD</name>
            <bitOffset>30</bitOffset>
            <bitWidth>2</bitWidth>
          </field>
        </fields>
      </register>
      <register>
        <name>BWTR.4</name>
        <addressOffset>0x10</addressOffset>
        <size>0x20</size>
        <fields>
          <field>
            <name>ADDSET</name>
            <bitOffset>0</bitOffset>
            <bitWidth>4</bitWidth>
          </field>
          <field>
            <name>ADDHLD</name>
            <bitOffset>4</bitOffset>
            <bitWidth>4</bitWidth>
          </field>
          <field>
            <name>DATAST</name>
            <bitOffset>8</bitOffset>
            <bitWidth>8</bitWidth>
          </field>
          <field>
            <name>BUSTURN</name>
            <bitOffset>16</bitOffset>
            <bitWidth>4</bitWidth>
          </field>
          <field>
            <name>ACCMOD</name>
            <bitOffset>28</bitOffset>
            <bitWidth>2</bitWidth>
          </field>
          <field>
            <name>DATAHLD</name>
            <bitOffset>30</bitOffset>
            <bitWidth>2</bitWidth>
          </field>
        </fields>
      </register>
      <register>
        <name>BWTR.5</name>
        <addressOffset>0x14</addressOffset>
        <size>0x20</size>
        <fields>
          <field>
            <name>ADDSET</name>
            <bitOffset>0</bitOffset>
            <bitWidth>4</bitWidth>
          </field>
          <field>
            <name>ADDHLD</name>
            <bitOffset>4</bitOffset>
            <bitWidth>4</bitWidth>
          </field>
          <field>
            <name>DATAST</name>
            <bitOffset>8</bitOffset>
            <bitWidth>8</bitWidth>
          </field>
          <field>
            <name>BUSTURN</name>
            <bitOffset>16</bitOffset>
            <bitWidth>4</bitWidth>
          </field>
          <field>
            <name>ACCMOD</name>
            <bitOffset>28</bitOffset>
            <bitWidth>2</bitWidth>
          </field>
          <field>
            <name>DATAHLD</name>
            <bitOffset>30</bitOffset>
            <bitWidth>2</bitWidth>
          </field>
        </fields>
      </register>
      <register>
        <name>BWTR.6</name>
        <addressOffset>0x18</addressOffset>
        <size>0x20</size>
        <fields>
          <field>
            <name>ADDSET</name>
            <bitOffset>0</bitOffset>
            <bitWidth>4</bitWidth>
          </field>
          <field>
            <name>ADDHLD</name>
            <bitOffset>4</bitOffset>
            <bitWidth>4</bitWidth>
          </field>
          <field>
            <name>DATAST</name>
            <bitOffset>8</bitOffset>
            <bitWidth>8</bitWidth>
          </field>
          <field>
            <name>BUSTURN</name>
            <bitOffset>16</bitOffset>
            <bitWidth>4</bitWidth>
          </field>
          <field>
            <name>ACCMOD</name>
            <bitOffset>28</bitOffset>
            <bitWidth>2</bitWidth>
          </field>
          <field>
            <name>DATAHLD</name>
            <bitOffset>30</bitOffset>
            <bitWidth>2</bitWidth>
          </field>
        </fields>
      </register>
    </peripheral>
    <peripheral>
      <name>OCTOSPI1</name>
      <baseAddress>0xa0001000</baseAddress>
      <register>
        <name>CR</name>
        <addressOffset>0x0</addressOffset>
        <size>0x20</size>
        <fields>
          <field>
            <name>EN</name>
            <bitOffset>0</bitOffset>
            <bitWidth>1</bitWidth>
          </field>
          <field>
            <name>ABORT</name>
            <bitOffset>1</bitOffset>
            <bitWidth>1</bitWidth>
          </field>
          <field>
            <name>DMAEN</name>
            <bitOffset>2</bitOffset>
            <bitWidth>1</bitWidth>
          </field>
          <field>
            <name>TCEN</name>
            <bitOffset>3</bitOffset>
            <bitWidth>1</bitWidth>
          </field>
          <field>
            <name>DQM</name>
            <bitOffset>6</bitOffset>
            <bitWidth>1</bitWidth>
          </field>
          <field>
            <name>FSEL</name>
            <bitOffset>7</bitOffset>
            <bitWidth>1</bitWidth>
          </field>
          <field>
            <name>FTHRES</name>
            <bitOffset>8</bitOffset>
            <bitWidth>5</bitWidth>
          </field>
          <field>
            <name>TEIE</name>
            <bitOffset>16</bitOffset>
            <bitWidth>1</bitWidth>
          </field>
          <field>
            <name>TCIE</name>
            <bitOffset>17</bitOffset>
            <bitWidth>1</bitWidth>
          </field>
          <field>
            <name>FTIE</name>
            <bitOffset>18</bitOffset>
            <bitWidth>1</bitWidth>
          </field>
          <field>
            <name>SMIE</name>
            <bitOffset>19</bitOffset>
            <bitWidth>1</bitWidth>
          </field>
          <field>
            <name>TOIE</name>
            <bitOffset>20</bitOffset>
            <bitWidth>1</bitWidth>
          </field>
          <field>
            <name>APMS</name>
            <bitOffset>22</bitOffset>
            <bitWidth>1</bitWidth>
          </field>
          <field>
            <name>PMM</name>
            <bitOffset>23</bitOffset>
            <bitWidth>1</bitWidth>
          </field>
          <field>
            <name>FMODE</name>
            <bitOffset>28</bitOffset>
            <bitWidth>2</bitWidth>
          </field>
        </fields>
      </register>
      <register>
        <name>DCR1</name>
        <addressOffset>0x8</addressOffset>
        <size>0x20</size>
        <fields>
          <field>
            <name>CKMODE</name>
            <bitOffset>0</bitOffset>
            <bitWidth>1</bitWidth>
          </field>
          <field>
            <name>FRCK</name>
            <bitOffset>1</bitOffset>
            <bitWidth>1</bitWidth>
          </field>
          <field>
            <name>DLYBYP</name>
            <bitOffset>3</bitOffset>
            <bitWidth>1</bitWidth>
          </field>
          <field>
            <name>CSHT</name>
            <bitOffset>8</bitOffset>
            <bitWidth>6</bitWidth>
          </field>
          <field>
            <name>DEVSIZE</name>
            <bitOffset>16</bitOffset>
            <bitWidth>5</bitWidth>
          </field>
          <field>
            <name>MTYP</name>
            <bitOffset>24</bitOffset>
            <bitWidth>3</bitWidth>
          </field>
        </fields>
      </register>
      <register>
        <name>DCR2</name>
        <addressOffset>0xc</addressOffset>
        <size>0x20</size>
        <fields>
          <field>
            <name>PRESCALER</name>
            <bitOffset>0</bitOffset>
            <bitWidth>8</bitWidth>
          </field>
        </fields>
      </register>
      <register>
        <name>DCR3</name>
        <addressOffset>0x10</addressOffset>
        <size>0x20</size>
        <fields>
          <field>
            <name>MAXTRAN</name>
            <bitOffset>0</bitOffset>
            <bitWidth>8</bitWidth>
          </field>
          <field>
            <name>CSBOUND</name>
            <bitOffset>16</bitOffset>
            <bitWidth>5</bitWidth>
          </field>
        </fields>
      </register>
      <register>
        <name>DCR4</name>
        <addressOffset>0x14</addressOffset>
        <size>0x20</size>
        <fields>
          <field>
            <name>REFRESH</name>
            <bitOffset>0</bitOffset>
            <bitWidth>32</bitWidth>
          </field>
        </fields>
      </register>
      <register>
        <name>SR</name>
        <addressOffset>0x20</addressOffset>
        <size>0x20</size>
        <fields>
          <field>
            <name>TEF</name>
            <bitOffset>0</bitOffset>
            <bitWidth>1</bitWidth>
          </field>
          <field>
            <name>TCF</name>
            <bitOffset>1</bitOffset>
            <bitWidth>1</bitWidth>
          </field>
          <field>
            <name>FTF</name>
            <bitOffset>2</bitOffset>
            <bitWidth>1</bitWidth>
          </field>
          <field>
            <name>SMF</name>
            <bitOffset>3</bitOffset>
            <bitWidth>1</bitWidth>
          </field>
          <field>
            <name>TOF</name>
            <bitOffset>4</bitOffset>
            <bitWidth>1</bitWidth>
          </field>
          <field>
            <name>BUSY</name>
            <bitOffset>5</bitOffset>
            <bitWidth>1</bitWidth>
          </field>
          <field>
            <name>FLEVEL</name>
            <bitOffset>8</bitOffset>
            <bitWidth>6</bitWidth>
          </field>
        </fields>
      </register>
      <register>
        <name>FCR</name>
        <addressOffset>0x24</addressOffset>
        <size>0x20</size>
        <fields>
          <field>
            <name>CTEF</name>
            <bitOffset>0</bitOffset>
            <bitWidth>1</bitWidth>
          </field>
          <field>
            <name>CTCF</name>
            <bitOffset>1</bitOffset>
            <bitWidth>1</bitWidth>
          </field>
          <field>
            <name>CSMF</name>
            <bitOffset>3</bitOffset>
            <bitWidth>1</bitWidth>
          </field>
          <field>
            <name>TOF</name>
            <bitOffset>4</bitOffset>
            <bitWidth>1</bitWidth>
          </field>
        </fields>
      </register>
      <register>
        <name>DLR</name>
        <addressOffset>0x40</addressOffset>
        <size>0x20</size>
        <fields>
          <field>
            <name>DL</name>
            <bitOffset>0</bitOffset>
            <bitWidth>32</bitWidth>
          </field>
        </fields>
      </register>
      <register>
        <name>AR</name>
        <addressOffset>0x48</addressOffset>
        <size>0x20</size>
        <fields>
          <field>
            <name>ADDRESS</name>
            <bitOffset>0</bitOffset>
            <bitWidth>32</bitWidth>
          </field>
        </fields>
      </register>
      <register>
        <name>DR</name>
        <addressOffset>0x50</addressOffset>
        <size>0x20</size>
        <fields>
          <field>
            <name>DATA</name>
            <bitOffset>0</bitOffset>
            <bitWidth>32</bitWidth>
          </field>
        </fields>
      </register>
      <register>
        <name>PSMKR</name>
        <addressOffset>0x80</addressOffset>
        <size>0x20</size>
        <fields>
          <field>
            <name>MASK</name>
            <bitOffset>0</bitOffset>
            <bitWidth>32</bitWidth>
          </field>
        </fields>
      </register>
      <register>
        <name>PSMAR</name>
        <addressOffset>0x88</addressOffset>
        <size>0x20</size>
        <fields>
          <field>
            <name>MATCH</name>
            <bitOffset>0</bitOffset>
            <bitWidth>32</bitWidth>
          </field>
        </fields>
      </register>
      <register>
        <name>PIR</name>
        <addressOffset>0x90</addressOffset>
        <size>0x20</size>
        <fields>
          <field>
            <name>INTERVAL</name>
            <bitOffset>0</bitOffset>
            <bitWidth>16</bitWidth>
          </field>
        </fields>
      </register>
      <register>
        <name>CCR</name>
        <addressOffset>0x100</addressOffset>
        <size>0x20</size>
        <fields>
          <field>
            <name>IMODE</name>
            <bitOffset>0</bitOffset>
            <bitWidth>3</bitWidth>
          </field>
          <field>
            <name>IDTR</name>
            <bitOffset>3</bitOffset>
            <bitWidth>1</bitWidth>
          </field>
          <field>
            <name>ISIZE</name>
            <bitOffset>4</bitOffset>
            <bitWidth>2</bitWidth>
          </field>
          <field>
            <name>ADMODE</name>
            <bitOffset>8</bitOffset>
            <bitWidth>3</bitWidth>
          </field>
          <field>
            <name>ADDTR</name>
            <bitOffset>11</bitOffset>
            <bitWidth>1</bitWidth>
          </field>
          <field>
            <name>ADSIZE</name>
            <bitOffset>12</bitOffset>
            <bitWidth>2</bitWidth>
          </field>
          <field>
            <name>ABMODE</name>
            <bitOffset>16</bitOffset>
            <bitWidth>3</bitWidth>
          </field>
          <field>
            <name>ABDTR</name>
            <bitOffset>19</bitOffset>
            <bitWidth>1</bitWidth>
          </field>
          <field>
            <name>ABSIZE</name>
            <bitOffset>20</bitOffset>
            <bitWidth>2</bitWidth>
          </field>
          <field>
            <name>DMODE</name>
            <bitOffset>24</bitOffset>
            <bitWidth>3</bitWidth>
          </field>
          <field>
            <name>DDTR</name>
            <bitOffset>27</bitOffset>
            <bitWidth>1</bitWidth>
          </field>
          <field>
            <name>DQSE</name>
            <bitOffset>29</bitOffset>
            <bitWidth>1</bitWidth>
          </field>
          <field>
            <name>SIOO</name>
            <bitOffset>31</bitOffset>
            <bitWidth>1</bitWidth>
          </field>
        </fields>
      </register>
      <register>
        <name>TCR</name>
        <addressOffset>0x108</addressOffset>
        <size>0x20</size>
        <fields>
          <field>
            <name>DCYC</name>
            <bitOffset>0</bitOffset>
            <bitWidth>5</bitWidth>
          </field>
          <field>
            <name>DHQC</name>
            <bitOffset>28</bitOffset>
            <bitWidth>1</bitWidth>
          </field>
          <field>
            <name>SSHIFT</name>
            <bitOffset>30</bitOffset>
            <bitWidth>1</bitWidth>
          </field>
        </fields>
      </register>
      <register>
        <name>IR</name>
        <addressOffset>0x110</addressOffset>
        <size>0x20</size>
        <fields>
          <field>
            <name>INSTRUCTION</name>
            <bitOffset>0</bitOffset>
            <bitWidth>32</bitWidth>
          </field>
        </fields>
      </register>
      <register>
        <name>ABR</name>
        <addressOffset>0x120</addressOffset>
        <size>0x20</size>
        <fields>
          <field>
            <name>ALTERNATE</name>
            <bitOffset>0</bitOffset>
            <bitWidth>32</bitWidth>
          </field>
        </fields>
      </register>
      <register>
        <name>LPTR</name>
        <addressOffset>0x130</addressOffset>
        <size>0x20</size>
        <fields>
          <field>
            <name>TIMEOUT</name>
            <bitOffset>0</bitOffset>
            <bitWidth>16</bitWidth>
          </field>
        </fields>
      </register>
      <register>
        <name>WCCR</name>
        <addressOffset>0x180</addressOffset>
        <size>0x20</size>
        <fields>
          <field>
            <name>IMODE</name>
            <bitOffset>0</bitOffset>
            <bitWidth>3</bitWidth>
          </field>
          <field>
            <name>IDTR</name>
            <bitOffset>3</bitOffset>
            <bitWidth>1</bitWidth>
          </field>
          <field>
            <name>ISIZE</name>
            <bitOffset>4</bitOffset>
            <bitWidth>2</bitWidth>
          </field>
          <field>
            <name>ADMODE</name>
            <bitOffset>8</bitOffset>
            <bitWidth>3</bitWidth>
          </field>
          <field>
            <name>ADDTR</name>
            <bitOffset>11</bitOffset>
            <bitWidth>1</bitWidth>
          </field>
          <field>
            <name>ADSIZE</name>
            <bitOffset>12</bitOffset>
            <bitWidth>2</bitWidth>
          </field>
          <field>
            <name>ABMODE</name>
            <bitOffset>16</bitOffset>
            <bitWidth>3</bitWidth>
          </field>
          <field>
            <name>ABDTR</name>
            <bitOffset>19</bitOffset>
            <bitWidth>1</bitWidth>
          </field>
          <field>
            <name>ABSIZE</name>
            <bitOffset>20</bitOffset>
            <bitWidth>2</bitWidth>
          </field>
          <field>
            <name>DMODE</name>
            <bitOffset>24</bitOffset>
            <bitWidth>3</bitWidth>
          </field>
          <field>
            <name>DDTR</name>
            <bitOffset>27</bitOffset>
            <bitWidth>1</bitWidth>
          </field>
          <field>
            <name>DQSE</name>
            <bitOffset>29</bitOffset>
            <bitWidth>1</bitWidth>
          </field>
        </fields>
      </register>
      <register>
        <name>WTCR</name>
        <addressOffset>0x188</addressOffset>
        <size>0x20</size>
        <fields>
          <field>
            <name>DCYC</name>
            <bitOffset>0</bitOffset>
            <bitWidth>5</bitWidth>
          </field>
        </fields>
      </register>
      <register>
        <name>WIR</name>
        <addressOffset>0x190</addressOffset>
        <size>0x20</size>
        <fields>
          <field>
            <name>INSTRUCTION</name>
            <bitOffset>0</bitOffset>
            <bitWidth>32</bitWidth>
          </field>
        </fields>
      </register>
      <register>
        <name>WABR</name>
        <addressOffset>0x1a0</addressOffset>
        <size>0x20</size>
        <fields>
          <field>
            <name>ALTERNATE</name>
            <bitOffset>0</bitOffset>
            <bitWidth>32</bitWidth>
          </field>
        </fields>
      </register>
      <register>
        <name>HLCR</name>
        <addressOffset>0x200</addressOffset>
        <size>0x20</size>
        <fields>
          <field>
            <name>LM</name>
            <bitOffset>0</bitOffset>
            <bitWidth>1</bitWidth>
          </field>
          <field>
            <name>WZL</name>
            <bitOffset>1</bitOffset>
            <bitWidth>1</bitWidth>
          </field>
          <field>
            <name>TACC</name>
            <bitOffset>8</bitOffset>
            <bitWidth>8</bitWidth>
          </field>
          <field>
            <name>TRWR</name>
            <bitOffset>16</bitOffset>
            <bitWidth>8</bitWidth>
          </field>
        </fields>
      </register>
    </peripheral>
    <peripheral>
      <name>OCTOSPI2</name>
      <baseAddress>0xa0001400</baseAddress>
      <register>
        <name>CR</name>
        <addressOffset>0x0</addressOffset>
        <size>0x20</size>
        <fields>
          <field>
            <name>EN</name>
            <bitOffset>0</bitOffset>
            <bitWidth>1</bitWidth>
          </field>
          <field>
            <name>ABORT</name>
            <bitOffset>1</bitOffset>
            <bitWidth>1</bitWidth>
          </field>
          <field>
            <name>DMAEN</name>
            <bitOffset>2</bitOffset>
            <bitWidth>1</bitWidth>
          </field>
          <field>
            <name>TCEN</name>
            <bitOffset>3</bitOffset>
            <bitWidth>1</bitWidth>
          </field>
          <field>
            <name>DQM</name>
            <bitOffset>6</bitOffset>
            <bitWidth>1</bitWidth>
          </field>
          <field>
            <name>FSEL</name>
            <bitOffset>7</bitOffset>
            <bitWidth>1</bitWidth>
          </field>
          <field>
            <name>FTHRES</name>
            <bitOffset>8</bitOffset>
            <bitWidth>5</bitWidth>
          </field>
          <field>
            <name>TEIE</name>
            <bitOffset>16</bitOffset>
            <bitWidth>1</bitWidth>
          </field>
          <field>
            <name>TCIE</name>
            <bitOffset>17</bitOffset>
            <bitWidth>1</bitWidth>
          </field>
          <field>
            <name>FTIE</name>
            <bitOffset>18</bitOffset>
            <bitWidth>1</bitWidth>
          </field>
          <field>
            <name>SMIE</name>
            <bitOffset>19</bitOffset>
            <bitWidth>1</bitWidth>
          </field>
          <field>
            <name>TOIE</name>
            <bitOffset>20</bitOffset>
            <bitWidth>1</bitWidth>
          </field>
          <field>
            <name>APMS</name>
            <bitOffset>22</bitOffset>
            <bitWidth>1</bitWidth>
          </field>
          <field>
            <name>PMM</name>
            <bitOffset>23</bitOffset>
            <bitWidth>1</bitWidth>
          </field>
          <field>
            <name>FMODE</name>
            <bitOffset>28</bitOffset>
            <bitWidth>2</bitWidth>
          </field>
        </fields>
      </register>
      <register>
        <name>DCR1</name>
        <addressOffset>0x8</addressOffset>
        <size>0x20</size>
        <fields>
          <field>
            <name>CKMODE</name>
            <bitOffset>0</bitOffset>
            <bitWidth>1</bitWidth>
          </field>
          <field>
            <name>FRCK</name>
            <bitOffset>1</bitOffset>
            <bitWidth>1</bitWidth>
          </field>
          <field>
            <name>DLYBYP</name>
            <bitOffset>3</bitOffset>
            <bitWidth>1</bitWidth>
          </field>
          <field>
            <name>CSHT</name>
            <bitOffset>8</bitOffset>
            <bitWidth>6</bitWidth>
          </field>
          <field>
            <name>DEVSIZE</name>
            <bitOffset>16</bitOffset>
            <bitWidth>5</bitWidth>
          </field>
          <field>
            <name>MTYP</name>
            <bitOffset>24</bitOffset>
            <bitWidth>3</bitWidth>
          </field>
        </fields>
      </register>
      <register>
        <name>DCR2</name>
        <addressOffset>0xc</addressOffset>
        <size>0x20</size>
        <fields>
          <field>
            <name>PRESCALER</name>
            <bitOffset>0</bitOffset>
            <bitWidth>8</bitWidth>
          </field>
        </fields>
      </register>
      <register>
        <name>DCR3</name>
        <addressOffset>0x10</addressOffset>
        <size>0x20</size>
        <fields>
          <field>
            <name>MAXTRAN</name>
            <bitOffset>0</bitOffset>
            <bitWidth>8</bitWidth>
          </field>
          <field>
            <name>CSBOUND</name>
            <bitOffset>16</bitOffset>
            <bitWidth>5</bitWidth>
          </field>
        </fields>
      </register>
      <register>
        <name>DCR4</name>
        <addressOffset>0x14</addressOffset>
        <size>0x20</size>
        <fields>
          <field>
            <name>REFRESH</name>
            <bitOffset>0</bitOffset>
            <bitWidth>32</bitWidth>
          </field>
        </fields>
      </register>
      <register>
        <name>SR</name>
        <addressOffset>0x20</addressOffset>
        <size>0x20</size>
        <fields>
          <field>
            <name>TEF</name>
            <bitOffset>0</bitOffset>
            <bitWidth>1</bitWidth>
          </field>
          <field>
            <name>TCF</name>
            <bitOffset>1</bitOffset>
            <bitWidth>1</bitWidth>
          </field>
          <field>
            <name>FTF</name>
            <bitOffset>2</bitOffset>
            <bitWidth>1</bitWidth>
          </field>
          <field>
            <name>SMF</name>
            <bitOffset>3</bitOffset>
            <bitWidth>1</bitWidth>
          </field>
          <field>
            <name>TOF</name>
            <bitOffset>4</bitOffset>
            <bitWidth>1</bitWidth>
          </field>
          <field>
            <name>BUSY</name>
            <bitOffset>5</bitOffset>
            <bitWidth>1</bitWidth>
          </field>
          <field>
            <name>FLEVEL</name>
            <bitOffset>8</bitOffset>
            <bitWidth>6</bitWidth>
          </field>
        </fields>
      </register>
      <register>
        <name>FCR</name>
        <addressOffset>0x24</addressOffset>
        <size>0x20</size>
        <fields>
          <field>
            <name>CTEF</name>
            <bitOffset>0</bitOffset>
            <bitWidth>1</bitWidth>
          </field>
          <field>
            <name>CTCF</name>
            <bitOffset>1</bitOffset>
            <bitWidth>1</bitWidth>
          </field>
          <field>
            <name>CSMF</name>
            <bitOffset>3</bitOffset>
            <bitWidth>1</bitWidth>
          </field>
          <field>
            <name>TOF</name>
            <bitOffset>4</bitOffset>
            <bitWidth>1</bitWidth>
          </field>
        </fields>
      </register>
      <register>
        <name>DLR</name>
        <addressOffset>0x40</addressOffset>
        <size>0x20</size>
        <fields>
          <field>
            <name>DL</name>
            <bitOffset>0</bitOffset>
            <bitWidth>32</bitWidth>
          </field>
        </fields>
      </register>
      <register>
        <name>AR</name>
        <addressOffset>0x48</addressOffset>
        <size>0x20</size>
        <fields>
          <field>
            <name>ADDRESS</name>
            <bitOffset>0</bitOffset>
            <bitWidth>32</bitWidth>
          </field>
        </fields>
      </register>
      <register>
        <name>DR</name>
        <addressOffset>0x50</addressOffset>
        <size>0x20</size>
        <fields>
          <field>
            <name>DATA</name>
            <bitOffset>0</bitOffset>
            <bitWidth>32</bitWidth>
          </field>
        </fields>
      </register>
      <register>
        <name>PSMKR</name>
        <addressOffset>0x80</addressOffset>
        <size>0x20</size>
        <fields>
          <field>
            <name>MASK</name>
            <bitOffset>0</bitOffset>
            <bitWidth>32</bitWidth>
          </field>
        </fields>
      </register>
      <register>
        <name>PSMAR</name>
        <addressOffset>0x88</addressOffset>
        <size>0x20</size>
        <fields>
          <field>
            <name>MATCH</name>
            <bitOffset>0</bitOffset>
            <bitWidth>32</bitWidth>
          </field>
        </fields>
      </register>
      <register>
        <name>PIR</name>
        <addressOffset>0x90</addressOffset>
        <size>0x20</size>
        <fields>
          <field>
            <name>INTERVAL</name>
            <bitOffset>0</bitOffset>
            <bitWidth>16</bitWidth>
          </field>
        </fields>
      </register>
      <register>
        <name>CCR</name>
        <addressOffset>0x100</addressOffset>
        <size>0x20</size>
        <fields>
          <field>
            <name>IMODE</name>
            <bitOffset>0</bitOffset>
            <bitWidth>3</bitWidth>
          </field>
          <field>
            <name>IDTR</name>
            <bitOffset>3</bitOffset>
            <bitWidth>1</bitWidth>
          </field>
          <field>
            <name>ISIZE</name>
            <bitOffset>4</bitOffset>
            <bitWidth>2</bitWidth>
          </field>
          <field>
            <name>ADMODE</name>
            <bitOffset>8</bitOffset>
            <bitWidth>3</bitWidth>
          </field>
          <field>
            <name>ADDTR</name>
            <bitOffset>11</bitOffset>
            <bitWidth>1</bitWidth>
          </field>
          <field>
            <name>ADSIZE</name>
            <bitOffset>12</bitOffset>
            <bitWidth>2</bitWidth>
          </field>
          <field>
            <name>ABMODE</name>
            <bitOffset>16</bitOffset>
            <bitWidth>3</bitWidth>
          </field>
          <field>
            <name>ABDTR</name>
            <bitOffset>19</bitOffset>
            <bitWidth>1</bitWidth>
          </field>
          <field>
            <name>ABSIZE</name>
            <bitOffset>20</bitOffset>
            <bitWidth>2</bitWidth>
          </field>
          <field>
            <name>DMODE</name>
            <bitOffset>24</bitOffset>
            <bitWidth>3</bitWidth>
          </field>
          <field>
            <name>DDTR</name>
            <bitOffset>27</bitOffset>
            <bitWidth>1</bitWidth>
          </field>
          <field>
            <name>DQSE</name>
            <bitOffset>29</bitOffset>
            <bitWidth>1</bitWidth>
          </field>
          <field>
            <name>SIOO</name>
            <bitOffset>31</bitOffset>
            <bitWidth>1</bitWidth>
          </field>
        </fields>
      </register>
      <register>
        <name>TCR</name>
        <addressOffset>0x108</addressOffset>
        <size>0x20</size>
        <fields>
          <field>
            <name>DCYC</name>
            <bitOffset>0</bitOffset>
            <bitWidth>5</bitWidth>
          </field>
          <field>
            <name>DHQC</name>
            <bitOffset>28</bitOffset>
            <bitWidth>1</bitWidth>
          </field>
          <field>
            <name>SSHIFT</name>
            <bitOffset>30</bitOffset>
            <bitWidth>1</bitWidth>
          </field>
        </fields>
      </register>
      <register>
        <name>IR</name>
        <addressOffset>0x110</addressOffset>
        <size>0x20</size>
        <fields>
          <field>
            <name>INSTRUCTION</name>
            <bitOffset>0</bitOffset>
            <bitWidth>32</bitWidth>
          </field>
        </fields>
      </register>
      <register>
        <name>ABR</name>
        <addressOffset>0x120</addressOffset>
        <size>0x20</size>
        <fields>
          <field>
            <name>ALTERNATE</name>
            <bitOffset>0</bitOffset>
            <bitWidth>32</bitWidth>
          </field>
        </fields>
      </register>
      <register>
        <name>LPTR</name>
        <addressOffset>0x130</addressOffset>
        <size>0x20</size>
        <fields>
          <field>
            <name>TIMEOUT</name>
            <bitOffset>0</bitOffset>
            <bitWidth>16</bitWidth>
          </field>
        </fields>
      </register>
      <register>
        <name>WCCR</name>
        <addressOffset>0x180</addressOffset>
        <size>0x20</size>
        <fields>
          <field>
            <name>IMODE</name>
            <bitOffset>0</bitOffset>
            <bitWidth>3</bitWidth>
          </field>
          <field>
            <name>IDTR</name>
            <bitOffset>3</bitOffset>
            <bitWidth>1</bitWidth>
          </field>
          <field>
            <name>ISIZE</name>
            <bitOffset>4</bitOffset>
            <bitWidth>2</bitWidth>
          </field>
          <field>
            <name>ADMODE</name>
            <bitOffset>8</bitOffset>
            <bitWidth>3</bitWidth>
          </field>
          <field>
            <name>ADDTR</name>
            <bitOffset>11</bitOffset>
            <bitWidth>1</bitWidth>
          </field>
          <field>
            <name>ADSIZE</name>
            <bitOffset>12</bitOffset>
            <bitWidth>2</bitWidth>
          </field>
          <field>
            <name>ABMODE</name>
            <bitOffset>16</bitOffset>
            <bitWidth>3</bitWidth>
          </field>
          <field>
            <name>ABDTR</name>
            <bitOffset>19</bitOffset>
            <bitWidth>1</bitWidth>
          </field>
          <field>
            <name>ABSIZE</name>
            <bitOffset>20</bitOffset>
            <bitWidth>2</bitWidth>
          </field>
          <field>
            <name>DMODE</name>
            <bitOffset>24</bitOffset>
            <bitWidth>3</bitWidth>
          </field>
          <field>
            <name>DDTR</name>
            <bitOffset>27</bitOffset>
            <bitWidth>1</bitWidth>
          </field>
          <field>
            <name>DQSE</name>
            <bitOffset>29</bitOffset>
            <bitWidth>1</bitWidth>
          </field>
        </fields>
      </register>
      <register>
        <name>WTCR</name>
        <addressOffset>0x188</addressOffset>
        <size>0x20</size>
        <fields>
          <field>
            <name>DCYC</name>
            <bitOffset>0</bitOffset>
            <bitWidth>5</bitWidth>
          </field>
        </fields>
      </register>
      <register>
        <name>WIR</name>
        <addressOffset>0x190</addressOffset>
        <size>0x20</size>
        <fields>
          <field>
            <name>INSTRUCTION</name>
            <bitOffset>0</bitOffset>
            <bitWidth>32</bitWidth>
          </field>
        </fields>
      </register>
      <register>
        <name>WABR</name>
        <addressOffset>0x1a0</addressOffset>
        <size>0x20</size>
        <fields>
          <field>
            <name>ALTERNATE</name>
            <bitOffset>0</bitOffset>
            <bitWidth>32</bitWidth>
          </field>
        </fields>
      </register>
      <register>
        <name>HLCR</name>
        <addressOffset>0x200</addressOffset>
        <size>0x20</size>
        <fields>
          <field>
            <name>LM</name>
            <bitOffset>0</bitOffset>
            <bitWidth>1</bitWidth>
          </field>
          <field>
            <name>WZL</name>
            <bitOffset>1</bitOffset>
            <bitWidth>1</bitWidth>
          </field>
          <field>
            <name>TACC</name>
            <bitOffset>8</bitOffset>
            <bitWidth>8</bitWidth>
          </field>
          <field>
            <name>TRWR</name>
            <bitOffset>16</bitOffset>
            <bitWidth>8</bitWidth>
          </field>
        </fields>
      </register>
    </peripheral>
    <peripheral>
      <name>DBGMCU</name>
      <baseAddress>0xe0042000</baseAddress>
      <register>
        <name>IDCODE</name>
        <addressOffset>0x0</addressOffset>
        <size>0x20</size>
        <fields>
          <field>
            <name>DEV_ID</name>
            <bitOffset>0</bitOffset>
            <bitWidth>12</bitWidth>
          </field>
          <field>
            <name>REV_ID</name>
            <bitOffset>16</bitOffset>
            <bitWidth>16</bitWidth>
          </field>
        </fields>
      </register>
      <register>
        <name>CR</name>
        <addressOffset>0x4</addressOffset>
        <size>0x20</size>
        <fields>
          <field>
            <name>DBG_SLEEP</name>
            <bitOffset>0</bitOffset>
            <bitWidth>1</bitWidth>
          </field>
          <field>
            <name>DBG_STOP</name>
            <bitOffset>1</bitOffset>
            <bitWidth>1</bitWidth>
          </field>
          <field>
            <name>DBG_STANDBY</name>
            <bitOffset>2</bitOffset>
            <bitWidth>1</bitWidth>
          </field>
          <field>
            <name>TRACE_IOEN</name>
            <bitOffset>5</bitOffset>
            <bitWidth>1</bitWidth>
          </field>
          <field>
            <name>TRACE_MODE</name>
            <bitOffset>6</bitOffset>
            <bitWidth>2</bitWidth>
          </field>
        </fields>
      </register>
      <register>
        <name>APB1FZR1</name>
        <addressOffset>0x8</addressOffset>
        <size>0x20</size>
        <fields>
          <field>
            <name>DBG_TIM2_STOP</name>
            <bitOffset>0</bitOffset>
            <bitWidth>1</bitWidth>
          </field>
          <field>
            <name>DBG_TIM3_STOP</name>
            <bitOffset>1</bitOffset>
            <bitWidth>1</bitWidth>
          </field>
          <field>
            <name>DBG_TIM4_STOP</name>
            <bitOffset>2</bitOffset>
            <bitWidth>1</bitWidth>
          </field>
          <field>
            <name>DBG_TIM5_STOP</name>
            <bitOffset>3</bitOffset>
            <bitWidth>1</bitWidth>
          </field>
          <field>
            <name>DBG_TIM6_STOP</name>
            <bitOffset>4</bitOffset>
            <bitWidth>1</bitWidth>
          </field>
          <field>
            <name>DBG_TIM7_STOP</name>
            <bitOffset>5</bitOffset>
            <bitWidth>1</bitWidth>
          </field>
          <field>
            <name>DBG_RTC_STOP</name>
            <bitOffset>10</bitOffset>
            <bitWidth>1</bitWidth>
          </field>
          <field>
            <name>DBG_WWDG_STOP</name>
            <bitOffset>11</bitOffset>
            <bitWidth>1</bitWidth>
          </field>
          <field>
            <name>DBG_IWDG_STOP</name>
            <bitOffset>12</bitOffset>
            <bitWidth>1</bitWidth>
          </field>
          <field>
            <name>DBG_I2C1_STOP</name>
            <bitOffset>21</bitOffset>
            <bitWidth>1</bitWidth>
          </field>
          <field>
            <name>DBG_I2C2_STOP</name>
            <bitOffset>22</bitOffset>
            <bitWidth>1</bitWidth>
          </field>
          <field>
            <name>DBG_I2C3_STOP</name>
            <bitOffset>23</bitOffset>
            <bitWidth>1</bitWidth>
          </field>
          <field>
            <name>DBG_CAN_STOP</name>
            <bitOffset>25</bitOffset>
            <bitWidth>1</bitWidth>
          </field>
          <field>
            <name>DBG_LPTIM1_STOP</name>
            <bitOffset>31</bitOffset>
            <bitWidth>1</bitWidth>
          </field>
        </fields>
      </register>
      <register>
        <name>APB1FZR2</name>
        <addressOffset>0xc</addressOffset>
        <size>0x20</size>
        <fields>
          <field>
            <name>DBG_I2C4_STOP</name>
            <bitOffset>1</bitOffset>
            <bitWidth>1</bitWidth>
          </field>
          <field>
            <name>DBG_LPTIM2_STOP</name>
            <bitOffset>5</bitOffset>
            <bitWidth>1</bitWidth>
          </field>
        </fields>
      </register>
      <register>
        <name>APB2FZ</name>
        <addressOffset>0x10</addressOffset>
        <size>0x20</size>
        <fields>
          <field>
            <name>DBG_TIM1_STOP</name>
            <bitOffset>11</bitOffset>
            <bitWidth>1</bitWidth>
          </field>
          <field>
            <name>DBG_TIM8_STOP</name>
            <bitOffset>13</bitOffset>
            <bitWidth>1</bitWidth>
          </field>
          <field>
            <name>DBG_TIM15_STOP</name>
            <bitOffset>16</bitOffset>
            <bitWidth>1</bitWidth>
          </field>
          <field>
            <name>DBG_TIM16_STOP</name>
            <bitOffset>17</bitOffset>
            <bitWidth>1</bitWidth>
          </field>
          <field>
            <name>DBG_TIM17_STOP</name>
            <bitOffset>18</bitOffset>
            <bitWidth>1</bitWidth>
          </field>
        </fields>
      </register>
    </peripheral>
  </peripherals>
</device>
